VERSION 5.8 ;
BUSBITCHARS "[]" ;
DIVIDERCHAR "/" ;
UNITS
    DATABASE MICRONS 1000 ;
END UNITS

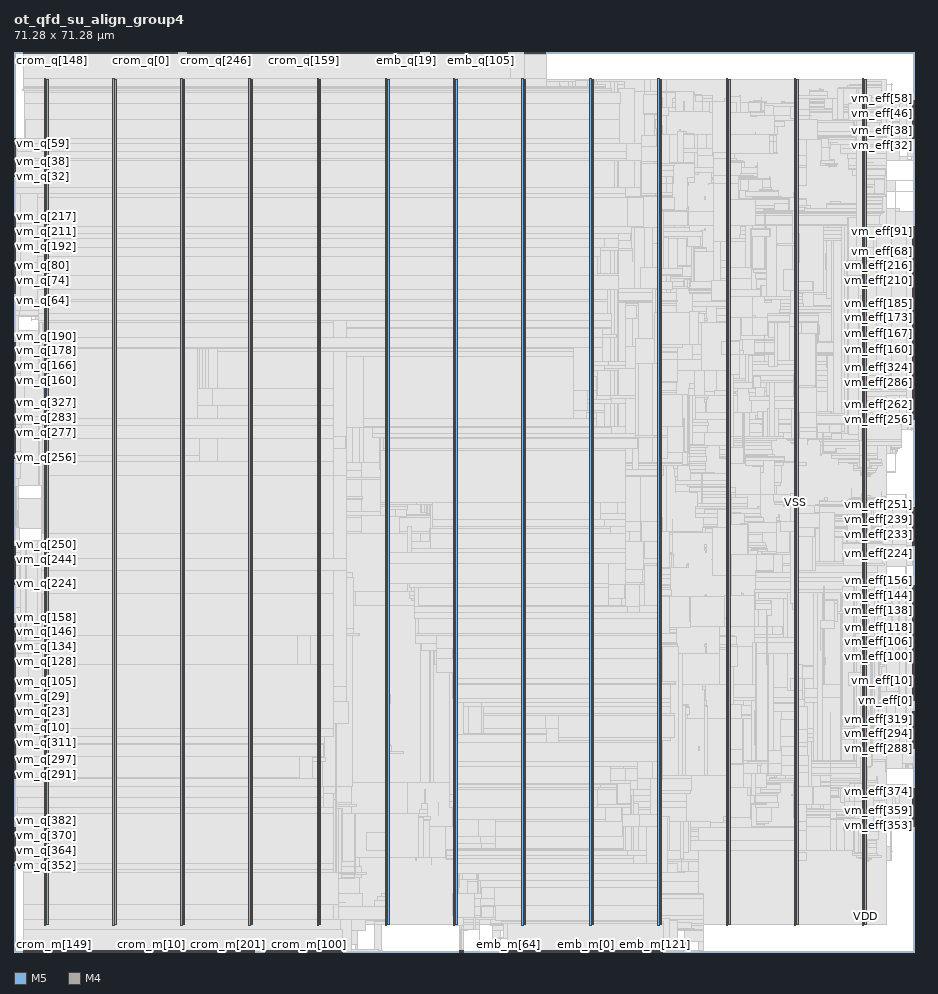
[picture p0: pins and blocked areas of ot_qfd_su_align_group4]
MACRO ot_qfd_su_align_group4
  FOREIGN ot_qfd_su_align_group4 0 0 ;
  CLASS BLOCK ;
  SIZE 71.28 BY 71.28 ;
  PIN clk
    DIRECTION INPUT ;
    USE SIGNAL ;
    PORT
      LAYER M5 ;
        RECT  9.936 71.196 9.96 71.28 ;
    END
  END clk
  PIN crom_m[0]
    DIRECTION OUTPUT ;
    USE SIGNAL ;
    PORT
      LAYER M5 ;
        RECT  9.936 0 9.96 0.084 ;
    END
  END crom_m[0]
  PIN crom_m[100]
    DIRECTION OUTPUT ;
    USE SIGNAL ;
    PORT
      LAYER M5 ;
        RECT  23.376 0 23.4 0.084 ;
    END
  END crom_m[100]
  PIN crom_m[101]
    DIRECTION OUTPUT ;
    USE SIGNAL ;
    PORT
      LAYER M5 ;
        RECT  23.472 0 23.496 0.084 ;
    END
  END crom_m[101]
  PIN crom_m[102]
    DIRECTION OUTPUT ;
    USE SIGNAL ;
    PORT
      LAYER M5 ;
        RECT  23.568 0 23.592 0.084 ;
    END
  END crom_m[102]
  PIN crom_m[103]
    DIRECTION OUTPUT ;
    USE SIGNAL ;
    PORT
      LAYER M5 ;
        RECT  23.664 0 23.688 0.084 ;
    END
  END crom_m[103]
  PIN crom_m[104]
    DIRECTION OUTPUT ;
    USE SIGNAL ;
    PORT
      LAYER M5 ;
        RECT  23.76 0 23.784 0.084 ;
    END
  END crom_m[104]
  PIN crom_m[105]
    DIRECTION OUTPUT ;
    USE SIGNAL ;
    PORT
      LAYER M5 ;
        RECT  23.856 0 23.88 0.084 ;
    END
  END crom_m[105]
  PIN crom_m[106]
    DIRECTION OUTPUT ;
    USE SIGNAL ;
    PORT
      LAYER M5 ;
        RECT  23.952 0 23.976 0.084 ;
    END
  END crom_m[106]
  PIN crom_m[107]
    DIRECTION OUTPUT ;
    USE SIGNAL ;
    PORT
      LAYER M5 ;
        RECT  24.048 0 24.072 0.084 ;
    END
  END crom_m[107]
  PIN crom_m[108]
    DIRECTION OUTPUT ;
    USE SIGNAL ;
    PORT
      LAYER M5 ;
        RECT  24.144 0 24.168 0.084 ;
    END
  END crom_m[108]
  PIN crom_m[109]
    DIRECTION OUTPUT ;
    USE SIGNAL ;
    PORT
      LAYER M5 ;
        RECT  24.24 0 24.264 0.084 ;
    END
  END crom_m[109]
  PIN crom_m[10]
    DIRECTION OUTPUT ;
    USE SIGNAL ;
    PORT
      LAYER M5 ;
        RECT  10.896 0 10.92 0.084 ;
    END
  END crom_m[10]
  PIN crom_m[110]
    DIRECTION OUTPUT ;
    USE SIGNAL ;
    PORT
      LAYER M5 ;
        RECT  24.336 0 24.36 0.084 ;
    END
  END crom_m[110]
  PIN crom_m[111]
    DIRECTION OUTPUT ;
    USE SIGNAL ;
    PORT
      LAYER M5 ;
        RECT  24.432 0 24.456 0.084 ;
    END
  END crom_m[111]
  PIN crom_m[112]
    DIRECTION OUTPUT ;
    USE SIGNAL ;
    PORT
      LAYER M5 ;
        RECT  24.528 0 24.552 0.084 ;
    END
  END crom_m[112]
  PIN crom_m[113]
    DIRECTION OUTPUT ;
    USE SIGNAL ;
    PORT
      LAYER M5 ;
        RECT  24.624 0 24.648 0.084 ;
    END
  END crom_m[113]
  PIN crom_m[114]
    DIRECTION OUTPUT ;
    USE SIGNAL ;
    PORT
      LAYER M5 ;
        RECT  24.72 0 24.744 0.084 ;
    END
  END crom_m[114]
  PIN crom_m[115]
    DIRECTION OUTPUT ;
    USE SIGNAL ;
    PORT
      LAYER M5 ;
        RECT  24.816 0 24.84 0.084 ;
    END
  END crom_m[115]
  PIN crom_m[116]
    DIRECTION OUTPUT ;
    USE SIGNAL ;
    PORT
      LAYER M5 ;
        RECT  24.912 0 24.936 0.084 ;
    END
  END crom_m[116]
  PIN crom_m[117]
    DIRECTION OUTPUT ;
    USE SIGNAL ;
    PORT
      LAYER M5 ;
        RECT  25.008 0 25.032 0.084 ;
    END
  END crom_m[117]
  PIN crom_m[118]
    DIRECTION OUTPUT ;
    USE SIGNAL ;
    PORT
      LAYER M5 ;
        RECT  25.104 0 25.128 0.084 ;
    END
  END crom_m[118]
  PIN crom_m[119]
    DIRECTION OUTPUT ;
    USE SIGNAL ;
    PORT
      LAYER M5 ;
        RECT  25.2 0 25.224 0.084 ;
    END
  END crom_m[119]
  PIN crom_m[11]
    DIRECTION OUTPUT ;
    USE SIGNAL ;
    PORT
      LAYER M5 ;
        RECT  10.992 0 11.016 0.084 ;
    END
  END crom_m[11]
  PIN crom_m[120]
    DIRECTION OUTPUT ;
    USE SIGNAL ;
    PORT
      LAYER M5 ;
        RECT  25.296 0 25.32 0.084 ;
    END
  END crom_m[120]
  PIN crom_m[121]
    DIRECTION OUTPUT ;
    USE SIGNAL ;
    PORT
      LAYER M5 ;
        RECT  25.392 0 25.416 0.084 ;
    END
  END crom_m[121]
  PIN crom_m[122]
    DIRECTION OUTPUT ;
    USE SIGNAL ;
    PORT
      LAYER M5 ;
        RECT  25.488 0 25.512 0.084 ;
    END
  END crom_m[122]
  PIN crom_m[123]
    DIRECTION OUTPUT ;
    USE SIGNAL ;
    PORT
      LAYER M5 ;
        RECT  25.584 0 25.608 0.084 ;
    END
  END crom_m[123]
  PIN crom_m[124]
    DIRECTION OUTPUT ;
    USE SIGNAL ;
    PORT
      LAYER M5 ;
        RECT  25.68 0 25.704 0.084 ;
    END
  END crom_m[124]
  PIN crom_m[125]
    DIRECTION OUTPUT ;
    USE SIGNAL ;
    PORT
      LAYER M5 ;
        RECT  25.776 0 25.8 0.084 ;
    END
  END crom_m[125]
  PIN crom_m[126]
    DIRECTION OUTPUT ;
    USE SIGNAL ;
    PORT
      LAYER M5 ;
        RECT  25.872 0 25.896 0.084 ;
    END
  END crom_m[126]
  PIN crom_m[127]
    DIRECTION OUTPUT ;
    USE SIGNAL ;
    PORT
      LAYER M5 ;
        RECT  25.968 0 25.992 0.084 ;
    END
  END crom_m[127]
  PIN crom_m[128]
    DIRECTION OUTPUT ;
    USE SIGNAL ;
    PORT
      LAYER M5 ;
        RECT  0.72 0 0.744 0.084 ;
    END
  END crom_m[128]
  PIN crom_m[129]
    DIRECTION OUTPUT ;
    USE SIGNAL ;
    PORT
      LAYER M5 ;
        RECT  0.816 0 0.84 0.084 ;
    END
  END crom_m[129]
  PIN crom_m[12]
    DIRECTION OUTPUT ;
    USE SIGNAL ;
    PORT
      LAYER M5 ;
        RECT  11.088 0 11.112 0.084 ;
    END
  END crom_m[12]
  PIN crom_m[130]
    DIRECTION OUTPUT ;
    USE SIGNAL ;
    PORT
      LAYER M5 ;
        RECT  0.912 0 0.936 0.084 ;
    END
  END crom_m[130]
  PIN crom_m[131]
    DIRECTION OUTPUT ;
    USE SIGNAL ;
    PORT
      LAYER M5 ;
        RECT  1.008 0 1.032 0.084 ;
    END
  END crom_m[131]
  PIN crom_m[132]
    DIRECTION OUTPUT ;
    USE SIGNAL ;
    PORT
      LAYER M5 ;
        RECT  1.104 0 1.128 0.084 ;
    END
  END crom_m[132]
  PIN crom_m[133]
    DIRECTION OUTPUT ;
    USE SIGNAL ;
    PORT
      LAYER M5 ;
        RECT  1.2 0 1.224 0.084 ;
    END
  END crom_m[133]
  PIN crom_m[134]
    DIRECTION OUTPUT ;
    USE SIGNAL ;
    PORT
      LAYER M5 ;
        RECT  1.296 0 1.32 0.084 ;
    END
  END crom_m[134]
  PIN crom_m[135]
    DIRECTION OUTPUT ;
    USE SIGNAL ;
    PORT
      LAYER M5 ;
        RECT  1.392 0 1.416 0.084 ;
    END
  END crom_m[135]
  PIN crom_m[136]
    DIRECTION OUTPUT ;
    USE SIGNAL ;
    PORT
      LAYER M5 ;
        RECT  1.488 0 1.512 0.084 ;
    END
  END crom_m[136]
  PIN crom_m[137]
    DIRECTION OUTPUT ;
    USE SIGNAL ;
    PORT
      LAYER M5 ;
        RECT  1.584 0 1.608 0.084 ;
    END
  END crom_m[137]
  PIN crom_m[138]
    DIRECTION OUTPUT ;
    USE SIGNAL ;
    PORT
      LAYER M5 ;
        RECT  1.68 0 1.704 0.084 ;
    END
  END crom_m[138]
  PIN crom_m[139]
    DIRECTION OUTPUT ;
    USE SIGNAL ;
    PORT
      LAYER M5 ;
        RECT  1.776 0 1.8 0.084 ;
    END
  END crom_m[139]
  PIN crom_m[13]
    DIRECTION OUTPUT ;
    USE SIGNAL ;
    PORT
      LAYER M5 ;
        RECT  11.184 0 11.208 0.084 ;
    END
  END crom_m[13]
  PIN crom_m[140]
    DIRECTION OUTPUT ;
    USE SIGNAL ;
    PORT
      LAYER M5 ;
        RECT  1.872 0 1.896 0.084 ;
    END
  END crom_m[140]
  PIN crom_m[141]
    DIRECTION OUTPUT ;
    USE SIGNAL ;
    PORT
      LAYER M5 ;
        RECT  1.968 0 1.992 0.084 ;
    END
  END crom_m[141]
  PIN crom_m[142]
    DIRECTION OUTPUT ;
    USE SIGNAL ;
    PORT
      LAYER M5 ;
        RECT  2.064 0 2.088 0.084 ;
    END
  END crom_m[142]
  PIN crom_m[143]
    DIRECTION OUTPUT ;
    USE SIGNAL ;
    PORT
      LAYER M5 ;
        RECT  2.16 0 2.184 0.084 ;
    END
  END crom_m[143]
  PIN crom_m[144]
    DIRECTION OUTPUT ;
    USE SIGNAL ;
    PORT
      LAYER M5 ;
        RECT  2.256 0 2.28 0.084 ;
    END
  END crom_m[144]
  PIN crom_m[145]
    DIRECTION OUTPUT ;
    USE SIGNAL ;
    PORT
      LAYER M5 ;
        RECT  2.352 0 2.376 0.084 ;
    END
  END crom_m[145]
  PIN crom_m[146]
    DIRECTION OUTPUT ;
    USE SIGNAL ;
    PORT
      LAYER M5 ;
        RECT  2.448 0 2.472 0.084 ;
    END
  END crom_m[146]
  PIN crom_m[147]
    DIRECTION OUTPUT ;
    USE SIGNAL ;
    PORT
      LAYER M5 ;
        RECT  2.544 0 2.568 0.084 ;
    END
  END crom_m[147]
  PIN crom_m[148]
    DIRECTION OUTPUT ;
    USE SIGNAL ;
    PORT
      LAYER M5 ;
        RECT  2.64 0 2.664 0.084 ;
    END
  END crom_m[148]
  PIN crom_m[149]
    DIRECTION OUTPUT ;
    USE SIGNAL ;
    PORT
      LAYER M5 ;
        RECT  2.736 0 2.76 0.084 ;
    END
  END crom_m[149]
  PIN crom_m[14]
    DIRECTION OUTPUT ;
    USE SIGNAL ;
    PORT
      LAYER M5 ;
        RECT  11.28 0 11.304 0.084 ;
    END
  END crom_m[14]
  PIN crom_m[150]
    DIRECTION OUTPUT ;
    USE SIGNAL ;
    PORT
      LAYER M5 ;
        RECT  2.832 0 2.856 0.084 ;
    END
  END crom_m[150]
  PIN crom_m[151]
    DIRECTION OUTPUT ;
    USE SIGNAL ;
    PORT
      LAYER M5 ;
        RECT  2.928 0 2.952 0.084 ;
    END
  END crom_m[151]
  PIN crom_m[152]
    DIRECTION OUTPUT ;
    USE SIGNAL ;
    PORT
      LAYER M5 ;
        RECT  3.024 0 3.048 0.084 ;
    END
  END crom_m[152]
  PIN crom_m[153]
    DIRECTION OUTPUT ;
    USE SIGNAL ;
    PORT
      LAYER M5 ;
        RECT  3.12 0 3.144 0.084 ;
    END
  END crom_m[153]
  PIN crom_m[154]
    DIRECTION OUTPUT ;
    USE SIGNAL ;
    PORT
      LAYER M5 ;
        RECT  3.216 0 3.24 0.084 ;
    END
  END crom_m[154]
  PIN crom_m[155]
    DIRECTION OUTPUT ;
    USE SIGNAL ;
    PORT
      LAYER M5 ;
        RECT  3.312 0 3.336 0.084 ;
    END
  END crom_m[155]
  PIN crom_m[156]
    DIRECTION OUTPUT ;
    USE SIGNAL ;
    PORT
      LAYER M5 ;
        RECT  3.408 0 3.432 0.084 ;
    END
  END crom_m[156]
  PIN crom_m[157]
    DIRECTION OUTPUT ;
    USE SIGNAL ;
    PORT
      LAYER M5 ;
        RECT  3.504 0 3.528 0.084 ;
    END
  END crom_m[157]
  PIN crom_m[158]
    DIRECTION OUTPUT ;
    USE SIGNAL ;
    PORT
      LAYER M5 ;
        RECT  3.6 0 3.624 0.084 ;
    END
  END crom_m[158]
  PIN crom_m[159]
    DIRECTION OUTPUT ;
    USE SIGNAL ;
    PORT
      LAYER M5 ;
        RECT  3.696 0 3.72 0.084 ;
    END
  END crom_m[159]
  PIN crom_m[15]
    DIRECTION OUTPUT ;
    USE SIGNAL ;
    PORT
      LAYER M5 ;
        RECT  11.376 0 11.4 0.084 ;
    END
  END crom_m[15]
  PIN crom_m[160]
    DIRECTION OUTPUT ;
    USE SIGNAL ;
    PORT
      LAYER M5 ;
        RECT  6.864 0 6.888 0.084 ;
    END
  END crom_m[160]
  PIN crom_m[161]
    DIRECTION OUTPUT ;
    USE SIGNAL ;
    PORT
      LAYER M5 ;
        RECT  6.96 0 6.984 0.084 ;
    END
  END crom_m[161]
  PIN crom_m[162]
    DIRECTION OUTPUT ;
    USE SIGNAL ;
    PORT
      LAYER M5 ;
        RECT  7.056 0 7.08 0.084 ;
    END
  END crom_m[162]
  PIN crom_m[163]
    DIRECTION OUTPUT ;
    USE SIGNAL ;
    PORT
      LAYER M5 ;
        RECT  7.152 0 7.176 0.084 ;
    END
  END crom_m[163]
  PIN crom_m[164]
    DIRECTION OUTPUT ;
    USE SIGNAL ;
    PORT
      LAYER M5 ;
        RECT  7.248 0 7.272 0.084 ;
    END
  END crom_m[164]
  PIN crom_m[165]
    DIRECTION OUTPUT ;
    USE SIGNAL ;
    PORT
      LAYER M5 ;
        RECT  7.344 0 7.368 0.084 ;
    END
  END crom_m[165]
  PIN crom_m[166]
    DIRECTION OUTPUT ;
    USE SIGNAL ;
    PORT
      LAYER M5 ;
        RECT  7.44 0 7.464 0.084 ;
    END
  END crom_m[166]
  PIN crom_m[167]
    DIRECTION OUTPUT ;
    USE SIGNAL ;
    PORT
      LAYER M5 ;
        RECT  7.536 0 7.56 0.084 ;
    END
  END crom_m[167]
  PIN crom_m[168]
    DIRECTION OUTPUT ;
    USE SIGNAL ;
    PORT
      LAYER M5 ;
        RECT  7.632 0 7.656 0.084 ;
    END
  END crom_m[168]
  PIN crom_m[169]
    DIRECTION OUTPUT ;
    USE SIGNAL ;
    PORT
      LAYER M5 ;
        RECT  7.728 0 7.752 0.084 ;
    END
  END crom_m[169]
  PIN crom_m[16]
    DIRECTION OUTPUT ;
    USE SIGNAL ;
    PORT
      LAYER M5 ;
        RECT  11.472 0 11.496 0.084 ;
    END
  END crom_m[16]
  PIN crom_m[170]
    DIRECTION OUTPUT ;
    USE SIGNAL ;
    PORT
      LAYER M5 ;
        RECT  7.824 0 7.848 0.084 ;
    END
  END crom_m[170]
  PIN crom_m[171]
    DIRECTION OUTPUT ;
    USE SIGNAL ;
    PORT
      LAYER M5 ;
        RECT  7.92 0 7.944 0.084 ;
    END
  END crom_m[171]
  PIN crom_m[172]
    DIRECTION OUTPUT ;
    USE SIGNAL ;
    PORT
      LAYER M5 ;
        RECT  8.016 0 8.04 0.084 ;
    END
  END crom_m[172]
  PIN crom_m[173]
    DIRECTION OUTPUT ;
    USE SIGNAL ;
    PORT
      LAYER M5 ;
        RECT  8.112 0 8.136 0.084 ;
    END
  END crom_m[173]
  PIN crom_m[174]
    DIRECTION OUTPUT ;
    USE SIGNAL ;
    PORT
      LAYER M5 ;
        RECT  8.208 0 8.232 0.084 ;
    END
  END crom_m[174]
  PIN crom_m[175]
    DIRECTION OUTPUT ;
    USE SIGNAL ;
    PORT
      LAYER M5 ;
        RECT  8.304 0 8.328 0.084 ;
    END
  END crom_m[175]
  PIN crom_m[176]
    DIRECTION OUTPUT ;
    USE SIGNAL ;
    PORT
      LAYER M5 ;
        RECT  8.4 0 8.424 0.084 ;
    END
  END crom_m[176]
  PIN crom_m[177]
    DIRECTION OUTPUT ;
    USE SIGNAL ;
    PORT
      LAYER M5 ;
        RECT  8.496 0 8.52 0.084 ;
    END
  END crom_m[177]
  PIN crom_m[178]
    DIRECTION OUTPUT ;
    USE SIGNAL ;
    PORT
      LAYER M5 ;
        RECT  8.592 0 8.616 0.084 ;
    END
  END crom_m[178]
  PIN crom_m[179]
    DIRECTION OUTPUT ;
    USE SIGNAL ;
    PORT
      LAYER M5 ;
        RECT  8.688 0 8.712 0.084 ;
    END
  END crom_m[179]
  PIN crom_m[17]
    DIRECTION OUTPUT ;
    USE SIGNAL ;
    PORT
      LAYER M5 ;
        RECT  11.568 0 11.592 0.084 ;
    END
  END crom_m[17]
  PIN crom_m[180]
    DIRECTION OUTPUT ;
    USE SIGNAL ;
    PORT
      LAYER M5 ;
        RECT  8.784 0 8.808 0.084 ;
    END
  END crom_m[180]
  PIN crom_m[181]
    DIRECTION OUTPUT ;
    USE SIGNAL ;
    PORT
      LAYER M5 ;
        RECT  8.88 0 8.904 0.084 ;
    END
  END crom_m[181]
  PIN crom_m[182]
    DIRECTION OUTPUT ;
    USE SIGNAL ;
    PORT
      LAYER M5 ;
        RECT  8.976 0 9 0.084 ;
    END
  END crom_m[182]
  PIN crom_m[183]
    DIRECTION OUTPUT ;
    USE SIGNAL ;
    PORT
      LAYER M5 ;
        RECT  9.072 0 9.096 0.084 ;
    END
  END crom_m[183]
  PIN crom_m[184]
    DIRECTION OUTPUT ;
    USE SIGNAL ;
    PORT
      LAYER M5 ;
        RECT  9.168 0 9.192 0.084 ;
    END
  END crom_m[184]
  PIN crom_m[185]
    DIRECTION OUTPUT ;
    USE SIGNAL ;
    PORT
      LAYER M5 ;
        RECT  9.264 0 9.288 0.084 ;
    END
  END crom_m[185]
  PIN crom_m[186]
    DIRECTION OUTPUT ;
    USE SIGNAL ;
    PORT
      LAYER M5 ;
        RECT  9.36 0 9.384 0.084 ;
    END
  END crom_m[186]
  PIN crom_m[187]
    DIRECTION OUTPUT ;
    USE SIGNAL ;
    PORT
      LAYER M5 ;
        RECT  9.456 0 9.48 0.084 ;
    END
  END crom_m[187]
  PIN crom_m[188]
    DIRECTION OUTPUT ;
    USE SIGNAL ;
    PORT
      LAYER M5 ;
        RECT  9.552 0 9.576 0.084 ;
    END
  END crom_m[188]
  PIN crom_m[189]
    DIRECTION OUTPUT ;
    USE SIGNAL ;
    PORT
      LAYER M5 ;
        RECT  9.648 0 9.672 0.084 ;
    END
  END crom_m[189]
  PIN crom_m[18]
    DIRECTION OUTPUT ;
    USE SIGNAL ;
    PORT
      LAYER M5 ;
        RECT  11.664 0 11.688 0.084 ;
    END
  END crom_m[18]
  PIN crom_m[190]
    DIRECTION OUTPUT ;
    USE SIGNAL ;
    PORT
      LAYER M5 ;
        RECT  9.744 0 9.768 0.084 ;
    END
  END crom_m[190]
  PIN crom_m[191]
    DIRECTION OUTPUT ;
    USE SIGNAL ;
    PORT
      LAYER M5 ;
        RECT  9.84 0 9.864 0.084 ;
    END
  END crom_m[191]
  PIN crom_m[192]
    DIRECTION OUTPUT ;
    USE SIGNAL ;
    PORT
      LAYER M5 ;
        RECT  16.08 0 16.104 0.084 ;
    END
  END crom_m[192]
  PIN crom_m[193]
    DIRECTION OUTPUT ;
    USE SIGNAL ;
    PORT
      LAYER M5 ;
        RECT  16.176 0 16.2 0.084 ;
    END
  END crom_m[193]
  PIN crom_m[194]
    DIRECTION OUTPUT ;
    USE SIGNAL ;
    PORT
      LAYER M5 ;
        RECT  16.272 0 16.296 0.084 ;
    END
  END crom_m[194]
  PIN crom_m[195]
    DIRECTION OUTPUT ;
    USE SIGNAL ;
    PORT
      LAYER M5 ;
        RECT  16.368 0 16.392 0.084 ;
    END
  END crom_m[195]
  PIN crom_m[196]
    DIRECTION OUTPUT ;
    USE SIGNAL ;
    PORT
      LAYER M5 ;
        RECT  16.464 0 16.488 0.084 ;
    END
  END crom_m[196]
  PIN crom_m[197]
    DIRECTION OUTPUT ;
    USE SIGNAL ;
    PORT
      LAYER M5 ;
        RECT  16.56 0 16.584 0.084 ;
    END
  END crom_m[197]
  PIN crom_m[198]
    DIRECTION OUTPUT ;
    USE SIGNAL ;
    PORT
      LAYER M5 ;
        RECT  16.656 0 16.68 0.084 ;
    END
  END crom_m[198]
  PIN crom_m[199]
    DIRECTION OUTPUT ;
    USE SIGNAL ;
    PORT
      LAYER M5 ;
        RECT  16.752 0 16.776 0.084 ;
    END
  END crom_m[199]
  PIN crom_m[19]
    DIRECTION OUTPUT ;
    USE SIGNAL ;
    PORT
      LAYER M5 ;
        RECT  11.76 0 11.784 0.084 ;
    END
  END crom_m[19]
  PIN crom_m[1]
    DIRECTION OUTPUT ;
    USE SIGNAL ;
    PORT
      LAYER M5 ;
        RECT  10.032 0 10.056 0.084 ;
    END
  END crom_m[1]
  PIN crom_m[200]
    DIRECTION OUTPUT ;
    USE SIGNAL ;
    PORT
      LAYER M5 ;
        RECT  16.848 0 16.872 0.084 ;
    END
  END crom_m[200]
  PIN crom_m[201]
    DIRECTION OUTPUT ;
    USE SIGNAL ;
    PORT
      LAYER M5 ;
        RECT  16.944 0 16.968 0.084 ;
    END
  END crom_m[201]
  PIN crom_m[202]
    DIRECTION OUTPUT ;
    USE SIGNAL ;
    PORT
      LAYER M5 ;
        RECT  17.04 0 17.064 0.084 ;
    END
  END crom_m[202]
  PIN crom_m[203]
    DIRECTION OUTPUT ;
    USE SIGNAL ;
    PORT
      LAYER M5 ;
        RECT  17.136 0 17.16 0.084 ;
    END
  END crom_m[203]
  PIN crom_m[204]
    DIRECTION OUTPUT ;
    USE SIGNAL ;
    PORT
      LAYER M5 ;
        RECT  17.232 0 17.256 0.084 ;
    END
  END crom_m[204]
  PIN crom_m[205]
    DIRECTION OUTPUT ;
    USE SIGNAL ;
    PORT
      LAYER M5 ;
        RECT  17.328 0 17.352 0.084 ;
    END
  END crom_m[205]
  PIN crom_m[206]
    DIRECTION OUTPUT ;
    USE SIGNAL ;
    PORT
      LAYER M5 ;
        RECT  17.424 0 17.448 0.084 ;
    END
  END crom_m[206]
  PIN crom_m[207]
    DIRECTION OUTPUT ;
    USE SIGNAL ;
    PORT
      LAYER M5 ;
        RECT  17.52 0 17.544 0.084 ;
    END
  END crom_m[207]
  PIN crom_m[208]
    DIRECTION OUTPUT ;
    USE SIGNAL ;
    PORT
      LAYER M5 ;
        RECT  17.616 0 17.64 0.084 ;
    END
  END crom_m[208]
  PIN crom_m[209]
    DIRECTION OUTPUT ;
    USE SIGNAL ;
    PORT
      LAYER M5 ;
        RECT  17.712 0 17.736 0.084 ;
    END
  END crom_m[209]
  PIN crom_m[20]
    DIRECTION OUTPUT ;
    USE SIGNAL ;
    PORT
      LAYER M5 ;
        RECT  11.856 0 11.88 0.084 ;
    END
  END crom_m[20]
  PIN crom_m[210]
    DIRECTION OUTPUT ;
    USE SIGNAL ;
    PORT
      LAYER M5 ;
        RECT  17.808 0 17.832 0.084 ;
    END
  END crom_m[210]
  PIN crom_m[211]
    DIRECTION OUTPUT ;
    USE SIGNAL ;
    PORT
      LAYER M5 ;
        RECT  17.904 0 17.928 0.084 ;
    END
  END crom_m[211]
  PIN crom_m[212]
    DIRECTION OUTPUT ;
    USE SIGNAL ;
    PORT
      LAYER M5 ;
        RECT  18 0 18.024 0.084 ;
    END
  END crom_m[212]
  PIN crom_m[213]
    DIRECTION OUTPUT ;
    USE SIGNAL ;
    PORT
      LAYER M5 ;
        RECT  18.096 0 18.12 0.084 ;
    END
  END crom_m[213]
  PIN crom_m[214]
    DIRECTION OUTPUT ;
    USE SIGNAL ;
    PORT
      LAYER M5 ;
        RECT  18.192 0 18.216 0.084 ;
    END
  END crom_m[214]
  PIN crom_m[215]
    DIRECTION OUTPUT ;
    USE SIGNAL ;
    PORT
      LAYER M5 ;
        RECT  18.288 0 18.312 0.084 ;
    END
  END crom_m[215]
  PIN crom_m[216]
    DIRECTION OUTPUT ;
    USE SIGNAL ;
    PORT
      LAYER M5 ;
        RECT  18.384 0 18.408 0.084 ;
    END
  END crom_m[216]
  PIN crom_m[217]
    DIRECTION OUTPUT ;
    USE SIGNAL ;
    PORT
      LAYER M5 ;
        RECT  18.48 0 18.504 0.084 ;
    END
  END crom_m[217]
  PIN crom_m[218]
    DIRECTION OUTPUT ;
    USE SIGNAL ;
    PORT
      LAYER M5 ;
        RECT  18.576 0 18.6 0.084 ;
    END
  END crom_m[218]
  PIN crom_m[219]
    DIRECTION OUTPUT ;
    USE SIGNAL ;
    PORT
      LAYER M5 ;
        RECT  18.672 0 18.696 0.084 ;
    END
  END crom_m[219]
  PIN crom_m[21]
    DIRECTION OUTPUT ;
    USE SIGNAL ;
    PORT
      LAYER M5 ;
        RECT  11.952 0 11.976 0.084 ;
    END
  END crom_m[21]
  PIN crom_m[220]
    DIRECTION OUTPUT ;
    USE SIGNAL ;
    PORT
      LAYER M5 ;
        RECT  18.768 0 18.792 0.084 ;
    END
  END crom_m[220]
  PIN crom_m[221]
    DIRECTION OUTPUT ;
    USE SIGNAL ;
    PORT
      LAYER M5 ;
        RECT  18.864 0 18.888 0.084 ;
    END
  END crom_m[221]
  PIN crom_m[222]
    DIRECTION OUTPUT ;
    USE SIGNAL ;
    PORT
      LAYER M5 ;
        RECT  18.96 0 18.984 0.084 ;
    END
  END crom_m[222]
  PIN crom_m[223]
    DIRECTION OUTPUT ;
    USE SIGNAL ;
    PORT
      LAYER M5 ;
        RECT  19.056 0 19.08 0.084 ;
    END
  END crom_m[223]
  PIN crom_m[224]
    DIRECTION OUTPUT ;
    USE SIGNAL ;
    PORT
      LAYER M5 ;
        RECT  19.92 0 19.944 0.084 ;
    END
  END crom_m[224]
  PIN crom_m[225]
    DIRECTION OUTPUT ;
    USE SIGNAL ;
    PORT
      LAYER M5 ;
        RECT  20.016 0 20.04 0.084 ;
    END
  END crom_m[225]
  PIN crom_m[226]
    DIRECTION OUTPUT ;
    USE SIGNAL ;
    PORT
      LAYER M5 ;
        RECT  20.112 0 20.136 0.084 ;
    END
  END crom_m[226]
  PIN crom_m[227]
    DIRECTION OUTPUT ;
    USE SIGNAL ;
    PORT
      LAYER M5 ;
        RECT  20.208 0 20.232 0.084 ;
    END
  END crom_m[227]
  PIN crom_m[228]
    DIRECTION OUTPUT ;
    USE SIGNAL ;
    PORT
      LAYER M5 ;
        RECT  20.304 0 20.328 0.084 ;
    END
  END crom_m[228]
  PIN crom_m[229]
    DIRECTION OUTPUT ;
    USE SIGNAL ;
    PORT
      LAYER M5 ;
        RECT  20.4 0 20.424 0.084 ;
    END
  END crom_m[229]
  PIN crom_m[22]
    DIRECTION OUTPUT ;
    USE SIGNAL ;
    PORT
      LAYER M5 ;
        RECT  12.048 0 12.072 0.084 ;
    END
  END crom_m[22]
  PIN crom_m[230]
    DIRECTION OUTPUT ;
    USE SIGNAL ;
    PORT
      LAYER M5 ;
        RECT  20.496 0 20.52 0.084 ;
    END
  END crom_m[230]
  PIN crom_m[231]
    DIRECTION OUTPUT ;
    USE SIGNAL ;
    PORT
      LAYER M5 ;
        RECT  20.592 0 20.616 0.084 ;
    END
  END crom_m[231]
  PIN crom_m[232]
    DIRECTION OUTPUT ;
    USE SIGNAL ;
    PORT
      LAYER M5 ;
        RECT  20.688 0 20.712 0.084 ;
    END
  END crom_m[232]
  PIN crom_m[233]
    DIRECTION OUTPUT ;
    USE SIGNAL ;
    PORT
      LAYER M5 ;
        RECT  20.784 0 20.808 0.084 ;
    END
  END crom_m[233]
  PIN crom_m[234]
    DIRECTION OUTPUT ;
    USE SIGNAL ;
    PORT
      LAYER M5 ;
        RECT  20.88 0 20.904 0.084 ;
    END
  END crom_m[234]
  PIN crom_m[235]
    DIRECTION OUTPUT ;
    USE SIGNAL ;
    PORT
      LAYER M5 ;
        RECT  20.976 0 21 0.084 ;
    END
  END crom_m[235]
  PIN crom_m[236]
    DIRECTION OUTPUT ;
    USE SIGNAL ;
    PORT
      LAYER M5 ;
        RECT  21.072 0 21.096 0.084 ;
    END
  END crom_m[236]
  PIN crom_m[237]
    DIRECTION OUTPUT ;
    USE SIGNAL ;
    PORT
      LAYER M5 ;
        RECT  21.168 0 21.192 0.084 ;
    END
  END crom_m[237]
  PIN crom_m[238]
    DIRECTION OUTPUT ;
    USE SIGNAL ;
    PORT
      LAYER M5 ;
        RECT  21.264 0 21.288 0.084 ;
    END
  END crom_m[238]
  PIN crom_m[239]
    DIRECTION OUTPUT ;
    USE SIGNAL ;
    PORT
      LAYER M5 ;
        RECT  21.36 0 21.384 0.084 ;
    END
  END crom_m[239]
  PIN crom_m[23]
    DIRECTION OUTPUT ;
    USE SIGNAL ;
    PORT
      LAYER M5 ;
        RECT  12.144 0 12.168 0.084 ;
    END
  END crom_m[23]
  PIN crom_m[240]
    DIRECTION OUTPUT ;
    USE SIGNAL ;
    PORT
      LAYER M5 ;
        RECT  21.456 0 21.48 0.084 ;
    END
  END crom_m[240]
  PIN crom_m[241]
    DIRECTION OUTPUT ;
    USE SIGNAL ;
    PORT
      LAYER M5 ;
        RECT  21.552 0 21.576 0.084 ;
    END
  END crom_m[241]
  PIN crom_m[242]
    DIRECTION OUTPUT ;
    USE SIGNAL ;
    PORT
      LAYER M5 ;
        RECT  21.648 0 21.672 0.084 ;
    END
  END crom_m[242]
  PIN crom_m[243]
    DIRECTION OUTPUT ;
    USE SIGNAL ;
    PORT
      LAYER M5 ;
        RECT  21.744 0 21.768 0.084 ;
    END
  END crom_m[243]
  PIN crom_m[244]
    DIRECTION OUTPUT ;
    USE SIGNAL ;
    PORT
      LAYER M5 ;
        RECT  21.84 0 21.864 0.084 ;
    END
  END crom_m[244]
  PIN crom_m[245]
    DIRECTION OUTPUT ;
    USE SIGNAL ;
    PORT
      LAYER M5 ;
        RECT  21.936 0 21.96 0.084 ;
    END
  END crom_m[245]
  PIN crom_m[246]
    DIRECTION OUTPUT ;
    USE SIGNAL ;
    PORT
      LAYER M5 ;
        RECT  22.032 0 22.056 0.084 ;
    END
  END crom_m[246]
  PIN crom_m[247]
    DIRECTION OUTPUT ;
    USE SIGNAL ;
    PORT
      LAYER M5 ;
        RECT  22.128 0 22.152 0.084 ;
    END
  END crom_m[247]
  PIN crom_m[248]
    DIRECTION OUTPUT ;
    USE SIGNAL ;
    PORT
      LAYER M5 ;
        RECT  22.224 0 22.248 0.084 ;
    END
  END crom_m[248]
  PIN crom_m[249]
    DIRECTION OUTPUT ;
    USE SIGNAL ;
    PORT
      LAYER M5 ;
        RECT  22.32 0 22.344 0.084 ;
    END
  END crom_m[249]
  PIN crom_m[24]
    DIRECTION OUTPUT ;
    USE SIGNAL ;
    PORT
      LAYER M5 ;
        RECT  12.24 0 12.264 0.084 ;
    END
  END crom_m[24]
  PIN crom_m[250]
    DIRECTION OUTPUT ;
    USE SIGNAL ;
    PORT
      LAYER M5 ;
        RECT  22.416 0 22.44 0.084 ;
    END
  END crom_m[250]
  PIN crom_m[251]
    DIRECTION OUTPUT ;
    USE SIGNAL ;
    PORT
      LAYER M5 ;
        RECT  22.512 0 22.536 0.084 ;
    END
  END crom_m[251]
  PIN crom_m[252]
    DIRECTION OUTPUT ;
    USE SIGNAL ;
    PORT
      LAYER M5 ;
        RECT  22.608 0 22.632 0.084 ;
    END
  END crom_m[252]
  PIN crom_m[253]
    DIRECTION OUTPUT ;
    USE SIGNAL ;
    PORT
      LAYER M5 ;
        RECT  22.704 0 22.728 0.084 ;
    END
  END crom_m[253]
  PIN crom_m[254]
    DIRECTION OUTPUT ;
    USE SIGNAL ;
    PORT
      LAYER M5 ;
        RECT  22.8 0 22.824 0.084 ;
    END
  END crom_m[254]
  PIN crom_m[255]
    DIRECTION OUTPUT ;
    USE SIGNAL ;
    PORT
      LAYER M5 ;
        RECT  22.896 0 22.92 0.084 ;
    END
  END crom_m[255]
  PIN crom_m[25]
    DIRECTION OUTPUT ;
    USE SIGNAL ;
    PORT
      LAYER M5 ;
        RECT  12.336 0 12.36 0.084 ;
    END
  END crom_m[25]
  PIN crom_m[26]
    DIRECTION OUTPUT ;
    USE SIGNAL ;
    PORT
      LAYER M5 ;
        RECT  12.432 0 12.456 0.084 ;
    END
  END crom_m[26]
  PIN crom_m[27]
    DIRECTION OUTPUT ;
    USE SIGNAL ;
    PORT
      LAYER M5 ;
        RECT  12.528 0 12.552 0.084 ;
    END
  END crom_m[27]
  PIN crom_m[28]
    DIRECTION OUTPUT ;
    USE SIGNAL ;
    PORT
      LAYER M5 ;
        RECT  12.624 0 12.648 0.084 ;
    END
  END crom_m[28]
  PIN crom_m[29]
    DIRECTION OUTPUT ;
    USE SIGNAL ;
    PORT
      LAYER M5 ;
        RECT  12.72 0 12.744 0.084 ;
    END
  END crom_m[29]
  PIN crom_m[2]
    DIRECTION OUTPUT ;
    USE SIGNAL ;
    PORT
      LAYER M5 ;
        RECT  10.128 0 10.152 0.084 ;
    END
  END crom_m[2]
  PIN crom_m[30]
    DIRECTION OUTPUT ;
    USE SIGNAL ;
    PORT
      LAYER M5 ;
        RECT  12.816 0 12.84 0.084 ;
    END
  END crom_m[30]
  PIN crom_m[31]
    DIRECTION OUTPUT ;
    USE SIGNAL ;
    PORT
      LAYER M5 ;
        RECT  12.912 0 12.936 0.084 ;
    END
  END crom_m[31]
  PIN crom_m[32]
    DIRECTION OUTPUT ;
    USE SIGNAL ;
    PORT
      LAYER M5 ;
        RECT  3.792 0 3.816 0.084 ;
    END
  END crom_m[32]
  PIN crom_m[33]
    DIRECTION OUTPUT ;
    USE SIGNAL ;
    PORT
      LAYER M5 ;
        RECT  3.888 0 3.912 0.084 ;
    END
  END crom_m[33]
  PIN crom_m[34]
    DIRECTION OUTPUT ;
    USE SIGNAL ;
    PORT
      LAYER M5 ;
        RECT  3.984 0 4.008 0.084 ;
    END
  END crom_m[34]
  PIN crom_m[35]
    DIRECTION OUTPUT ;
    USE SIGNAL ;
    PORT
      LAYER M5 ;
        RECT  4.08 0 4.104 0.084 ;
    END
  END crom_m[35]
  PIN crom_m[36]
    DIRECTION OUTPUT ;
    USE SIGNAL ;
    PORT
      LAYER M5 ;
        RECT  4.176 0 4.2 0.084 ;
    END
  END crom_m[36]
  PIN crom_m[37]
    DIRECTION OUTPUT ;
    USE SIGNAL ;
    PORT
      LAYER M5 ;
        RECT  4.272 0 4.296 0.084 ;
    END
  END crom_m[37]
  PIN crom_m[38]
    DIRECTION OUTPUT ;
    USE SIGNAL ;
    PORT
      LAYER M5 ;
        RECT  4.368 0 4.392 0.084 ;
    END
  END crom_m[38]
  PIN crom_m[39]
    DIRECTION OUTPUT ;
    USE SIGNAL ;
    PORT
      LAYER M5 ;
        RECT  4.464 0 4.488 0.084 ;
    END
  END crom_m[39]
  PIN crom_m[3]
    DIRECTION OUTPUT ;
    USE SIGNAL ;
    PORT
      LAYER M5 ;
        RECT  10.224 0 10.248 0.084 ;
    END
  END crom_m[3]
  PIN crom_m[40]
    DIRECTION OUTPUT ;
    USE SIGNAL ;
    PORT
      LAYER M5 ;
        RECT  4.56 0 4.584 0.084 ;
    END
  END crom_m[40]
  PIN crom_m[41]
    DIRECTION OUTPUT ;
    USE SIGNAL ;
    PORT
      LAYER M5 ;
        RECT  4.656 0 4.68 0.084 ;
    END
  END crom_m[41]
  PIN crom_m[42]
    DIRECTION OUTPUT ;
    USE SIGNAL ;
    PORT
      LAYER M5 ;
        RECT  4.752 0 4.776 0.084 ;
    END
  END crom_m[42]
  PIN crom_m[43]
    DIRECTION OUTPUT ;
    USE SIGNAL ;
    PORT
      LAYER M5 ;
        RECT  4.848 0 4.872 0.084 ;
    END
  END crom_m[43]
  PIN crom_m[44]
    DIRECTION OUTPUT ;
    USE SIGNAL ;
    PORT
      LAYER M5 ;
        RECT  4.944 0 4.968 0.084 ;
    END
  END crom_m[44]
  PIN crom_m[45]
    DIRECTION OUTPUT ;
    USE SIGNAL ;
    PORT
      LAYER M5 ;
        RECT  5.04 0 5.064 0.084 ;
    END
  END crom_m[45]
  PIN crom_m[46]
    DIRECTION OUTPUT ;
    USE SIGNAL ;
    PORT
      LAYER M5 ;
        RECT  5.136 0 5.16 0.084 ;
    END
  END crom_m[46]
  PIN crom_m[47]
    DIRECTION OUTPUT ;
    USE SIGNAL ;
    PORT
      LAYER M5 ;
        RECT  5.232 0 5.256 0.084 ;
    END
  END crom_m[47]
  PIN crom_m[48]
    DIRECTION OUTPUT ;
    USE SIGNAL ;
    PORT
      LAYER M5 ;
        RECT  5.328 0 5.352 0.084 ;
    END
  END crom_m[48]
  PIN crom_m[49]
    DIRECTION OUTPUT ;
    USE SIGNAL ;
    PORT
      LAYER M5 ;
        RECT  5.424 0 5.448 0.084 ;
    END
  END crom_m[49]
  PIN crom_m[4]
    DIRECTION OUTPUT ;
    USE SIGNAL ;
    PORT
      LAYER M5 ;
        RECT  10.32 0 10.344 0.084 ;
    END
  END crom_m[4]
  PIN crom_m[50]
    DIRECTION OUTPUT ;
    USE SIGNAL ;
    PORT
      LAYER M5 ;
        RECT  5.52 0 5.544 0.084 ;
    END
  END crom_m[50]
  PIN crom_m[51]
    DIRECTION OUTPUT ;
    USE SIGNAL ;
    PORT
      LAYER M5 ;
        RECT  5.616 0 5.64 0.084 ;
    END
  END crom_m[51]
  PIN crom_m[52]
    DIRECTION OUTPUT ;
    USE SIGNAL ;
    PORT
      LAYER M5 ;
        RECT  5.712 0 5.736 0.084 ;
    END
  END crom_m[52]
  PIN crom_m[53]
    DIRECTION OUTPUT ;
    USE SIGNAL ;
    PORT
      LAYER M5 ;
        RECT  5.808 0 5.832 0.084 ;
    END
  END crom_m[53]
  PIN crom_m[54]
    DIRECTION OUTPUT ;
    USE SIGNAL ;
    PORT
      LAYER M5 ;
        RECT  5.904 0 5.928 0.084 ;
    END
  END crom_m[54]
  PIN crom_m[55]
    DIRECTION OUTPUT ;
    USE SIGNAL ;
    PORT
      LAYER M5 ;
        RECT  6 0 6.024 0.084 ;
    END
  END crom_m[55]
  PIN crom_m[56]
    DIRECTION OUTPUT ;
    USE SIGNAL ;
    PORT
      LAYER M5 ;
        RECT  6.096 0 6.12 0.084 ;
    END
  END crom_m[56]
  PIN crom_m[57]
    DIRECTION OUTPUT ;
    USE SIGNAL ;
    PORT
      LAYER M5 ;
        RECT  6.192 0 6.216 0.084 ;
    END
  END crom_m[57]
  PIN crom_m[58]
    DIRECTION OUTPUT ;
    USE SIGNAL ;
    PORT
      LAYER M5 ;
        RECT  6.288 0 6.312 0.084 ;
    END
  END crom_m[58]
  PIN crom_m[59]
    DIRECTION OUTPUT ;
    USE SIGNAL ;
    PORT
      LAYER M5 ;
        RECT  6.384 0 6.408 0.084 ;
    END
  END crom_m[59]
  PIN crom_m[5]
    DIRECTION OUTPUT ;
    USE SIGNAL ;
    PORT
      LAYER M5 ;
        RECT  10.416 0 10.44 0.084 ;
    END
  END crom_m[5]
  PIN crom_m[60]
    DIRECTION OUTPUT ;
    USE SIGNAL ;
    PORT
      LAYER M5 ;
        RECT  6.48 0 6.504 0.084 ;
    END
  END crom_m[60]
  PIN crom_m[61]
    DIRECTION OUTPUT ;
    USE SIGNAL ;
    PORT
      LAYER M5 ;
        RECT  6.576 0 6.6 0.084 ;
    END
  END crom_m[61]
  PIN crom_m[62]
    DIRECTION OUTPUT ;
    USE SIGNAL ;
    PORT
      LAYER M5 ;
        RECT  6.672 0 6.696 0.084 ;
    END
  END crom_m[62]
  PIN crom_m[63]
    DIRECTION OUTPUT ;
    USE SIGNAL ;
    PORT
      LAYER M5 ;
        RECT  6.768 0 6.792 0.084 ;
    END
  END crom_m[63]
  PIN crom_m[64]
    DIRECTION OUTPUT ;
    USE SIGNAL ;
    PORT
      LAYER M5 ;
        RECT  13.008 0 13.032 0.084 ;
    END
  END crom_m[64]
  PIN crom_m[65]
    DIRECTION OUTPUT ;
    USE SIGNAL ;
    PORT
      LAYER M5 ;
        RECT  13.104 0 13.128 0.084 ;
    END
  END crom_m[65]
  PIN crom_m[66]
    DIRECTION OUTPUT ;
    USE SIGNAL ;
    PORT
      LAYER M5 ;
        RECT  13.2 0 13.224 0.084 ;
    END
  END crom_m[66]
  PIN crom_m[67]
    DIRECTION OUTPUT ;
    USE SIGNAL ;
    PORT
      LAYER M5 ;
        RECT  13.296 0 13.32 0.084 ;
    END
  END crom_m[67]
  PIN crom_m[68]
    DIRECTION OUTPUT ;
    USE SIGNAL ;
    PORT
      LAYER M5 ;
        RECT  13.392 0 13.416 0.084 ;
    END
  END crom_m[68]
  PIN crom_m[69]
    DIRECTION OUTPUT ;
    USE SIGNAL ;
    PORT
      LAYER M5 ;
        RECT  13.488 0 13.512 0.084 ;
    END
  END crom_m[69]
  PIN crom_m[6]
    DIRECTION OUTPUT ;
    USE SIGNAL ;
    PORT
      LAYER M5 ;
        RECT  10.512 0 10.536 0.084 ;
    END
  END crom_m[6]
  PIN crom_m[70]
    DIRECTION OUTPUT ;
    USE SIGNAL ;
    PORT
      LAYER M5 ;
        RECT  13.584 0 13.608 0.084 ;
    END
  END crom_m[70]
  PIN crom_m[71]
    DIRECTION OUTPUT ;
    USE SIGNAL ;
    PORT
      LAYER M5 ;
        RECT  13.68 0 13.704 0.084 ;
    END
  END crom_m[71]
  PIN crom_m[72]
    DIRECTION OUTPUT ;
    USE SIGNAL ;
    PORT
      LAYER M5 ;
        RECT  13.776 0 13.8 0.084 ;
    END
  END crom_m[72]
  PIN crom_m[73]
    DIRECTION OUTPUT ;
    USE SIGNAL ;
    PORT
      LAYER M5 ;
        RECT  13.872 0 13.896 0.084 ;
    END
  END crom_m[73]
  PIN crom_m[74]
    DIRECTION OUTPUT ;
    USE SIGNAL ;
    PORT
      LAYER M5 ;
        RECT  13.968 0 13.992 0.084 ;
    END
  END crom_m[74]
  PIN crom_m[75]
    DIRECTION OUTPUT ;
    USE SIGNAL ;
    PORT
      LAYER M5 ;
        RECT  14.064 0 14.088 0.084 ;
    END
  END crom_m[75]
  PIN crom_m[76]
    DIRECTION OUTPUT ;
    USE SIGNAL ;
    PORT
      LAYER M5 ;
        RECT  14.16 0 14.184 0.084 ;
    END
  END crom_m[76]
  PIN crom_m[77]
    DIRECTION OUTPUT ;
    USE SIGNAL ;
    PORT
      LAYER M5 ;
        RECT  14.256 0 14.28 0.084 ;
    END
  END crom_m[77]
  PIN crom_m[78]
    DIRECTION OUTPUT ;
    USE SIGNAL ;
    PORT
      LAYER M5 ;
        RECT  14.352 0 14.376 0.084 ;
    END
  END crom_m[78]
  PIN crom_m[79]
    DIRECTION OUTPUT ;
    USE SIGNAL ;
    PORT
      LAYER M5 ;
        RECT  14.448 0 14.472 0.084 ;
    END
  END crom_m[79]
  PIN crom_m[7]
    DIRECTION OUTPUT ;
    USE SIGNAL ;
    PORT
      LAYER M5 ;
        RECT  10.608 0 10.632 0.084 ;
    END
  END crom_m[7]
  PIN crom_m[80]
    DIRECTION OUTPUT ;
    USE SIGNAL ;
    PORT
      LAYER M5 ;
        RECT  14.544 0 14.568 0.084 ;
    END
  END crom_m[80]
  PIN crom_m[81]
    DIRECTION OUTPUT ;
    USE SIGNAL ;
    PORT
      LAYER M5 ;
        RECT  14.64 0 14.664 0.084 ;
    END
  END crom_m[81]
  PIN crom_m[82]
    DIRECTION OUTPUT ;
    USE SIGNAL ;
    PORT
      LAYER M5 ;
        RECT  14.736 0 14.76 0.084 ;
    END
  END crom_m[82]
  PIN crom_m[83]
    DIRECTION OUTPUT ;
    USE SIGNAL ;
    PORT
      LAYER M5 ;
        RECT  14.832 0 14.856 0.084 ;
    END
  END crom_m[83]
  PIN crom_m[84]
    DIRECTION OUTPUT ;
    USE SIGNAL ;
    PORT
      LAYER M5 ;
        RECT  14.928 0 14.952 0.084 ;
    END
  END crom_m[84]
  PIN crom_m[85]
    DIRECTION OUTPUT ;
    USE SIGNAL ;
    PORT
      LAYER M5 ;
        RECT  15.024 0 15.048 0.084 ;
    END
  END crom_m[85]
  PIN crom_m[86]
    DIRECTION OUTPUT ;
    USE SIGNAL ;
    PORT
      LAYER M5 ;
        RECT  15.12 0 15.144 0.084 ;
    END
  END crom_m[86]
  PIN crom_m[87]
    DIRECTION OUTPUT ;
    USE SIGNAL ;
    PORT
      LAYER M5 ;
        RECT  15.216 0 15.24 0.084 ;
    END
  END crom_m[87]
  PIN crom_m[88]
    DIRECTION OUTPUT ;
    USE SIGNAL ;
    PORT
      LAYER M5 ;
        RECT  15.312 0 15.336 0.084 ;
    END
  END crom_m[88]
  PIN crom_m[89]
    DIRECTION OUTPUT ;
    USE SIGNAL ;
    PORT
      LAYER M5 ;
        RECT  15.408 0 15.432 0.084 ;
    END
  END crom_m[89]
  PIN crom_m[8]
    DIRECTION OUTPUT ;
    USE SIGNAL ;
    PORT
      LAYER M5 ;
        RECT  10.704 0 10.728 0.084 ;
    END
  END crom_m[8]
  PIN crom_m[90]
    DIRECTION OUTPUT ;
    USE SIGNAL ;
    PORT
      LAYER M5 ;
        RECT  15.504 0 15.528 0.084 ;
    END
  END crom_m[90]
  PIN crom_m[91]
    DIRECTION OUTPUT ;
    USE SIGNAL ;
    PORT
      LAYER M5 ;
        RECT  15.6 0 15.624 0.084 ;
    END
  END crom_m[91]
  PIN crom_m[92]
    DIRECTION OUTPUT ;
    USE SIGNAL ;
    PORT
      LAYER M5 ;
        RECT  15.696 0 15.72 0.084 ;
    END
  END crom_m[92]
  PIN crom_m[93]
    DIRECTION OUTPUT ;
    USE SIGNAL ;
    PORT
      LAYER M5 ;
        RECT  15.792 0 15.816 0.084 ;
    END
  END crom_m[93]
  PIN crom_m[94]
    DIRECTION OUTPUT ;
    USE SIGNAL ;
    PORT
      LAYER M5 ;
        RECT  15.888 0 15.912 0.084 ;
    END
  END crom_m[94]
  PIN crom_m[95]
    DIRECTION OUTPUT ;
    USE SIGNAL ;
    PORT
      LAYER M5 ;
        RECT  15.984 0 16.008 0.084 ;
    END
  END crom_m[95]
  PIN crom_m[96]
    DIRECTION OUTPUT ;
    USE SIGNAL ;
    PORT
      LAYER M5 ;
        RECT  22.992 0 23.016 0.084 ;
    END
  END crom_m[96]
  PIN crom_m[97]
    DIRECTION OUTPUT ;
    USE SIGNAL ;
    PORT
      LAYER M5 ;
        RECT  23.088 0 23.112 0.084 ;
    END
  END crom_m[97]
  PIN crom_m[98]
    DIRECTION OUTPUT ;
    USE SIGNAL ;
    PORT
      LAYER M5 ;
        RECT  23.184 0 23.208 0.084 ;
    END
  END crom_m[98]
  PIN crom_m[99]
    DIRECTION OUTPUT ;
    USE SIGNAL ;
    PORT
      LAYER M5 ;
        RECT  23.28 0 23.304 0.084 ;
    END
  END crom_m[99]
  PIN crom_m[9]
    DIRECTION OUTPUT ;
    USE SIGNAL ;
    PORT
      LAYER M5 ;
        RECT  10.8 0 10.824 0.084 ;
    END
  END crom_m[9]
  PIN crom_q[0]
    DIRECTION INPUT ;
    USE SIGNAL ;
    PORT
      LAYER M5 ;
        RECT  10.032 71.196 10.056 71.28 ;
    END
  END crom_q[0]
  PIN crom_q[100]
    DIRECTION INPUT ;
    USE SIGNAL ;
    PORT
      LAYER M5 ;
        RECT  20.4 71.196 20.424 71.28 ;
    END
  END crom_q[100]
  PIN crom_q[101]
    DIRECTION INPUT ;
    USE SIGNAL ;
    PORT
      LAYER M5 ;
        RECT  20.496 71.196 20.52 71.28 ;
    END
  END crom_q[101]
  PIN crom_q[102]
    DIRECTION INPUT ;
    USE SIGNAL ;
    PORT
      LAYER M5 ;
        RECT  20.592 71.196 20.616 71.28 ;
    END
  END crom_q[102]
  PIN crom_q[103]
    DIRECTION INPUT ;
    USE SIGNAL ;
    PORT
      LAYER M5 ;
        RECT  20.688 71.196 20.712 71.28 ;
    END
  END crom_q[103]
  PIN crom_q[104]
    DIRECTION INPUT ;
    USE SIGNAL ;
    PORT
      LAYER M5 ;
        RECT  20.784 71.196 20.808 71.28 ;
    END
  END crom_q[104]
  PIN crom_q[105]
    DIRECTION INPUT ;
    USE SIGNAL ;
    PORT
      LAYER M5 ;
        RECT  20.88 71.196 20.904 71.28 ;
    END
  END crom_q[105]
  PIN crom_q[106]
    DIRECTION INPUT ;
    USE SIGNAL ;
    PORT
      LAYER M5 ;
        RECT  20.976 71.196 21 71.28 ;
    END
  END crom_q[106]
  PIN crom_q[107]
    DIRECTION INPUT ;
    USE SIGNAL ;
    PORT
      LAYER M5 ;
        RECT  21.072 71.196 21.096 71.28 ;
    END
  END crom_q[107]
  PIN crom_q[108]
    DIRECTION INPUT ;
    USE SIGNAL ;
    PORT
      LAYER M5 ;
        RECT  21.168 71.196 21.192 71.28 ;
    END
  END crom_q[108]
  PIN crom_q[109]
    DIRECTION INPUT ;
    USE SIGNAL ;
    PORT
      LAYER M5 ;
        RECT  21.264 71.196 21.288 71.28 ;
    END
  END crom_q[109]
  PIN crom_q[10]
    DIRECTION INPUT ;
    USE SIGNAL ;
    PORT
      LAYER M5 ;
        RECT  10.992 71.196 11.016 71.28 ;
    END
  END crom_q[10]
  PIN crom_q[110]
    DIRECTION INPUT ;
    USE SIGNAL ;
    PORT
      LAYER M5 ;
        RECT  21.36 71.196 21.384 71.28 ;
    END
  END crom_q[110]
  PIN crom_q[111]
    DIRECTION INPUT ;
    USE SIGNAL ;
    PORT
      LAYER M5 ;
        RECT  21.456 71.196 21.48 71.28 ;
    END
  END crom_q[111]
  PIN crom_q[112]
    DIRECTION INPUT ;
    USE SIGNAL ;
    PORT
      LAYER M5 ;
        RECT  21.552 71.196 21.576 71.28 ;
    END
  END crom_q[112]
  PIN crom_q[113]
    DIRECTION INPUT ;
    USE SIGNAL ;
    PORT
      LAYER M5 ;
        RECT  21.648 71.196 21.672 71.28 ;
    END
  END crom_q[113]
  PIN crom_q[114]
    DIRECTION INPUT ;
    USE SIGNAL ;
    PORT
      LAYER M5 ;
        RECT  21.744 71.196 21.768 71.28 ;
    END
  END crom_q[114]
  PIN crom_q[115]
    DIRECTION INPUT ;
    USE SIGNAL ;
    PORT
      LAYER M5 ;
        RECT  21.84 71.196 21.864 71.28 ;
    END
  END crom_q[115]
  PIN crom_q[116]
    DIRECTION INPUT ;
    USE SIGNAL ;
    PORT
      LAYER M5 ;
        RECT  21.936 71.196 21.96 71.28 ;
    END
  END crom_q[116]
  PIN crom_q[117]
    DIRECTION INPUT ;
    USE SIGNAL ;
    PORT
      LAYER M5 ;
        RECT  22.032 71.196 22.056 71.28 ;
    END
  END crom_q[117]
  PIN crom_q[118]
    DIRECTION INPUT ;
    USE SIGNAL ;
    PORT
      LAYER M5 ;
        RECT  22.128 71.196 22.152 71.28 ;
    END
  END crom_q[118]
  PIN crom_q[119]
    DIRECTION INPUT ;
    USE SIGNAL ;
    PORT
      LAYER M5 ;
        RECT  22.224 71.196 22.248 71.28 ;
    END
  END crom_q[119]
  PIN crom_q[11]
    DIRECTION INPUT ;
    USE SIGNAL ;
    PORT
      LAYER M5 ;
        RECT  11.088 71.196 11.112 71.28 ;
    END
  END crom_q[11]
  PIN crom_q[120]
    DIRECTION INPUT ;
    USE SIGNAL ;
    PORT
      LAYER M5 ;
        RECT  22.32 71.196 22.344 71.28 ;
    END
  END crom_q[120]
  PIN crom_q[121]
    DIRECTION INPUT ;
    USE SIGNAL ;
    PORT
      LAYER M5 ;
        RECT  22.416 71.196 22.44 71.28 ;
    END
  END crom_q[121]
  PIN crom_q[122]
    DIRECTION INPUT ;
    USE SIGNAL ;
    PORT
      LAYER M5 ;
        RECT  22.512 71.196 22.536 71.28 ;
    END
  END crom_q[122]
  PIN crom_q[123]
    DIRECTION INPUT ;
    USE SIGNAL ;
    PORT
      LAYER M5 ;
        RECT  22.608 71.196 22.632 71.28 ;
    END
  END crom_q[123]
  PIN crom_q[124]
    DIRECTION INPUT ;
    USE SIGNAL ;
    PORT
      LAYER M5 ;
        RECT  22.704 71.196 22.728 71.28 ;
    END
  END crom_q[124]
  PIN crom_q[125]
    DIRECTION INPUT ;
    USE SIGNAL ;
    PORT
      LAYER M5 ;
        RECT  22.8 71.196 22.824 71.28 ;
    END
  END crom_q[125]
  PIN crom_q[126]
    DIRECTION INPUT ;
    USE SIGNAL ;
    PORT
      LAYER M5 ;
        RECT  22.896 71.196 22.92 71.28 ;
    END
  END crom_q[126]
  PIN crom_q[127]
    DIRECTION INPUT ;
    USE SIGNAL ;
    PORT
      LAYER M5 ;
        RECT  0.72 71.196 0.744 71.28 ;
    END
  END crom_q[127]
  PIN crom_q[128]
    DIRECTION INPUT ;
    USE SIGNAL ;
    PORT
      LAYER M5 ;
        RECT  0.816 71.196 0.84 71.28 ;
    END
  END crom_q[128]
  PIN crom_q[129]
    DIRECTION INPUT ;
    USE SIGNAL ;
    PORT
      LAYER M5 ;
        RECT  0.912 71.196 0.936 71.28 ;
    END
  END crom_q[129]
  PIN crom_q[12]
    DIRECTION INPUT ;
    USE SIGNAL ;
    PORT
      LAYER M5 ;
        RECT  11.184 71.196 11.208 71.28 ;
    END
  END crom_q[12]
  PIN crom_q[130]
    DIRECTION INPUT ;
    USE SIGNAL ;
    PORT
      LAYER M5 ;
        RECT  1.008 71.196 1.032 71.28 ;
    END
  END crom_q[130]
  PIN crom_q[131]
    DIRECTION INPUT ;
    USE SIGNAL ;
    PORT
      LAYER M5 ;
        RECT  1.104 71.196 1.128 71.28 ;
    END
  END crom_q[131]
  PIN crom_q[132]
    DIRECTION INPUT ;
    USE SIGNAL ;
    PORT
      LAYER M5 ;
        RECT  1.2 71.196 1.224 71.28 ;
    END
  END crom_q[132]
  PIN crom_q[133]
    DIRECTION INPUT ;
    USE SIGNAL ;
    PORT
      LAYER M5 ;
        RECT  1.296 71.196 1.32 71.28 ;
    END
  END crom_q[133]
  PIN crom_q[134]
    DIRECTION INPUT ;
    USE SIGNAL ;
    PORT
      LAYER M5 ;
        RECT  1.392 71.196 1.416 71.28 ;
    END
  END crom_q[134]
  PIN crom_q[135]
    DIRECTION INPUT ;
    USE SIGNAL ;
    PORT
      LAYER M5 ;
        RECT  1.488 71.196 1.512 71.28 ;
    END
  END crom_q[135]
  PIN crom_q[136]
    DIRECTION INPUT ;
    USE SIGNAL ;
    PORT
      LAYER M5 ;
        RECT  1.584 71.196 1.608 71.28 ;
    END
  END crom_q[136]
  PIN crom_q[137]
    DIRECTION INPUT ;
    USE SIGNAL ;
    PORT
      LAYER M5 ;
        RECT  1.68 71.196 1.704 71.28 ;
    END
  END crom_q[137]
  PIN crom_q[138]
    DIRECTION INPUT ;
    USE SIGNAL ;
    PORT
      LAYER M5 ;
        RECT  1.776 71.196 1.8 71.28 ;
    END
  END crom_q[138]
  PIN crom_q[139]
    DIRECTION INPUT ;
    USE SIGNAL ;
    PORT
      LAYER M5 ;
        RECT  1.872 71.196 1.896 71.28 ;
    END
  END crom_q[139]
  PIN crom_q[13]
    DIRECTION INPUT ;
    USE SIGNAL ;
    PORT
      LAYER M5 ;
        RECT  11.28 71.196 11.304 71.28 ;
    END
  END crom_q[13]
  PIN crom_q[140]
    DIRECTION INPUT ;
    USE SIGNAL ;
    PORT
      LAYER M5 ;
        RECT  1.968 71.196 1.992 71.28 ;
    END
  END crom_q[140]
  PIN crom_q[141]
    DIRECTION INPUT ;
    USE SIGNAL ;
    PORT
      LAYER M5 ;
        RECT  2.064 71.196 2.088 71.28 ;
    END
  END crom_q[141]
  PIN crom_q[142]
    DIRECTION INPUT ;
    USE SIGNAL ;
    PORT
      LAYER M5 ;
        RECT  2.16 71.196 2.184 71.28 ;
    END
  END crom_q[142]
  PIN crom_q[143]
    DIRECTION INPUT ;
    USE SIGNAL ;
    PORT
      LAYER M5 ;
        RECT  2.256 71.196 2.28 71.28 ;
    END
  END crom_q[143]
  PIN crom_q[144]
    DIRECTION INPUT ;
    USE SIGNAL ;
    PORT
      LAYER M5 ;
        RECT  2.352 71.196 2.376 71.28 ;
    END
  END crom_q[144]
  PIN crom_q[145]
    DIRECTION INPUT ;
    USE SIGNAL ;
    PORT
      LAYER M5 ;
        RECT  2.448 71.196 2.472 71.28 ;
    END
  END crom_q[145]
  PIN crom_q[146]
    DIRECTION INPUT ;
    USE SIGNAL ;
    PORT
      LAYER M5 ;
        RECT  2.544 71.196 2.568 71.28 ;
    END
  END crom_q[146]
  PIN crom_q[147]
    DIRECTION INPUT ;
    USE SIGNAL ;
    PORT
      LAYER M5 ;
        RECT  2.64 71.196 2.664 71.28 ;
    END
  END crom_q[147]
  PIN crom_q[148]
    DIRECTION INPUT ;
    USE SIGNAL ;
    PORT
      LAYER M5 ;
        RECT  2.736 71.196 2.76 71.28 ;
    END
  END crom_q[148]
  PIN crom_q[149]
    DIRECTION INPUT ;
    USE SIGNAL ;
    PORT
      LAYER M5 ;
        RECT  2.832 71.196 2.856 71.28 ;
    END
  END crom_q[149]
  PIN crom_q[14]
    DIRECTION INPUT ;
    USE SIGNAL ;
    PORT
      LAYER M5 ;
        RECT  11.376 71.196 11.4 71.28 ;
    END
  END crom_q[14]
  PIN crom_q[150]
    DIRECTION INPUT ;
    USE SIGNAL ;
    PORT
      LAYER M5 ;
        RECT  2.928 71.196 2.952 71.28 ;
    END
  END crom_q[150]
  PIN crom_q[151]
    DIRECTION INPUT ;
    USE SIGNAL ;
    PORT
      LAYER M5 ;
        RECT  3.024 71.196 3.048 71.28 ;
    END
  END crom_q[151]
  PIN crom_q[152]
    DIRECTION INPUT ;
    USE SIGNAL ;
    PORT
      LAYER M5 ;
        RECT  3.12 71.196 3.144 71.28 ;
    END
  END crom_q[152]
  PIN crom_q[153]
    DIRECTION INPUT ;
    USE SIGNAL ;
    PORT
      LAYER M5 ;
        RECT  3.216 71.196 3.24 71.28 ;
    END
  END crom_q[153]
  PIN crom_q[154]
    DIRECTION INPUT ;
    USE SIGNAL ;
    PORT
      LAYER M5 ;
        RECT  3.312 71.196 3.336 71.28 ;
    END
  END crom_q[154]
  PIN crom_q[155]
    DIRECTION INPUT ;
    USE SIGNAL ;
    PORT
      LAYER M5 ;
        RECT  3.408 71.196 3.432 71.28 ;
    END
  END crom_q[155]
  PIN crom_q[156]
    DIRECTION INPUT ;
    USE SIGNAL ;
    PORT
      LAYER M5 ;
        RECT  3.504 71.196 3.528 71.28 ;
    END
  END crom_q[156]
  PIN crom_q[157]
    DIRECTION INPUT ;
    USE SIGNAL ;
    PORT
      LAYER M5 ;
        RECT  3.6 71.196 3.624 71.28 ;
    END
  END crom_q[157]
  PIN crom_q[158]
    DIRECTION INPUT ;
    USE SIGNAL ;
    PORT
      LAYER M5 ;
        RECT  3.696 71.196 3.72 71.28 ;
    END
  END crom_q[158]
  PIN crom_q[159]
    DIRECTION INPUT ;
    USE SIGNAL ;
    PORT
      LAYER M5 ;
        RECT  22.992 71.196 23.016 71.28 ;
    END
  END crom_q[159]
  PIN crom_q[15]
    DIRECTION INPUT ;
    USE SIGNAL ;
    PORT
      LAYER M5 ;
        RECT  11.472 71.196 11.496 71.28 ;
    END
  END crom_q[15]
  PIN crom_q[160]
    DIRECTION INPUT ;
    USE SIGNAL ;
    PORT
      LAYER M5 ;
        RECT  23.088 71.196 23.112 71.28 ;
    END
  END crom_q[160]
  PIN crom_q[161]
    DIRECTION INPUT ;
    USE SIGNAL ;
    PORT
      LAYER M5 ;
        RECT  23.184 71.196 23.208 71.28 ;
    END
  END crom_q[161]
  PIN crom_q[162]
    DIRECTION INPUT ;
    USE SIGNAL ;
    PORT
      LAYER M5 ;
        RECT  23.28 71.196 23.304 71.28 ;
    END
  END crom_q[162]
  PIN crom_q[163]
    DIRECTION INPUT ;
    USE SIGNAL ;
    PORT
      LAYER M5 ;
        RECT  23.376 71.196 23.4 71.28 ;
    END
  END crom_q[163]
  PIN crom_q[164]
    DIRECTION INPUT ;
    USE SIGNAL ;
    PORT
      LAYER M5 ;
        RECT  23.472 71.196 23.496 71.28 ;
    END
  END crom_q[164]
  PIN crom_q[165]
    DIRECTION INPUT ;
    USE SIGNAL ;
    PORT
      LAYER M5 ;
        RECT  23.568 71.196 23.592 71.28 ;
    END
  END crom_q[165]
  PIN crom_q[166]
    DIRECTION INPUT ;
    USE SIGNAL ;
    PORT
      LAYER M5 ;
        RECT  23.664 71.196 23.688 71.28 ;
    END
  END crom_q[166]
  PIN crom_q[167]
    DIRECTION INPUT ;
    USE SIGNAL ;
    PORT
      LAYER M5 ;
        RECT  23.76 71.196 23.784 71.28 ;
    END
  END crom_q[167]
  PIN crom_q[168]
    DIRECTION INPUT ;
    USE SIGNAL ;
    PORT
      LAYER M5 ;
        RECT  23.856 71.196 23.88 71.28 ;
    END
  END crom_q[168]
  PIN crom_q[169]
    DIRECTION INPUT ;
    USE SIGNAL ;
    PORT
      LAYER M5 ;
        RECT  23.952 71.196 23.976 71.28 ;
    END
  END crom_q[169]
  PIN crom_q[16]
    DIRECTION INPUT ;
    USE SIGNAL ;
    PORT
      LAYER M5 ;
        RECT  11.568 71.196 11.592 71.28 ;
    END
  END crom_q[16]
  PIN crom_q[170]
    DIRECTION INPUT ;
    USE SIGNAL ;
    PORT
      LAYER M5 ;
        RECT  24.048 71.196 24.072 71.28 ;
    END
  END crom_q[170]
  PIN crom_q[171]
    DIRECTION INPUT ;
    USE SIGNAL ;
    PORT
      LAYER M5 ;
        RECT  24.144 71.196 24.168 71.28 ;
    END
  END crom_q[171]
  PIN crom_q[172]
    DIRECTION INPUT ;
    USE SIGNAL ;
    PORT
      LAYER M5 ;
        RECT  24.24 71.196 24.264 71.28 ;
    END
  END crom_q[172]
  PIN crom_q[173]
    DIRECTION INPUT ;
    USE SIGNAL ;
    PORT
      LAYER M5 ;
        RECT  24.336 71.196 24.36 71.28 ;
    END
  END crom_q[173]
  PIN crom_q[174]
    DIRECTION INPUT ;
    USE SIGNAL ;
    PORT
      LAYER M5 ;
        RECT  24.432 71.196 24.456 71.28 ;
    END
  END crom_q[174]
  PIN crom_q[175]
    DIRECTION INPUT ;
    USE SIGNAL ;
    PORT
      LAYER M5 ;
        RECT  24.528 71.196 24.552 71.28 ;
    END
  END crom_q[175]
  PIN crom_q[176]
    DIRECTION INPUT ;
    USE SIGNAL ;
    PORT
      LAYER M5 ;
        RECT  24.624 71.196 24.648 71.28 ;
    END
  END crom_q[176]
  PIN crom_q[177]
    DIRECTION INPUT ;
    USE SIGNAL ;
    PORT
      LAYER M5 ;
        RECT  24.72 71.196 24.744 71.28 ;
    END
  END crom_q[177]
  PIN crom_q[178]
    DIRECTION INPUT ;
    USE SIGNAL ;
    PORT
      LAYER M5 ;
        RECT  24.816 71.196 24.84 71.28 ;
    END
  END crom_q[178]
  PIN crom_q[179]
    DIRECTION INPUT ;
    USE SIGNAL ;
    PORT
      LAYER M5 ;
        RECT  24.912 71.196 24.936 71.28 ;
    END
  END crom_q[179]
  PIN crom_q[17]
    DIRECTION INPUT ;
    USE SIGNAL ;
    PORT
      LAYER M5 ;
        RECT  11.664 71.196 11.688 71.28 ;
    END
  END crom_q[17]
  PIN crom_q[180]
    DIRECTION INPUT ;
    USE SIGNAL ;
    PORT
      LAYER M5 ;
        RECT  25.008 71.196 25.032 71.28 ;
    END
  END crom_q[180]
  PIN crom_q[181]
    DIRECTION INPUT ;
    USE SIGNAL ;
    PORT
      LAYER M5 ;
        RECT  25.104 71.196 25.128 71.28 ;
    END
  END crom_q[181]
  PIN crom_q[182]
    DIRECTION INPUT ;
    USE SIGNAL ;
    PORT
      LAYER M5 ;
        RECT  25.2 71.196 25.224 71.28 ;
    END
  END crom_q[182]
  PIN crom_q[183]
    DIRECTION INPUT ;
    USE SIGNAL ;
    PORT
      LAYER M5 ;
        RECT  25.296 71.196 25.32 71.28 ;
    END
  END crom_q[183]
  PIN crom_q[184]
    DIRECTION INPUT ;
    USE SIGNAL ;
    PORT
      LAYER M5 ;
        RECT  25.392 71.196 25.416 71.28 ;
    END
  END crom_q[184]
  PIN crom_q[185]
    DIRECTION INPUT ;
    USE SIGNAL ;
    PORT
      LAYER M5 ;
        RECT  25.488 71.196 25.512 71.28 ;
    END
  END crom_q[185]
  PIN crom_q[186]
    DIRECTION INPUT ;
    USE SIGNAL ;
    PORT
      LAYER M5 ;
        RECT  25.584 71.196 25.608 71.28 ;
    END
  END crom_q[186]
  PIN crom_q[187]
    DIRECTION INPUT ;
    USE SIGNAL ;
    PORT
      LAYER M5 ;
        RECT  25.68 71.196 25.704 71.28 ;
    END
  END crom_q[187]
  PIN crom_q[188]
    DIRECTION INPUT ;
    USE SIGNAL ;
    PORT
      LAYER M5 ;
        RECT  25.776 71.196 25.8 71.28 ;
    END
  END crom_q[188]
  PIN crom_q[189]
    DIRECTION INPUT ;
    USE SIGNAL ;
    PORT
      LAYER M5 ;
        RECT  25.872 71.196 25.896 71.28 ;
    END
  END crom_q[189]
  PIN crom_q[18]
    DIRECTION INPUT ;
    USE SIGNAL ;
    PORT
      LAYER M5 ;
        RECT  11.76 71.196 11.784 71.28 ;
    END
  END crom_q[18]
  PIN crom_q[190]
    DIRECTION INPUT ;
    USE SIGNAL ;
    PORT
      LAYER M5 ;
        RECT  25.968 71.196 25.992 71.28 ;
    END
  END crom_q[190]
  PIN crom_q[191]
    DIRECTION INPUT ;
    USE SIGNAL ;
    PORT
      LAYER M5 ;
        RECT  16.848 71.196 16.872 71.28 ;
    END
  END crom_q[191]
  PIN crom_q[192]
    DIRECTION INPUT ;
    USE SIGNAL ;
    PORT
      LAYER M5 ;
        RECT  16.944 71.196 16.968 71.28 ;
    END
  END crom_q[192]
  PIN crom_q[193]
    DIRECTION INPUT ;
    USE SIGNAL ;
    PORT
      LAYER M5 ;
        RECT  17.04 71.196 17.064 71.28 ;
    END
  END crom_q[193]
  PIN crom_q[194]
    DIRECTION INPUT ;
    USE SIGNAL ;
    PORT
      LAYER M5 ;
        RECT  17.136 71.196 17.16 71.28 ;
    END
  END crom_q[194]
  PIN crom_q[195]
    DIRECTION INPUT ;
    USE SIGNAL ;
    PORT
      LAYER M5 ;
        RECT  17.232 71.196 17.256 71.28 ;
    END
  END crom_q[195]
  PIN crom_q[196]
    DIRECTION INPUT ;
    USE SIGNAL ;
    PORT
      LAYER M5 ;
        RECT  17.328 71.196 17.352 71.28 ;
    END
  END crom_q[196]
  PIN crom_q[197]
    DIRECTION INPUT ;
    USE SIGNAL ;
    PORT
      LAYER M5 ;
        RECT  17.424 71.196 17.448 71.28 ;
    END
  END crom_q[197]
  PIN crom_q[198]
    DIRECTION INPUT ;
    USE SIGNAL ;
    PORT
      LAYER M5 ;
        RECT  17.52 71.196 17.544 71.28 ;
    END
  END crom_q[198]
  PIN crom_q[199]
    DIRECTION INPUT ;
    USE SIGNAL ;
    PORT
      LAYER M5 ;
        RECT  17.616 71.196 17.64 71.28 ;
    END
  END crom_q[199]
  PIN crom_q[19]
    DIRECTION INPUT ;
    USE SIGNAL ;
    PORT
      LAYER M5 ;
        RECT  11.856 71.196 11.88 71.28 ;
    END
  END crom_q[19]
  PIN crom_q[1]
    DIRECTION INPUT ;
    USE SIGNAL ;
    PORT
      LAYER M5 ;
        RECT  10.128 71.196 10.152 71.28 ;
    END
  END crom_q[1]
  PIN crom_q[200]
    DIRECTION INPUT ;
    USE SIGNAL ;
    PORT
      LAYER M5 ;
        RECT  17.712 71.196 17.736 71.28 ;
    END
  END crom_q[200]
  PIN crom_q[201]
    DIRECTION INPUT ;
    USE SIGNAL ;
    PORT
      LAYER M5 ;
        RECT  17.808 71.196 17.832 71.28 ;
    END
  END crom_q[201]
  PIN crom_q[202]
    DIRECTION INPUT ;
    USE SIGNAL ;
    PORT
      LAYER M5 ;
        RECT  17.904 71.196 17.928 71.28 ;
    END
  END crom_q[202]
  PIN crom_q[203]
    DIRECTION INPUT ;
    USE SIGNAL ;
    PORT
      LAYER M5 ;
        RECT  18 71.196 18.024 71.28 ;
    END
  END crom_q[203]
  PIN crom_q[204]
    DIRECTION INPUT ;
    USE SIGNAL ;
    PORT
      LAYER M5 ;
        RECT  18.096 71.196 18.12 71.28 ;
    END
  END crom_q[204]
  PIN crom_q[205]
    DIRECTION INPUT ;
    USE SIGNAL ;
    PORT
      LAYER M5 ;
        RECT  18.192 71.196 18.216 71.28 ;
    END
  END crom_q[205]
  PIN crom_q[206]
    DIRECTION INPUT ;
    USE SIGNAL ;
    PORT
      LAYER M5 ;
        RECT  18.288 71.196 18.312 71.28 ;
    END
  END crom_q[206]
  PIN crom_q[207]
    DIRECTION INPUT ;
    USE SIGNAL ;
    PORT
      LAYER M5 ;
        RECT  18.384 71.196 18.408 71.28 ;
    END
  END crom_q[207]
  PIN crom_q[208]
    DIRECTION INPUT ;
    USE SIGNAL ;
    PORT
      LAYER M5 ;
        RECT  18.48 71.196 18.504 71.28 ;
    END
  END crom_q[208]
  PIN crom_q[209]
    DIRECTION INPUT ;
    USE SIGNAL ;
    PORT
      LAYER M5 ;
        RECT  18.576 71.196 18.6 71.28 ;
    END
  END crom_q[209]
  PIN crom_q[20]
    DIRECTION INPUT ;
    USE SIGNAL ;
    PORT
      LAYER M5 ;
        RECT  11.952 71.196 11.976 71.28 ;
    END
  END crom_q[20]
  PIN crom_q[210]
    DIRECTION INPUT ;
    USE SIGNAL ;
    PORT
      LAYER M5 ;
        RECT  18.672 71.196 18.696 71.28 ;
    END
  END crom_q[210]
  PIN crom_q[211]
    DIRECTION INPUT ;
    USE SIGNAL ;
    PORT
      LAYER M5 ;
        RECT  18.768 71.196 18.792 71.28 ;
    END
  END crom_q[211]
  PIN crom_q[212]
    DIRECTION INPUT ;
    USE SIGNAL ;
    PORT
      LAYER M5 ;
        RECT  18.864 71.196 18.888 71.28 ;
    END
  END crom_q[212]
  PIN crom_q[213]
    DIRECTION INPUT ;
    USE SIGNAL ;
    PORT
      LAYER M5 ;
        RECT  18.96 71.196 18.984 71.28 ;
    END
  END crom_q[213]
  PIN crom_q[214]
    DIRECTION INPUT ;
    USE SIGNAL ;
    PORT
      LAYER M5 ;
        RECT  19.056 71.196 19.08 71.28 ;
    END
  END crom_q[214]
  PIN crom_q[215]
    DIRECTION INPUT ;
    USE SIGNAL ;
    PORT
      LAYER M5 ;
        RECT  19.152 71.196 19.176 71.28 ;
    END
  END crom_q[215]
  PIN crom_q[216]
    DIRECTION INPUT ;
    USE SIGNAL ;
    PORT
      LAYER M5 ;
        RECT  19.248 71.196 19.272 71.28 ;
    END
  END crom_q[216]
  PIN crom_q[217]
    DIRECTION INPUT ;
    USE SIGNAL ;
    PORT
      LAYER M5 ;
        RECT  19.344 71.196 19.368 71.28 ;
    END
  END crom_q[217]
  PIN crom_q[218]
    DIRECTION INPUT ;
    USE SIGNAL ;
    PORT
      LAYER M5 ;
        RECT  19.44 71.196 19.464 71.28 ;
    END
  END crom_q[218]
  PIN crom_q[219]
    DIRECTION INPUT ;
    USE SIGNAL ;
    PORT
      LAYER M5 ;
        RECT  19.536 71.196 19.56 71.28 ;
    END
  END crom_q[219]
  PIN crom_q[21]
    DIRECTION INPUT ;
    USE SIGNAL ;
    PORT
      LAYER M5 ;
        RECT  12.048 71.196 12.072 71.28 ;
    END
  END crom_q[21]
  PIN crom_q[220]
    DIRECTION INPUT ;
    USE SIGNAL ;
    PORT
      LAYER M5 ;
        RECT  19.632 71.196 19.656 71.28 ;
    END
  END crom_q[220]
  PIN crom_q[221]
    DIRECTION INPUT ;
    USE SIGNAL ;
    PORT
      LAYER M5 ;
        RECT  19.728 71.196 19.752 71.28 ;
    END
  END crom_q[221]
  PIN crom_q[222]
    DIRECTION INPUT ;
    USE SIGNAL ;
    PORT
      LAYER M5 ;
        RECT  19.824 71.196 19.848 71.28 ;
    END
  END crom_q[222]
  PIN crom_q[223]
    DIRECTION INPUT ;
    USE SIGNAL ;
    PORT
      LAYER M5 ;
        RECT  13.776 71.196 13.8 71.28 ;
    END
  END crom_q[223]
  PIN crom_q[224]
    DIRECTION INPUT ;
    USE SIGNAL ;
    PORT
      LAYER M5 ;
        RECT  13.872 71.196 13.896 71.28 ;
    END
  END crom_q[224]
  PIN crom_q[225]
    DIRECTION INPUT ;
    USE SIGNAL ;
    PORT
      LAYER M5 ;
        RECT  13.968 71.196 13.992 71.28 ;
    END
  END crom_q[225]
  PIN crom_q[226]
    DIRECTION INPUT ;
    USE SIGNAL ;
    PORT
      LAYER M5 ;
        RECT  14.064 71.196 14.088 71.28 ;
    END
  END crom_q[226]
  PIN crom_q[227]
    DIRECTION INPUT ;
    USE SIGNAL ;
    PORT
      LAYER M5 ;
        RECT  14.16 71.196 14.184 71.28 ;
    END
  END crom_q[227]
  PIN crom_q[228]
    DIRECTION INPUT ;
    USE SIGNAL ;
    PORT
      LAYER M5 ;
        RECT  14.256 71.196 14.28 71.28 ;
    END
  END crom_q[228]
  PIN crom_q[229]
    DIRECTION INPUT ;
    USE SIGNAL ;
    PORT
      LAYER M5 ;
        RECT  14.352 71.196 14.376 71.28 ;
    END
  END crom_q[229]
  PIN crom_q[22]
    DIRECTION INPUT ;
    USE SIGNAL ;
    PORT
      LAYER M5 ;
        RECT  12.144 71.196 12.168 71.28 ;
    END
  END crom_q[22]
  PIN crom_q[230]
    DIRECTION INPUT ;
    USE SIGNAL ;
    PORT
      LAYER M5 ;
        RECT  14.448 71.196 14.472 71.28 ;
    END
  END crom_q[230]
  PIN crom_q[231]
    DIRECTION INPUT ;
    USE SIGNAL ;
    PORT
      LAYER M5 ;
        RECT  14.544 71.196 14.568 71.28 ;
    END
  END crom_q[231]
  PIN crom_q[232]
    DIRECTION INPUT ;
    USE SIGNAL ;
    PORT
      LAYER M5 ;
        RECT  14.64 71.196 14.664 71.28 ;
    END
  END crom_q[232]
  PIN crom_q[233]
    DIRECTION INPUT ;
    USE SIGNAL ;
    PORT
      LAYER M5 ;
        RECT  14.736 71.196 14.76 71.28 ;
    END
  END crom_q[233]
  PIN crom_q[234]
    DIRECTION INPUT ;
    USE SIGNAL ;
    PORT
      LAYER M5 ;
        RECT  14.832 71.196 14.856 71.28 ;
    END
  END crom_q[234]
  PIN crom_q[235]
    DIRECTION INPUT ;
    USE SIGNAL ;
    PORT
      LAYER M5 ;
        RECT  14.928 71.196 14.952 71.28 ;
    END
  END crom_q[235]
  PIN crom_q[236]
    DIRECTION INPUT ;
    USE SIGNAL ;
    PORT
      LAYER M5 ;
        RECT  15.024 71.196 15.048 71.28 ;
    END
  END crom_q[236]
  PIN crom_q[237]
    DIRECTION INPUT ;
    USE SIGNAL ;
    PORT
      LAYER M5 ;
        RECT  15.12 71.196 15.144 71.28 ;
    END
  END crom_q[237]
  PIN crom_q[238]
    DIRECTION INPUT ;
    USE SIGNAL ;
    PORT
      LAYER M5 ;
        RECT  15.216 71.196 15.24 71.28 ;
    END
  END crom_q[238]
  PIN crom_q[239]
    DIRECTION INPUT ;
    USE SIGNAL ;
    PORT
      LAYER M5 ;
        RECT  15.312 71.196 15.336 71.28 ;
    END
  END crom_q[239]
  PIN crom_q[23]
    DIRECTION INPUT ;
    USE SIGNAL ;
    PORT
      LAYER M5 ;
        RECT  12.24 71.196 12.264 71.28 ;
    END
  END crom_q[23]
  PIN crom_q[240]
    DIRECTION INPUT ;
    USE SIGNAL ;
    PORT
      LAYER M5 ;
        RECT  15.408 71.196 15.432 71.28 ;
    END
  END crom_q[240]
  PIN crom_q[241]
    DIRECTION INPUT ;
    USE SIGNAL ;
    PORT
      LAYER M5 ;
        RECT  15.504 71.196 15.528 71.28 ;
    END
  END crom_q[241]
  PIN crom_q[242]
    DIRECTION INPUT ;
    USE SIGNAL ;
    PORT
      LAYER M5 ;
        RECT  15.6 71.196 15.624 71.28 ;
    END
  END crom_q[242]
  PIN crom_q[243]
    DIRECTION INPUT ;
    USE SIGNAL ;
    PORT
      LAYER M5 ;
        RECT  15.696 71.196 15.72 71.28 ;
    END
  END crom_q[243]
  PIN crom_q[244]
    DIRECTION INPUT ;
    USE SIGNAL ;
    PORT
      LAYER M5 ;
        RECT  15.792 71.196 15.816 71.28 ;
    END
  END crom_q[244]
  PIN crom_q[245]
    DIRECTION INPUT ;
    USE SIGNAL ;
    PORT
      LAYER M5 ;
        RECT  15.888 71.196 15.912 71.28 ;
    END
  END crom_q[245]
  PIN crom_q[246]
    DIRECTION INPUT ;
    USE SIGNAL ;
    PORT
      LAYER M5 ;
        RECT  15.984 71.196 16.008 71.28 ;
    END
  END crom_q[246]
  PIN crom_q[247]
    DIRECTION INPUT ;
    USE SIGNAL ;
    PORT
      LAYER M5 ;
        RECT  16.08 71.196 16.104 71.28 ;
    END
  END crom_q[247]
  PIN crom_q[248]
    DIRECTION INPUT ;
    USE SIGNAL ;
    PORT
      LAYER M5 ;
        RECT  16.176 71.196 16.2 71.28 ;
    END
  END crom_q[248]
  PIN crom_q[249]
    DIRECTION INPUT ;
    USE SIGNAL ;
    PORT
      LAYER M5 ;
        RECT  16.272 71.196 16.296 71.28 ;
    END
  END crom_q[249]
  PIN crom_q[24]
    DIRECTION INPUT ;
    USE SIGNAL ;
    PORT
      LAYER M5 ;
        RECT  12.336 71.196 12.36 71.28 ;
    END
  END crom_q[24]
  PIN crom_q[250]
    DIRECTION INPUT ;
    USE SIGNAL ;
    PORT
      LAYER M5 ;
        RECT  16.368 71.196 16.392 71.28 ;
    END
  END crom_q[250]
  PIN crom_q[251]
    DIRECTION INPUT ;
    USE SIGNAL ;
    PORT
      LAYER M5 ;
        RECT  16.464 71.196 16.488 71.28 ;
    END
  END crom_q[251]
  PIN crom_q[252]
    DIRECTION INPUT ;
    USE SIGNAL ;
    PORT
      LAYER M5 ;
        RECT  16.56 71.196 16.584 71.28 ;
    END
  END crom_q[252]
  PIN crom_q[253]
    DIRECTION INPUT ;
    USE SIGNAL ;
    PORT
      LAYER M5 ;
        RECT  16.656 71.196 16.68 71.28 ;
    END
  END crom_q[253]
  PIN crom_q[254]
    DIRECTION INPUT ;
    USE SIGNAL ;
    PORT
      LAYER M5 ;
        RECT  16.752 71.196 16.776 71.28 ;
    END
  END crom_q[254]
  PIN crom_q[255]
    DIRECTION INPUT ;
    USE SIGNAL ;
    PORT
      LAYER M5 ;
        RECT  29.136 71.196 29.16 71.28 ;
    END
  END crom_q[255]
  PIN crom_q[25]
    DIRECTION INPUT ;
    USE SIGNAL ;
    PORT
      LAYER M5 ;
        RECT  12.432 71.196 12.456 71.28 ;
    END
  END crom_q[25]
  PIN crom_q[26]
    DIRECTION INPUT ;
    USE SIGNAL ;
    PORT
      LAYER M5 ;
        RECT  12.528 71.196 12.552 71.28 ;
    END
  END crom_q[26]
  PIN crom_q[27]
    DIRECTION INPUT ;
    USE SIGNAL ;
    PORT
      LAYER M5 ;
        RECT  12.624 71.196 12.648 71.28 ;
    END
  END crom_q[27]
  PIN crom_q[28]
    DIRECTION INPUT ;
    USE SIGNAL ;
    PORT
      LAYER M5 ;
        RECT  12.72 71.196 12.744 71.28 ;
    END
  END crom_q[28]
  PIN crom_q[29]
    DIRECTION INPUT ;
    USE SIGNAL ;
    PORT
      LAYER M5 ;
        RECT  12.816 71.196 12.84 71.28 ;
    END
  END crom_q[29]
  PIN crom_q[2]
    DIRECTION INPUT ;
    USE SIGNAL ;
    PORT
      LAYER M5 ;
        RECT  10.224 71.196 10.248 71.28 ;
    END
  END crom_q[2]
  PIN crom_q[30]
    DIRECTION INPUT ;
    USE SIGNAL ;
    PORT
      LAYER M5 ;
        RECT  12.912 71.196 12.936 71.28 ;
    END
  END crom_q[30]
  PIN crom_q[31]
    DIRECTION INPUT ;
    USE SIGNAL ;
    PORT
      LAYER M5 ;
        RECT  3.792 71.196 3.816 71.28 ;
    END
  END crom_q[31]
  PIN crom_q[32]
    DIRECTION INPUT ;
    USE SIGNAL ;
    PORT
      LAYER M5 ;
        RECT  3.888 71.196 3.912 71.28 ;
    END
  END crom_q[32]
  PIN crom_q[33]
    DIRECTION INPUT ;
    USE SIGNAL ;
    PORT
      LAYER M5 ;
        RECT  3.984 71.196 4.008 71.28 ;
    END
  END crom_q[33]
  PIN crom_q[34]
    DIRECTION INPUT ;
    USE SIGNAL ;
    PORT
      LAYER M5 ;
        RECT  4.08 71.196 4.104 71.28 ;
    END
  END crom_q[34]
  PIN crom_q[35]
    DIRECTION INPUT ;
    USE SIGNAL ;
    PORT
      LAYER M5 ;
        RECT  4.176 71.196 4.2 71.28 ;
    END
  END crom_q[35]
  PIN crom_q[36]
    DIRECTION INPUT ;
    USE SIGNAL ;
    PORT
      LAYER M5 ;
        RECT  4.272 71.196 4.296 71.28 ;
    END
  END crom_q[36]
  PIN crom_q[37]
    DIRECTION INPUT ;
    USE SIGNAL ;
    PORT
      LAYER M5 ;
        RECT  4.368 71.196 4.392 71.28 ;
    END
  END crom_q[37]
  PIN crom_q[38]
    DIRECTION INPUT ;
    USE SIGNAL ;
    PORT
      LAYER M5 ;
        RECT  4.464 71.196 4.488 71.28 ;
    END
  END crom_q[38]
  PIN crom_q[39]
    DIRECTION INPUT ;
    USE SIGNAL ;
    PORT
      LAYER M5 ;
        RECT  4.56 71.196 4.584 71.28 ;
    END
  END crom_q[39]
  PIN crom_q[3]
    DIRECTION INPUT ;
    USE SIGNAL ;
    PORT
      LAYER M5 ;
        RECT  10.32 71.196 10.344 71.28 ;
    END
  END crom_q[3]
  PIN crom_q[40]
    DIRECTION INPUT ;
    USE SIGNAL ;
    PORT
      LAYER M5 ;
        RECT  4.656 71.196 4.68 71.28 ;
    END
  END crom_q[40]
  PIN crom_q[41]
    DIRECTION INPUT ;
    USE SIGNAL ;
    PORT
      LAYER M5 ;
        RECT  4.752 71.196 4.776 71.28 ;
    END
  END crom_q[41]
  PIN crom_q[42]
    DIRECTION INPUT ;
    USE SIGNAL ;
    PORT
      LAYER M5 ;
        RECT  4.848 71.196 4.872 71.28 ;
    END
  END crom_q[42]
  PIN crom_q[43]
    DIRECTION INPUT ;
    USE SIGNAL ;
    PORT
      LAYER M5 ;
        RECT  4.944 71.196 4.968 71.28 ;
    END
  END crom_q[43]
  PIN crom_q[44]
    DIRECTION INPUT ;
    USE SIGNAL ;
    PORT
      LAYER M5 ;
        RECT  5.04 71.196 5.064 71.28 ;
    END
  END crom_q[44]
  PIN crom_q[45]
    DIRECTION INPUT ;
    USE SIGNAL ;
    PORT
      LAYER M5 ;
        RECT  5.136 71.196 5.16 71.28 ;
    END
  END crom_q[45]
  PIN crom_q[46]
    DIRECTION INPUT ;
    USE SIGNAL ;
    PORT
      LAYER M5 ;
        RECT  5.232 71.196 5.256 71.28 ;
    END
  END crom_q[46]
  PIN crom_q[47]
    DIRECTION INPUT ;
    USE SIGNAL ;
    PORT
      LAYER M5 ;
        RECT  5.328 71.196 5.352 71.28 ;
    END
  END crom_q[47]
  PIN crom_q[48]
    DIRECTION INPUT ;
    USE SIGNAL ;
    PORT
      LAYER M5 ;
        RECT  5.424 71.196 5.448 71.28 ;
    END
  END crom_q[48]
  PIN crom_q[49]
    DIRECTION INPUT ;
    USE SIGNAL ;
    PORT
      LAYER M5 ;
        RECT  5.52 71.196 5.544 71.28 ;
    END
  END crom_q[49]
  PIN crom_q[4]
    DIRECTION INPUT ;
    USE SIGNAL ;
    PORT
      LAYER M5 ;
        RECT  10.416 71.196 10.44 71.28 ;
    END
  END crom_q[4]
  PIN crom_q[50]
    DIRECTION INPUT ;
    USE SIGNAL ;
    PORT
      LAYER M5 ;
        RECT  5.616 71.196 5.64 71.28 ;
    END
  END crom_q[50]
  PIN crom_q[51]
    DIRECTION INPUT ;
    USE SIGNAL ;
    PORT
      LAYER M5 ;
        RECT  5.712 71.196 5.736 71.28 ;
    END
  END crom_q[51]
  PIN crom_q[52]
    DIRECTION INPUT ;
    USE SIGNAL ;
    PORT
      LAYER M5 ;
        RECT  5.808 71.196 5.832 71.28 ;
    END
  END crom_q[52]
  PIN crom_q[53]
    DIRECTION INPUT ;
    USE SIGNAL ;
    PORT
      LAYER M5 ;
        RECT  5.904 71.196 5.928 71.28 ;
    END
  END crom_q[53]
  PIN crom_q[54]
    DIRECTION INPUT ;
    USE SIGNAL ;
    PORT
      LAYER M5 ;
        RECT  6 71.196 6.024 71.28 ;
    END
  END crom_q[54]
  PIN crom_q[55]
    DIRECTION INPUT ;
    USE SIGNAL ;
    PORT
      LAYER M5 ;
        RECT  6.096 71.196 6.12 71.28 ;
    END
  END crom_q[55]
  PIN crom_q[56]
    DIRECTION INPUT ;
    USE SIGNAL ;
    PORT
      LAYER M5 ;
        RECT  6.192 71.196 6.216 71.28 ;
    END
  END crom_q[56]
  PIN crom_q[57]
    DIRECTION INPUT ;
    USE SIGNAL ;
    PORT
      LAYER M5 ;
        RECT  6.288 71.196 6.312 71.28 ;
    END
  END crom_q[57]
  PIN crom_q[58]
    DIRECTION INPUT ;
    USE SIGNAL ;
    PORT
      LAYER M5 ;
        RECT  6.384 71.196 6.408 71.28 ;
    END
  END crom_q[58]
  PIN crom_q[59]
    DIRECTION INPUT ;
    USE SIGNAL ;
    PORT
      LAYER M5 ;
        RECT  6.48 71.196 6.504 71.28 ;
    END
  END crom_q[59]
  PIN crom_q[5]
    DIRECTION INPUT ;
    USE SIGNAL ;
    PORT
      LAYER M5 ;
        RECT  10.512 71.196 10.536 71.28 ;
    END
  END crom_q[5]
  PIN crom_q[60]
    DIRECTION INPUT ;
    USE SIGNAL ;
    PORT
      LAYER M5 ;
        RECT  6.576 71.196 6.6 71.28 ;
    END
  END crom_q[60]
  PIN crom_q[61]
    DIRECTION INPUT ;
    USE SIGNAL ;
    PORT
      LAYER M5 ;
        RECT  6.672 71.196 6.696 71.28 ;
    END
  END crom_q[61]
  PIN crom_q[62]
    DIRECTION INPUT ;
    USE SIGNAL ;
    PORT
      LAYER M5 ;
        RECT  6.768 71.196 6.792 71.28 ;
    END
  END crom_q[62]
  PIN crom_q[63]
    DIRECTION INPUT ;
    USE SIGNAL ;
    PORT
      LAYER M5 ;
        RECT  6.864 71.196 6.888 71.28 ;
    END
  END crom_q[63]
  PIN crom_q[64]
    DIRECTION INPUT ;
    USE SIGNAL ;
    PORT
      LAYER M5 ;
        RECT  6.96 71.196 6.984 71.28 ;
    END
  END crom_q[64]
  PIN crom_q[65]
    DIRECTION INPUT ;
    USE SIGNAL ;
    PORT
      LAYER M5 ;
        RECT  7.056 71.196 7.08 71.28 ;
    END
  END crom_q[65]
  PIN crom_q[66]
    DIRECTION INPUT ;
    USE SIGNAL ;
    PORT
      LAYER M5 ;
        RECT  7.152 71.196 7.176 71.28 ;
    END
  END crom_q[66]
  PIN crom_q[67]
    DIRECTION INPUT ;
    USE SIGNAL ;
    PORT
      LAYER M5 ;
        RECT  7.248 71.196 7.272 71.28 ;
    END
  END crom_q[67]
  PIN crom_q[68]
    DIRECTION INPUT ;
    USE SIGNAL ;
    PORT
      LAYER M5 ;
        RECT  7.344 71.196 7.368 71.28 ;
    END
  END crom_q[68]
  PIN crom_q[69]
    DIRECTION INPUT ;
    USE SIGNAL ;
    PORT
      LAYER M5 ;
        RECT  7.44 71.196 7.464 71.28 ;
    END
  END crom_q[69]
  PIN crom_q[6]
    DIRECTION INPUT ;
    USE SIGNAL ;
    PORT
      LAYER M5 ;
        RECT  10.608 71.196 10.632 71.28 ;
    END
  END crom_q[6]
  PIN crom_q[70]
    DIRECTION INPUT ;
    USE SIGNAL ;
    PORT
      LAYER M5 ;
        RECT  7.536 71.196 7.56 71.28 ;
    END
  END crom_q[70]
  PIN crom_q[71]
    DIRECTION INPUT ;
    USE SIGNAL ;
    PORT
      LAYER M5 ;
        RECT  7.632 71.196 7.656 71.28 ;
    END
  END crom_q[71]
  PIN crom_q[72]
    DIRECTION INPUT ;
    USE SIGNAL ;
    PORT
      LAYER M5 ;
        RECT  7.728 71.196 7.752 71.28 ;
    END
  END crom_q[72]
  PIN crom_q[73]
    DIRECTION INPUT ;
    USE SIGNAL ;
    PORT
      LAYER M5 ;
        RECT  7.824 71.196 7.848 71.28 ;
    END
  END crom_q[73]
  PIN crom_q[74]
    DIRECTION INPUT ;
    USE SIGNAL ;
    PORT
      LAYER M5 ;
        RECT  7.92 71.196 7.944 71.28 ;
    END
  END crom_q[74]
  PIN crom_q[75]
    DIRECTION INPUT ;
    USE SIGNAL ;
    PORT
      LAYER M5 ;
        RECT  8.016 71.196 8.04 71.28 ;
    END
  END crom_q[75]
  PIN crom_q[76]
    DIRECTION INPUT ;
    USE SIGNAL ;
    PORT
      LAYER M5 ;
        RECT  8.112 71.196 8.136 71.28 ;
    END
  END crom_q[76]
  PIN crom_q[77]
    DIRECTION INPUT ;
    USE SIGNAL ;
    PORT
      LAYER M5 ;
        RECT  8.208 71.196 8.232 71.28 ;
    END
  END crom_q[77]
  PIN crom_q[78]
    DIRECTION INPUT ;
    USE SIGNAL ;
    PORT
      LAYER M5 ;
        RECT  8.304 71.196 8.328 71.28 ;
    END
  END crom_q[78]
  PIN crom_q[79]
    DIRECTION INPUT ;
    USE SIGNAL ;
    PORT
      LAYER M5 ;
        RECT  8.4 71.196 8.424 71.28 ;
    END
  END crom_q[79]
  PIN crom_q[7]
    DIRECTION INPUT ;
    USE SIGNAL ;
    PORT
      LAYER M5 ;
        RECT  10.704 71.196 10.728 71.28 ;
    END
  END crom_q[7]
  PIN crom_q[80]
    DIRECTION INPUT ;
    USE SIGNAL ;
    PORT
      LAYER M5 ;
        RECT  8.496 71.196 8.52 71.28 ;
    END
  END crom_q[80]
  PIN crom_q[81]
    DIRECTION INPUT ;
    USE SIGNAL ;
    PORT
      LAYER M5 ;
        RECT  8.592 71.196 8.616 71.28 ;
    END
  END crom_q[81]
  PIN crom_q[82]
    DIRECTION INPUT ;
    USE SIGNAL ;
    PORT
      LAYER M5 ;
        RECT  8.688 71.196 8.712 71.28 ;
    END
  END crom_q[82]
  PIN crom_q[83]
    DIRECTION INPUT ;
    USE SIGNAL ;
    PORT
      LAYER M5 ;
        RECT  8.784 71.196 8.808 71.28 ;
    END
  END crom_q[83]
  PIN crom_q[84]
    DIRECTION INPUT ;
    USE SIGNAL ;
    PORT
      LAYER M5 ;
        RECT  8.88 71.196 8.904 71.28 ;
    END
  END crom_q[84]
  PIN crom_q[85]
    DIRECTION INPUT ;
    USE SIGNAL ;
    PORT
      LAYER M5 ;
        RECT  8.976 71.196 9 71.28 ;
    END
  END crom_q[85]
  PIN crom_q[86]
    DIRECTION INPUT ;
    USE SIGNAL ;
    PORT
      LAYER M5 ;
        RECT  9.072 71.196 9.096 71.28 ;
    END
  END crom_q[86]
  PIN crom_q[87]
    DIRECTION INPUT ;
    USE SIGNAL ;
    PORT
      LAYER M5 ;
        RECT  9.168 71.196 9.192 71.28 ;
    END
  END crom_q[87]
  PIN crom_q[88]
    DIRECTION INPUT ;
    USE SIGNAL ;
    PORT
      LAYER M5 ;
        RECT  9.264 71.196 9.288 71.28 ;
    END
  END crom_q[88]
  PIN crom_q[89]
    DIRECTION INPUT ;
    USE SIGNAL ;
    PORT
      LAYER M5 ;
        RECT  9.36 71.196 9.384 71.28 ;
    END
  END crom_q[89]
  PIN crom_q[8]
    DIRECTION INPUT ;
    USE SIGNAL ;
    PORT
      LAYER M5 ;
        RECT  10.8 71.196 10.824 71.28 ;
    END
  END crom_q[8]
  PIN crom_q[90]
    DIRECTION INPUT ;
    USE SIGNAL ;
    PORT
      LAYER M5 ;
        RECT  9.456 71.196 9.48 71.28 ;
    END
  END crom_q[90]
  PIN crom_q[91]
    DIRECTION INPUT ;
    USE SIGNAL ;
    PORT
      LAYER M5 ;
        RECT  9.552 71.196 9.576 71.28 ;
    END
  END crom_q[91]
  PIN crom_q[92]
    DIRECTION INPUT ;
    USE SIGNAL ;
    PORT
      LAYER M5 ;
        RECT  9.648 71.196 9.672 71.28 ;
    END
  END crom_q[92]
  PIN crom_q[93]
    DIRECTION INPUT ;
    USE SIGNAL ;
    PORT
      LAYER M5 ;
        RECT  9.744 71.196 9.768 71.28 ;
    END
  END crom_q[93]
  PIN crom_q[94]
    DIRECTION INPUT ;
    USE SIGNAL ;
    PORT
      LAYER M5 ;
        RECT  9.84 71.196 9.864 71.28 ;
    END
  END crom_q[94]
  PIN crom_q[95]
    DIRECTION INPUT ;
    USE SIGNAL ;
    PORT
      LAYER M5 ;
        RECT  19.92 71.196 19.944 71.28 ;
    END
  END crom_q[95]
  PIN crom_q[96]
    DIRECTION INPUT ;
    USE SIGNAL ;
    PORT
      LAYER M5 ;
        RECT  20.016 71.196 20.04 71.28 ;
    END
  END crom_q[96]
  PIN crom_q[97]
    DIRECTION INPUT ;
    USE SIGNAL ;
    PORT
      LAYER M5 ;
        RECT  20.112 71.196 20.136 71.28 ;
    END
  END crom_q[97]
  PIN crom_q[98]
    DIRECTION INPUT ;
    USE SIGNAL ;
    PORT
      LAYER M5 ;
        RECT  20.208 71.196 20.232 71.28 ;
    END
  END crom_q[98]
  PIN crom_q[99]
    DIRECTION INPUT ;
    USE SIGNAL ;
    PORT
      LAYER M5 ;
        RECT  20.304 71.196 20.328 71.28 ;
    END
  END crom_q[99]
  PIN crom_q[9]
    DIRECTION INPUT ;
    USE SIGNAL ;
    PORT
      LAYER M5 ;
        RECT  10.896 71.196 10.92 71.28 ;
    END
  END crom_q[9]
  PIN emb_m[0]
    DIRECTION OUTPUT ;
    USE SIGNAL ;
    PORT
      LAYER M5 ;
        RECT  45.264 0 45.288 0.084 ;
    END
  END emb_m[0]
  PIN emb_m[100]
    DIRECTION OUTPUT ;
    USE SIGNAL ;
    PORT
      LAYER M5 ;
        RECT  48.72 0 48.744 0.084 ;
    END
  END emb_m[100]
  PIN emb_m[101]
    DIRECTION OUTPUT ;
    USE SIGNAL ;
    PORT
      LAYER M5 ;
        RECT  48.816 0 48.84 0.084 ;
    END
  END emb_m[101]
  PIN emb_m[102]
    DIRECTION OUTPUT ;
    USE SIGNAL ;
    PORT
      LAYER M5 ;
        RECT  48.912 0 48.936 0.084 ;
    END
  END emb_m[102]
  PIN emb_m[103]
    DIRECTION OUTPUT ;
    USE SIGNAL ;
    PORT
      LAYER M5 ;
        RECT  49.008 0 49.032 0.084 ;
    END
  END emb_m[103]
  PIN emb_m[104]
    DIRECTION OUTPUT ;
    USE SIGNAL ;
    PORT
      LAYER M5 ;
        RECT  49.104 0 49.128 0.084 ;
    END
  END emb_m[104]
  PIN emb_m[105]
    DIRECTION OUTPUT ;
    USE SIGNAL ;
    PORT
      LAYER M5 ;
        RECT  49.2 0 49.224 0.084 ;
    END
  END emb_m[105]
  PIN emb_m[106]
    DIRECTION OUTPUT ;
    USE SIGNAL ;
    PORT
      LAYER M5 ;
        RECT  49.296 0 49.32 0.084 ;
    END
  END emb_m[106]
  PIN emb_m[107]
    DIRECTION OUTPUT ;
    USE SIGNAL ;
    PORT
      LAYER M5 ;
        RECT  49.392 0 49.416 0.084 ;
    END
  END emb_m[107]
  PIN emb_m[108]
    DIRECTION OUTPUT ;
    USE SIGNAL ;
    PORT
      LAYER M5 ;
        RECT  49.488 0 49.512 0.084 ;
    END
  END emb_m[108]
  PIN emb_m[109]
    DIRECTION OUTPUT ;
    USE SIGNAL ;
    PORT
      LAYER M5 ;
        RECT  49.584 0 49.608 0.084 ;
    END
  END emb_m[109]
  PIN emb_m[10]
    DIRECTION OUTPUT ;
    USE SIGNAL ;
    PORT
      LAYER M5 ;
        RECT  46.224 0 46.248 0.084 ;
    END
  END emb_m[10]
  PIN emb_m[110]
    DIRECTION OUTPUT ;
    USE SIGNAL ;
    PORT
      LAYER M5 ;
        RECT  49.68 0 49.704 0.084 ;
    END
  END emb_m[110]
  PIN emb_m[111]
    DIRECTION OUTPUT ;
    USE SIGNAL ;
    PORT
      LAYER M5 ;
        RECT  49.776 0 49.8 0.084 ;
    END
  END emb_m[111]
  PIN emb_m[112]
    DIRECTION OUTPUT ;
    USE SIGNAL ;
    PORT
      LAYER M5 ;
        RECT  49.872 0 49.896 0.084 ;
    END
  END emb_m[112]
  PIN emb_m[113]
    DIRECTION OUTPUT ;
    USE SIGNAL ;
    PORT
      LAYER M5 ;
        RECT  49.968 0 49.992 0.084 ;
    END
  END emb_m[113]
  PIN emb_m[114]
    DIRECTION OUTPUT ;
    USE SIGNAL ;
    PORT
      LAYER M5 ;
        RECT  50.064 0 50.088 0.084 ;
    END
  END emb_m[114]
  PIN emb_m[115]
    DIRECTION OUTPUT ;
    USE SIGNAL ;
    PORT
      LAYER M5 ;
        RECT  50.16 0 50.184 0.084 ;
    END
  END emb_m[115]
  PIN emb_m[116]
    DIRECTION OUTPUT ;
    USE SIGNAL ;
    PORT
      LAYER M5 ;
        RECT  50.256 0 50.28 0.084 ;
    END
  END emb_m[116]
  PIN emb_m[117]
    DIRECTION OUTPUT ;
    USE SIGNAL ;
    PORT
      LAYER M5 ;
        RECT  50.352 0 50.376 0.084 ;
    END
  END emb_m[117]
  PIN emb_m[118]
    DIRECTION OUTPUT ;
    USE SIGNAL ;
    PORT
      LAYER M5 ;
        RECT  50.448 0 50.472 0.084 ;
    END
  END emb_m[118]
  PIN emb_m[119]
    DIRECTION OUTPUT ;
    USE SIGNAL ;
    PORT
      LAYER M5 ;
        RECT  50.544 0 50.568 0.084 ;
    END
  END emb_m[119]
  PIN emb_m[11]
    DIRECTION OUTPUT ;
    USE SIGNAL ;
    PORT
      LAYER M5 ;
        RECT  46.32 0 46.344 0.084 ;
    END
  END emb_m[11]
  PIN emb_m[120]
    DIRECTION OUTPUT ;
    USE SIGNAL ;
    PORT
      LAYER M5 ;
        RECT  50.64 0 50.664 0.084 ;
    END
  END emb_m[120]
  PIN emb_m[121]
    DIRECTION OUTPUT ;
    USE SIGNAL ;
    PORT
      LAYER M5 ;
        RECT  50.736 0 50.76 0.084 ;
    END
  END emb_m[121]
  PIN emb_m[122]
    DIRECTION OUTPUT ;
    USE SIGNAL ;
    PORT
      LAYER M5 ;
        RECT  50.832 0 50.856 0.084 ;
    END
  END emb_m[122]
  PIN emb_m[123]
    DIRECTION OUTPUT ;
    USE SIGNAL ;
    PORT
      LAYER M5 ;
        RECT  50.928 0 50.952 0.084 ;
    END
  END emb_m[123]
  PIN emb_m[124]
    DIRECTION OUTPUT ;
    USE SIGNAL ;
    PORT
      LAYER M5 ;
        RECT  51.024 0 51.048 0.084 ;
    END
  END emb_m[124]
  PIN emb_m[125]
    DIRECTION OUTPUT ;
    USE SIGNAL ;
    PORT
      LAYER M5 ;
        RECT  51.12 0 51.144 0.084 ;
    END
  END emb_m[125]
  PIN emb_m[126]
    DIRECTION OUTPUT ;
    USE SIGNAL ;
    PORT
      LAYER M5 ;
        RECT  51.216 0 51.24 0.084 ;
    END
  END emb_m[126]
  PIN emb_m[127]
    DIRECTION OUTPUT ;
    USE SIGNAL ;
    PORT
      LAYER M5 ;
        RECT  51.312 0 51.336 0.084 ;
    END
  END emb_m[127]
  PIN emb_m[12]
    DIRECTION OUTPUT ;
    USE SIGNAL ;
    PORT
      LAYER M5 ;
        RECT  46.416 0 46.44 0.084 ;
    END
  END emb_m[12]
  PIN emb_m[13]
    DIRECTION OUTPUT ;
    USE SIGNAL ;
    PORT
      LAYER M5 ;
        RECT  46.512 0 46.536 0.084 ;
    END
  END emb_m[13]
  PIN emb_m[14]
    DIRECTION OUTPUT ;
    USE SIGNAL ;
    PORT
      LAYER M5 ;
        RECT  46.608 0 46.632 0.084 ;
    END
  END emb_m[14]
  PIN emb_m[15]
    DIRECTION OUTPUT ;
    USE SIGNAL ;
    PORT
      LAYER M5 ;
        RECT  46.704 0 46.728 0.084 ;
    END
  END emb_m[15]
  PIN emb_m[16]
    DIRECTION OUTPUT ;
    USE SIGNAL ;
    PORT
      LAYER M5 ;
        RECT  46.8 0 46.824 0.084 ;
    END
  END emb_m[16]
  PIN emb_m[17]
    DIRECTION OUTPUT ;
    USE SIGNAL ;
    PORT
      LAYER M5 ;
        RECT  46.896 0 46.92 0.084 ;
    END
  END emb_m[17]
  PIN emb_m[18]
    DIRECTION OUTPUT ;
    USE SIGNAL ;
    PORT
      LAYER M5 ;
        RECT  46.992 0 47.016 0.084 ;
    END
  END emb_m[18]
  PIN emb_m[19]
    DIRECTION OUTPUT ;
    USE SIGNAL ;
    PORT
      LAYER M5 ;
        RECT  47.088 0 47.112 0.084 ;
    END
  END emb_m[19]
  PIN emb_m[1]
    DIRECTION OUTPUT ;
    USE SIGNAL ;
    PORT
      LAYER M5 ;
        RECT  45.36 0 45.384 0.084 ;
    END
  END emb_m[1]
  PIN emb_m[20]
    DIRECTION OUTPUT ;
    USE SIGNAL ;
    PORT
      LAYER M5 ;
        RECT  47.184 0 47.208 0.084 ;
    END
  END emb_m[20]
  PIN emb_m[21]
    DIRECTION OUTPUT ;
    USE SIGNAL ;
    PORT
      LAYER M5 ;
        RECT  47.28 0 47.304 0.084 ;
    END
  END emb_m[21]
  PIN emb_m[22]
    DIRECTION OUTPUT ;
    USE SIGNAL ;
    PORT
      LAYER M5 ;
        RECT  47.376 0 47.4 0.084 ;
    END
  END emb_m[22]
  PIN emb_m[23]
    DIRECTION OUTPUT ;
    USE SIGNAL ;
    PORT
      LAYER M5 ;
        RECT  47.472 0 47.496 0.084 ;
    END
  END emb_m[23]
  PIN emb_m[24]
    DIRECTION OUTPUT ;
    USE SIGNAL ;
    PORT
      LAYER M5 ;
        RECT  47.568 0 47.592 0.084 ;
    END
  END emb_m[24]
  PIN emb_m[25]
    DIRECTION OUTPUT ;
    USE SIGNAL ;
    PORT
      LAYER M5 ;
        RECT  47.664 0 47.688 0.084 ;
    END
  END emb_m[25]
  PIN emb_m[26]
    DIRECTION OUTPUT ;
    USE SIGNAL ;
    PORT
      LAYER M5 ;
        RECT  47.76 0 47.784 0.084 ;
    END
  END emb_m[26]
  PIN emb_m[27]
    DIRECTION OUTPUT ;
    USE SIGNAL ;
    PORT
      LAYER M5 ;
        RECT  47.856 0 47.88 0.084 ;
    END
  END emb_m[27]
  PIN emb_m[28]
    DIRECTION OUTPUT ;
    USE SIGNAL ;
    PORT
      LAYER M5 ;
        RECT  47.952 0 47.976 0.084 ;
    END
  END emb_m[28]
  PIN emb_m[29]
    DIRECTION OUTPUT ;
    USE SIGNAL ;
    PORT
      LAYER M5 ;
        RECT  48.048 0 48.072 0.084 ;
    END
  END emb_m[29]
  PIN emb_m[2]
    DIRECTION OUTPUT ;
    USE SIGNAL ;
    PORT
      LAYER M5 ;
        RECT  45.456 0 45.48 0.084 ;
    END
  END emb_m[2]
  PIN emb_m[30]
    DIRECTION OUTPUT ;
    USE SIGNAL ;
    PORT
      LAYER M5 ;
        RECT  48.144 0 48.168 0.084 ;
    END
  END emb_m[30]
  PIN emb_m[31]
    DIRECTION OUTPUT ;
    USE SIGNAL ;
    PORT
      LAYER M5 ;
        RECT  48.24 0 48.264 0.084 ;
    END
  END emb_m[31]
  PIN emb_m[32]
    DIRECTION OUTPUT ;
    USE SIGNAL ;
    PORT
      LAYER M5 ;
        RECT  42.192 0 42.216 0.084 ;
    END
  END emb_m[32]
  PIN emb_m[33]
    DIRECTION OUTPUT ;
    USE SIGNAL ;
    PORT
      LAYER M5 ;
        RECT  42.288 0 42.312 0.084 ;
    END
  END emb_m[33]
  PIN emb_m[34]
    DIRECTION OUTPUT ;
    USE SIGNAL ;
    PORT
      LAYER M5 ;
        RECT  42.384 0 42.408 0.084 ;
    END
  END emb_m[34]
  PIN emb_m[35]
    DIRECTION OUTPUT ;
    USE SIGNAL ;
    PORT
      LAYER M5 ;
        RECT  42.48 0 42.504 0.084 ;
    END
  END emb_m[35]
  PIN emb_m[36]
    DIRECTION OUTPUT ;
    USE SIGNAL ;
    PORT
      LAYER M5 ;
        RECT  42.576 0 42.6 0.084 ;
    END
  END emb_m[36]
  PIN emb_m[37]
    DIRECTION OUTPUT ;
    USE SIGNAL ;
    PORT
      LAYER M5 ;
        RECT  42.672 0 42.696 0.084 ;
    END
  END emb_m[37]
  PIN emb_m[38]
    DIRECTION OUTPUT ;
    USE SIGNAL ;
    PORT
      LAYER M5 ;
        RECT  42.768 0 42.792 0.084 ;
    END
  END emb_m[38]
  PIN emb_m[39]
    DIRECTION OUTPUT ;
    USE SIGNAL ;
    PORT
      LAYER M5 ;
        RECT  42.864 0 42.888 0.084 ;
    END
  END emb_m[39]
  PIN emb_m[3]
    DIRECTION OUTPUT ;
    USE SIGNAL ;
    PORT
      LAYER M5 ;
        RECT  45.552 0 45.576 0.084 ;
    END
  END emb_m[3]
  PIN emb_m[40]
    DIRECTION OUTPUT ;
    USE SIGNAL ;
    PORT
      LAYER M5 ;
        RECT  42.96 0 42.984 0.084 ;
    END
  END emb_m[40]
  PIN emb_m[41]
    DIRECTION OUTPUT ;
    USE SIGNAL ;
    PORT
      LAYER M5 ;
        RECT  43.056 0 43.08 0.084 ;
    END
  END emb_m[41]
  PIN emb_m[42]
    DIRECTION OUTPUT ;
    USE SIGNAL ;
    PORT
      LAYER M5 ;
        RECT  43.152 0 43.176 0.084 ;
    END
  END emb_m[42]
  PIN emb_m[43]
    DIRECTION OUTPUT ;
    USE SIGNAL ;
    PORT
      LAYER M5 ;
        RECT  43.248 0 43.272 0.084 ;
    END
  END emb_m[43]
  PIN emb_m[44]
    DIRECTION OUTPUT ;
    USE SIGNAL ;
    PORT
      LAYER M5 ;
        RECT  43.344 0 43.368 0.084 ;
    END
  END emb_m[44]
  PIN emb_m[45]
    DIRECTION OUTPUT ;
    USE SIGNAL ;
    PORT
      LAYER M5 ;
        RECT  43.44 0 43.464 0.084 ;
    END
  END emb_m[45]
  PIN emb_m[46]
    DIRECTION OUTPUT ;
    USE SIGNAL ;
    PORT
      LAYER M5 ;
        RECT  43.536 0 43.56 0.084 ;
    END
  END emb_m[46]
  PIN emb_m[47]
    DIRECTION OUTPUT ;
    USE SIGNAL ;
    PORT
      LAYER M5 ;
        RECT  43.632 0 43.656 0.084 ;
    END
  END emb_m[47]
  PIN emb_m[48]
    DIRECTION OUTPUT ;
    USE SIGNAL ;
    PORT
      LAYER M5 ;
        RECT  43.728 0 43.752 0.084 ;
    END
  END emb_m[48]
  PIN emb_m[49]
    DIRECTION OUTPUT ;
    USE SIGNAL ;
    PORT
      LAYER M5 ;
        RECT  43.824 0 43.848 0.084 ;
    END
  END emb_m[49]
  PIN emb_m[4]
    DIRECTION OUTPUT ;
    USE SIGNAL ;
    PORT
      LAYER M5 ;
        RECT  45.648 0 45.672 0.084 ;
    END
  END emb_m[4]
  PIN emb_m[50]
    DIRECTION OUTPUT ;
    USE SIGNAL ;
    PORT
      LAYER M5 ;
        RECT  43.92 0 43.944 0.084 ;
    END
  END emb_m[50]
  PIN emb_m[51]
    DIRECTION OUTPUT ;
    USE SIGNAL ;
    PORT
      LAYER M5 ;
        RECT  44.016 0 44.04 0.084 ;
    END
  END emb_m[51]
  PIN emb_m[52]
    DIRECTION OUTPUT ;
    USE SIGNAL ;
    PORT
      LAYER M5 ;
        RECT  44.112 0 44.136 0.084 ;
    END
  END emb_m[52]
  PIN emb_m[53]
    DIRECTION OUTPUT ;
    USE SIGNAL ;
    PORT
      LAYER M5 ;
        RECT  44.208 0 44.232 0.084 ;
    END
  END emb_m[53]
  PIN emb_m[54]
    DIRECTION OUTPUT ;
    USE SIGNAL ;
    PORT
      LAYER M5 ;
        RECT  44.304 0 44.328 0.084 ;
    END
  END emb_m[54]
  PIN emb_m[55]
    DIRECTION OUTPUT ;
    USE SIGNAL ;
    PORT
      LAYER M5 ;
        RECT  44.4 0 44.424 0.084 ;
    END
  END emb_m[55]
  PIN emb_m[56]
    DIRECTION OUTPUT ;
    USE SIGNAL ;
    PORT
      LAYER M5 ;
        RECT  44.496 0 44.52 0.084 ;
    END
  END emb_m[56]
  PIN emb_m[57]
    DIRECTION OUTPUT ;
    USE SIGNAL ;
    PORT
      LAYER M5 ;
        RECT  44.592 0 44.616 0.084 ;
    END
  END emb_m[57]
  PIN emb_m[58]
    DIRECTION OUTPUT ;
    USE SIGNAL ;
    PORT
      LAYER M5 ;
        RECT  44.688 0 44.712 0.084 ;
    END
  END emb_m[58]
  PIN emb_m[59]
    DIRECTION OUTPUT ;
    USE SIGNAL ;
    PORT
      LAYER M5 ;
        RECT  44.784 0 44.808 0.084 ;
    END
  END emb_m[59]
  PIN emb_m[5]
    DIRECTION OUTPUT ;
    USE SIGNAL ;
    PORT
      LAYER M5 ;
        RECT  45.744 0 45.768 0.084 ;
    END
  END emb_m[5]
  PIN emb_m[60]
    DIRECTION OUTPUT ;
    USE SIGNAL ;
    PORT
      LAYER M5 ;
        RECT  44.88 0 44.904 0.084 ;
    END
  END emb_m[60]
  PIN emb_m[61]
    DIRECTION OUTPUT ;
    USE SIGNAL ;
    PORT
      LAYER M5 ;
        RECT  44.976 0 45 0.084 ;
    END
  END emb_m[61]
  PIN emb_m[62]
    DIRECTION OUTPUT ;
    USE SIGNAL ;
    PORT
      LAYER M5 ;
        RECT  45.072 0 45.096 0.084 ;
    END
  END emb_m[62]
  PIN emb_m[63]
    DIRECTION OUTPUT ;
    USE SIGNAL ;
    PORT
      LAYER M5 ;
        RECT  45.168 0 45.192 0.084 ;
    END
  END emb_m[63]
  PIN emb_m[64]
    DIRECTION OUTPUT ;
    USE SIGNAL ;
    PORT
      LAYER M5 ;
        RECT  39.12 0 39.144 0.084 ;
    END
  END emb_m[64]
  PIN emb_m[65]
    DIRECTION OUTPUT ;
    USE SIGNAL ;
    PORT
      LAYER M5 ;
        RECT  39.216 0 39.24 0.084 ;
    END
  END emb_m[65]
  PIN emb_m[66]
    DIRECTION OUTPUT ;
    USE SIGNAL ;
    PORT
      LAYER M5 ;
        RECT  39.312 0 39.336 0.084 ;
    END
  END emb_m[66]
  PIN emb_m[67]
    DIRECTION OUTPUT ;
    USE SIGNAL ;
    PORT
      LAYER M5 ;
        RECT  39.408 0 39.432 0.084 ;
    END
  END emb_m[67]
  PIN emb_m[68]
    DIRECTION OUTPUT ;
    USE SIGNAL ;
    PORT
      LAYER M5 ;
        RECT  39.504 0 39.528 0.084 ;
    END
  END emb_m[68]
  PIN emb_m[69]
    DIRECTION OUTPUT ;
    USE SIGNAL ;
    PORT
      LAYER M5 ;
        RECT  39.6 0 39.624 0.084 ;
    END
  END emb_m[69]
  PIN emb_m[6]
    DIRECTION OUTPUT ;
    USE SIGNAL ;
    PORT
      LAYER M5 ;
        RECT  45.84 0 45.864 0.084 ;
    END
  END emb_m[6]
  PIN emb_m[70]
    DIRECTION OUTPUT ;
    USE SIGNAL ;
    PORT
      LAYER M5 ;
        RECT  39.696 0 39.72 0.084 ;
    END
  END emb_m[70]
  PIN emb_m[71]
    DIRECTION OUTPUT ;
    USE SIGNAL ;
    PORT
      LAYER M5 ;
        RECT  39.792 0 39.816 0.084 ;
    END
  END emb_m[71]
  PIN emb_m[72]
    DIRECTION OUTPUT ;
    USE SIGNAL ;
    PORT
      LAYER M5 ;
        RECT  39.888 0 39.912 0.084 ;
    END
  END emb_m[72]
  PIN emb_m[73]
    DIRECTION OUTPUT ;
    USE SIGNAL ;
    PORT
      LAYER M5 ;
        RECT  39.984 0 40.008 0.084 ;
    END
  END emb_m[73]
  PIN emb_m[74]
    DIRECTION OUTPUT ;
    USE SIGNAL ;
    PORT
      LAYER M5 ;
        RECT  40.08 0 40.104 0.084 ;
    END
  END emb_m[74]
  PIN emb_m[75]
    DIRECTION OUTPUT ;
    USE SIGNAL ;
    PORT
      LAYER M5 ;
        RECT  40.176 0 40.2 0.084 ;
    END
  END emb_m[75]
  PIN emb_m[76]
    DIRECTION OUTPUT ;
    USE SIGNAL ;
    PORT
      LAYER M5 ;
        RECT  40.272 0 40.296 0.084 ;
    END
  END emb_m[76]
  PIN emb_m[77]
    DIRECTION OUTPUT ;
    USE SIGNAL ;
    PORT
      LAYER M5 ;
        RECT  40.368 0 40.392 0.084 ;
    END
  END emb_m[77]
  PIN emb_m[78]
    DIRECTION OUTPUT ;
    USE SIGNAL ;
    PORT
      LAYER M5 ;
        RECT  40.464 0 40.488 0.084 ;
    END
  END emb_m[78]
  PIN emb_m[79]
    DIRECTION OUTPUT ;
    USE SIGNAL ;
    PORT
      LAYER M5 ;
        RECT  40.56 0 40.584 0.084 ;
    END
  END emb_m[79]
  PIN emb_m[7]
    DIRECTION OUTPUT ;
    USE SIGNAL ;
    PORT
      LAYER M5 ;
        RECT  45.936 0 45.96 0.084 ;
    END
  END emb_m[7]
  PIN emb_m[80]
    DIRECTION OUTPUT ;
    USE SIGNAL ;
    PORT
      LAYER M5 ;
        RECT  40.656 0 40.68 0.084 ;
    END
  END emb_m[80]
  PIN emb_m[81]
    DIRECTION OUTPUT ;
    USE SIGNAL ;
    PORT
      LAYER M5 ;
        RECT  40.752 0 40.776 0.084 ;
    END
  END emb_m[81]
  PIN emb_m[82]
    DIRECTION OUTPUT ;
    USE SIGNAL ;
    PORT
      LAYER M5 ;
        RECT  40.848 0 40.872 0.084 ;
    END
  END emb_m[82]
  PIN emb_m[83]
    DIRECTION OUTPUT ;
    USE SIGNAL ;
    PORT
      LAYER M5 ;
        RECT  40.944 0 40.968 0.084 ;
    END
  END emb_m[83]
  PIN emb_m[84]
    DIRECTION OUTPUT ;
    USE SIGNAL ;
    PORT
      LAYER M5 ;
        RECT  41.04 0 41.064 0.084 ;
    END
  END emb_m[84]
  PIN emb_m[85]
    DIRECTION OUTPUT ;
    USE SIGNAL ;
    PORT
      LAYER M5 ;
        RECT  41.136 0 41.16 0.084 ;
    END
  END emb_m[85]
  PIN emb_m[86]
    DIRECTION OUTPUT ;
    USE SIGNAL ;
    PORT
      LAYER M5 ;
        RECT  41.232 0 41.256 0.084 ;
    END
  END emb_m[86]
  PIN emb_m[87]
    DIRECTION OUTPUT ;
    USE SIGNAL ;
    PORT
      LAYER M5 ;
        RECT  41.328 0 41.352 0.084 ;
    END
  END emb_m[87]
  PIN emb_m[88]
    DIRECTION OUTPUT ;
    USE SIGNAL ;
    PORT
      LAYER M5 ;
        RECT  41.424 0 41.448 0.084 ;
    END
  END emb_m[88]
  PIN emb_m[89]
    DIRECTION OUTPUT ;
    USE SIGNAL ;
    PORT
      LAYER M5 ;
        RECT  41.52 0 41.544 0.084 ;
    END
  END emb_m[89]
  PIN emb_m[8]
    DIRECTION OUTPUT ;
    USE SIGNAL ;
    PORT
      LAYER M5 ;
        RECT  46.032 0 46.056 0.084 ;
    END
  END emb_m[8]
  PIN emb_m[90]
    DIRECTION OUTPUT ;
    USE SIGNAL ;
    PORT
      LAYER M5 ;
        RECT  41.616 0 41.64 0.084 ;
    END
  END emb_m[90]
  PIN emb_m[91]
    DIRECTION OUTPUT ;
    USE SIGNAL ;
    PORT
      LAYER M5 ;
        RECT  41.712 0 41.736 0.084 ;
    END
  END emb_m[91]
  PIN emb_m[92]
    DIRECTION OUTPUT ;
    USE SIGNAL ;
    PORT
      LAYER M5 ;
        RECT  41.808 0 41.832 0.084 ;
    END
  END emb_m[92]
  PIN emb_m[93]
    DIRECTION OUTPUT ;
    USE SIGNAL ;
    PORT
      LAYER M5 ;
        RECT  41.904 0 41.928 0.084 ;
    END
  END emb_m[93]
  PIN emb_m[94]
    DIRECTION OUTPUT ;
    USE SIGNAL ;
    PORT
      LAYER M5 ;
        RECT  42 0 42.024 0.084 ;
    END
  END emb_m[94]
  PIN emb_m[95]
    DIRECTION OUTPUT ;
    USE SIGNAL ;
    PORT
      LAYER M5 ;
        RECT  42.096 0 42.12 0.084 ;
    END
  END emb_m[95]
  PIN emb_m[96]
    DIRECTION OUTPUT ;
    USE SIGNAL ;
    PORT
      LAYER M5 ;
        RECT  48.336 0 48.36 0.084 ;
    END
  END emb_m[96]
  PIN emb_m[97]
    DIRECTION OUTPUT ;
    USE SIGNAL ;
    PORT
      LAYER M5 ;
        RECT  48.432 0 48.456 0.084 ;
    END
  END emb_m[97]
  PIN emb_m[98]
    DIRECTION OUTPUT ;
    USE SIGNAL ;
    PORT
      LAYER M5 ;
        RECT  48.528 0 48.552 0.084 ;
    END
  END emb_m[98]
  PIN emb_m[99]
    DIRECTION OUTPUT ;
    USE SIGNAL ;
    PORT
      LAYER M5 ;
        RECT  48.624 0 48.648 0.084 ;
    END
  END emb_m[99]
  PIN emb_m[9]
    DIRECTION OUTPUT ;
    USE SIGNAL ;
    PORT
      LAYER M5 ;
        RECT  46.128 0 46.152 0.084 ;
    END
  END emb_m[9]
  PIN emb_q[0]
    DIRECTION INPUT ;
    USE SIGNAL ;
    PORT
      LAYER M5 ;
        RECT  29.232 71.196 29.256 71.28 ;
    END
  END emb_q[0]
  PIN emb_q[100]
    DIRECTION INPUT ;
    USE SIGNAL ;
    PORT
      LAYER M5 ;
        RECT  36.528 71.196 36.552 71.28 ;
    END
  END emb_q[100]
  PIN emb_q[101]
    DIRECTION INPUT ;
    USE SIGNAL ;
    PORT
      LAYER M5 ;
        RECT  36.624 71.196 36.648 71.28 ;
    END
  END emb_q[101]
  PIN emb_q[102]
    DIRECTION INPUT ;
    USE SIGNAL ;
    PORT
      LAYER M5 ;
        RECT  36.72 71.196 36.744 71.28 ;
    END
  END emb_q[102]
  PIN emb_q[103]
    DIRECTION INPUT ;
    USE SIGNAL ;
    PORT
      LAYER M5 ;
        RECT  36.816 71.196 36.84 71.28 ;
    END
  END emb_q[103]
  PIN emb_q[104]
    DIRECTION INPUT ;
    USE SIGNAL ;
    PORT
      LAYER M5 ;
        RECT  36.912 71.196 36.936 71.28 ;
    END
  END emb_q[104]
  PIN emb_q[105]
    DIRECTION INPUT ;
    USE SIGNAL ;
    PORT
      LAYER M5 ;
        RECT  37.008 71.196 37.032 71.28 ;
    END
  END emb_q[105]
  PIN emb_q[106]
    DIRECTION INPUT ;
    USE SIGNAL ;
    PORT
      LAYER M5 ;
        RECT  37.104 71.196 37.128 71.28 ;
    END
  END emb_q[106]
  PIN emb_q[107]
    DIRECTION INPUT ;
    USE SIGNAL ;
    PORT
      LAYER M5 ;
        RECT  37.2 71.196 37.224 71.28 ;
    END
  END emb_q[107]
  PIN emb_q[108]
    DIRECTION INPUT ;
    USE SIGNAL ;
    PORT
      LAYER M5 ;
        RECT  37.296 71.196 37.32 71.28 ;
    END
  END emb_q[108]
  PIN emb_q[109]
    DIRECTION INPUT ;
    USE SIGNAL ;
    PORT
      LAYER M5 ;
        RECT  37.392 71.196 37.416 71.28 ;
    END
  END emb_q[109]
  PIN emb_q[10]
    DIRECTION INPUT ;
    USE SIGNAL ;
    PORT
      LAYER M5 ;
        RECT  30.192 71.196 30.216 71.28 ;
    END
  END emb_q[10]
  PIN emb_q[110]
    DIRECTION INPUT ;
    USE SIGNAL ;
    PORT
      LAYER M5 ;
        RECT  37.488 71.196 37.512 71.28 ;
    END
  END emb_q[110]
  PIN emb_q[111]
    DIRECTION INPUT ;
    USE SIGNAL ;
    PORT
      LAYER M5 ;
        RECT  37.584 71.196 37.608 71.28 ;
    END
  END emb_q[111]
  PIN emb_q[112]
    DIRECTION INPUT ;
    USE SIGNAL ;
    PORT
      LAYER M5 ;
        RECT  37.68 71.196 37.704 71.28 ;
    END
  END emb_q[112]
  PIN emb_q[113]
    DIRECTION INPUT ;
    USE SIGNAL ;
    PORT
      LAYER M5 ;
        RECT  37.776 71.196 37.8 71.28 ;
    END
  END emb_q[113]
  PIN emb_q[114]
    DIRECTION INPUT ;
    USE SIGNAL ;
    PORT
      LAYER M5 ;
        RECT  37.872 71.196 37.896 71.28 ;
    END
  END emb_q[114]
  PIN emb_q[115]
    DIRECTION INPUT ;
    USE SIGNAL ;
    PORT
      LAYER M5 ;
        RECT  37.968 71.196 37.992 71.28 ;
    END
  END emb_q[115]
  PIN emb_q[116]
    DIRECTION INPUT ;
    USE SIGNAL ;
    PORT
      LAYER M5 ;
        RECT  38.064 71.196 38.088 71.28 ;
    END
  END emb_q[116]
  PIN emb_q[117]
    DIRECTION INPUT ;
    USE SIGNAL ;
    PORT
      LAYER M5 ;
        RECT  38.16 71.196 38.184 71.28 ;
    END
  END emb_q[117]
  PIN emb_q[118]
    DIRECTION INPUT ;
    USE SIGNAL ;
    PORT
      LAYER M5 ;
        RECT  38.256 71.196 38.28 71.28 ;
    END
  END emb_q[118]
  PIN emb_q[119]
    DIRECTION INPUT ;
    USE SIGNAL ;
    PORT
      LAYER M5 ;
        RECT  38.352 71.196 38.376 71.28 ;
    END
  END emb_q[119]
  PIN emb_q[11]
    DIRECTION INPUT ;
    USE SIGNAL ;
    PORT
      LAYER M5 ;
        RECT  30.288 71.196 30.312 71.28 ;
    END
  END emb_q[11]
  PIN emb_q[120]
    DIRECTION INPUT ;
    USE SIGNAL ;
    PORT
      LAYER M5 ;
        RECT  38.448 71.196 38.472 71.28 ;
    END
  END emb_q[120]
  PIN emb_q[121]
    DIRECTION INPUT ;
    USE SIGNAL ;
    PORT
      LAYER M5 ;
        RECT  38.544 71.196 38.568 71.28 ;
    END
  END emb_q[121]
  PIN emb_q[122]
    DIRECTION INPUT ;
    USE SIGNAL ;
    PORT
      LAYER M5 ;
        RECT  38.64 71.196 38.664 71.28 ;
    END
  END emb_q[122]
  PIN emb_q[123]
    DIRECTION INPUT ;
    USE SIGNAL ;
    PORT
      LAYER M5 ;
        RECT  38.736 71.196 38.76 71.28 ;
    END
  END emb_q[123]
  PIN emb_q[124]
    DIRECTION INPUT ;
    USE SIGNAL ;
    PORT
      LAYER M5 ;
        RECT  38.832 71.196 38.856 71.28 ;
    END
  END emb_q[124]
  PIN emb_q[125]
    DIRECTION INPUT ;
    USE SIGNAL ;
    PORT
      LAYER M5 ;
        RECT  38.928 71.196 38.952 71.28 ;
    END
  END emb_q[125]
  PIN emb_q[126]
    DIRECTION INPUT ;
    USE SIGNAL ;
    PORT
      LAYER M5 ;
        RECT  39.024 71.196 39.048 71.28 ;
    END
  END emb_q[126]
  PIN emb_q[127]
    DIRECTION INPUT ;
    USE SIGNAL ;
    PORT
      LAYER M5 ;
        RECT  40.464 71.196 40.488 71.28 ;
    END
  END emb_q[127]
  PIN emb_q[12]
    DIRECTION INPUT ;
    USE SIGNAL ;
    PORT
      LAYER M5 ;
        RECT  30.384 71.196 30.408 71.28 ;
    END
  END emb_q[12]
  PIN emb_q[13]
    DIRECTION INPUT ;
    USE SIGNAL ;
    PORT
      LAYER M5 ;
        RECT  30.48 71.196 30.504 71.28 ;
    END
  END emb_q[13]
  PIN emb_q[14]
    DIRECTION INPUT ;
    USE SIGNAL ;
    PORT
      LAYER M5 ;
        RECT  30.576 71.196 30.6 71.28 ;
    END
  END emb_q[14]
  PIN emb_q[15]
    DIRECTION INPUT ;
    USE SIGNAL ;
    PORT
      LAYER M5 ;
        RECT  30.672 71.196 30.696 71.28 ;
    END
  END emb_q[15]
  PIN emb_q[16]
    DIRECTION INPUT ;
    USE SIGNAL ;
    PORT
      LAYER M5 ;
        RECT  30.768 71.196 30.792 71.28 ;
    END
  END emb_q[16]
  PIN emb_q[17]
    DIRECTION INPUT ;
    USE SIGNAL ;
    PORT
      LAYER M5 ;
        RECT  30.864 71.196 30.888 71.28 ;
    END
  END emb_q[17]
  PIN emb_q[18]
    DIRECTION INPUT ;
    USE SIGNAL ;
    PORT
      LAYER M5 ;
        RECT  30.96 71.196 30.984 71.28 ;
    END
  END emb_q[18]
  PIN emb_q[19]
    DIRECTION INPUT ;
    USE SIGNAL ;
    PORT
      LAYER M5 ;
        RECT  31.056 71.196 31.08 71.28 ;
    END
  END emb_q[19]
  PIN emb_q[1]
    DIRECTION INPUT ;
    USE SIGNAL ;
    PORT
      LAYER M5 ;
        RECT  29.328 71.196 29.352 71.28 ;
    END
  END emb_q[1]
  PIN emb_q[20]
    DIRECTION INPUT ;
    USE SIGNAL ;
    PORT
      LAYER M5 ;
        RECT  31.152 71.196 31.176 71.28 ;
    END
  END emb_q[20]
  PIN emb_q[21]
    DIRECTION INPUT ;
    USE SIGNAL ;
    PORT
      LAYER M5 ;
        RECT  31.248 71.196 31.272 71.28 ;
    END
  END emb_q[21]
  PIN emb_q[22]
    DIRECTION INPUT ;
    USE SIGNAL ;
    PORT
      LAYER M5 ;
        RECT  31.344 71.196 31.368 71.28 ;
    END
  END emb_q[22]
  PIN emb_q[23]
    DIRECTION INPUT ;
    USE SIGNAL ;
    PORT
      LAYER M5 ;
        RECT  31.44 71.196 31.464 71.28 ;
    END
  END emb_q[23]
  PIN emb_q[24]
    DIRECTION INPUT ;
    USE SIGNAL ;
    PORT
      LAYER M5 ;
        RECT  31.536 71.196 31.56 71.28 ;
    END
  END emb_q[24]
  PIN emb_q[25]
    DIRECTION INPUT ;
    USE SIGNAL ;
    PORT
      LAYER M5 ;
        RECT  31.632 71.196 31.656 71.28 ;
    END
  END emb_q[25]
  PIN emb_q[26]
    DIRECTION INPUT ;
    USE SIGNAL ;
    PORT
      LAYER M5 ;
        RECT  31.728 71.196 31.752 71.28 ;
    END
  END emb_q[26]
  PIN emb_q[27]
    DIRECTION INPUT ;
    USE SIGNAL ;
    PORT
      LAYER M5 ;
        RECT  31.824 71.196 31.848 71.28 ;
    END
  END emb_q[27]
  PIN emb_q[28]
    DIRECTION INPUT ;
    USE SIGNAL ;
    PORT
      LAYER M5 ;
        RECT  31.92 71.196 31.944 71.28 ;
    END
  END emb_q[28]
  PIN emb_q[29]
    DIRECTION INPUT ;
    USE SIGNAL ;
    PORT
      LAYER M5 ;
        RECT  32.016 71.196 32.04 71.28 ;
    END
  END emb_q[29]
  PIN emb_q[2]
    DIRECTION INPUT ;
    USE SIGNAL ;
    PORT
      LAYER M5 ;
        RECT  29.424 71.196 29.448 71.28 ;
    END
  END emb_q[2]
  PIN emb_q[30]
    DIRECTION INPUT ;
    USE SIGNAL ;
    PORT
      LAYER M5 ;
        RECT  32.112 71.196 32.136 71.28 ;
    END
  END emb_q[30]
  PIN emb_q[31]
    DIRECTION INPUT ;
    USE SIGNAL ;
    PORT
      LAYER M5 ;
        RECT  26.064 71.196 26.088 71.28 ;
    END
  END emb_q[31]
  PIN emb_q[32]
    DIRECTION INPUT ;
    USE SIGNAL ;
    PORT
      LAYER M5 ;
        RECT  26.16 71.196 26.184 71.28 ;
    END
  END emb_q[32]
  PIN emb_q[33]
    DIRECTION INPUT ;
    USE SIGNAL ;
    PORT
      LAYER M5 ;
        RECT  26.256 71.196 26.28 71.28 ;
    END
  END emb_q[33]
  PIN emb_q[34]
    DIRECTION INPUT ;
    USE SIGNAL ;
    PORT
      LAYER M5 ;
        RECT  26.352 71.196 26.376 71.28 ;
    END
  END emb_q[34]
  PIN emb_q[35]
    DIRECTION INPUT ;
    USE SIGNAL ;
    PORT
      LAYER M5 ;
        RECT  26.448 71.196 26.472 71.28 ;
    END
  END emb_q[35]
  PIN emb_q[36]
    DIRECTION INPUT ;
    USE SIGNAL ;
    PORT
      LAYER M5 ;
        RECT  26.544 71.196 26.568 71.28 ;
    END
  END emb_q[36]
  PIN emb_q[37]
    DIRECTION INPUT ;
    USE SIGNAL ;
    PORT
      LAYER M5 ;
        RECT  26.64 71.196 26.664 71.28 ;
    END
  END emb_q[37]
  PIN emb_q[38]
    DIRECTION INPUT ;
    USE SIGNAL ;
    PORT
      LAYER M5 ;
        RECT  26.736 71.196 26.76 71.28 ;
    END
  END emb_q[38]
  PIN emb_q[39]
    DIRECTION INPUT ;
    USE SIGNAL ;
    PORT
      LAYER M5 ;
        RECT  26.832 71.196 26.856 71.28 ;
    END
  END emb_q[39]
  PIN emb_q[3]
    DIRECTION INPUT ;
    USE SIGNAL ;
    PORT
      LAYER M5 ;
        RECT  29.52 71.196 29.544 71.28 ;
    END
  END emb_q[3]
  PIN emb_q[40]
    DIRECTION INPUT ;
    USE SIGNAL ;
    PORT
      LAYER M5 ;
        RECT  26.928 71.196 26.952 71.28 ;
    END
  END emb_q[40]
  PIN emb_q[41]
    DIRECTION INPUT ;
    USE SIGNAL ;
    PORT
      LAYER M5 ;
        RECT  27.024 71.196 27.048 71.28 ;
    END
  END emb_q[41]
  PIN emb_q[42]
    DIRECTION INPUT ;
    USE SIGNAL ;
    PORT
      LAYER M5 ;
        RECT  27.12 71.196 27.144 71.28 ;
    END
  END emb_q[42]
  PIN emb_q[43]
    DIRECTION INPUT ;
    USE SIGNAL ;
    PORT
      LAYER M5 ;
        RECT  27.216 71.196 27.24 71.28 ;
    END
  END emb_q[43]
  PIN emb_q[44]
    DIRECTION INPUT ;
    USE SIGNAL ;
    PORT
      LAYER M5 ;
        RECT  27.312 71.196 27.336 71.28 ;
    END
  END emb_q[44]
  PIN emb_q[45]
    DIRECTION INPUT ;
    USE SIGNAL ;
    PORT
      LAYER M5 ;
        RECT  27.408 71.196 27.432 71.28 ;
    END
  END emb_q[45]
  PIN emb_q[46]
    DIRECTION INPUT ;
    USE SIGNAL ;
    PORT
      LAYER M5 ;
        RECT  27.504 71.196 27.528 71.28 ;
    END
  END emb_q[46]
  PIN emb_q[47]
    DIRECTION INPUT ;
    USE SIGNAL ;
    PORT
      LAYER M5 ;
        RECT  27.6 71.196 27.624 71.28 ;
    END
  END emb_q[47]
  PIN emb_q[48]
    DIRECTION INPUT ;
    USE SIGNAL ;
    PORT
      LAYER M5 ;
        RECT  27.696 71.196 27.72 71.28 ;
    END
  END emb_q[48]
  PIN emb_q[49]
    DIRECTION INPUT ;
    USE SIGNAL ;
    PORT
      LAYER M5 ;
        RECT  27.792 71.196 27.816 71.28 ;
    END
  END emb_q[49]
  PIN emb_q[4]
    DIRECTION INPUT ;
    USE SIGNAL ;
    PORT
      LAYER M5 ;
        RECT  29.616 71.196 29.64 71.28 ;
    END
  END emb_q[4]
  PIN emb_q[50]
    DIRECTION INPUT ;
    USE SIGNAL ;
    PORT
      LAYER M5 ;
        RECT  27.888 71.196 27.912 71.28 ;
    END
  END emb_q[50]
  PIN emb_q[51]
    DIRECTION INPUT ;
    USE SIGNAL ;
    PORT
      LAYER M5 ;
        RECT  27.984 71.196 28.008 71.28 ;
    END
  END emb_q[51]
  PIN emb_q[52]
    DIRECTION INPUT ;
    USE SIGNAL ;
    PORT
      LAYER M5 ;
        RECT  28.08 71.196 28.104 71.28 ;
    END
  END emb_q[52]
  PIN emb_q[53]
    DIRECTION INPUT ;
    USE SIGNAL ;
    PORT
      LAYER M5 ;
        RECT  28.176 71.196 28.2 71.28 ;
    END
  END emb_q[53]
  PIN emb_q[54]
    DIRECTION INPUT ;
    USE SIGNAL ;
    PORT
      LAYER M5 ;
        RECT  28.272 71.196 28.296 71.28 ;
    END
  END emb_q[54]
  PIN emb_q[55]
    DIRECTION INPUT ;
    USE SIGNAL ;
    PORT
      LAYER M5 ;
        RECT  28.368 71.196 28.392 71.28 ;
    END
  END emb_q[55]
  PIN emb_q[56]
    DIRECTION INPUT ;
    USE SIGNAL ;
    PORT
      LAYER M5 ;
        RECT  28.464 71.196 28.488 71.28 ;
    END
  END emb_q[56]
  PIN emb_q[57]
    DIRECTION INPUT ;
    USE SIGNAL ;
    PORT
      LAYER M5 ;
        RECT  28.56 71.196 28.584 71.28 ;
    END
  END emb_q[57]
  PIN emb_q[58]
    DIRECTION INPUT ;
    USE SIGNAL ;
    PORT
      LAYER M5 ;
        RECT  28.656 71.196 28.68 71.28 ;
    END
  END emb_q[58]
  PIN emb_q[59]
    DIRECTION INPUT ;
    USE SIGNAL ;
    PORT
      LAYER M5 ;
        RECT  28.752 71.196 28.776 71.28 ;
    END
  END emb_q[59]
  PIN emb_q[5]
    DIRECTION INPUT ;
    USE SIGNAL ;
    PORT
      LAYER M5 ;
        RECT  29.712 71.196 29.736 71.28 ;
    END
  END emb_q[5]
  PIN emb_q[60]
    DIRECTION INPUT ;
    USE SIGNAL ;
    PORT
      LAYER M5 ;
        RECT  28.848 71.196 28.872 71.28 ;
    END
  END emb_q[60]
  PIN emb_q[61]
    DIRECTION INPUT ;
    USE SIGNAL ;
    PORT
      LAYER M5 ;
        RECT  28.944 71.196 28.968 71.28 ;
    END
  END emb_q[61]
  PIN emb_q[62]
    DIRECTION INPUT ;
    USE SIGNAL ;
    PORT
      LAYER M5 ;
        RECT  29.04 71.196 29.064 71.28 ;
    END
  END emb_q[62]
  PIN emb_q[63]
    DIRECTION INPUT ;
    USE SIGNAL ;
    PORT
      LAYER M5 ;
        RECT  32.976 71.196 33 71.28 ;
    END
  END emb_q[63]
  PIN emb_q[64]
    DIRECTION INPUT ;
    USE SIGNAL ;
    PORT
      LAYER M5 ;
        RECT  33.072 71.196 33.096 71.28 ;
    END
  END emb_q[64]
  PIN emb_q[65]
    DIRECTION INPUT ;
    USE SIGNAL ;
    PORT
      LAYER M5 ;
        RECT  33.168 71.196 33.192 71.28 ;
    END
  END emb_q[65]
  PIN emb_q[66]
    DIRECTION INPUT ;
    USE SIGNAL ;
    PORT
      LAYER M5 ;
        RECT  33.264 71.196 33.288 71.28 ;
    END
  END emb_q[66]
  PIN emb_q[67]
    DIRECTION INPUT ;
    USE SIGNAL ;
    PORT
      LAYER M5 ;
        RECT  33.36 71.196 33.384 71.28 ;
    END
  END emb_q[67]
  PIN emb_q[68]
    DIRECTION INPUT ;
    USE SIGNAL ;
    PORT
      LAYER M5 ;
        RECT  33.456 71.196 33.48 71.28 ;
    END
  END emb_q[68]
  PIN emb_q[69]
    DIRECTION INPUT ;
    USE SIGNAL ;
    PORT
      LAYER M5 ;
        RECT  33.552 71.196 33.576 71.28 ;
    END
  END emb_q[69]
  PIN emb_q[6]
    DIRECTION INPUT ;
    USE SIGNAL ;
    PORT
      LAYER M5 ;
        RECT  29.808 71.196 29.832 71.28 ;
    END
  END emb_q[6]
  PIN emb_q[70]
    DIRECTION INPUT ;
    USE SIGNAL ;
    PORT
      LAYER M5 ;
        RECT  33.648 71.196 33.672 71.28 ;
    END
  END emb_q[70]
  PIN emb_q[71]
    DIRECTION INPUT ;
    USE SIGNAL ;
    PORT
      LAYER M5 ;
        RECT  33.744 71.196 33.768 71.28 ;
    END
  END emb_q[71]
  PIN emb_q[72]
    DIRECTION INPUT ;
    USE SIGNAL ;
    PORT
      LAYER M5 ;
        RECT  33.84 71.196 33.864 71.28 ;
    END
  END emb_q[72]
  PIN emb_q[73]
    DIRECTION INPUT ;
    USE SIGNAL ;
    PORT
      LAYER M5 ;
        RECT  33.936 71.196 33.96 71.28 ;
    END
  END emb_q[73]
  PIN emb_q[74]
    DIRECTION INPUT ;
    USE SIGNAL ;
    PORT
      LAYER M5 ;
        RECT  34.032 71.196 34.056 71.28 ;
    END
  END emb_q[74]
  PIN emb_q[75]
    DIRECTION INPUT ;
    USE SIGNAL ;
    PORT
      LAYER M5 ;
        RECT  34.128 71.196 34.152 71.28 ;
    END
  END emb_q[75]
  PIN emb_q[76]
    DIRECTION INPUT ;
    USE SIGNAL ;
    PORT
      LAYER M5 ;
        RECT  34.224 71.196 34.248 71.28 ;
    END
  END emb_q[76]
  PIN emb_q[77]
    DIRECTION INPUT ;
    USE SIGNAL ;
    PORT
      LAYER M5 ;
        RECT  34.32 71.196 34.344 71.28 ;
    END
  END emb_q[77]
  PIN emb_q[78]
    DIRECTION INPUT ;
    USE SIGNAL ;
    PORT
      LAYER M5 ;
        RECT  34.416 71.196 34.44 71.28 ;
    END
  END emb_q[78]
  PIN emb_q[79]
    DIRECTION INPUT ;
    USE SIGNAL ;
    PORT
      LAYER M5 ;
        RECT  34.512 71.196 34.536 71.28 ;
    END
  END emb_q[79]
  PIN emb_q[7]
    DIRECTION INPUT ;
    USE SIGNAL ;
    PORT
      LAYER M5 ;
        RECT  29.904 71.196 29.928 71.28 ;
    END
  END emb_q[7]
  PIN emb_q[80]
    DIRECTION INPUT ;
    USE SIGNAL ;
    PORT
      LAYER M5 ;
        RECT  34.608 71.196 34.632 71.28 ;
    END
  END emb_q[80]
  PIN emb_q[81]
    DIRECTION INPUT ;
    USE SIGNAL ;
    PORT
      LAYER M5 ;
        RECT  34.704 71.196 34.728 71.28 ;
    END
  END emb_q[81]
  PIN emb_q[82]
    DIRECTION INPUT ;
    USE SIGNAL ;
    PORT
      LAYER M5 ;
        RECT  34.8 71.196 34.824 71.28 ;
    END
  END emb_q[82]
  PIN emb_q[83]
    DIRECTION INPUT ;
    USE SIGNAL ;
    PORT
      LAYER M5 ;
        RECT  34.896 71.196 34.92 71.28 ;
    END
  END emb_q[83]
  PIN emb_q[84]
    DIRECTION INPUT ;
    USE SIGNAL ;
    PORT
      LAYER M5 ;
        RECT  34.992 71.196 35.016 71.28 ;
    END
  END emb_q[84]
  PIN emb_q[85]
    DIRECTION INPUT ;
    USE SIGNAL ;
    PORT
      LAYER M5 ;
        RECT  35.088 71.196 35.112 71.28 ;
    END
  END emb_q[85]
  PIN emb_q[86]
    DIRECTION INPUT ;
    USE SIGNAL ;
    PORT
      LAYER M5 ;
        RECT  35.184 71.196 35.208 71.28 ;
    END
  END emb_q[86]
  PIN emb_q[87]
    DIRECTION INPUT ;
    USE SIGNAL ;
    PORT
      LAYER M5 ;
        RECT  35.28 71.196 35.304 71.28 ;
    END
  END emb_q[87]
  PIN emb_q[88]
    DIRECTION INPUT ;
    USE SIGNAL ;
    PORT
      LAYER M5 ;
        RECT  35.376 71.196 35.4 71.28 ;
    END
  END emb_q[88]
  PIN emb_q[89]
    DIRECTION INPUT ;
    USE SIGNAL ;
    PORT
      LAYER M5 ;
        RECT  35.472 71.196 35.496 71.28 ;
    END
  END emb_q[89]
  PIN emb_q[8]
    DIRECTION INPUT ;
    USE SIGNAL ;
    PORT
      LAYER M5 ;
        RECT  30 71.196 30.024 71.28 ;
    END
  END emb_q[8]
  PIN emb_q[90]
    DIRECTION INPUT ;
    USE SIGNAL ;
    PORT
      LAYER M5 ;
        RECT  35.568 71.196 35.592 71.28 ;
    END
  END emb_q[90]
  PIN emb_q[91]
    DIRECTION INPUT ;
    USE SIGNAL ;
    PORT
      LAYER M5 ;
        RECT  35.664 71.196 35.688 71.28 ;
    END
  END emb_q[91]
  PIN emb_q[92]
    DIRECTION INPUT ;
    USE SIGNAL ;
    PORT
      LAYER M5 ;
        RECT  35.76 71.196 35.784 71.28 ;
    END
  END emb_q[92]
  PIN emb_q[93]
    DIRECTION INPUT ;
    USE SIGNAL ;
    PORT
      LAYER M5 ;
        RECT  35.856 71.196 35.88 71.28 ;
    END
  END emb_q[93]
  PIN emb_q[94]
    DIRECTION INPUT ;
    USE SIGNAL ;
    PORT
      LAYER M5 ;
        RECT  35.952 71.196 35.976 71.28 ;
    END
  END emb_q[94]
  PIN emb_q[95]
    DIRECTION INPUT ;
    USE SIGNAL ;
    PORT
      LAYER M5 ;
        RECT  36.048 71.196 36.072 71.28 ;
    END
  END emb_q[95]
  PIN emb_q[96]
    DIRECTION INPUT ;
    USE SIGNAL ;
    PORT
      LAYER M5 ;
        RECT  36.144 71.196 36.168 71.28 ;
    END
  END emb_q[96]
  PIN emb_q[97]
    DIRECTION INPUT ;
    USE SIGNAL ;
    PORT
      LAYER M5 ;
        RECT  36.24 71.196 36.264 71.28 ;
    END
  END emb_q[97]
  PIN emb_q[98]
    DIRECTION INPUT ;
    USE SIGNAL ;
    PORT
      LAYER M5 ;
        RECT  36.336 71.196 36.36 71.28 ;
    END
  END emb_q[98]
  PIN emb_q[99]
    DIRECTION INPUT ;
    USE SIGNAL ;
    PORT
      LAYER M5 ;
        RECT  36.432 71.196 36.456 71.28 ;
    END
  END emb_q[99]
  PIN emb_q[9]
    DIRECTION INPUT ;
    USE SIGNAL ;
    PORT
      LAYER M5 ;
        RECT  30.096 71.196 30.12 71.28 ;
    END
  END emb_q[9]
  PIN emb_sel[0]
    DIRECTION INPUT ;
    USE SIGNAL ;
    PORT
      LAYER M5 ;
        RECT  40.56 71.196 40.584 71.28 ;
    END
  END emb_sel[0]
  PIN emb_sel[1]
    DIRECTION INPUT ;
    USE SIGNAL ;
    PORT
      LAYER M5 ;
        RECT  40.656 71.196 40.68 71.28 ;
    END
  END emb_sel[1]
  PIN emb_sel[2]
    DIRECTION INPUT ;
    USE SIGNAL ;
    PORT
      LAYER M5 ;
        RECT  40.752 71.196 40.776 71.28 ;
    END
  END emb_sel[2]
  PIN emb_sel[3]
    DIRECTION INPUT ;
    USE SIGNAL ;
    PORT
      LAYER M5 ;
        RECT  40.848 71.196 40.872 71.28 ;
    END
  END emb_sel[3]
  PIN emb_sel_m[0]
    DIRECTION OUTPUT ;
    USE SIGNAL ;
    PORT
      LAYER M5 ;
        RECT  35.28 0 35.304 0.084 ;
    END
  END emb_sel_m[0]
  PIN emb_sel_m[1]
    DIRECTION OUTPUT ;
    USE SIGNAL ;
    PORT
      LAYER M5 ;
        RECT  35.376 0 35.4 0.084 ;
    END
  END emb_sel_m[1]
  PIN emb_sel_m[2]
    DIRECTION OUTPUT ;
    USE SIGNAL ;
    PORT
      LAYER M5 ;
        RECT  35.472 0 35.496 0.084 ;
    END
  END emb_sel_m[2]
  PIN emb_sel_m[3]
    DIRECTION OUTPUT ;
    USE SIGNAL ;
    PORT
      LAYER M5 ;
        RECT  35.568 0 35.592 0.084 ;
    END
  END emb_sel_m[3]
  PIN rst_n
    DIRECTION INPUT ;
    USE SIGNAL ;
    PORT
      LAYER M5 ;
        RECT  40.944 71.196 40.968 71.28 ;
    END
  END rst_n
  PIN vm_eff[0]
    DIRECTION OUTPUT ;
    USE SIGNAL ;
    PORT
      LAYER M4 ;
        RECT  71.196 19.92 71.28 19.944 ;
    END
  END vm_eff[0]
  PIN vm_eff[100]
    DIRECTION OUTPUT ;
    USE SIGNAL ;
    PORT
      LAYER M4 ;
        RECT  71.196 23.376 71.28 23.4 ;
    END
  END vm_eff[100]
  PIN vm_eff[101]
    DIRECTION OUTPUT ;
    USE SIGNAL ;
    PORT
      LAYER M4 ;
        RECT  71.196 23.472 71.28 23.496 ;
    END
  END vm_eff[101]
  PIN vm_eff[102]
    DIRECTION OUTPUT ;
    USE SIGNAL ;
    PORT
      LAYER M4 ;
        RECT  71.196 23.568 71.28 23.592 ;
    END
  END vm_eff[102]
  PIN vm_eff[103]
    DIRECTION OUTPUT ;
    USE SIGNAL ;
    PORT
      LAYER M4 ;
        RECT  71.196 23.664 71.28 23.688 ;
    END
  END vm_eff[103]
  PIN vm_eff[104]
    DIRECTION OUTPUT ;
    USE SIGNAL ;
    PORT
      LAYER M4 ;
        RECT  71.196 23.76 71.28 23.784 ;
    END
  END vm_eff[104]
  PIN vm_eff[105]
    DIRECTION OUTPUT ;
    USE SIGNAL ;
    PORT
      LAYER M4 ;
        RECT  71.196 23.856 71.28 23.88 ;
    END
  END vm_eff[105]
  PIN vm_eff[106]
    DIRECTION OUTPUT ;
    USE SIGNAL ;
    PORT
      LAYER M4 ;
        RECT  71.196 23.952 71.28 23.976 ;
    END
  END vm_eff[106]
  PIN vm_eff[107]
    DIRECTION OUTPUT ;
    USE SIGNAL ;
    PORT
      LAYER M4 ;
        RECT  71.196 24.048 71.28 24.072 ;
    END
  END vm_eff[107]
  PIN vm_eff[108]
    DIRECTION OUTPUT ;
    USE SIGNAL ;
    PORT
      LAYER M4 ;
        RECT  71.196 24.144 71.28 24.168 ;
    END
  END vm_eff[108]
  PIN vm_eff[109]
    DIRECTION OUTPUT ;
    USE SIGNAL ;
    PORT
      LAYER M4 ;
        RECT  71.196 24.24 71.28 24.264 ;
    END
  END vm_eff[109]
  PIN vm_eff[10]
    DIRECTION OUTPUT ;
    USE SIGNAL ;
    PORT
      LAYER M4 ;
        RECT  71.196 20.88 71.28 20.904 ;
    END
  END vm_eff[10]
  PIN vm_eff[110]
    DIRECTION OUTPUT ;
    USE SIGNAL ;
    PORT
      LAYER M4 ;
        RECT  71.196 24.336 71.28 24.36 ;
    END
  END vm_eff[110]
  PIN vm_eff[111]
    DIRECTION OUTPUT ;
    USE SIGNAL ;
    PORT
      LAYER M4 ;
        RECT  71.196 24.432 71.28 24.456 ;
    END
  END vm_eff[111]
  PIN vm_eff[112]
    DIRECTION OUTPUT ;
    USE SIGNAL ;
    PORT
      LAYER M4 ;
        RECT  71.196 24.528 71.28 24.552 ;
    END
  END vm_eff[112]
  PIN vm_eff[113]
    DIRECTION OUTPUT ;
    USE SIGNAL ;
    PORT
      LAYER M4 ;
        RECT  71.196 24.624 71.28 24.648 ;
    END
  END vm_eff[113]
  PIN vm_eff[114]
    DIRECTION OUTPUT ;
    USE SIGNAL ;
    PORT
      LAYER M4 ;
        RECT  71.196 24.72 71.28 24.744 ;
    END
  END vm_eff[114]
  PIN vm_eff[115]
    DIRECTION OUTPUT ;
    USE SIGNAL ;
    PORT
      LAYER M4 ;
        RECT  71.196 24.816 71.28 24.84 ;
    END
  END vm_eff[115]
  PIN vm_eff[116]
    DIRECTION OUTPUT ;
    USE SIGNAL ;
    PORT
      LAYER M4 ;
        RECT  71.196 24.912 71.28 24.936 ;
    END
  END vm_eff[116]
  PIN vm_eff[117]
    DIRECTION OUTPUT ;
    USE SIGNAL ;
    PORT
      LAYER M4 ;
        RECT  71.196 25.008 71.28 25.032 ;
    END
  END vm_eff[117]
  PIN vm_eff[118]
    DIRECTION OUTPUT ;
    USE SIGNAL ;
    PORT
      LAYER M4 ;
        RECT  71.196 25.104 71.28 25.128 ;
    END
  END vm_eff[118]
  PIN vm_eff[119]
    DIRECTION OUTPUT ;
    USE SIGNAL ;
    PORT
      LAYER M4 ;
        RECT  71.196 25.2 71.28 25.224 ;
    END
  END vm_eff[119]
  PIN vm_eff[11]
    DIRECTION OUTPUT ;
    USE SIGNAL ;
    PORT
      LAYER M4 ;
        RECT  71.196 20.976 71.28 21 ;
    END
  END vm_eff[11]
  PIN vm_eff[120]
    DIRECTION OUTPUT ;
    USE SIGNAL ;
    PORT
      LAYER M4 ;
        RECT  71.196 25.296 71.28 25.32 ;
    END
  END vm_eff[120]
  PIN vm_eff[121]
    DIRECTION OUTPUT ;
    USE SIGNAL ;
    PORT
      LAYER M4 ;
        RECT  71.196 25.392 71.28 25.416 ;
    END
  END vm_eff[121]
  PIN vm_eff[122]
    DIRECTION OUTPUT ;
    USE SIGNAL ;
    PORT
      LAYER M4 ;
        RECT  71.196 25.488 71.28 25.512 ;
    END
  END vm_eff[122]
  PIN vm_eff[123]
    DIRECTION OUTPUT ;
    USE SIGNAL ;
    PORT
      LAYER M4 ;
        RECT  71.196 25.584 71.28 25.608 ;
    END
  END vm_eff[123]
  PIN vm_eff[124]
    DIRECTION OUTPUT ;
    USE SIGNAL ;
    PORT
      LAYER M4 ;
        RECT  71.196 25.68 71.28 25.704 ;
    END
  END vm_eff[124]
  PIN vm_eff[125]
    DIRECTION OUTPUT ;
    USE SIGNAL ;
    PORT
      LAYER M4 ;
        RECT  71.196 25.776 71.28 25.8 ;
    END
  END vm_eff[125]
  PIN vm_eff[126]
    DIRECTION OUTPUT ;
    USE SIGNAL ;
    PORT
      LAYER M4 ;
        RECT  71.196 25.872 71.28 25.896 ;
    END
  END vm_eff[126]
  PIN vm_eff[127]
    DIRECTION OUTPUT ;
    USE SIGNAL ;
    PORT
      LAYER M4 ;
        RECT  71.196 25.968 71.28 25.992 ;
    END
  END vm_eff[127]
  PIN vm_eff[128]
    DIRECTION OUTPUT ;
    USE SIGNAL ;
    PORT
      LAYER M4 ;
        RECT  71.196 26.064 71.28 26.088 ;
    END
  END vm_eff[128]
  PIN vm_eff[129]
    DIRECTION OUTPUT ;
    USE SIGNAL ;
    PORT
      LAYER M4 ;
        RECT  71.196 26.16 71.28 26.184 ;
    END
  END vm_eff[129]
  PIN vm_eff[12]
    DIRECTION OUTPUT ;
    USE SIGNAL ;
    PORT
      LAYER M4 ;
        RECT  71.196 21.072 71.28 21.096 ;
    END
  END vm_eff[12]
  PIN vm_eff[130]
    DIRECTION OUTPUT ;
    USE SIGNAL ;
    PORT
      LAYER M4 ;
        RECT  71.196 26.256 71.28 26.28 ;
    END
  END vm_eff[130]
  PIN vm_eff[131]
    DIRECTION OUTPUT ;
    USE SIGNAL ;
    PORT
      LAYER M4 ;
        RECT  71.196 26.352 71.28 26.376 ;
    END
  END vm_eff[131]
  PIN vm_eff[132]
    DIRECTION OUTPUT ;
    USE SIGNAL ;
    PORT
      LAYER M4 ;
        RECT  71.196 26.448 71.28 26.472 ;
    END
  END vm_eff[132]
  PIN vm_eff[133]
    DIRECTION OUTPUT ;
    USE SIGNAL ;
    PORT
      LAYER M4 ;
        RECT  71.196 26.544 71.28 26.568 ;
    END
  END vm_eff[133]
  PIN vm_eff[134]
    DIRECTION OUTPUT ;
    USE SIGNAL ;
    PORT
      LAYER M4 ;
        RECT  71.196 26.64 71.28 26.664 ;
    END
  END vm_eff[134]
  PIN vm_eff[135]
    DIRECTION OUTPUT ;
    USE SIGNAL ;
    PORT
      LAYER M4 ;
        RECT  71.196 26.736 71.28 26.76 ;
    END
  END vm_eff[135]
  PIN vm_eff[136]
    DIRECTION OUTPUT ;
    USE SIGNAL ;
    PORT
      LAYER M4 ;
        RECT  71.196 26.832 71.28 26.856 ;
    END
  END vm_eff[136]
  PIN vm_eff[137]
    DIRECTION OUTPUT ;
    USE SIGNAL ;
    PORT
      LAYER M4 ;
        RECT  71.196 26.928 71.28 26.952 ;
    END
  END vm_eff[137]
  PIN vm_eff[138]
    DIRECTION OUTPUT ;
    USE SIGNAL ;
    PORT
      LAYER M4 ;
        RECT  71.196 27.024 71.28 27.048 ;
    END
  END vm_eff[138]
  PIN vm_eff[139]
    DIRECTION OUTPUT ;
    USE SIGNAL ;
    PORT
      LAYER M4 ;
        RECT  71.196 27.12 71.28 27.144 ;
    END
  END vm_eff[139]
  PIN vm_eff[13]
    DIRECTION OUTPUT ;
    USE SIGNAL ;
    PORT
      LAYER M4 ;
        RECT  71.196 21.168 71.28 21.192 ;
    END
  END vm_eff[13]
  PIN vm_eff[140]
    DIRECTION OUTPUT ;
    USE SIGNAL ;
    PORT
      LAYER M4 ;
        RECT  71.196 27.216 71.28 27.24 ;
    END
  END vm_eff[140]
  PIN vm_eff[141]
    DIRECTION OUTPUT ;
    USE SIGNAL ;
    PORT
      LAYER M4 ;
        RECT  71.196 27.312 71.28 27.336 ;
    END
  END vm_eff[141]
  PIN vm_eff[142]
    DIRECTION OUTPUT ;
    USE SIGNAL ;
    PORT
      LAYER M4 ;
        RECT  71.196 27.408 71.28 27.432 ;
    END
  END vm_eff[142]
  PIN vm_eff[143]
    DIRECTION OUTPUT ;
    USE SIGNAL ;
    PORT
      LAYER M4 ;
        RECT  71.196 27.504 71.28 27.528 ;
    END
  END vm_eff[143]
  PIN vm_eff[144]
    DIRECTION OUTPUT ;
    USE SIGNAL ;
    PORT
      LAYER M4 ;
        RECT  71.196 27.6 71.28 27.624 ;
    END
  END vm_eff[144]
  PIN vm_eff[145]
    DIRECTION OUTPUT ;
    USE SIGNAL ;
    PORT
      LAYER M4 ;
        RECT  71.196 27.696 71.28 27.72 ;
    END
  END vm_eff[145]
  PIN vm_eff[146]
    DIRECTION OUTPUT ;
    USE SIGNAL ;
    PORT
      LAYER M4 ;
        RECT  71.196 27.792 71.28 27.816 ;
    END
  END vm_eff[146]
  PIN vm_eff[147]
    DIRECTION OUTPUT ;
    USE SIGNAL ;
    PORT
      LAYER M4 ;
        RECT  71.196 27.888 71.28 27.912 ;
    END
  END vm_eff[147]
  PIN vm_eff[148]
    DIRECTION OUTPUT ;
    USE SIGNAL ;
    PORT
      LAYER M4 ;
        RECT  71.196 27.984 71.28 28.008 ;
    END
  END vm_eff[148]
  PIN vm_eff[149]
    DIRECTION OUTPUT ;
    USE SIGNAL ;
    PORT
      LAYER M4 ;
        RECT  71.196 28.08 71.28 28.104 ;
    END
  END vm_eff[149]
  PIN vm_eff[14]
    DIRECTION OUTPUT ;
    USE SIGNAL ;
    PORT
      LAYER M4 ;
        RECT  71.196 21.264 71.28 21.288 ;
    END
  END vm_eff[14]
  PIN vm_eff[150]
    DIRECTION OUTPUT ;
    USE SIGNAL ;
    PORT
      LAYER M4 ;
        RECT  71.196 28.176 71.28 28.2 ;
    END
  END vm_eff[150]
  PIN vm_eff[151]
    DIRECTION OUTPUT ;
    USE SIGNAL ;
    PORT
      LAYER M4 ;
        RECT  71.196 28.272 71.28 28.296 ;
    END
  END vm_eff[151]
  PIN vm_eff[152]
    DIRECTION OUTPUT ;
    USE SIGNAL ;
    PORT
      LAYER M4 ;
        RECT  71.196 28.368 71.28 28.392 ;
    END
  END vm_eff[152]
  PIN vm_eff[153]
    DIRECTION OUTPUT ;
    USE SIGNAL ;
    PORT
      LAYER M4 ;
        RECT  71.196 28.464 71.28 28.488 ;
    END
  END vm_eff[153]
  PIN vm_eff[154]
    DIRECTION OUTPUT ;
    USE SIGNAL ;
    PORT
      LAYER M4 ;
        RECT  71.196 28.56 71.28 28.584 ;
    END
  END vm_eff[154]
  PIN vm_eff[155]
    DIRECTION OUTPUT ;
    USE SIGNAL ;
    PORT
      LAYER M4 ;
        RECT  71.196 28.656 71.28 28.68 ;
    END
  END vm_eff[155]
  PIN vm_eff[156]
    DIRECTION OUTPUT ;
    USE SIGNAL ;
    PORT
      LAYER M4 ;
        RECT  71.196 28.752 71.28 28.776 ;
    END
  END vm_eff[156]
  PIN vm_eff[157]
    DIRECTION OUTPUT ;
    USE SIGNAL ;
    PORT
      LAYER M4 ;
        RECT  71.196 28.848 71.28 28.872 ;
    END
  END vm_eff[157]
  PIN vm_eff[158]
    DIRECTION OUTPUT ;
    USE SIGNAL ;
    PORT
      LAYER M4 ;
        RECT  71.196 28.944 71.28 28.968 ;
    END
  END vm_eff[158]
  PIN vm_eff[159]
    DIRECTION OUTPUT ;
    USE SIGNAL ;
    PORT
      LAYER M4 ;
        RECT  71.196 29.04 71.28 29.064 ;
    END
  END vm_eff[159]
  PIN vm_eff[15]
    DIRECTION OUTPUT ;
    USE SIGNAL ;
    PORT
      LAYER M4 ;
        RECT  71.196 21.36 71.28 21.384 ;
    END
  END vm_eff[15]
  PIN vm_eff[160]
    DIRECTION OUTPUT ;
    USE SIGNAL ;
    PORT
      LAYER M4 ;
        RECT  71.196 48.336 71.28 48.36 ;
    END
  END vm_eff[160]
  PIN vm_eff[161]
    DIRECTION OUTPUT ;
    USE SIGNAL ;
    PORT
      LAYER M4 ;
        RECT  71.196 48.432 71.28 48.456 ;
    END
  END vm_eff[161]
  PIN vm_eff[162]
    DIRECTION OUTPUT ;
    USE SIGNAL ;
    PORT
      LAYER M4 ;
        RECT  71.196 48.528 71.28 48.552 ;
    END
  END vm_eff[162]
  PIN vm_eff[163]
    DIRECTION OUTPUT ;
    USE SIGNAL ;
    PORT
      LAYER M4 ;
        RECT  71.196 48.624 71.28 48.648 ;
    END
  END vm_eff[163]
  PIN vm_eff[164]
    DIRECTION OUTPUT ;
    USE SIGNAL ;
    PORT
      LAYER M4 ;
        RECT  71.196 48.72 71.28 48.744 ;
    END
  END vm_eff[164]
  PIN vm_eff[165]
    DIRECTION OUTPUT ;
    USE SIGNAL ;
    PORT
      LAYER M4 ;
        RECT  71.196 48.816 71.28 48.84 ;
    END
  END vm_eff[165]
  PIN vm_eff[166]
    DIRECTION OUTPUT ;
    USE SIGNAL ;
    PORT
      LAYER M4 ;
        RECT  71.196 48.912 71.28 48.936 ;
    END
  END vm_eff[166]
  PIN vm_eff[167]
    DIRECTION OUTPUT ;
    USE SIGNAL ;
    PORT
      LAYER M4 ;
        RECT  71.196 49.008 71.28 49.032 ;
    END
  END vm_eff[167]
  PIN vm_eff[168]
    DIRECTION OUTPUT ;
    USE SIGNAL ;
    PORT
      LAYER M4 ;
        RECT  71.196 49.104 71.28 49.128 ;
    END
  END vm_eff[168]
  PIN vm_eff[169]
    DIRECTION OUTPUT ;
    USE SIGNAL ;
    PORT
      LAYER M4 ;
        RECT  71.196 49.2 71.28 49.224 ;
    END
  END vm_eff[169]
  PIN vm_eff[16]
    DIRECTION OUTPUT ;
    USE SIGNAL ;
    PORT
      LAYER M4 ;
        RECT  71.196 21.456 71.28 21.48 ;
    END
  END vm_eff[16]
  PIN vm_eff[170]
    DIRECTION OUTPUT ;
    USE SIGNAL ;
    PORT
      LAYER M4 ;
        RECT  71.196 49.296 71.28 49.32 ;
    END
  END vm_eff[170]
  PIN vm_eff[171]
    DIRECTION OUTPUT ;
    USE SIGNAL ;
    PORT
      LAYER M4 ;
        RECT  71.196 49.392 71.28 49.416 ;
    END
  END vm_eff[171]
  PIN vm_eff[172]
    DIRECTION OUTPUT ;
    USE SIGNAL ;
    PORT
      LAYER M4 ;
        RECT  71.196 49.488 71.28 49.512 ;
    END
  END vm_eff[172]
  PIN vm_eff[173]
    DIRECTION OUTPUT ;
    USE SIGNAL ;
    PORT
      LAYER M4 ;
        RECT  71.196 49.584 71.28 49.608 ;
    END
  END vm_eff[173]
  PIN vm_eff[174]
    DIRECTION OUTPUT ;
    USE SIGNAL ;
    PORT
      LAYER M4 ;
        RECT  71.196 49.68 71.28 49.704 ;
    END
  END vm_eff[174]
  PIN vm_eff[175]
    DIRECTION OUTPUT ;
    USE SIGNAL ;
    PORT
      LAYER M4 ;
        RECT  71.196 49.776 71.28 49.8 ;
    END
  END vm_eff[175]
  PIN vm_eff[176]
    DIRECTION OUTPUT ;
    USE SIGNAL ;
    PORT
      LAYER M4 ;
        RECT  71.196 49.872 71.28 49.896 ;
    END
  END vm_eff[176]
  PIN vm_eff[177]
    DIRECTION OUTPUT ;
    USE SIGNAL ;
    PORT
      LAYER M4 ;
        RECT  71.196 49.968 71.28 49.992 ;
    END
  END vm_eff[177]
  PIN vm_eff[178]
    DIRECTION OUTPUT ;
    USE SIGNAL ;
    PORT
      LAYER M4 ;
        RECT  71.196 50.064 71.28 50.088 ;
    END
  END vm_eff[178]
  PIN vm_eff[179]
    DIRECTION OUTPUT ;
    USE SIGNAL ;
    PORT
      LAYER M4 ;
        RECT  71.196 50.16 71.28 50.184 ;
    END
  END vm_eff[179]
  PIN vm_eff[17]
    DIRECTION OUTPUT ;
    USE SIGNAL ;
    PORT
      LAYER M4 ;
        RECT  71.196 21.552 71.28 21.576 ;
    END
  END vm_eff[17]
  PIN vm_eff[180]
    DIRECTION OUTPUT ;
    USE SIGNAL ;
    PORT
      LAYER M4 ;
        RECT  71.196 50.256 71.28 50.28 ;
    END
  END vm_eff[180]
  PIN vm_eff[181]
    DIRECTION OUTPUT ;
    USE SIGNAL ;
    PORT
      LAYER M4 ;
        RECT  71.196 50.352 71.28 50.376 ;
    END
  END vm_eff[181]
  PIN vm_eff[182]
    DIRECTION OUTPUT ;
    USE SIGNAL ;
    PORT
      LAYER M4 ;
        RECT  71.196 50.448 71.28 50.472 ;
    END
  END vm_eff[182]
  PIN vm_eff[183]
    DIRECTION OUTPUT ;
    USE SIGNAL ;
    PORT
      LAYER M4 ;
        RECT  71.196 50.544 71.28 50.568 ;
    END
  END vm_eff[183]
  PIN vm_eff[184]
    DIRECTION OUTPUT ;
    USE SIGNAL ;
    PORT
      LAYER M4 ;
        RECT  71.196 50.64 71.28 50.664 ;
    END
  END vm_eff[184]
  PIN vm_eff[185]
    DIRECTION OUTPUT ;
    USE SIGNAL ;
    PORT
      LAYER M4 ;
        RECT  71.196 50.736 71.28 50.76 ;
    END
  END vm_eff[185]
  PIN vm_eff[186]
    DIRECTION OUTPUT ;
    USE SIGNAL ;
    PORT
      LAYER M4 ;
        RECT  71.196 50.832 71.28 50.856 ;
    END
  END vm_eff[186]
  PIN vm_eff[187]
    DIRECTION OUTPUT ;
    USE SIGNAL ;
    PORT
      LAYER M4 ;
        RECT  71.196 50.928 71.28 50.952 ;
    END
  END vm_eff[187]
  PIN vm_eff[188]
    DIRECTION OUTPUT ;
    USE SIGNAL ;
    PORT
      LAYER M4 ;
        RECT  71.196 51.024 71.28 51.048 ;
    END
  END vm_eff[188]
  PIN vm_eff[189]
    DIRECTION OUTPUT ;
    USE SIGNAL ;
    PORT
      LAYER M4 ;
        RECT  71.196 51.12 71.28 51.144 ;
    END
  END vm_eff[189]
  PIN vm_eff[18]
    DIRECTION OUTPUT ;
    USE SIGNAL ;
    PORT
      LAYER M4 ;
        RECT  71.196 21.648 71.28 21.672 ;
    END
  END vm_eff[18]
  PIN vm_eff[190]
    DIRECTION OUTPUT ;
    USE SIGNAL ;
    PORT
      LAYER M4 ;
        RECT  71.196 51.216 71.28 51.24 ;
    END
  END vm_eff[190]
  PIN vm_eff[191]
    DIRECTION OUTPUT ;
    USE SIGNAL ;
    PORT
      LAYER M4 ;
        RECT  71.196 51.312 71.28 51.336 ;
    END
  END vm_eff[191]
  PIN vm_eff[192]
    DIRECTION OUTPUT ;
    USE SIGNAL ;
    PORT
      LAYER M4 ;
        RECT  71.196 51.408 71.28 51.432 ;
    END
  END vm_eff[192]
  PIN vm_eff[193]
    DIRECTION OUTPUT ;
    USE SIGNAL ;
    PORT
      LAYER M4 ;
        RECT  71.196 51.504 71.28 51.528 ;
    END
  END vm_eff[193]
  PIN vm_eff[194]
    DIRECTION OUTPUT ;
    USE SIGNAL ;
    PORT
      LAYER M4 ;
        RECT  71.196 51.6 71.28 51.624 ;
    END
  END vm_eff[194]
  PIN vm_eff[195]
    DIRECTION OUTPUT ;
    USE SIGNAL ;
    PORT
      LAYER M4 ;
        RECT  71.196 51.696 71.28 51.72 ;
    END
  END vm_eff[195]
  PIN vm_eff[196]
    DIRECTION OUTPUT ;
    USE SIGNAL ;
    PORT
      LAYER M4 ;
        RECT  71.196 51.792 71.28 51.816 ;
    END
  END vm_eff[196]
  PIN vm_eff[197]
    DIRECTION OUTPUT ;
    USE SIGNAL ;
    PORT
      LAYER M4 ;
        RECT  71.196 51.888 71.28 51.912 ;
    END
  END vm_eff[197]
  PIN vm_eff[198]
    DIRECTION OUTPUT ;
    USE SIGNAL ;
    PORT
      LAYER M4 ;
        RECT  71.196 51.984 71.28 52.008 ;
    END
  END vm_eff[198]
  PIN vm_eff[199]
    DIRECTION OUTPUT ;
    USE SIGNAL ;
    PORT
      LAYER M4 ;
        RECT  71.196 52.08 71.28 52.104 ;
    END
  END vm_eff[199]
  PIN vm_eff[19]
    DIRECTION OUTPUT ;
    USE SIGNAL ;
    PORT
      LAYER M4 ;
        RECT  71.196 21.744 71.28 21.768 ;
    END
  END vm_eff[19]
  PIN vm_eff[1]
    DIRECTION OUTPUT ;
    USE SIGNAL ;
    PORT
      LAYER M4 ;
        RECT  71.196 20.016 71.28 20.04 ;
    END
  END vm_eff[1]
  PIN vm_eff[200]
    DIRECTION OUTPUT ;
    USE SIGNAL ;
    PORT
      LAYER M4 ;
        RECT  71.196 52.176 71.28 52.2 ;
    END
  END vm_eff[200]
  PIN vm_eff[201]
    DIRECTION OUTPUT ;
    USE SIGNAL ;
    PORT
      LAYER M4 ;
        RECT  71.196 52.272 71.28 52.296 ;
    END
  END vm_eff[201]
  PIN vm_eff[202]
    DIRECTION OUTPUT ;
    USE SIGNAL ;
    PORT
      LAYER M4 ;
        RECT  71.196 52.368 71.28 52.392 ;
    END
  END vm_eff[202]
  PIN vm_eff[203]
    DIRECTION OUTPUT ;
    USE SIGNAL ;
    PORT
      LAYER M4 ;
        RECT  71.196 52.464 71.28 52.488 ;
    END
  END vm_eff[203]
  PIN vm_eff[204]
    DIRECTION OUTPUT ;
    USE SIGNAL ;
    PORT
      LAYER M4 ;
        RECT  71.196 52.56 71.28 52.584 ;
    END
  END vm_eff[204]
  PIN vm_eff[205]
    DIRECTION OUTPUT ;
    USE SIGNAL ;
    PORT
      LAYER M4 ;
        RECT  71.196 52.656 71.28 52.68 ;
    END
  END vm_eff[205]
  PIN vm_eff[206]
    DIRECTION OUTPUT ;
    USE SIGNAL ;
    PORT
      LAYER M4 ;
        RECT  71.196 52.752 71.28 52.776 ;
    END
  END vm_eff[206]
  PIN vm_eff[207]
    DIRECTION OUTPUT ;
    USE SIGNAL ;
    PORT
      LAYER M4 ;
        RECT  71.196 52.848 71.28 52.872 ;
    END
  END vm_eff[207]
  PIN vm_eff[208]
    DIRECTION OUTPUT ;
    USE SIGNAL ;
    PORT
      LAYER M4 ;
        RECT  71.196 52.944 71.28 52.968 ;
    END
  END vm_eff[208]
  PIN vm_eff[209]
    DIRECTION OUTPUT ;
    USE SIGNAL ;
    PORT
      LAYER M4 ;
        RECT  71.196 53.04 71.28 53.064 ;
    END
  END vm_eff[209]
  PIN vm_eff[20]
    DIRECTION OUTPUT ;
    USE SIGNAL ;
    PORT
      LAYER M4 ;
        RECT  71.196 21.84 71.28 21.864 ;
    END
  END vm_eff[20]
  PIN vm_eff[210]
    DIRECTION OUTPUT ;
    USE SIGNAL ;
    PORT
      LAYER M4 ;
        RECT  71.196 53.136 71.28 53.16 ;
    END
  END vm_eff[210]
  PIN vm_eff[211]
    DIRECTION OUTPUT ;
    USE SIGNAL ;
    PORT
      LAYER M4 ;
        RECT  71.196 53.232 71.28 53.256 ;
    END
  END vm_eff[211]
  PIN vm_eff[212]
    DIRECTION OUTPUT ;
    USE SIGNAL ;
    PORT
      LAYER M4 ;
        RECT  71.196 53.328 71.28 53.352 ;
    END
  END vm_eff[212]
  PIN vm_eff[213]
    DIRECTION OUTPUT ;
    USE SIGNAL ;
    PORT
      LAYER M4 ;
        RECT  71.196 53.424 71.28 53.448 ;
    END
  END vm_eff[213]
  PIN vm_eff[214]
    DIRECTION OUTPUT ;
    USE SIGNAL ;
    PORT
      LAYER M4 ;
        RECT  71.196 53.52 71.28 53.544 ;
    END
  END vm_eff[214]
  PIN vm_eff[215]
    DIRECTION OUTPUT ;
    USE SIGNAL ;
    PORT
      LAYER M4 ;
        RECT  71.196 53.616 71.28 53.64 ;
    END
  END vm_eff[215]
  PIN vm_eff[216]
    DIRECTION OUTPUT ;
    USE SIGNAL ;
    PORT
      LAYER M4 ;
        RECT  71.196 53.712 71.28 53.736 ;
    END
  END vm_eff[216]
  PIN vm_eff[217]
    DIRECTION OUTPUT ;
    USE SIGNAL ;
    PORT
      LAYER M4 ;
        RECT  71.196 53.808 71.28 53.832 ;
    END
  END vm_eff[217]
  PIN vm_eff[218]
    DIRECTION OUTPUT ;
    USE SIGNAL ;
    PORT
      LAYER M4 ;
        RECT  71.196 53.904 71.28 53.928 ;
    END
  END vm_eff[218]
  PIN vm_eff[219]
    DIRECTION OUTPUT ;
    USE SIGNAL ;
    PORT
      LAYER M4 ;
        RECT  71.196 54 71.28 54.024 ;
    END
  END vm_eff[219]
  PIN vm_eff[21]
    DIRECTION OUTPUT ;
    USE SIGNAL ;
    PORT
      LAYER M4 ;
        RECT  71.196 21.936 71.28 21.96 ;
    END
  END vm_eff[21]
  PIN vm_eff[220]
    DIRECTION OUTPUT ;
    USE SIGNAL ;
    PORT
      LAYER M4 ;
        RECT  71.196 54.096 71.28 54.12 ;
    END
  END vm_eff[220]
  PIN vm_eff[221]
    DIRECTION OUTPUT ;
    USE SIGNAL ;
    PORT
      LAYER M4 ;
        RECT  71.196 54.192 71.28 54.216 ;
    END
  END vm_eff[221]
  PIN vm_eff[222]
    DIRECTION OUTPUT ;
    USE SIGNAL ;
    PORT
      LAYER M4 ;
        RECT  71.196 54.288 71.28 54.312 ;
    END
  END vm_eff[222]
  PIN vm_eff[223]
    DIRECTION OUTPUT ;
    USE SIGNAL ;
    PORT
      LAYER M4 ;
        RECT  71.196 54.384 71.28 54.408 ;
    END
  END vm_eff[223]
  PIN vm_eff[224]
    DIRECTION OUTPUT ;
    USE SIGNAL ;
    PORT
      LAYER M4 ;
        RECT  71.196 32.208 71.28 32.232 ;
    END
  END vm_eff[224]
  PIN vm_eff[225]
    DIRECTION OUTPUT ;
    USE SIGNAL ;
    PORT
      LAYER M4 ;
        RECT  71.196 32.304 71.28 32.328 ;
    END
  END vm_eff[225]
  PIN vm_eff[226]
    DIRECTION OUTPUT ;
    USE SIGNAL ;
    PORT
      LAYER M4 ;
        RECT  71.196 32.4 71.28 32.424 ;
    END
  END vm_eff[226]
  PIN vm_eff[227]
    DIRECTION OUTPUT ;
    USE SIGNAL ;
    PORT
      LAYER M4 ;
        RECT  71.196 32.496 71.28 32.52 ;
    END
  END vm_eff[227]
  PIN vm_eff[228]
    DIRECTION OUTPUT ;
    USE SIGNAL ;
    PORT
      LAYER M4 ;
        RECT  71.196 32.592 71.28 32.616 ;
    END
  END vm_eff[228]
  PIN vm_eff[229]
    DIRECTION OUTPUT ;
    USE SIGNAL ;
    PORT
      LAYER M4 ;
        RECT  71.196 32.688 71.28 32.712 ;
    END
  END vm_eff[229]
  PIN vm_eff[22]
    DIRECTION OUTPUT ;
    USE SIGNAL ;
    PORT
      LAYER M4 ;
        RECT  71.196 22.032 71.28 22.056 ;
    END
  END vm_eff[22]
  PIN vm_eff[230]
    DIRECTION OUTPUT ;
    USE SIGNAL ;
    PORT
      LAYER M4 ;
        RECT  71.196 32.784 71.28 32.808 ;
    END
  END vm_eff[230]
  PIN vm_eff[231]
    DIRECTION OUTPUT ;
    USE SIGNAL ;
    PORT
      LAYER M4 ;
        RECT  71.196 32.88 71.28 32.904 ;
    END
  END vm_eff[231]
  PIN vm_eff[232]
    DIRECTION OUTPUT ;
    USE SIGNAL ;
    PORT
      LAYER M4 ;
        RECT  71.196 32.976 71.28 33 ;
    END
  END vm_eff[232]
  PIN vm_eff[233]
    DIRECTION OUTPUT ;
    USE SIGNAL ;
    PORT
      LAYER M4 ;
        RECT  71.196 33.072 71.28 33.096 ;
    END
  END vm_eff[233]
  PIN vm_eff[234]
    DIRECTION OUTPUT ;
    USE SIGNAL ;
    PORT
      LAYER M4 ;
        RECT  71.196 33.168 71.28 33.192 ;
    END
  END vm_eff[234]
  PIN vm_eff[235]
    DIRECTION OUTPUT ;
    USE SIGNAL ;
    PORT
      LAYER M4 ;
        RECT  71.196 33.264 71.28 33.288 ;
    END
  END vm_eff[235]
  PIN vm_eff[236]
    DIRECTION OUTPUT ;
    USE SIGNAL ;
    PORT
      LAYER M4 ;
        RECT  71.196 33.36 71.28 33.384 ;
    END
  END vm_eff[236]
  PIN vm_eff[237]
    DIRECTION OUTPUT ;
    USE SIGNAL ;
    PORT
      LAYER M4 ;
        RECT  71.196 33.456 71.28 33.48 ;
    END
  END vm_eff[237]
  PIN vm_eff[238]
    DIRECTION OUTPUT ;
    USE SIGNAL ;
    PORT
      LAYER M4 ;
        RECT  71.196 33.552 71.28 33.576 ;
    END
  END vm_eff[238]
  PIN vm_eff[239]
    DIRECTION OUTPUT ;
    USE SIGNAL ;
    PORT
      LAYER M4 ;
        RECT  71.196 33.648 71.28 33.672 ;
    END
  END vm_eff[239]
  PIN vm_eff[23]
    DIRECTION OUTPUT ;
    USE SIGNAL ;
    PORT
      LAYER M4 ;
        RECT  71.196 22.128 71.28 22.152 ;
    END
  END vm_eff[23]
  PIN vm_eff[240]
    DIRECTION OUTPUT ;
    USE SIGNAL ;
    PORT
      LAYER M4 ;
        RECT  71.196 33.744 71.28 33.768 ;
    END
  END vm_eff[240]
  PIN vm_eff[241]
    DIRECTION OUTPUT ;
    USE SIGNAL ;
    PORT
      LAYER M4 ;
        RECT  71.196 33.84 71.28 33.864 ;
    END
  END vm_eff[241]
  PIN vm_eff[242]
    DIRECTION OUTPUT ;
    USE SIGNAL ;
    PORT
      LAYER M4 ;
        RECT  71.196 33.936 71.28 33.96 ;
    END
  END vm_eff[242]
  PIN vm_eff[243]
    DIRECTION OUTPUT ;
    USE SIGNAL ;
    PORT
      LAYER M4 ;
        RECT  71.196 34.032 71.28 34.056 ;
    END
  END vm_eff[243]
  PIN vm_eff[244]
    DIRECTION OUTPUT ;
    USE SIGNAL ;
    PORT
      LAYER M4 ;
        RECT  71.196 34.128 71.28 34.152 ;
    END
  END vm_eff[244]
  PIN vm_eff[245]
    DIRECTION OUTPUT ;
    USE SIGNAL ;
    PORT
      LAYER M4 ;
        RECT  71.196 34.224 71.28 34.248 ;
    END
  END vm_eff[245]
  PIN vm_eff[246]
    DIRECTION OUTPUT ;
    USE SIGNAL ;
    PORT
      LAYER M4 ;
        RECT  71.196 34.32 71.28 34.344 ;
    END
  END vm_eff[246]
  PIN vm_eff[247]
    DIRECTION OUTPUT ;
    USE SIGNAL ;
    PORT
      LAYER M4 ;
        RECT  71.196 34.416 71.28 34.44 ;
    END
  END vm_eff[247]
  PIN vm_eff[248]
    DIRECTION OUTPUT ;
    USE SIGNAL ;
    PORT
      LAYER M4 ;
        RECT  71.196 34.512 71.28 34.536 ;
    END
  END vm_eff[248]
  PIN vm_eff[249]
    DIRECTION OUTPUT ;
    USE SIGNAL ;
    PORT
      LAYER M4 ;
        RECT  71.196 34.608 71.28 34.632 ;
    END
  END vm_eff[249]
  PIN vm_eff[24]
    DIRECTION OUTPUT ;
    USE SIGNAL ;
    PORT
      LAYER M4 ;
        RECT  71.196 22.224 71.28 22.248 ;
    END
  END vm_eff[24]
  PIN vm_eff[250]
    DIRECTION OUTPUT ;
    USE SIGNAL ;
    PORT
      LAYER M4 ;
        RECT  71.196 34.704 71.28 34.728 ;
    END
  END vm_eff[250]
  PIN vm_eff[251]
    DIRECTION OUTPUT ;
    USE SIGNAL ;
    PORT
      LAYER M4 ;
        RECT  71.196 34.8 71.28 34.824 ;
    END
  END vm_eff[251]
  PIN vm_eff[252]
    DIRECTION OUTPUT ;
    USE SIGNAL ;
    PORT
      LAYER M4 ;
        RECT  71.196 34.896 71.28 34.92 ;
    END
  END vm_eff[252]
  PIN vm_eff[253]
    DIRECTION OUTPUT ;
    USE SIGNAL ;
    PORT
      LAYER M4 ;
        RECT  71.196 34.992 71.28 35.016 ;
    END
  END vm_eff[253]
  PIN vm_eff[254]
    DIRECTION OUTPUT ;
    USE SIGNAL ;
    PORT
      LAYER M4 ;
        RECT  71.196 35.088 71.28 35.112 ;
    END
  END vm_eff[254]
  PIN vm_eff[255]
    DIRECTION OUTPUT ;
    USE SIGNAL ;
    PORT
      LAYER M4 ;
        RECT  71.196 35.184 71.28 35.208 ;
    END
  END vm_eff[255]
  PIN vm_eff[256]
    DIRECTION OUTPUT ;
    USE SIGNAL ;
    PORT
      LAYER M4 ;
        RECT  71.196 42.192 71.28 42.216 ;
    END
  END vm_eff[256]
  PIN vm_eff[257]
    DIRECTION OUTPUT ;
    USE SIGNAL ;
    PORT
      LAYER M4 ;
        RECT  71.196 42.288 71.28 42.312 ;
    END
  END vm_eff[257]
  PIN vm_eff[258]
    DIRECTION OUTPUT ;
    USE SIGNAL ;
    PORT
      LAYER M4 ;
        RECT  71.196 42.384 71.28 42.408 ;
    END
  END vm_eff[258]
  PIN vm_eff[259]
    DIRECTION OUTPUT ;
    USE SIGNAL ;
    PORT
      LAYER M4 ;
        RECT  71.196 42.48 71.28 42.504 ;
    END
  END vm_eff[259]
  PIN vm_eff[25]
    DIRECTION OUTPUT ;
    USE SIGNAL ;
    PORT
      LAYER M4 ;
        RECT  71.196 22.32 71.28 22.344 ;
    END
  END vm_eff[25]
  PIN vm_eff[260]
    DIRECTION OUTPUT ;
    USE SIGNAL ;
    PORT
      LAYER M4 ;
        RECT  71.196 42.576 71.28 42.6 ;
    END
  END vm_eff[260]
  PIN vm_eff[261]
    DIRECTION OUTPUT ;
    USE SIGNAL ;
    PORT
      LAYER M4 ;
        RECT  71.196 42.672 71.28 42.696 ;
    END
  END vm_eff[261]
  PIN vm_eff[262]
    DIRECTION OUTPUT ;
    USE SIGNAL ;
    PORT
      LAYER M4 ;
        RECT  71.196 42.768 71.28 42.792 ;
    END
  END vm_eff[262]
  PIN vm_eff[263]
    DIRECTION OUTPUT ;
    USE SIGNAL ;
    PORT
      LAYER M4 ;
        RECT  71.196 42.864 71.28 42.888 ;
    END
  END vm_eff[263]
  PIN vm_eff[264]
    DIRECTION OUTPUT ;
    USE SIGNAL ;
    PORT
      LAYER M4 ;
        RECT  71.196 42.96 71.28 42.984 ;
    END
  END vm_eff[264]
  PIN vm_eff[265]
    DIRECTION OUTPUT ;
    USE SIGNAL ;
    PORT
      LAYER M4 ;
        RECT  71.196 43.056 71.28 43.08 ;
    END
  END vm_eff[265]
  PIN vm_eff[266]
    DIRECTION OUTPUT ;
    USE SIGNAL ;
    PORT
      LAYER M4 ;
        RECT  71.196 43.152 71.28 43.176 ;
    END
  END vm_eff[266]
  PIN vm_eff[267]
    DIRECTION OUTPUT ;
    USE SIGNAL ;
    PORT
      LAYER M4 ;
        RECT  71.196 43.248 71.28 43.272 ;
    END
  END vm_eff[267]
  PIN vm_eff[268]
    DIRECTION OUTPUT ;
    USE SIGNAL ;
    PORT
      LAYER M4 ;
        RECT  71.196 43.344 71.28 43.368 ;
    END
  END vm_eff[268]
  PIN vm_eff[269]
    DIRECTION OUTPUT ;
    USE SIGNAL ;
    PORT
      LAYER M4 ;
        RECT  71.196 43.44 71.28 43.464 ;
    END
  END vm_eff[269]
  PIN vm_eff[26]
    DIRECTION OUTPUT ;
    USE SIGNAL ;
    PORT
      LAYER M4 ;
        RECT  71.196 22.416 71.28 22.44 ;
    END
  END vm_eff[26]
  PIN vm_eff[270]
    DIRECTION OUTPUT ;
    USE SIGNAL ;
    PORT
      LAYER M4 ;
        RECT  71.196 43.536 71.28 43.56 ;
    END
  END vm_eff[270]
  PIN vm_eff[271]
    DIRECTION OUTPUT ;
    USE SIGNAL ;
    PORT
      LAYER M4 ;
        RECT  71.196 43.632 71.28 43.656 ;
    END
  END vm_eff[271]
  PIN vm_eff[272]
    DIRECTION OUTPUT ;
    USE SIGNAL ;
    PORT
      LAYER M4 ;
        RECT  71.196 43.728 71.28 43.752 ;
    END
  END vm_eff[272]
  PIN vm_eff[273]
    DIRECTION OUTPUT ;
    USE SIGNAL ;
    PORT
      LAYER M4 ;
        RECT  71.196 43.824 71.28 43.848 ;
    END
  END vm_eff[273]
  PIN vm_eff[274]
    DIRECTION OUTPUT ;
    USE SIGNAL ;
    PORT
      LAYER M4 ;
        RECT  71.196 43.92 71.28 43.944 ;
    END
  END vm_eff[274]
  PIN vm_eff[275]
    DIRECTION OUTPUT ;
    USE SIGNAL ;
    PORT
      LAYER M4 ;
        RECT  71.196 44.016 71.28 44.04 ;
    END
  END vm_eff[275]
  PIN vm_eff[276]
    DIRECTION OUTPUT ;
    USE SIGNAL ;
    PORT
      LAYER M4 ;
        RECT  71.196 44.112 71.28 44.136 ;
    END
  END vm_eff[276]
  PIN vm_eff[277]
    DIRECTION OUTPUT ;
    USE SIGNAL ;
    PORT
      LAYER M4 ;
        RECT  71.196 44.208 71.28 44.232 ;
    END
  END vm_eff[277]
  PIN vm_eff[278]
    DIRECTION OUTPUT ;
    USE SIGNAL ;
    PORT
      LAYER M4 ;
        RECT  71.196 44.304 71.28 44.328 ;
    END
  END vm_eff[278]
  PIN vm_eff[279]
    DIRECTION OUTPUT ;
    USE SIGNAL ;
    PORT
      LAYER M4 ;
        RECT  71.196 44.4 71.28 44.424 ;
    END
  END vm_eff[279]
  PIN vm_eff[27]
    DIRECTION OUTPUT ;
    USE SIGNAL ;
    PORT
      LAYER M4 ;
        RECT  71.196 22.512 71.28 22.536 ;
    END
  END vm_eff[27]
  PIN vm_eff[280]
    DIRECTION OUTPUT ;
    USE SIGNAL ;
    PORT
      LAYER M4 ;
        RECT  71.196 44.496 71.28 44.52 ;
    END
  END vm_eff[280]
  PIN vm_eff[281]
    DIRECTION OUTPUT ;
    USE SIGNAL ;
    PORT
      LAYER M4 ;
        RECT  71.196 44.592 71.28 44.616 ;
    END
  END vm_eff[281]
  PIN vm_eff[282]
    DIRECTION OUTPUT ;
    USE SIGNAL ;
    PORT
      LAYER M4 ;
        RECT  71.196 44.688 71.28 44.712 ;
    END
  END vm_eff[282]
  PIN vm_eff[283]
    DIRECTION OUTPUT ;
    USE SIGNAL ;
    PORT
      LAYER M4 ;
        RECT  71.196 44.784 71.28 44.808 ;
    END
  END vm_eff[283]
  PIN vm_eff[284]
    DIRECTION OUTPUT ;
    USE SIGNAL ;
    PORT
      LAYER M4 ;
        RECT  71.196 44.88 71.28 44.904 ;
    END
  END vm_eff[284]
  PIN vm_eff[285]
    DIRECTION OUTPUT ;
    USE SIGNAL ;
    PORT
      LAYER M4 ;
        RECT  71.196 44.976 71.28 45 ;
    END
  END vm_eff[285]
  PIN vm_eff[286]
    DIRECTION OUTPUT ;
    USE SIGNAL ;
    PORT
      LAYER M4 ;
        RECT  71.196 45.072 71.28 45.096 ;
    END
  END vm_eff[286]
  PIN vm_eff[287]
    DIRECTION OUTPUT ;
    USE SIGNAL ;
    PORT
      LAYER M4 ;
        RECT  71.196 45.168 71.28 45.192 ;
    END
  END vm_eff[287]
  PIN vm_eff[288]
    DIRECTION OUTPUT ;
    USE SIGNAL ;
    PORT
      LAYER M4 ;
        RECT  71.196 16.08 71.28 16.104 ;
    END
  END vm_eff[288]
  PIN vm_eff[289]
    DIRECTION OUTPUT ;
    USE SIGNAL ;
    PORT
      LAYER M4 ;
        RECT  71.196 16.176 71.28 16.2 ;
    END
  END vm_eff[289]
  PIN vm_eff[28]
    DIRECTION OUTPUT ;
    USE SIGNAL ;
    PORT
      LAYER M4 ;
        RECT  71.196 22.608 71.28 22.632 ;
    END
  END vm_eff[28]
  PIN vm_eff[290]
    DIRECTION OUTPUT ;
    USE SIGNAL ;
    PORT
      LAYER M4 ;
        RECT  71.196 16.272 71.28 16.296 ;
    END
  END vm_eff[290]
  PIN vm_eff[291]
    DIRECTION OUTPUT ;
    USE SIGNAL ;
    PORT
      LAYER M4 ;
        RECT  71.196 16.368 71.28 16.392 ;
    END
  END vm_eff[291]
  PIN vm_eff[292]
    DIRECTION OUTPUT ;
    USE SIGNAL ;
    PORT
      LAYER M4 ;
        RECT  71.196 16.464 71.28 16.488 ;
    END
  END vm_eff[292]
  PIN vm_eff[293]
    DIRECTION OUTPUT ;
    USE SIGNAL ;
    PORT
      LAYER M4 ;
        RECT  71.196 16.56 71.28 16.584 ;
    END
  END vm_eff[293]
  PIN vm_eff[294]
    DIRECTION OUTPUT ;
    USE SIGNAL ;
    PORT
      LAYER M4 ;
        RECT  71.196 16.656 71.28 16.68 ;
    END
  END vm_eff[294]
  PIN vm_eff[295]
    DIRECTION OUTPUT ;
    USE SIGNAL ;
    PORT
      LAYER M4 ;
        RECT  71.196 16.752 71.28 16.776 ;
    END
  END vm_eff[295]
  PIN vm_eff[296]
    DIRECTION OUTPUT ;
    USE SIGNAL ;
    PORT
      LAYER M4 ;
        RECT  71.196 16.848 71.28 16.872 ;
    END
  END vm_eff[296]
  PIN vm_eff[297]
    DIRECTION OUTPUT ;
    USE SIGNAL ;
    PORT
      LAYER M4 ;
        RECT  71.196 16.944 71.28 16.968 ;
    END
  END vm_eff[297]
  PIN vm_eff[298]
    DIRECTION OUTPUT ;
    USE SIGNAL ;
    PORT
      LAYER M4 ;
        RECT  71.196 17.04 71.28 17.064 ;
    END
  END vm_eff[298]
  PIN vm_eff[299]
    DIRECTION OUTPUT ;
    USE SIGNAL ;
    PORT
      LAYER M4 ;
        RECT  71.196 17.136 71.28 17.16 ;
    END
  END vm_eff[299]
  PIN vm_eff[29]
    DIRECTION OUTPUT ;
    USE SIGNAL ;
    PORT
      LAYER M4 ;
        RECT  71.196 22.704 71.28 22.728 ;
    END
  END vm_eff[29]
  PIN vm_eff[2]
    DIRECTION OUTPUT ;
    USE SIGNAL ;
    PORT
      LAYER M4 ;
        RECT  71.196 20.112 71.28 20.136 ;
    END
  END vm_eff[2]
  PIN vm_eff[300]
    DIRECTION OUTPUT ;
    USE SIGNAL ;
    PORT
      LAYER M4 ;
        RECT  71.196 17.232 71.28 17.256 ;
    END
  END vm_eff[300]
  PIN vm_eff[301]
    DIRECTION OUTPUT ;
    USE SIGNAL ;
    PORT
      LAYER M4 ;
        RECT  71.196 17.328 71.28 17.352 ;
    END
  END vm_eff[301]
  PIN vm_eff[302]
    DIRECTION OUTPUT ;
    USE SIGNAL ;
    PORT
      LAYER M4 ;
        RECT  71.196 17.424 71.28 17.448 ;
    END
  END vm_eff[302]
  PIN vm_eff[303]
    DIRECTION OUTPUT ;
    USE SIGNAL ;
    PORT
      LAYER M4 ;
        RECT  71.196 17.52 71.28 17.544 ;
    END
  END vm_eff[303]
  PIN vm_eff[304]
    DIRECTION OUTPUT ;
    USE SIGNAL ;
    PORT
      LAYER M4 ;
        RECT  71.196 17.616 71.28 17.64 ;
    END
  END vm_eff[304]
  PIN vm_eff[305]
    DIRECTION OUTPUT ;
    USE SIGNAL ;
    PORT
      LAYER M4 ;
        RECT  71.196 17.712 71.28 17.736 ;
    END
  END vm_eff[305]
  PIN vm_eff[306]
    DIRECTION OUTPUT ;
    USE SIGNAL ;
    PORT
      LAYER M4 ;
        RECT  71.196 17.808 71.28 17.832 ;
    END
  END vm_eff[306]
  PIN vm_eff[307]
    DIRECTION OUTPUT ;
    USE SIGNAL ;
    PORT
      LAYER M4 ;
        RECT  71.196 17.904 71.28 17.928 ;
    END
  END vm_eff[307]
  PIN vm_eff[308]
    DIRECTION OUTPUT ;
    USE SIGNAL ;
    PORT
      LAYER M4 ;
        RECT  71.196 18 71.28 18.024 ;
    END
  END vm_eff[308]
  PIN vm_eff[309]
    DIRECTION OUTPUT ;
    USE SIGNAL ;
    PORT
      LAYER M4 ;
        RECT  71.196 18.096 71.28 18.12 ;
    END
  END vm_eff[309]
  PIN vm_eff[30]
    DIRECTION OUTPUT ;
    USE SIGNAL ;
    PORT
      LAYER M4 ;
        RECT  71.196 22.8 71.28 22.824 ;
    END
  END vm_eff[30]
  PIN vm_eff[310]
    DIRECTION OUTPUT ;
    USE SIGNAL ;
    PORT
      LAYER M4 ;
        RECT  71.196 18.192 71.28 18.216 ;
    END
  END vm_eff[310]
  PIN vm_eff[311]
    DIRECTION OUTPUT ;
    USE SIGNAL ;
    PORT
      LAYER M4 ;
        RECT  71.196 18.288 71.28 18.312 ;
    END
  END vm_eff[311]
  PIN vm_eff[312]
    DIRECTION OUTPUT ;
    USE SIGNAL ;
    PORT
      LAYER M4 ;
        RECT  71.196 18.384 71.28 18.408 ;
    END
  END vm_eff[312]
  PIN vm_eff[313]
    DIRECTION OUTPUT ;
    USE SIGNAL ;
    PORT
      LAYER M4 ;
        RECT  71.196 18.48 71.28 18.504 ;
    END
  END vm_eff[313]
  PIN vm_eff[314]
    DIRECTION OUTPUT ;
    USE SIGNAL ;
    PORT
      LAYER M4 ;
        RECT  71.196 18.576 71.28 18.6 ;
    END
  END vm_eff[314]
  PIN vm_eff[315]
    DIRECTION OUTPUT ;
    USE SIGNAL ;
    PORT
      LAYER M4 ;
        RECT  71.196 18.672 71.28 18.696 ;
    END
  END vm_eff[315]
  PIN vm_eff[316]
    DIRECTION OUTPUT ;
    USE SIGNAL ;
    PORT
      LAYER M4 ;
        RECT  71.196 18.768 71.28 18.792 ;
    END
  END vm_eff[316]
  PIN vm_eff[317]
    DIRECTION OUTPUT ;
    USE SIGNAL ;
    PORT
      LAYER M4 ;
        RECT  71.196 18.864 71.28 18.888 ;
    END
  END vm_eff[317]
  PIN vm_eff[318]
    DIRECTION OUTPUT ;
    USE SIGNAL ;
    PORT
      LAYER M4 ;
        RECT  71.196 18.96 71.28 18.984 ;
    END
  END vm_eff[318]
  PIN vm_eff[319]
    DIRECTION OUTPUT ;
    USE SIGNAL ;
    PORT
      LAYER M4 ;
        RECT  71.196 19.056 71.28 19.08 ;
    END
  END vm_eff[319]
  PIN vm_eff[31]
    DIRECTION OUTPUT ;
    USE SIGNAL ;
    PORT
      LAYER M4 ;
        RECT  71.196 22.896 71.28 22.92 ;
    END
  END vm_eff[31]
  PIN vm_eff[320]
    DIRECTION OUTPUT ;
    USE SIGNAL ;
    PORT
      LAYER M4 ;
        RECT  71.196 45.264 71.28 45.288 ;
    END
  END vm_eff[320]
  PIN vm_eff[321]
    DIRECTION OUTPUT ;
    USE SIGNAL ;
    PORT
      LAYER M4 ;
        RECT  71.196 45.36 71.28 45.384 ;
    END
  END vm_eff[321]
  PIN vm_eff[322]
    DIRECTION OUTPUT ;
    USE SIGNAL ;
    PORT
      LAYER M4 ;
        RECT  71.196 45.456 71.28 45.48 ;
    END
  END vm_eff[322]
  PIN vm_eff[323]
    DIRECTION OUTPUT ;
    USE SIGNAL ;
    PORT
      LAYER M4 ;
        RECT  71.196 45.552 71.28 45.576 ;
    END
  END vm_eff[323]
  PIN vm_eff[324]
    DIRECTION OUTPUT ;
    USE SIGNAL ;
    PORT
      LAYER M4 ;
        RECT  71.196 45.648 71.28 45.672 ;
    END
  END vm_eff[324]
  PIN vm_eff[325]
    DIRECTION OUTPUT ;
    USE SIGNAL ;
    PORT
      LAYER M4 ;
        RECT  71.196 45.744 71.28 45.768 ;
    END
  END vm_eff[325]
  PIN vm_eff[326]
    DIRECTION OUTPUT ;
    USE SIGNAL ;
    PORT
      LAYER M4 ;
        RECT  71.196 45.84 71.28 45.864 ;
    END
  END vm_eff[326]
  PIN vm_eff[327]
    DIRECTION OUTPUT ;
    USE SIGNAL ;
    PORT
      LAYER M4 ;
        RECT  71.196 45.936 71.28 45.96 ;
    END
  END vm_eff[327]
  PIN vm_eff[328]
    DIRECTION OUTPUT ;
    USE SIGNAL ;
    PORT
      LAYER M4 ;
        RECT  71.196 46.032 71.28 46.056 ;
    END
  END vm_eff[328]
  PIN vm_eff[329]
    DIRECTION OUTPUT ;
    USE SIGNAL ;
    PORT
      LAYER M4 ;
        RECT  71.196 46.128 71.28 46.152 ;
    END
  END vm_eff[329]
  PIN vm_eff[32]
    DIRECTION OUTPUT ;
    USE SIGNAL ;
    PORT
      LAYER M4 ;
        RECT  71.196 64.464 71.28 64.488 ;
    END
  END vm_eff[32]
  PIN vm_eff[330]
    DIRECTION OUTPUT ;
    USE SIGNAL ;
    PORT
      LAYER M4 ;
        RECT  71.196 46.224 71.28 46.248 ;
    END
  END vm_eff[330]
  PIN vm_eff[331]
    DIRECTION OUTPUT ;
    USE SIGNAL ;
    PORT
      LAYER M4 ;
        RECT  71.196 46.32 71.28 46.344 ;
    END
  END vm_eff[331]
  PIN vm_eff[332]
    DIRECTION OUTPUT ;
    USE SIGNAL ;
    PORT
      LAYER M4 ;
        RECT  71.196 46.416 71.28 46.44 ;
    END
  END vm_eff[332]
  PIN vm_eff[333]
    DIRECTION OUTPUT ;
    USE SIGNAL ;
    PORT
      LAYER M4 ;
        RECT  71.196 46.512 71.28 46.536 ;
    END
  END vm_eff[333]
  PIN vm_eff[334]
    DIRECTION OUTPUT ;
    USE SIGNAL ;
    PORT
      LAYER M4 ;
        RECT  71.196 46.608 71.28 46.632 ;
    END
  END vm_eff[334]
  PIN vm_eff[335]
    DIRECTION OUTPUT ;
    USE SIGNAL ;
    PORT
      LAYER M4 ;
        RECT  71.196 46.704 71.28 46.728 ;
    END
  END vm_eff[335]
  PIN vm_eff[336]
    DIRECTION OUTPUT ;
    USE SIGNAL ;
    PORT
      LAYER M4 ;
        RECT  71.196 46.8 71.28 46.824 ;
    END
  END vm_eff[336]
  PIN vm_eff[337]
    DIRECTION OUTPUT ;
    USE SIGNAL ;
    PORT
      LAYER M4 ;
        RECT  71.196 46.896 71.28 46.92 ;
    END
  END vm_eff[337]
  PIN vm_eff[338]
    DIRECTION OUTPUT ;
    USE SIGNAL ;
    PORT
      LAYER M4 ;
        RECT  71.196 46.992 71.28 47.016 ;
    END
  END vm_eff[338]
  PIN vm_eff[339]
    DIRECTION OUTPUT ;
    USE SIGNAL ;
    PORT
      LAYER M4 ;
        RECT  71.196 47.088 71.28 47.112 ;
    END
  END vm_eff[339]
  PIN vm_eff[33]
    DIRECTION OUTPUT ;
    USE SIGNAL ;
    PORT
      LAYER M4 ;
        RECT  71.196 64.56 71.28 64.584 ;
    END
  END vm_eff[33]
  PIN vm_eff[340]
    DIRECTION OUTPUT ;
    USE SIGNAL ;
    PORT
      LAYER M4 ;
        RECT  71.196 47.184 71.28 47.208 ;
    END
  END vm_eff[340]
  PIN vm_eff[341]
    DIRECTION OUTPUT ;
    USE SIGNAL ;
    PORT
      LAYER M4 ;
        RECT  71.196 47.28 71.28 47.304 ;
    END
  END vm_eff[341]
  PIN vm_eff[342]
    DIRECTION OUTPUT ;
    USE SIGNAL ;
    PORT
      LAYER M4 ;
        RECT  71.196 47.376 71.28 47.4 ;
    END
  END vm_eff[342]
  PIN vm_eff[343]
    DIRECTION OUTPUT ;
    USE SIGNAL ;
    PORT
      LAYER M4 ;
        RECT  71.196 47.472 71.28 47.496 ;
    END
  END vm_eff[343]
  PIN vm_eff[344]
    DIRECTION OUTPUT ;
    USE SIGNAL ;
    PORT
      LAYER M4 ;
        RECT  71.196 47.568 71.28 47.592 ;
    END
  END vm_eff[344]
  PIN vm_eff[345]
    DIRECTION OUTPUT ;
    USE SIGNAL ;
    PORT
      LAYER M4 ;
        RECT  71.196 47.664 71.28 47.688 ;
    END
  END vm_eff[345]
  PIN vm_eff[346]
    DIRECTION OUTPUT ;
    USE SIGNAL ;
    PORT
      LAYER M4 ;
        RECT  71.196 47.76 71.28 47.784 ;
    END
  END vm_eff[346]
  PIN vm_eff[347]
    DIRECTION OUTPUT ;
    USE SIGNAL ;
    PORT
      LAYER M4 ;
        RECT  71.196 47.856 71.28 47.88 ;
    END
  END vm_eff[347]
  PIN vm_eff[348]
    DIRECTION OUTPUT ;
    USE SIGNAL ;
    PORT
      LAYER M4 ;
        RECT  71.196 47.952 71.28 47.976 ;
    END
  END vm_eff[348]
  PIN vm_eff[349]
    DIRECTION OUTPUT ;
    USE SIGNAL ;
    PORT
      LAYER M4 ;
        RECT  71.196 48.048 71.28 48.072 ;
    END
  END vm_eff[349]
  PIN vm_eff[34]
    DIRECTION OUTPUT ;
    USE SIGNAL ;
    PORT
      LAYER M4 ;
        RECT  71.196 64.656 71.28 64.68 ;
    END
  END vm_eff[34]
  PIN vm_eff[350]
    DIRECTION OUTPUT ;
    USE SIGNAL ;
    PORT
      LAYER M4 ;
        RECT  71.196 48.144 71.28 48.168 ;
    END
  END vm_eff[350]
  PIN vm_eff[351]
    DIRECTION OUTPUT ;
    USE SIGNAL ;
    PORT
      LAYER M4 ;
        RECT  71.196 48.24 71.28 48.264 ;
    END
  END vm_eff[351]
  PIN vm_eff[352]
    DIRECTION OUTPUT ;
    USE SIGNAL ;
    PORT
      LAYER M4 ;
        RECT  71.196 9.936 71.28 9.96 ;
    END
  END vm_eff[352]
  PIN vm_eff[353]
    DIRECTION OUTPUT ;
    USE SIGNAL ;
    PORT
      LAYER M4 ;
        RECT  71.196 10.032 71.28 10.056 ;
    END
  END vm_eff[353]
  PIN vm_eff[354]
    DIRECTION OUTPUT ;
    USE SIGNAL ;
    PORT
      LAYER M4 ;
        RECT  71.196 10.128 71.28 10.152 ;
    END
  END vm_eff[354]
  PIN vm_eff[355]
    DIRECTION OUTPUT ;
    USE SIGNAL ;
    PORT
      LAYER M4 ;
        RECT  71.196 10.224 71.28 10.248 ;
    END
  END vm_eff[355]
  PIN vm_eff[356]
    DIRECTION OUTPUT ;
    USE SIGNAL ;
    PORT
      LAYER M4 ;
        RECT  71.196 10.32 71.28 10.344 ;
    END
  END vm_eff[356]
  PIN vm_eff[357]
    DIRECTION OUTPUT ;
    USE SIGNAL ;
    PORT
      LAYER M4 ;
        RECT  71.196 10.416 71.28 10.44 ;
    END
  END vm_eff[357]
  PIN vm_eff[358]
    DIRECTION OUTPUT ;
    USE SIGNAL ;
    PORT
      LAYER M4 ;
        RECT  71.196 10.512 71.28 10.536 ;
    END
  END vm_eff[358]
  PIN vm_eff[359]
    DIRECTION OUTPUT ;
    USE SIGNAL ;
    PORT
      LAYER M4 ;
        RECT  71.196 10.608 71.28 10.632 ;
    END
  END vm_eff[359]
  PIN vm_eff[35]
    DIRECTION OUTPUT ;
    USE SIGNAL ;
    PORT
      LAYER M4 ;
        RECT  71.196 64.752 71.28 64.776 ;
    END
  END vm_eff[35]
  PIN vm_eff[360]
    DIRECTION OUTPUT ;
    USE SIGNAL ;
    PORT
      LAYER M4 ;
        RECT  71.196 10.704 71.28 10.728 ;
    END
  END vm_eff[360]
  PIN vm_eff[361]
    DIRECTION OUTPUT ;
    USE SIGNAL ;
    PORT
      LAYER M4 ;
        RECT  71.196 10.8 71.28 10.824 ;
    END
  END vm_eff[361]
  PIN vm_eff[362]
    DIRECTION OUTPUT ;
    USE SIGNAL ;
    PORT
      LAYER M4 ;
        RECT  71.196 10.896 71.28 10.92 ;
    END
  END vm_eff[362]
  PIN vm_eff[363]
    DIRECTION OUTPUT ;
    USE SIGNAL ;
    PORT
      LAYER M4 ;
        RECT  71.196 10.992 71.28 11.016 ;
    END
  END vm_eff[363]
  PIN vm_eff[364]
    DIRECTION OUTPUT ;
    USE SIGNAL ;
    PORT
      LAYER M4 ;
        RECT  71.196 11.088 71.28 11.112 ;
    END
  END vm_eff[364]
  PIN vm_eff[365]
    DIRECTION OUTPUT ;
    USE SIGNAL ;
    PORT
      LAYER M4 ;
        RECT  71.196 11.184 71.28 11.208 ;
    END
  END vm_eff[365]
  PIN vm_eff[366]
    DIRECTION OUTPUT ;
    USE SIGNAL ;
    PORT
      LAYER M4 ;
        RECT  71.196 11.28 71.28 11.304 ;
    END
  END vm_eff[366]
  PIN vm_eff[367]
    DIRECTION OUTPUT ;
    USE SIGNAL ;
    PORT
      LAYER M4 ;
        RECT  71.196 11.376 71.28 11.4 ;
    END
  END vm_eff[367]
  PIN vm_eff[368]
    DIRECTION OUTPUT ;
    USE SIGNAL ;
    PORT
      LAYER M4 ;
        RECT  71.196 11.472 71.28 11.496 ;
    END
  END vm_eff[368]
  PIN vm_eff[369]
    DIRECTION OUTPUT ;
    USE SIGNAL ;
    PORT
      LAYER M4 ;
        RECT  71.196 11.568 71.28 11.592 ;
    END
  END vm_eff[369]
  PIN vm_eff[36]
    DIRECTION OUTPUT ;
    USE SIGNAL ;
    PORT
      LAYER M4 ;
        RECT  71.196 64.848 71.28 64.872 ;
    END
  END vm_eff[36]
  PIN vm_eff[370]
    DIRECTION OUTPUT ;
    USE SIGNAL ;
    PORT
      LAYER M4 ;
        RECT  71.196 11.664 71.28 11.688 ;
    END
  END vm_eff[370]
  PIN vm_eff[371]
    DIRECTION OUTPUT ;
    USE SIGNAL ;
    PORT
      LAYER M4 ;
        RECT  71.196 11.76 71.28 11.784 ;
    END
  END vm_eff[371]
  PIN vm_eff[372]
    DIRECTION OUTPUT ;
    USE SIGNAL ;
    PORT
      LAYER M4 ;
        RECT  71.196 11.856 71.28 11.88 ;
    END
  END vm_eff[372]
  PIN vm_eff[373]
    DIRECTION OUTPUT ;
    USE SIGNAL ;
    PORT
      LAYER M4 ;
        RECT  71.196 11.952 71.28 11.976 ;
    END
  END vm_eff[373]
  PIN vm_eff[374]
    DIRECTION OUTPUT ;
    USE SIGNAL ;
    PORT
      LAYER M4 ;
        RECT  71.196 12.048 71.28 12.072 ;
    END
  END vm_eff[374]
  PIN vm_eff[375]
    DIRECTION OUTPUT ;
    USE SIGNAL ;
    PORT
      LAYER M4 ;
        RECT  71.196 12.144 71.28 12.168 ;
    END
  END vm_eff[375]
  PIN vm_eff[376]
    DIRECTION OUTPUT ;
    USE SIGNAL ;
    PORT
      LAYER M4 ;
        RECT  71.196 12.24 71.28 12.264 ;
    END
  END vm_eff[376]
  PIN vm_eff[377]
    DIRECTION OUTPUT ;
    USE SIGNAL ;
    PORT
      LAYER M4 ;
        RECT  71.196 12.336 71.28 12.36 ;
    END
  END vm_eff[377]
  PIN vm_eff[378]
    DIRECTION OUTPUT ;
    USE SIGNAL ;
    PORT
      LAYER M4 ;
        RECT  71.196 12.432 71.28 12.456 ;
    END
  END vm_eff[378]
  PIN vm_eff[379]
    DIRECTION OUTPUT ;
    USE SIGNAL ;
    PORT
      LAYER M4 ;
        RECT  71.196 12.528 71.28 12.552 ;
    END
  END vm_eff[379]
  PIN vm_eff[37]
    DIRECTION OUTPUT ;
    USE SIGNAL ;
    PORT
      LAYER M4 ;
        RECT  71.196 64.944 71.28 64.968 ;
    END
  END vm_eff[37]
  PIN vm_eff[380]
    DIRECTION OUTPUT ;
    USE SIGNAL ;
    PORT
      LAYER M4 ;
        RECT  71.196 12.624 71.28 12.648 ;
    END
  END vm_eff[380]
  PIN vm_eff[381]
    DIRECTION OUTPUT ;
    USE SIGNAL ;
    PORT
      LAYER M4 ;
        RECT  71.196 12.72 71.28 12.744 ;
    END
  END vm_eff[381]
  PIN vm_eff[382]
    DIRECTION OUTPUT ;
    USE SIGNAL ;
    PORT
      LAYER M4 ;
        RECT  71.196 12.816 71.28 12.84 ;
    END
  END vm_eff[382]
  PIN vm_eff[383]
    DIRECTION OUTPUT ;
    USE SIGNAL ;
    PORT
      LAYER M4 ;
        RECT  71.196 12.912 71.28 12.936 ;
    END
  END vm_eff[383]
  PIN vm_eff[38]
    DIRECTION OUTPUT ;
    USE SIGNAL ;
    PORT
      LAYER M4 ;
        RECT  71.196 65.04 71.28 65.064 ;
    END
  END vm_eff[38]
  PIN vm_eff[39]
    DIRECTION OUTPUT ;
    USE SIGNAL ;
    PORT
      LAYER M4 ;
        RECT  71.196 65.136 71.28 65.16 ;
    END
  END vm_eff[39]
  PIN vm_eff[3]
    DIRECTION OUTPUT ;
    USE SIGNAL ;
    PORT
      LAYER M4 ;
        RECT  71.196 20.208 71.28 20.232 ;
    END
  END vm_eff[3]
  PIN vm_eff[40]
    DIRECTION OUTPUT ;
    USE SIGNAL ;
    PORT
      LAYER M4 ;
        RECT  71.196 65.232 71.28 65.256 ;
    END
  END vm_eff[40]
  PIN vm_eff[41]
    DIRECTION OUTPUT ;
    USE SIGNAL ;
    PORT
      LAYER M4 ;
        RECT  71.196 65.328 71.28 65.352 ;
    END
  END vm_eff[41]
  PIN vm_eff[42]
    DIRECTION OUTPUT ;
    USE SIGNAL ;
    PORT
      LAYER M4 ;
        RECT  71.196 65.424 71.28 65.448 ;
    END
  END vm_eff[42]
  PIN vm_eff[43]
    DIRECTION OUTPUT ;
    USE SIGNAL ;
    PORT
      LAYER M4 ;
        RECT  71.196 65.52 71.28 65.544 ;
    END
  END vm_eff[43]
  PIN vm_eff[44]
    DIRECTION OUTPUT ;
    USE SIGNAL ;
    PORT
      LAYER M4 ;
        RECT  71.196 65.616 71.28 65.64 ;
    END
  END vm_eff[44]
  PIN vm_eff[45]
    DIRECTION OUTPUT ;
    USE SIGNAL ;
    PORT
      LAYER M4 ;
        RECT  71.196 65.712 71.28 65.736 ;
    END
  END vm_eff[45]
  PIN vm_eff[46]
    DIRECTION OUTPUT ;
    USE SIGNAL ;
    PORT
      LAYER M4 ;
        RECT  71.196 65.808 71.28 65.832 ;
    END
  END vm_eff[46]
  PIN vm_eff[47]
    DIRECTION OUTPUT ;
    USE SIGNAL ;
    PORT
      LAYER M4 ;
        RECT  71.196 65.904 71.28 65.928 ;
    END
  END vm_eff[47]
  PIN vm_eff[48]
    DIRECTION OUTPUT ;
    USE SIGNAL ;
    PORT
      LAYER M4 ;
        RECT  71.196 66 71.28 66.024 ;
    END
  END vm_eff[48]
  PIN vm_eff[49]
    DIRECTION OUTPUT ;
    USE SIGNAL ;
    PORT
      LAYER M4 ;
        RECT  71.196 66.096 71.28 66.12 ;
    END
  END vm_eff[49]
  PIN vm_eff[4]
    DIRECTION OUTPUT ;
    USE SIGNAL ;
    PORT
      LAYER M4 ;
        RECT  71.196 20.304 71.28 20.328 ;
    END
  END vm_eff[4]
  PIN vm_eff[50]
    DIRECTION OUTPUT ;
    USE SIGNAL ;
    PORT
      LAYER M4 ;
        RECT  71.196 66.192 71.28 66.216 ;
    END
  END vm_eff[50]
  PIN vm_eff[51]
    DIRECTION OUTPUT ;
    USE SIGNAL ;
    PORT
      LAYER M4 ;
        RECT  71.196 66.288 71.28 66.312 ;
    END
  END vm_eff[51]
  PIN vm_eff[52]
    DIRECTION OUTPUT ;
    USE SIGNAL ;
    PORT
      LAYER M4 ;
        RECT  71.196 66.384 71.28 66.408 ;
    END
  END vm_eff[52]
  PIN vm_eff[53]
    DIRECTION OUTPUT ;
    USE SIGNAL ;
    PORT
      LAYER M4 ;
        RECT  71.196 66.48 71.28 66.504 ;
    END
  END vm_eff[53]
  PIN vm_eff[54]
    DIRECTION OUTPUT ;
    USE SIGNAL ;
    PORT
      LAYER M4 ;
        RECT  71.196 66.576 71.28 66.6 ;
    END
  END vm_eff[54]
  PIN vm_eff[55]
    DIRECTION OUTPUT ;
    USE SIGNAL ;
    PORT
      LAYER M4 ;
        RECT  71.196 66.672 71.28 66.696 ;
    END
  END vm_eff[55]
  PIN vm_eff[56]
    DIRECTION OUTPUT ;
    USE SIGNAL ;
    PORT
      LAYER M4 ;
        RECT  71.196 66.768 71.28 66.792 ;
    END
  END vm_eff[56]
  PIN vm_eff[57]
    DIRECTION OUTPUT ;
    USE SIGNAL ;
    PORT
      LAYER M4 ;
        RECT  71.196 66.864 71.28 66.888 ;
    END
  END vm_eff[57]
  PIN vm_eff[58]
    DIRECTION OUTPUT ;
    USE SIGNAL ;
    PORT
      LAYER M4 ;
        RECT  71.196 66.96 71.28 66.984 ;
    END
  END vm_eff[58]
  PIN vm_eff[59]
    DIRECTION OUTPUT ;
    USE SIGNAL ;
    PORT
      LAYER M4 ;
        RECT  71.196 67.056 71.28 67.08 ;
    END
  END vm_eff[59]
  PIN vm_eff[5]
    DIRECTION OUTPUT ;
    USE SIGNAL ;
    PORT
      LAYER M4 ;
        RECT  71.196 20.4 71.28 20.424 ;
    END
  END vm_eff[5]
  PIN vm_eff[60]
    DIRECTION OUTPUT ;
    USE SIGNAL ;
    PORT
      LAYER M4 ;
        RECT  71.196 67.152 71.28 67.176 ;
    END
  END vm_eff[60]
  PIN vm_eff[61]
    DIRECTION OUTPUT ;
    USE SIGNAL ;
    PORT
      LAYER M4 ;
        RECT  71.196 67.248 71.28 67.272 ;
    END
  END vm_eff[61]
  PIN vm_eff[62]
    DIRECTION OUTPUT ;
    USE SIGNAL ;
    PORT
      LAYER M4 ;
        RECT  71.196 67.344 71.28 67.368 ;
    END
  END vm_eff[62]
  PIN vm_eff[63]
    DIRECTION OUTPUT ;
    USE SIGNAL ;
    PORT
      LAYER M4 ;
        RECT  71.196 67.44 71.28 67.464 ;
    END
  END vm_eff[63]
  PIN vm_eff[64]
    DIRECTION OUTPUT ;
    USE SIGNAL ;
    PORT
      LAYER M4 ;
        RECT  71.196 54.48 71.28 54.504 ;
    END
  END vm_eff[64]
  PIN vm_eff[65]
    DIRECTION OUTPUT ;
    USE SIGNAL ;
    PORT
      LAYER M4 ;
        RECT  71.196 54.576 71.28 54.6 ;
    END
  END vm_eff[65]
  PIN vm_eff[66]
    DIRECTION OUTPUT ;
    USE SIGNAL ;
    PORT
      LAYER M4 ;
        RECT  71.196 54.672 71.28 54.696 ;
    END
  END vm_eff[66]
  PIN vm_eff[67]
    DIRECTION OUTPUT ;
    USE SIGNAL ;
    PORT
      LAYER M4 ;
        RECT  71.196 54.768 71.28 54.792 ;
    END
  END vm_eff[67]
  PIN vm_eff[68]
    DIRECTION OUTPUT ;
    USE SIGNAL ;
    PORT
      LAYER M4 ;
        RECT  71.196 54.864 71.28 54.888 ;
    END
  END vm_eff[68]
  PIN vm_eff[69]
    DIRECTION OUTPUT ;
    USE SIGNAL ;
    PORT
      LAYER M4 ;
        RECT  71.196 54.96 71.28 54.984 ;
    END
  END vm_eff[69]
  PIN vm_eff[6]
    DIRECTION OUTPUT ;
    USE SIGNAL ;
    PORT
      LAYER M4 ;
        RECT  71.196 20.496 71.28 20.52 ;
    END
  END vm_eff[6]
  PIN vm_eff[70]
    DIRECTION OUTPUT ;
    USE SIGNAL ;
    PORT
      LAYER M4 ;
        RECT  71.196 55.056 71.28 55.08 ;
    END
  END vm_eff[70]
  PIN vm_eff[71]
    DIRECTION OUTPUT ;
    USE SIGNAL ;
    PORT
      LAYER M4 ;
        RECT  71.196 55.152 71.28 55.176 ;
    END
  END vm_eff[71]
  PIN vm_eff[72]
    DIRECTION OUTPUT ;
    USE SIGNAL ;
    PORT
      LAYER M4 ;
        RECT  71.196 55.248 71.28 55.272 ;
    END
  END vm_eff[72]
  PIN vm_eff[73]
    DIRECTION OUTPUT ;
    USE SIGNAL ;
    PORT
      LAYER M4 ;
        RECT  71.196 55.344 71.28 55.368 ;
    END
  END vm_eff[73]
  PIN vm_eff[74]
    DIRECTION OUTPUT ;
    USE SIGNAL ;
    PORT
      LAYER M4 ;
        RECT  71.196 55.44 71.28 55.464 ;
    END
  END vm_eff[74]
  PIN vm_eff[75]
    DIRECTION OUTPUT ;
    USE SIGNAL ;
    PORT
      LAYER M4 ;
        RECT  71.196 55.536 71.28 55.56 ;
    END
  END vm_eff[75]
  PIN vm_eff[76]
    DIRECTION OUTPUT ;
    USE SIGNAL ;
    PORT
      LAYER M4 ;
        RECT  71.196 55.632 71.28 55.656 ;
    END
  END vm_eff[76]
  PIN vm_eff[77]
    DIRECTION OUTPUT ;
    USE SIGNAL ;
    PORT
      LAYER M4 ;
        RECT  71.196 55.728 71.28 55.752 ;
    END
  END vm_eff[77]
  PIN vm_eff[78]
    DIRECTION OUTPUT ;
    USE SIGNAL ;
    PORT
      LAYER M4 ;
        RECT  71.196 55.824 71.28 55.848 ;
    END
  END vm_eff[78]
  PIN vm_eff[79]
    DIRECTION OUTPUT ;
    USE SIGNAL ;
    PORT
      LAYER M4 ;
        RECT  71.196 55.92 71.28 55.944 ;
    END
  END vm_eff[79]
  PIN vm_eff[7]
    DIRECTION OUTPUT ;
    USE SIGNAL ;
    PORT
      LAYER M4 ;
        RECT  71.196 20.592 71.28 20.616 ;
    END
  END vm_eff[7]
  PIN vm_eff[80]
    DIRECTION OUTPUT ;
    USE SIGNAL ;
    PORT
      LAYER M4 ;
        RECT  71.196 56.016 71.28 56.04 ;
    END
  END vm_eff[80]
  PIN vm_eff[81]
    DIRECTION OUTPUT ;
    USE SIGNAL ;
    PORT
      LAYER M4 ;
        RECT  71.196 56.112 71.28 56.136 ;
    END
  END vm_eff[81]
  PIN vm_eff[82]
    DIRECTION OUTPUT ;
    USE SIGNAL ;
    PORT
      LAYER M4 ;
        RECT  71.196 56.208 71.28 56.232 ;
    END
  END vm_eff[82]
  PIN vm_eff[83]
    DIRECTION OUTPUT ;
    USE SIGNAL ;
    PORT
      LAYER M4 ;
        RECT  71.196 56.304 71.28 56.328 ;
    END
  END vm_eff[83]
  PIN vm_eff[84]
    DIRECTION OUTPUT ;
    USE SIGNAL ;
    PORT
      LAYER M4 ;
        RECT  71.196 56.4 71.28 56.424 ;
    END
  END vm_eff[84]
  PIN vm_eff[85]
    DIRECTION OUTPUT ;
    USE SIGNAL ;
    PORT
      LAYER M4 ;
        RECT  71.196 56.496 71.28 56.52 ;
    END
  END vm_eff[85]
  PIN vm_eff[86]
    DIRECTION OUTPUT ;
    USE SIGNAL ;
    PORT
      LAYER M4 ;
        RECT  71.196 56.592 71.28 56.616 ;
    END
  END vm_eff[86]
  PIN vm_eff[87]
    DIRECTION OUTPUT ;
    USE SIGNAL ;
    PORT
      LAYER M4 ;
        RECT  71.196 56.688 71.28 56.712 ;
    END
  END vm_eff[87]
  PIN vm_eff[88]
    DIRECTION OUTPUT ;
    USE SIGNAL ;
    PORT
      LAYER M4 ;
        RECT  71.196 56.784 71.28 56.808 ;
    END
  END vm_eff[88]
  PIN vm_eff[89]
    DIRECTION OUTPUT ;
    USE SIGNAL ;
    PORT
      LAYER M4 ;
        RECT  71.196 56.88 71.28 56.904 ;
    END
  END vm_eff[89]
  PIN vm_eff[8]
    DIRECTION OUTPUT ;
    USE SIGNAL ;
    PORT
      LAYER M4 ;
        RECT  71.196 20.688 71.28 20.712 ;
    END
  END vm_eff[8]
  PIN vm_eff[90]
    DIRECTION OUTPUT ;
    USE SIGNAL ;
    PORT
      LAYER M4 ;
        RECT  71.196 56.976 71.28 57 ;
    END
  END vm_eff[90]
  PIN vm_eff[91]
    DIRECTION OUTPUT ;
    USE SIGNAL ;
    PORT
      LAYER M4 ;
        RECT  71.196 57.072 71.28 57.096 ;
    END
  END vm_eff[91]
  PIN vm_eff[92]
    DIRECTION OUTPUT ;
    USE SIGNAL ;
    PORT
      LAYER M4 ;
        RECT  71.196 57.168 71.28 57.192 ;
    END
  END vm_eff[92]
  PIN vm_eff[93]
    DIRECTION OUTPUT ;
    USE SIGNAL ;
    PORT
      LAYER M4 ;
        RECT  71.196 57.264 71.28 57.288 ;
    END
  END vm_eff[93]
  PIN vm_eff[94]
    DIRECTION OUTPUT ;
    USE SIGNAL ;
    PORT
      LAYER M4 ;
        RECT  71.196 57.36 71.28 57.384 ;
    END
  END vm_eff[94]
  PIN vm_eff[95]
    DIRECTION OUTPUT ;
    USE SIGNAL ;
    PORT
      LAYER M4 ;
        RECT  71.196 57.456 71.28 57.48 ;
    END
  END vm_eff[95]
  PIN vm_eff[96]
    DIRECTION OUTPUT ;
    USE SIGNAL ;
    PORT
      LAYER M4 ;
        RECT  71.196 22.992 71.28 23.016 ;
    END
  END vm_eff[96]
  PIN vm_eff[97]
    DIRECTION OUTPUT ;
    USE SIGNAL ;
    PORT
      LAYER M4 ;
        RECT  71.196 23.088 71.28 23.112 ;
    END
  END vm_eff[97]
  PIN vm_eff[98]
    DIRECTION OUTPUT ;
    USE SIGNAL ;
    PORT
      LAYER M4 ;
        RECT  71.196 23.184 71.28 23.208 ;
    END
  END vm_eff[98]
  PIN vm_eff[99]
    DIRECTION OUTPUT ;
    USE SIGNAL ;
    PORT
      LAYER M4 ;
        RECT  71.196 23.28 71.28 23.304 ;
    END
  END vm_eff[99]
  PIN vm_eff[9]
    DIRECTION OUTPUT ;
    USE SIGNAL ;
    PORT
      LAYER M4 ;
        RECT  71.196 20.784 71.28 20.808 ;
    END
  END vm_eff[9]
  PIN vm_mask[0]
    DIRECTION INPUT ;
    USE SIGNAL ;
    PORT
      LAYER M5 ;
        RECT  41.04 71.196 41.064 71.28 ;
    END
  END vm_mask[0]
  PIN vm_mask[10]
    DIRECTION INPUT ;
    USE SIGNAL ;
    PORT
      LAYER M5 ;
        RECT  42 71.196 42.024 71.28 ;
    END
  END vm_mask[10]
  PIN vm_mask[11]
    DIRECTION INPUT ;
    USE SIGNAL ;
    PORT
      LAYER M5 ;
        RECT  42.096 71.196 42.12 71.28 ;
    END
  END vm_mask[11]
  PIN vm_mask[1]
    DIRECTION INPUT ;
    USE SIGNAL ;
    PORT
      LAYER M5 ;
        RECT  41.136 71.196 41.16 71.28 ;
    END
  END vm_mask[1]
  PIN vm_mask[2]
    DIRECTION INPUT ;
    USE SIGNAL ;
    PORT
      LAYER M5 ;
        RECT  41.232 71.196 41.256 71.28 ;
    END
  END vm_mask[2]
  PIN vm_mask[3]
    DIRECTION INPUT ;
    USE SIGNAL ;
    PORT
      LAYER M5 ;
        RECT  41.328 71.196 41.352 71.28 ;
    END
  END vm_mask[3]
  PIN vm_mask[4]
    DIRECTION INPUT ;
    USE SIGNAL ;
    PORT
      LAYER M5 ;
        RECT  41.424 71.196 41.448 71.28 ;
    END
  END vm_mask[4]
  PIN vm_mask[5]
    DIRECTION INPUT ;
    USE SIGNAL ;
    PORT
      LAYER M5 ;
        RECT  41.52 71.196 41.544 71.28 ;
    END
  END vm_mask[5]
  PIN vm_mask[6]
    DIRECTION INPUT ;
    USE SIGNAL ;
    PORT
      LAYER M5 ;
        RECT  41.616 71.196 41.64 71.28 ;
    END
  END vm_mask[6]
  PIN vm_mask[7]
    DIRECTION INPUT ;
    USE SIGNAL ;
    PORT
      LAYER M5 ;
        RECT  41.712 71.196 41.736 71.28 ;
    END
  END vm_mask[7]
  PIN vm_mask[8]
    DIRECTION INPUT ;
    USE SIGNAL ;
    PORT
      LAYER M5 ;
        RECT  41.808 71.196 41.832 71.28 ;
    END
  END vm_mask[8]
  PIN vm_mask[9]
    DIRECTION INPUT ;
    USE SIGNAL ;
    PORT
      LAYER M5 ;
        RECT  41.904 71.196 41.928 71.28 ;
    END
  END vm_mask[9]
  PIN vm_q[0]
    DIRECTION INPUT ;
    USE SIGNAL ;
    PORT
      LAYER M4 ;
        RECT  0 16.848 0.084 16.872 ;
    END
  END vm_q[0]
  PIN vm_q[100]
    DIRECTION INPUT ;
    USE SIGNAL ;
    PORT
      LAYER M4 ;
        RECT  0 20.304 0.084 20.328 ;
    END
  END vm_q[100]
  PIN vm_q[101]
    DIRECTION INPUT ;
    USE SIGNAL ;
    PORT
      LAYER M4 ;
        RECT  0 20.4 0.084 20.424 ;
    END
  END vm_q[101]
  PIN vm_q[102]
    DIRECTION INPUT ;
    USE SIGNAL ;
    PORT
      LAYER M4 ;
        RECT  0 20.496 0.084 20.52 ;
    END
  END vm_q[102]
  PIN vm_q[103]
    DIRECTION INPUT ;
    USE SIGNAL ;
    PORT
      LAYER M4 ;
        RECT  0 20.592 0.084 20.616 ;
    END
  END vm_q[103]
  PIN vm_q[104]
    DIRECTION INPUT ;
    USE SIGNAL ;
    PORT
      LAYER M4 ;
        RECT  0 20.688 0.084 20.712 ;
    END
  END vm_q[104]
  PIN vm_q[105]
    DIRECTION INPUT ;
    USE SIGNAL ;
    PORT
      LAYER M4 ;
        RECT  0 20.784 0.084 20.808 ;
    END
  END vm_q[105]
  PIN vm_q[106]
    DIRECTION INPUT ;
    USE SIGNAL ;
    PORT
      LAYER M4 ;
        RECT  0 20.88 0.084 20.904 ;
    END
  END vm_q[106]
  PIN vm_q[107]
    DIRECTION INPUT ;
    USE SIGNAL ;
    PORT
      LAYER M4 ;
        RECT  0 20.976 0.084 21 ;
    END
  END vm_q[107]
  PIN vm_q[108]
    DIRECTION INPUT ;
    USE SIGNAL ;
    PORT
      LAYER M4 ;
        RECT  0 21.072 0.084 21.096 ;
    END
  END vm_q[108]
  PIN vm_q[109]
    DIRECTION INPUT ;
    USE SIGNAL ;
    PORT
      LAYER M4 ;
        RECT  0 21.168 0.084 21.192 ;
    END
  END vm_q[109]
  PIN vm_q[10]
    DIRECTION INPUT ;
    USE SIGNAL ;
    PORT
      LAYER M4 ;
        RECT  0 17.808 0.084 17.832 ;
    END
  END vm_q[10]
  PIN vm_q[110]
    DIRECTION INPUT ;
    USE SIGNAL ;
    PORT
      LAYER M4 ;
        RECT  0 21.264 0.084 21.288 ;
    END
  END vm_q[110]
  PIN vm_q[111]
    DIRECTION INPUT ;
    USE SIGNAL ;
    PORT
      LAYER M4 ;
        RECT  0 21.36 0.084 21.384 ;
    END
  END vm_q[111]
  PIN vm_q[112]
    DIRECTION INPUT ;
    USE SIGNAL ;
    PORT
      LAYER M4 ;
        RECT  0 21.456 0.084 21.48 ;
    END
  END vm_q[112]
  PIN vm_q[113]
    DIRECTION INPUT ;
    USE SIGNAL ;
    PORT
      LAYER M4 ;
        RECT  0 21.552 0.084 21.576 ;
    END
  END vm_q[113]
  PIN vm_q[114]
    DIRECTION INPUT ;
    USE SIGNAL ;
    PORT
      LAYER M4 ;
        RECT  0 21.648 0.084 21.672 ;
    END
  END vm_q[114]
  PIN vm_q[115]
    DIRECTION INPUT ;
    USE SIGNAL ;
    PORT
      LAYER M4 ;
        RECT  0 21.744 0.084 21.768 ;
    END
  END vm_q[115]
  PIN vm_q[116]
    DIRECTION INPUT ;
    USE SIGNAL ;
    PORT
      LAYER M4 ;
        RECT  0 21.84 0.084 21.864 ;
    END
  END vm_q[116]
  PIN vm_q[117]
    DIRECTION INPUT ;
    USE SIGNAL ;
    PORT
      LAYER M4 ;
        RECT  0 21.936 0.084 21.96 ;
    END
  END vm_q[117]
  PIN vm_q[118]
    DIRECTION INPUT ;
    USE SIGNAL ;
    PORT
      LAYER M4 ;
        RECT  0 22.032 0.084 22.056 ;
    END
  END vm_q[118]
  PIN vm_q[119]
    DIRECTION INPUT ;
    USE SIGNAL ;
    PORT
      LAYER M4 ;
        RECT  0 22.128 0.084 22.152 ;
    END
  END vm_q[119]
  PIN vm_q[11]
    DIRECTION INPUT ;
    USE SIGNAL ;
    PORT
      LAYER M4 ;
        RECT  0 17.904 0.084 17.928 ;
    END
  END vm_q[11]
  PIN vm_q[120]
    DIRECTION INPUT ;
    USE SIGNAL ;
    PORT
      LAYER M4 ;
        RECT  0 22.224 0.084 22.248 ;
    END
  END vm_q[120]
  PIN vm_q[121]
    DIRECTION INPUT ;
    USE SIGNAL ;
    PORT
      LAYER M4 ;
        RECT  0 22.32 0.084 22.344 ;
    END
  END vm_q[121]
  PIN vm_q[122]
    DIRECTION INPUT ;
    USE SIGNAL ;
    PORT
      LAYER M4 ;
        RECT  0 22.416 0.084 22.44 ;
    END
  END vm_q[122]
  PIN vm_q[123]
    DIRECTION INPUT ;
    USE SIGNAL ;
    PORT
      LAYER M4 ;
        RECT  0 22.512 0.084 22.536 ;
    END
  END vm_q[123]
  PIN vm_q[124]
    DIRECTION INPUT ;
    USE SIGNAL ;
    PORT
      LAYER M4 ;
        RECT  0 22.608 0.084 22.632 ;
    END
  END vm_q[124]
  PIN vm_q[125]
    DIRECTION INPUT ;
    USE SIGNAL ;
    PORT
      LAYER M4 ;
        RECT  0 22.704 0.084 22.728 ;
    END
  END vm_q[125]
  PIN vm_q[126]
    DIRECTION INPUT ;
    USE SIGNAL ;
    PORT
      LAYER M4 ;
        RECT  0 22.8 0.084 22.824 ;
    END
  END vm_q[126]
  PIN vm_q[127]
    DIRECTION INPUT ;
    USE SIGNAL ;
    PORT
      LAYER M4 ;
        RECT  0 22.896 0.084 22.92 ;
    END
  END vm_q[127]
  PIN vm_q[128]
    DIRECTION INPUT ;
    USE SIGNAL ;
    PORT
      LAYER M4 ;
        RECT  0 22.992 0.084 23.016 ;
    END
  END vm_q[128]
  PIN vm_q[129]
    DIRECTION INPUT ;
    USE SIGNAL ;
    PORT
      LAYER M4 ;
        RECT  0 23.088 0.084 23.112 ;
    END
  END vm_q[129]
  PIN vm_q[12]
    DIRECTION INPUT ;
    USE SIGNAL ;
    PORT
      LAYER M4 ;
        RECT  0 18 0.084 18.024 ;
    END
  END vm_q[12]
  PIN vm_q[130]
    DIRECTION INPUT ;
    USE SIGNAL ;
    PORT
      LAYER M4 ;
        RECT  0 23.184 0.084 23.208 ;
    END
  END vm_q[130]
  PIN vm_q[131]
    DIRECTION INPUT ;
    USE SIGNAL ;
    PORT
      LAYER M4 ;
        RECT  0 23.28 0.084 23.304 ;
    END
  END vm_q[131]
  PIN vm_q[132]
    DIRECTION INPUT ;
    USE SIGNAL ;
    PORT
      LAYER M4 ;
        RECT  0 23.376 0.084 23.4 ;
    END
  END vm_q[132]
  PIN vm_q[133]
    DIRECTION INPUT ;
    USE SIGNAL ;
    PORT
      LAYER M4 ;
        RECT  0 23.472 0.084 23.496 ;
    END
  END vm_q[133]
  PIN vm_q[134]
    DIRECTION INPUT ;
    USE SIGNAL ;
    PORT
      LAYER M4 ;
        RECT  0 23.568 0.084 23.592 ;
    END
  END vm_q[134]
  PIN vm_q[135]
    DIRECTION INPUT ;
    USE SIGNAL ;
    PORT
      LAYER M4 ;
        RECT  0 23.664 0.084 23.688 ;
    END
  END vm_q[135]
  PIN vm_q[136]
    DIRECTION INPUT ;
    USE SIGNAL ;
    PORT
      LAYER M4 ;
        RECT  0 23.76 0.084 23.784 ;
    END
  END vm_q[136]
  PIN vm_q[137]
    DIRECTION INPUT ;
    USE SIGNAL ;
    PORT
      LAYER M4 ;
        RECT  0 23.856 0.084 23.88 ;
    END
  END vm_q[137]
  PIN vm_q[138]
    DIRECTION INPUT ;
    USE SIGNAL ;
    PORT
      LAYER M4 ;
        RECT  0 23.952 0.084 23.976 ;
    END
  END vm_q[138]
  PIN vm_q[139]
    DIRECTION INPUT ;
    USE SIGNAL ;
    PORT
      LAYER M4 ;
        RECT  0 24.048 0.084 24.072 ;
    END
  END vm_q[139]
  PIN vm_q[13]
    DIRECTION INPUT ;
    USE SIGNAL ;
    PORT
      LAYER M4 ;
        RECT  0 18.096 0.084 18.12 ;
    END
  END vm_q[13]
  PIN vm_q[140]
    DIRECTION INPUT ;
    USE SIGNAL ;
    PORT
      LAYER M4 ;
        RECT  0 24.144 0.084 24.168 ;
    END
  END vm_q[140]
  PIN vm_q[141]
    DIRECTION INPUT ;
    USE SIGNAL ;
    PORT
      LAYER M4 ;
        RECT  0 24.24 0.084 24.264 ;
    END
  END vm_q[141]
  PIN vm_q[142]
    DIRECTION INPUT ;
    USE SIGNAL ;
    PORT
      LAYER M4 ;
        RECT  0 24.336 0.084 24.36 ;
    END
  END vm_q[142]
  PIN vm_q[143]
    DIRECTION INPUT ;
    USE SIGNAL ;
    PORT
      LAYER M4 ;
        RECT  0 24.432 0.084 24.456 ;
    END
  END vm_q[143]
  PIN vm_q[144]
    DIRECTION INPUT ;
    USE SIGNAL ;
    PORT
      LAYER M4 ;
        RECT  0 24.528 0.084 24.552 ;
    END
  END vm_q[144]
  PIN vm_q[145]
    DIRECTION INPUT ;
    USE SIGNAL ;
    PORT
      LAYER M4 ;
        RECT  0 24.624 0.084 24.648 ;
    END
  END vm_q[145]
  PIN vm_q[146]
    DIRECTION INPUT ;
    USE SIGNAL ;
    PORT
      LAYER M4 ;
        RECT  0 24.72 0.084 24.744 ;
    END
  END vm_q[146]
  PIN vm_q[147]
    DIRECTION INPUT ;
    USE SIGNAL ;
    PORT
      LAYER M4 ;
        RECT  0 24.816 0.084 24.84 ;
    END
  END vm_q[147]
  PIN vm_q[148]
    DIRECTION INPUT ;
    USE SIGNAL ;
    PORT
      LAYER M4 ;
        RECT  0 24.912 0.084 24.936 ;
    END
  END vm_q[148]
  PIN vm_q[149]
    DIRECTION INPUT ;
    USE SIGNAL ;
    PORT
      LAYER M4 ;
        RECT  0 25.008 0.084 25.032 ;
    END
  END vm_q[149]
  PIN vm_q[14]
    DIRECTION INPUT ;
    USE SIGNAL ;
    PORT
      LAYER M4 ;
        RECT  0 18.192 0.084 18.216 ;
    END
  END vm_q[14]
  PIN vm_q[150]
    DIRECTION INPUT ;
    USE SIGNAL ;
    PORT
      LAYER M4 ;
        RECT  0 25.104 0.084 25.128 ;
    END
  END vm_q[150]
  PIN vm_q[151]
    DIRECTION INPUT ;
    USE SIGNAL ;
    PORT
      LAYER M4 ;
        RECT  0 25.2 0.084 25.224 ;
    END
  END vm_q[151]
  PIN vm_q[152]
    DIRECTION INPUT ;
    USE SIGNAL ;
    PORT
      LAYER M4 ;
        RECT  0 25.296 0.084 25.32 ;
    END
  END vm_q[152]
  PIN vm_q[153]
    DIRECTION INPUT ;
    USE SIGNAL ;
    PORT
      LAYER M4 ;
        RECT  0 25.392 0.084 25.416 ;
    END
  END vm_q[153]
  PIN vm_q[154]
    DIRECTION INPUT ;
    USE SIGNAL ;
    PORT
      LAYER M4 ;
        RECT  0 25.488 0.084 25.512 ;
    END
  END vm_q[154]
  PIN vm_q[155]
    DIRECTION INPUT ;
    USE SIGNAL ;
    PORT
      LAYER M4 ;
        RECT  0 25.584 0.084 25.608 ;
    END
  END vm_q[155]
  PIN vm_q[156]
    DIRECTION INPUT ;
    USE SIGNAL ;
    PORT
      LAYER M4 ;
        RECT  0 25.68 0.084 25.704 ;
    END
  END vm_q[156]
  PIN vm_q[157]
    DIRECTION INPUT ;
    USE SIGNAL ;
    PORT
      LAYER M4 ;
        RECT  0 25.776 0.084 25.8 ;
    END
  END vm_q[157]
  PIN vm_q[158]
    DIRECTION INPUT ;
    USE SIGNAL ;
    PORT
      LAYER M4 ;
        RECT  0 25.872 0.084 25.896 ;
    END
  END vm_q[158]
  PIN vm_q[159]
    DIRECTION INPUT ;
    USE SIGNAL ;
    PORT
      LAYER M4 ;
        RECT  0 25.968 0.084 25.992 ;
    END
  END vm_q[159]
  PIN vm_q[15]
    DIRECTION INPUT ;
    USE SIGNAL ;
    PORT
      LAYER M4 ;
        RECT  0 18.288 0.084 18.312 ;
    END
  END vm_q[15]
  PIN vm_q[160]
    DIRECTION INPUT ;
    USE SIGNAL ;
    PORT
      LAYER M4 ;
        RECT  0 45.264 0.084 45.288 ;
    END
  END vm_q[160]
  PIN vm_q[161]
    DIRECTION INPUT ;
    USE SIGNAL ;
    PORT
      LAYER M4 ;
        RECT  0 45.36 0.084 45.384 ;
    END
  END vm_q[161]
  PIN vm_q[162]
    DIRECTION INPUT ;
    USE SIGNAL ;
    PORT
      LAYER M4 ;
        RECT  0 45.456 0.084 45.48 ;
    END
  END vm_q[162]
  PIN vm_q[163]
    DIRECTION INPUT ;
    USE SIGNAL ;
    PORT
      LAYER M4 ;
        RECT  0 45.552 0.084 45.576 ;
    END
  END vm_q[163]
  PIN vm_q[164]
    DIRECTION INPUT ;
    USE SIGNAL ;
    PORT
      LAYER M4 ;
        RECT  0 45.648 0.084 45.672 ;
    END
  END vm_q[164]
  PIN vm_q[165]
    DIRECTION INPUT ;
    USE SIGNAL ;
    PORT
      LAYER M4 ;
        RECT  0 45.744 0.084 45.768 ;
    END
  END vm_q[165]
  PIN vm_q[166]
    DIRECTION INPUT ;
    USE SIGNAL ;
    PORT
      LAYER M4 ;
        RECT  0 45.84 0.084 45.864 ;
    END
  END vm_q[166]
  PIN vm_q[167]
    DIRECTION INPUT ;
    USE SIGNAL ;
    PORT
      LAYER M4 ;
        RECT  0 45.936 0.084 45.96 ;
    END
  END vm_q[167]
  PIN vm_q[168]
    DIRECTION INPUT ;
    USE SIGNAL ;
    PORT
      LAYER M4 ;
        RECT  0 46.032 0.084 46.056 ;
    END
  END vm_q[168]
  PIN vm_q[169]
    DIRECTION INPUT ;
    USE SIGNAL ;
    PORT
      LAYER M4 ;
        RECT  0 46.128 0.084 46.152 ;
    END
  END vm_q[169]
  PIN vm_q[16]
    DIRECTION INPUT ;
    USE SIGNAL ;
    PORT
      LAYER M4 ;
        RECT  0 18.384 0.084 18.408 ;
    END
  END vm_q[16]
  PIN vm_q[170]
    DIRECTION INPUT ;
    USE SIGNAL ;
    PORT
      LAYER M4 ;
        RECT  0 46.224 0.084 46.248 ;
    END
  END vm_q[170]
  PIN vm_q[171]
    DIRECTION INPUT ;
    USE SIGNAL ;
    PORT
      LAYER M4 ;
        RECT  0 46.32 0.084 46.344 ;
    END
  END vm_q[171]
  PIN vm_q[172]
    DIRECTION INPUT ;
    USE SIGNAL ;
    PORT
      LAYER M4 ;
        RECT  0 46.416 0.084 46.44 ;
    END
  END vm_q[172]
  PIN vm_q[173]
    DIRECTION INPUT ;
    USE SIGNAL ;
    PORT
      LAYER M4 ;
        RECT  0 46.512 0.084 46.536 ;
    END
  END vm_q[173]
  PIN vm_q[174]
    DIRECTION INPUT ;
    USE SIGNAL ;
    PORT
      LAYER M4 ;
        RECT  0 46.608 0.084 46.632 ;
    END
  END vm_q[174]
  PIN vm_q[175]
    DIRECTION INPUT ;
    USE SIGNAL ;
    PORT
      LAYER M4 ;
        RECT  0 46.704 0.084 46.728 ;
    END
  END vm_q[175]
  PIN vm_q[176]
    DIRECTION INPUT ;
    USE SIGNAL ;
    PORT
      LAYER M4 ;
        RECT  0 46.8 0.084 46.824 ;
    END
  END vm_q[176]
  PIN vm_q[177]
    DIRECTION INPUT ;
    USE SIGNAL ;
    PORT
      LAYER M4 ;
        RECT  0 46.896 0.084 46.92 ;
    END
  END vm_q[177]
  PIN vm_q[178]
    DIRECTION INPUT ;
    USE SIGNAL ;
    PORT
      LAYER M4 ;
        RECT  0 46.992 0.084 47.016 ;
    END
  END vm_q[178]
  PIN vm_q[179]
    DIRECTION INPUT ;
    USE SIGNAL ;
    PORT
      LAYER M4 ;
        RECT  0 47.088 0.084 47.112 ;
    END
  END vm_q[179]
  PIN vm_q[17]
    DIRECTION INPUT ;
    USE SIGNAL ;
    PORT
      LAYER M4 ;
        RECT  0 18.48 0.084 18.504 ;
    END
  END vm_q[17]
  PIN vm_q[180]
    DIRECTION INPUT ;
    USE SIGNAL ;
    PORT
      LAYER M4 ;
        RECT  0 47.184 0.084 47.208 ;
    END
  END vm_q[180]
  PIN vm_q[181]
    DIRECTION INPUT ;
    USE SIGNAL ;
    PORT
      LAYER M4 ;
        RECT  0 47.28 0.084 47.304 ;
    END
  END vm_q[181]
  PIN vm_q[182]
    DIRECTION INPUT ;
    USE SIGNAL ;
    PORT
      LAYER M4 ;
        RECT  0 47.376 0.084 47.4 ;
    END
  END vm_q[182]
  PIN vm_q[183]
    DIRECTION INPUT ;
    USE SIGNAL ;
    PORT
      LAYER M4 ;
        RECT  0 47.472 0.084 47.496 ;
    END
  END vm_q[183]
  PIN vm_q[184]
    DIRECTION INPUT ;
    USE SIGNAL ;
    PORT
      LAYER M4 ;
        RECT  0 47.568 0.084 47.592 ;
    END
  END vm_q[184]
  PIN vm_q[185]
    DIRECTION INPUT ;
    USE SIGNAL ;
    PORT
      LAYER M4 ;
        RECT  0 47.664 0.084 47.688 ;
    END
  END vm_q[185]
  PIN vm_q[186]
    DIRECTION INPUT ;
    USE SIGNAL ;
    PORT
      LAYER M4 ;
        RECT  0 47.76 0.084 47.784 ;
    END
  END vm_q[186]
  PIN vm_q[187]
    DIRECTION INPUT ;
    USE SIGNAL ;
    PORT
      LAYER M4 ;
        RECT  0 47.856 0.084 47.88 ;
    END
  END vm_q[187]
  PIN vm_q[188]
    DIRECTION INPUT ;
    USE SIGNAL ;
    PORT
      LAYER M4 ;
        RECT  0 47.952 0.084 47.976 ;
    END
  END vm_q[188]
  PIN vm_q[189]
    DIRECTION INPUT ;
    USE SIGNAL ;
    PORT
      LAYER M4 ;
        RECT  0 48.048 0.084 48.072 ;
    END
  END vm_q[189]
  PIN vm_q[18]
    DIRECTION INPUT ;
    USE SIGNAL ;
    PORT
      LAYER M4 ;
        RECT  0 18.576 0.084 18.6 ;
    END
  END vm_q[18]
  PIN vm_q[190]
    DIRECTION INPUT ;
    USE SIGNAL ;
    PORT
      LAYER M4 ;
        RECT  0 48.144 0.084 48.168 ;
    END
  END vm_q[190]
  PIN vm_q[191]
    DIRECTION INPUT ;
    USE SIGNAL ;
    PORT
      LAYER M4 ;
        RECT  0 48.24 0.084 48.264 ;
    END
  END vm_q[191]
  PIN vm_q[192]
    DIRECTION INPUT ;
    USE SIGNAL ;
    PORT
      LAYER M4 ;
        RECT  0 55.248 0.084 55.272 ;
    END
  END vm_q[192]
  PIN vm_q[193]
    DIRECTION INPUT ;
    USE SIGNAL ;
    PORT
      LAYER M4 ;
        RECT  0 55.344 0.084 55.368 ;
    END
  END vm_q[193]
  PIN vm_q[194]
    DIRECTION INPUT ;
    USE SIGNAL ;
    PORT
      LAYER M4 ;
        RECT  0 55.44 0.084 55.464 ;
    END
  END vm_q[194]
  PIN vm_q[195]
    DIRECTION INPUT ;
    USE SIGNAL ;
    PORT
      LAYER M4 ;
        RECT  0 55.536 0.084 55.56 ;
    END
  END vm_q[195]
  PIN vm_q[196]
    DIRECTION INPUT ;
    USE SIGNAL ;
    PORT
      LAYER M4 ;
        RECT  0 55.632 0.084 55.656 ;
    END
  END vm_q[196]
  PIN vm_q[197]
    DIRECTION INPUT ;
    USE SIGNAL ;
    PORT
      LAYER M4 ;
        RECT  0 55.728 0.084 55.752 ;
    END
  END vm_q[197]
  PIN vm_q[198]
    DIRECTION INPUT ;
    USE SIGNAL ;
    PORT
      LAYER M4 ;
        RECT  0 55.824 0.084 55.848 ;
    END
  END vm_q[198]
  PIN vm_q[199]
    DIRECTION INPUT ;
    USE SIGNAL ;
    PORT
      LAYER M4 ;
        RECT  0 55.92 0.084 55.944 ;
    END
  END vm_q[199]
  PIN vm_q[19]
    DIRECTION INPUT ;
    USE SIGNAL ;
    PORT
      LAYER M4 ;
        RECT  0 18.672 0.084 18.696 ;
    END
  END vm_q[19]
  PIN vm_q[1]
    DIRECTION INPUT ;
    USE SIGNAL ;
    PORT
      LAYER M4 ;
        RECT  0 16.944 0.084 16.968 ;
    END
  END vm_q[1]
  PIN vm_q[200]
    DIRECTION INPUT ;
    USE SIGNAL ;
    PORT
      LAYER M4 ;
        RECT  0 56.016 0.084 56.04 ;
    END
  END vm_q[200]
  PIN vm_q[201]
    DIRECTION INPUT ;
    USE SIGNAL ;
    PORT
      LAYER M4 ;
        RECT  0 56.112 0.084 56.136 ;
    END
  END vm_q[201]
  PIN vm_q[202]
    DIRECTION INPUT ;
    USE SIGNAL ;
    PORT
      LAYER M4 ;
        RECT  0 56.208 0.084 56.232 ;
    END
  END vm_q[202]
  PIN vm_q[203]
    DIRECTION INPUT ;
    USE SIGNAL ;
    PORT
      LAYER M4 ;
        RECT  0 56.304 0.084 56.328 ;
    END
  END vm_q[203]
  PIN vm_q[204]
    DIRECTION INPUT ;
    USE SIGNAL ;
    PORT
      LAYER M4 ;
        RECT  0 56.4 0.084 56.424 ;
    END
  END vm_q[204]
  PIN vm_q[205]
    DIRECTION INPUT ;
    USE SIGNAL ;
    PORT
      LAYER M4 ;
        RECT  0 56.496 0.084 56.52 ;
    END
  END vm_q[205]
  PIN vm_q[206]
    DIRECTION INPUT ;
    USE SIGNAL ;
    PORT
      LAYER M4 ;
        RECT  0 56.592 0.084 56.616 ;
    END
  END vm_q[206]
  PIN vm_q[207]
    DIRECTION INPUT ;
    USE SIGNAL ;
    PORT
      LAYER M4 ;
        RECT  0 56.688 0.084 56.712 ;
    END
  END vm_q[207]
  PIN vm_q[208]
    DIRECTION INPUT ;
    USE SIGNAL ;
    PORT
      LAYER M4 ;
        RECT  0 56.784 0.084 56.808 ;
    END
  END vm_q[208]
  PIN vm_q[209]
    DIRECTION INPUT ;
    USE SIGNAL ;
    PORT
      LAYER M4 ;
        RECT  0 56.88 0.084 56.904 ;
    END
  END vm_q[209]
  PIN vm_q[20]
    DIRECTION INPUT ;
    USE SIGNAL ;
    PORT
      LAYER M4 ;
        RECT  0 18.768 0.084 18.792 ;
    END
  END vm_q[20]
  PIN vm_q[210]
    DIRECTION INPUT ;
    USE SIGNAL ;
    PORT
      LAYER M4 ;
        RECT  0 56.976 0.084 57 ;
    END
  END vm_q[210]
  PIN vm_q[211]
    DIRECTION INPUT ;
    USE SIGNAL ;
    PORT
      LAYER M4 ;
        RECT  0 57.072 0.084 57.096 ;
    END
  END vm_q[211]
  PIN vm_q[212]
    DIRECTION INPUT ;
    USE SIGNAL ;
    PORT
      LAYER M4 ;
        RECT  0 57.168 0.084 57.192 ;
    END
  END vm_q[212]
  PIN vm_q[213]
    DIRECTION INPUT ;
    USE SIGNAL ;
    PORT
      LAYER M4 ;
        RECT  0 57.264 0.084 57.288 ;
    END
  END vm_q[213]
  PIN vm_q[214]
    DIRECTION INPUT ;
    USE SIGNAL ;
    PORT
      LAYER M4 ;
        RECT  0 57.36 0.084 57.384 ;
    END
  END vm_q[214]
  PIN vm_q[215]
    DIRECTION INPUT ;
    USE SIGNAL ;
    PORT
      LAYER M4 ;
        RECT  0 57.456 0.084 57.48 ;
    END
  END vm_q[215]
  PIN vm_q[216]
    DIRECTION INPUT ;
    USE SIGNAL ;
    PORT
      LAYER M4 ;
        RECT  0 57.552 0.084 57.576 ;
    END
  END vm_q[216]
  PIN vm_q[217]
    DIRECTION INPUT ;
    USE SIGNAL ;
    PORT
      LAYER M4 ;
        RECT  0 57.648 0.084 57.672 ;
    END
  END vm_q[217]
  PIN vm_q[218]
    DIRECTION INPUT ;
    USE SIGNAL ;
    PORT
      LAYER M4 ;
        RECT  0 57.744 0.084 57.768 ;
    END
  END vm_q[218]
  PIN vm_q[219]
    DIRECTION INPUT ;
    USE SIGNAL ;
    PORT
      LAYER M4 ;
        RECT  0 57.84 0.084 57.864 ;
    END
  END vm_q[219]
  PIN vm_q[21]
    DIRECTION INPUT ;
    USE SIGNAL ;
    PORT
      LAYER M4 ;
        RECT  0 18.864 0.084 18.888 ;
    END
  END vm_q[21]
  PIN vm_q[220]
    DIRECTION INPUT ;
    USE SIGNAL ;
    PORT
      LAYER M4 ;
        RECT  0 57.936 0.084 57.96 ;
    END
  END vm_q[220]
  PIN vm_q[221]
    DIRECTION INPUT ;
    USE SIGNAL ;
    PORT
      LAYER M4 ;
        RECT  0 58.032 0.084 58.056 ;
    END
  END vm_q[221]
  PIN vm_q[222]
    DIRECTION INPUT ;
    USE SIGNAL ;
    PORT
      LAYER M4 ;
        RECT  0 58.128 0.084 58.152 ;
    END
  END vm_q[222]
  PIN vm_q[223]
    DIRECTION INPUT ;
    USE SIGNAL ;
    PORT
      LAYER M4 ;
        RECT  0 58.224 0.084 58.248 ;
    END
  END vm_q[223]
  PIN vm_q[224]
    DIRECTION INPUT ;
    USE SIGNAL ;
    PORT
      LAYER M4 ;
        RECT  0 29.136 0.084 29.16 ;
    END
  END vm_q[224]
  PIN vm_q[225]
    DIRECTION INPUT ;
    USE SIGNAL ;
    PORT
      LAYER M4 ;
        RECT  0 29.232 0.084 29.256 ;
    END
  END vm_q[225]
  PIN vm_q[226]
    DIRECTION INPUT ;
    USE SIGNAL ;
    PORT
      LAYER M4 ;
        RECT  0 29.328 0.084 29.352 ;
    END
  END vm_q[226]
  PIN vm_q[227]
    DIRECTION INPUT ;
    USE SIGNAL ;
    PORT
      LAYER M4 ;
        RECT  0 29.424 0.084 29.448 ;
    END
  END vm_q[227]
  PIN vm_q[228]
    DIRECTION INPUT ;
    USE SIGNAL ;
    PORT
      LAYER M4 ;
        RECT  0 29.52 0.084 29.544 ;
    END
  END vm_q[228]
  PIN vm_q[229]
    DIRECTION INPUT ;
    USE SIGNAL ;
    PORT
      LAYER M4 ;
        RECT  0 29.616 0.084 29.64 ;
    END
  END vm_q[229]
  PIN vm_q[22]
    DIRECTION INPUT ;
    USE SIGNAL ;
    PORT
      LAYER M4 ;
        RECT  0 18.96 0.084 18.984 ;
    END
  END vm_q[22]
  PIN vm_q[230]
    DIRECTION INPUT ;
    USE SIGNAL ;
    PORT
      LAYER M4 ;
        RECT  0 29.712 0.084 29.736 ;
    END
  END vm_q[230]
  PIN vm_q[231]
    DIRECTION INPUT ;
    USE SIGNAL ;
    PORT
      LAYER M4 ;
        RECT  0 29.808 0.084 29.832 ;
    END
  END vm_q[231]
  PIN vm_q[232]
    DIRECTION INPUT ;
    USE SIGNAL ;
    PORT
      LAYER M4 ;
        RECT  0 29.904 0.084 29.928 ;
    END
  END vm_q[232]
  PIN vm_q[233]
    DIRECTION INPUT ;
    USE SIGNAL ;
    PORT
      LAYER M4 ;
        RECT  0 30 0.084 30.024 ;
    END
  END vm_q[233]
  PIN vm_q[234]
    DIRECTION INPUT ;
    USE SIGNAL ;
    PORT
      LAYER M4 ;
        RECT  0 30.096 0.084 30.12 ;
    END
  END vm_q[234]
  PIN vm_q[235]
    DIRECTION INPUT ;
    USE SIGNAL ;
    PORT
      LAYER M4 ;
        RECT  0 30.192 0.084 30.216 ;
    END
  END vm_q[235]
  PIN vm_q[236]
    DIRECTION INPUT ;
    USE SIGNAL ;
    PORT
      LAYER M4 ;
        RECT  0 30.288 0.084 30.312 ;
    END
  END vm_q[236]
  PIN vm_q[237]
    DIRECTION INPUT ;
    USE SIGNAL ;
    PORT
      LAYER M4 ;
        RECT  0 30.384 0.084 30.408 ;
    END
  END vm_q[237]
  PIN vm_q[238]
    DIRECTION INPUT ;
    USE SIGNAL ;
    PORT
      LAYER M4 ;
        RECT  0 30.48 0.084 30.504 ;
    END
  END vm_q[238]
  PIN vm_q[239]
    DIRECTION INPUT ;
    USE SIGNAL ;
    PORT
      LAYER M4 ;
        RECT  0 30.576 0.084 30.6 ;
    END
  END vm_q[239]
  PIN vm_q[23]
    DIRECTION INPUT ;
    USE SIGNAL ;
    PORT
      LAYER M4 ;
        RECT  0 19.056 0.084 19.08 ;
    END
  END vm_q[23]
  PIN vm_q[240]
    DIRECTION INPUT ;
    USE SIGNAL ;
    PORT
      LAYER M4 ;
        RECT  0 30.672 0.084 30.696 ;
    END
  END vm_q[240]
  PIN vm_q[241]
    DIRECTION INPUT ;
    USE SIGNAL ;
    PORT
      LAYER M4 ;
        RECT  0 30.768 0.084 30.792 ;
    END
  END vm_q[241]
  PIN vm_q[242]
    DIRECTION INPUT ;
    USE SIGNAL ;
    PORT
      LAYER M4 ;
        RECT  0 30.864 0.084 30.888 ;
    END
  END vm_q[242]
  PIN vm_q[243]
    DIRECTION INPUT ;
    USE SIGNAL ;
    PORT
      LAYER M4 ;
        RECT  0 30.96 0.084 30.984 ;
    END
  END vm_q[243]
  PIN vm_q[244]
    DIRECTION INPUT ;
    USE SIGNAL ;
    PORT
      LAYER M4 ;
        RECT  0 31.056 0.084 31.08 ;
    END
  END vm_q[244]
  PIN vm_q[245]
    DIRECTION INPUT ;
    USE SIGNAL ;
    PORT
      LAYER M4 ;
        RECT  0 31.152 0.084 31.176 ;
    END
  END vm_q[245]
  PIN vm_q[246]
    DIRECTION INPUT ;
    USE SIGNAL ;
    PORT
      LAYER M4 ;
        RECT  0 31.248 0.084 31.272 ;
    END
  END vm_q[246]
  PIN vm_q[247]
    DIRECTION INPUT ;
    USE SIGNAL ;
    PORT
      LAYER M4 ;
        RECT  0 31.344 0.084 31.368 ;
    END
  END vm_q[247]
  PIN vm_q[248]
    DIRECTION INPUT ;
    USE SIGNAL ;
    PORT
      LAYER M4 ;
        RECT  0 31.44 0.084 31.464 ;
    END
  END vm_q[248]
  PIN vm_q[249]
    DIRECTION INPUT ;
    USE SIGNAL ;
    PORT
      LAYER M4 ;
        RECT  0 31.536 0.084 31.56 ;
    END
  END vm_q[249]
  PIN vm_q[24]
    DIRECTION INPUT ;
    USE SIGNAL ;
    PORT
      LAYER M4 ;
        RECT  0 19.152 0.084 19.176 ;
    END
  END vm_q[24]
  PIN vm_q[250]
    DIRECTION INPUT ;
    USE SIGNAL ;
    PORT
      LAYER M4 ;
        RECT  0 31.632 0.084 31.656 ;
    END
  END vm_q[250]
  PIN vm_q[251]
    DIRECTION INPUT ;
    USE SIGNAL ;
    PORT
      LAYER M4 ;
        RECT  0 31.728 0.084 31.752 ;
    END
  END vm_q[251]
  PIN vm_q[252]
    DIRECTION INPUT ;
    USE SIGNAL ;
    PORT
      LAYER M4 ;
        RECT  0 31.824 0.084 31.848 ;
    END
  END vm_q[252]
  PIN vm_q[253]
    DIRECTION INPUT ;
    USE SIGNAL ;
    PORT
      LAYER M4 ;
        RECT  0 31.92 0.084 31.944 ;
    END
  END vm_q[253]
  PIN vm_q[254]
    DIRECTION INPUT ;
    USE SIGNAL ;
    PORT
      LAYER M4 ;
        RECT  0 32.016 0.084 32.04 ;
    END
  END vm_q[254]
  PIN vm_q[255]
    DIRECTION INPUT ;
    USE SIGNAL ;
    PORT
      LAYER M4 ;
        RECT  0 32.112 0.084 32.136 ;
    END
  END vm_q[255]
  PIN vm_q[256]
    DIRECTION INPUT ;
    USE SIGNAL ;
    PORT
      LAYER M4 ;
        RECT  0 39.12 0.084 39.144 ;
    END
  END vm_q[256]
  PIN vm_q[257]
    DIRECTION INPUT ;
    USE SIGNAL ;
    PORT
      LAYER M4 ;
        RECT  0 39.216 0.084 39.24 ;
    END
  END vm_q[257]
  PIN vm_q[258]
    DIRECTION INPUT ;
    USE SIGNAL ;
    PORT
      LAYER M4 ;
        RECT  0 39.312 0.084 39.336 ;
    END
  END vm_q[258]
  PIN vm_q[259]
    DIRECTION INPUT ;
    USE SIGNAL ;
    PORT
      LAYER M4 ;
        RECT  0 39.408 0.084 39.432 ;
    END
  END vm_q[259]
  PIN vm_q[25]
    DIRECTION INPUT ;
    USE SIGNAL ;
    PORT
      LAYER M4 ;
        RECT  0 19.248 0.084 19.272 ;
    END
  END vm_q[25]
  PIN vm_q[260]
    DIRECTION INPUT ;
    USE SIGNAL ;
    PORT
      LAYER M4 ;
        RECT  0 39.504 0.084 39.528 ;
    END
  END vm_q[260]
  PIN vm_q[261]
    DIRECTION INPUT ;
    USE SIGNAL ;
    PORT
      LAYER M4 ;
        RECT  0 39.6 0.084 39.624 ;
    END
  END vm_q[261]
  PIN vm_q[262]
    DIRECTION INPUT ;
    USE SIGNAL ;
    PORT
      LAYER M4 ;
        RECT  0 39.696 0.084 39.72 ;
    END
  END vm_q[262]
  PIN vm_q[263]
    DIRECTION INPUT ;
    USE SIGNAL ;
    PORT
      LAYER M4 ;
        RECT  0 39.792 0.084 39.816 ;
    END
  END vm_q[263]
  PIN vm_q[264]
    DIRECTION INPUT ;
    USE SIGNAL ;
    PORT
      LAYER M4 ;
        RECT  0 39.888 0.084 39.912 ;
    END
  END vm_q[264]
  PIN vm_q[265]
    DIRECTION INPUT ;
    USE SIGNAL ;
    PORT
      LAYER M4 ;
        RECT  0 39.984 0.084 40.008 ;
    END
  END vm_q[265]
  PIN vm_q[266]
    DIRECTION INPUT ;
    USE SIGNAL ;
    PORT
      LAYER M4 ;
        RECT  0 40.08 0.084 40.104 ;
    END
  END vm_q[266]
  PIN vm_q[267]
    DIRECTION INPUT ;
    USE SIGNAL ;
    PORT
      LAYER M4 ;
        RECT  0 40.176 0.084 40.2 ;
    END
  END vm_q[267]
  PIN vm_q[268]
    DIRECTION INPUT ;
    USE SIGNAL ;
    PORT
      LAYER M4 ;
        RECT  0 40.272 0.084 40.296 ;
    END
  END vm_q[268]
  PIN vm_q[269]
    DIRECTION INPUT ;
    USE SIGNAL ;
    PORT
      LAYER M4 ;
        RECT  0 40.368 0.084 40.392 ;
    END
  END vm_q[269]
  PIN vm_q[26]
    DIRECTION INPUT ;
    USE SIGNAL ;
    PORT
      LAYER M4 ;
        RECT  0 19.344 0.084 19.368 ;
    END
  END vm_q[26]
  PIN vm_q[270]
    DIRECTION INPUT ;
    USE SIGNAL ;
    PORT
      LAYER M4 ;
        RECT  0 40.464 0.084 40.488 ;
    END
  END vm_q[270]
  PIN vm_q[271]
    DIRECTION INPUT ;
    USE SIGNAL ;
    PORT
      LAYER M4 ;
        RECT  0 40.56 0.084 40.584 ;
    END
  END vm_q[271]
  PIN vm_q[272]
    DIRECTION INPUT ;
    USE SIGNAL ;
    PORT
      LAYER M4 ;
        RECT  0 40.656 0.084 40.68 ;
    END
  END vm_q[272]
  PIN vm_q[273]
    DIRECTION INPUT ;
    USE SIGNAL ;
    PORT
      LAYER M4 ;
        RECT  0 40.752 0.084 40.776 ;
    END
  END vm_q[273]
  PIN vm_q[274]
    DIRECTION INPUT ;
    USE SIGNAL ;
    PORT
      LAYER M4 ;
        RECT  0 40.848 0.084 40.872 ;
    END
  END vm_q[274]
  PIN vm_q[275]
    DIRECTION INPUT ;
    USE SIGNAL ;
    PORT
      LAYER M4 ;
        RECT  0 40.944 0.084 40.968 ;
    END
  END vm_q[275]
  PIN vm_q[276]
    DIRECTION INPUT ;
    USE SIGNAL ;
    PORT
      LAYER M4 ;
        RECT  0 41.04 0.084 41.064 ;
    END
  END vm_q[276]
  PIN vm_q[277]
    DIRECTION INPUT ;
    USE SIGNAL ;
    PORT
      LAYER M4 ;
        RECT  0 41.136 0.084 41.16 ;
    END
  END vm_q[277]
  PIN vm_q[278]
    DIRECTION INPUT ;
    USE SIGNAL ;
    PORT
      LAYER M4 ;
        RECT  0 41.232 0.084 41.256 ;
    END
  END vm_q[278]
  PIN vm_q[279]
    DIRECTION INPUT ;
    USE SIGNAL ;
    PORT
      LAYER M4 ;
        RECT  0 41.328 0.084 41.352 ;
    END
  END vm_q[279]
  PIN vm_q[27]
    DIRECTION INPUT ;
    USE SIGNAL ;
    PORT
      LAYER M4 ;
        RECT  0 19.44 0.084 19.464 ;
    END
  END vm_q[27]
  PIN vm_q[280]
    DIRECTION INPUT ;
    USE SIGNAL ;
    PORT
      LAYER M4 ;
        RECT  0 41.424 0.084 41.448 ;
    END
  END vm_q[280]
  PIN vm_q[281]
    DIRECTION INPUT ;
    USE SIGNAL ;
    PORT
      LAYER M4 ;
        RECT  0 41.52 0.084 41.544 ;
    END
  END vm_q[281]
  PIN vm_q[282]
    DIRECTION INPUT ;
    USE SIGNAL ;
    PORT
      LAYER M4 ;
        RECT  0 41.616 0.084 41.64 ;
    END
  END vm_q[282]
  PIN vm_q[283]
    DIRECTION INPUT ;
    USE SIGNAL ;
    PORT
      LAYER M4 ;
        RECT  0 41.712 0.084 41.736 ;
    END
  END vm_q[283]
  PIN vm_q[284]
    DIRECTION INPUT ;
    USE SIGNAL ;
    PORT
      LAYER M4 ;
        RECT  0 41.808 0.084 41.832 ;
    END
  END vm_q[284]
  PIN vm_q[285]
    DIRECTION INPUT ;
    USE SIGNAL ;
    PORT
      LAYER M4 ;
        RECT  0 41.904 0.084 41.928 ;
    END
  END vm_q[285]
  PIN vm_q[286]
    DIRECTION INPUT ;
    USE SIGNAL ;
    PORT
      LAYER M4 ;
        RECT  0 42 0.084 42.024 ;
    END
  END vm_q[286]
  PIN vm_q[287]
    DIRECTION INPUT ;
    USE SIGNAL ;
    PORT
      LAYER M4 ;
        RECT  0 42.096 0.084 42.12 ;
    END
  END vm_q[287]
  PIN vm_q[288]
    DIRECTION INPUT ;
    USE SIGNAL ;
    PORT
      LAYER M4 ;
        RECT  0 13.776 0.084 13.8 ;
    END
  END vm_q[288]
  PIN vm_q[289]
    DIRECTION INPUT ;
    USE SIGNAL ;
    PORT
      LAYER M4 ;
        RECT  0 13.872 0.084 13.896 ;
    END
  END vm_q[289]
  PIN vm_q[28]
    DIRECTION INPUT ;
    USE SIGNAL ;
    PORT
      LAYER M4 ;
        RECT  0 19.536 0.084 19.56 ;
    END
  END vm_q[28]
  PIN vm_q[290]
    DIRECTION INPUT ;
    USE SIGNAL ;
    PORT
      LAYER M4 ;
        RECT  0 13.968 0.084 13.992 ;
    END
  END vm_q[290]
  PIN vm_q[291]
    DIRECTION INPUT ;
    USE SIGNAL ;
    PORT
      LAYER M4 ;
        RECT  0 14.064 0.084 14.088 ;
    END
  END vm_q[291]
  PIN vm_q[292]
    DIRECTION INPUT ;
    USE SIGNAL ;
    PORT
      LAYER M4 ;
        RECT  0 14.16 0.084 14.184 ;
    END
  END vm_q[292]
  PIN vm_q[293]
    DIRECTION INPUT ;
    USE SIGNAL ;
    PORT
      LAYER M4 ;
        RECT  0 14.256 0.084 14.28 ;
    END
  END vm_q[293]
  PIN vm_q[294]
    DIRECTION INPUT ;
    USE SIGNAL ;
    PORT
      LAYER M4 ;
        RECT  0 14.352 0.084 14.376 ;
    END
  END vm_q[294]
  PIN vm_q[295]
    DIRECTION INPUT ;
    USE SIGNAL ;
    PORT
      LAYER M4 ;
        RECT  0 14.448 0.084 14.472 ;
    END
  END vm_q[295]
  PIN vm_q[296]
    DIRECTION INPUT ;
    USE SIGNAL ;
    PORT
      LAYER M4 ;
        RECT  0 14.544 0.084 14.568 ;
    END
  END vm_q[296]
  PIN vm_q[297]
    DIRECTION INPUT ;
    USE SIGNAL ;
    PORT
      LAYER M4 ;
        RECT  0 14.64 0.084 14.664 ;
    END
  END vm_q[297]
  PIN vm_q[298]
    DIRECTION INPUT ;
    USE SIGNAL ;
    PORT
      LAYER M4 ;
        RECT  0 14.736 0.084 14.76 ;
    END
  END vm_q[298]
  PIN vm_q[299]
    DIRECTION INPUT ;
    USE SIGNAL ;
    PORT
      LAYER M4 ;
        RECT  0 14.832 0.084 14.856 ;
    END
  END vm_q[299]
  PIN vm_q[29]
    DIRECTION INPUT ;
    USE SIGNAL ;
    PORT
      LAYER M4 ;
        RECT  0 19.632 0.084 19.656 ;
    END
  END vm_q[29]
  PIN vm_q[2]
    DIRECTION INPUT ;
    USE SIGNAL ;
    PORT
      LAYER M4 ;
        RECT  0 17.04 0.084 17.064 ;
    END
  END vm_q[2]
  PIN vm_q[300]
    DIRECTION INPUT ;
    USE SIGNAL ;
    PORT
      LAYER M4 ;
        RECT  0 14.928 0.084 14.952 ;
    END
  END vm_q[300]
  PIN vm_q[301]
    DIRECTION INPUT ;
    USE SIGNAL ;
    PORT
      LAYER M4 ;
        RECT  0 15.024 0.084 15.048 ;
    END
  END vm_q[301]
  PIN vm_q[302]
    DIRECTION INPUT ;
    USE SIGNAL ;
    PORT
      LAYER M4 ;
        RECT  0 15.12 0.084 15.144 ;
    END
  END vm_q[302]
  PIN vm_q[303]
    DIRECTION INPUT ;
    USE SIGNAL ;
    PORT
      LAYER M4 ;
        RECT  0 15.216 0.084 15.24 ;
    END
  END vm_q[303]
  PIN vm_q[304]
    DIRECTION INPUT ;
    USE SIGNAL ;
    PORT
      LAYER M4 ;
        RECT  0 15.312 0.084 15.336 ;
    END
  END vm_q[304]
  PIN vm_q[305]
    DIRECTION INPUT ;
    USE SIGNAL ;
    PORT
      LAYER M4 ;
        RECT  0 15.408 0.084 15.432 ;
    END
  END vm_q[305]
  PIN vm_q[306]
    DIRECTION INPUT ;
    USE SIGNAL ;
    PORT
      LAYER M4 ;
        RECT  0 15.504 0.084 15.528 ;
    END
  END vm_q[306]
  PIN vm_q[307]
    DIRECTION INPUT ;
    USE SIGNAL ;
    PORT
      LAYER M4 ;
        RECT  0 15.6 0.084 15.624 ;
    END
  END vm_q[307]
  PIN vm_q[308]
    DIRECTION INPUT ;
    USE SIGNAL ;
    PORT
      LAYER M4 ;
        RECT  0 15.696 0.084 15.72 ;
    END
  END vm_q[308]
  PIN vm_q[309]
    DIRECTION INPUT ;
    USE SIGNAL ;
    PORT
      LAYER M4 ;
        RECT  0 15.792 0.084 15.816 ;
    END
  END vm_q[309]
  PIN vm_q[30]
    DIRECTION INPUT ;
    USE SIGNAL ;
    PORT
      LAYER M4 ;
        RECT  0 19.728 0.084 19.752 ;
    END
  END vm_q[30]
  PIN vm_q[310]
    DIRECTION INPUT ;
    USE SIGNAL ;
    PORT
      LAYER M4 ;
        RECT  0 15.888 0.084 15.912 ;
    END
  END vm_q[310]
  PIN vm_q[311]
    DIRECTION INPUT ;
    USE SIGNAL ;
    PORT
      LAYER M4 ;
        RECT  0 15.984 0.084 16.008 ;
    END
  END vm_q[311]
  PIN vm_q[312]
    DIRECTION INPUT ;
    USE SIGNAL ;
    PORT
      LAYER M4 ;
        RECT  0 16.08 0.084 16.104 ;
    END
  END vm_q[312]
  PIN vm_q[313]
    DIRECTION INPUT ;
    USE SIGNAL ;
    PORT
      LAYER M4 ;
        RECT  0 16.176 0.084 16.2 ;
    END
  END vm_q[313]
  PIN vm_q[314]
    DIRECTION INPUT ;
    USE SIGNAL ;
    PORT
      LAYER M4 ;
        RECT  0 16.272 0.084 16.296 ;
    END
  END vm_q[314]
  PIN vm_q[315]
    DIRECTION INPUT ;
    USE SIGNAL ;
    PORT
      LAYER M4 ;
        RECT  0 16.368 0.084 16.392 ;
    END
  END vm_q[315]
  PIN vm_q[316]
    DIRECTION INPUT ;
    USE SIGNAL ;
    PORT
      LAYER M4 ;
        RECT  0 16.464 0.084 16.488 ;
    END
  END vm_q[316]
  PIN vm_q[317]
    DIRECTION INPUT ;
    USE SIGNAL ;
    PORT
      LAYER M4 ;
        RECT  0 16.56 0.084 16.584 ;
    END
  END vm_q[317]
  PIN vm_q[318]
    DIRECTION INPUT ;
    USE SIGNAL ;
    PORT
      LAYER M4 ;
        RECT  0 16.656 0.084 16.68 ;
    END
  END vm_q[318]
  PIN vm_q[319]
    DIRECTION INPUT ;
    USE SIGNAL ;
    PORT
      LAYER M4 ;
        RECT  0 16.752 0.084 16.776 ;
    END
  END vm_q[319]
  PIN vm_q[31]
    DIRECTION INPUT ;
    USE SIGNAL ;
    PORT
      LAYER M4 ;
        RECT  0 19.824 0.084 19.848 ;
    END
  END vm_q[31]
  PIN vm_q[320]
    DIRECTION INPUT ;
    USE SIGNAL ;
    PORT
      LAYER M4 ;
        RECT  0 42.192 0.084 42.216 ;
    END
  END vm_q[320]
  PIN vm_q[321]
    DIRECTION INPUT ;
    USE SIGNAL ;
    PORT
      LAYER M4 ;
        RECT  0 42.288 0.084 42.312 ;
    END
  END vm_q[321]
  PIN vm_q[322]
    DIRECTION INPUT ;
    USE SIGNAL ;
    PORT
      LAYER M4 ;
        RECT  0 42.384 0.084 42.408 ;
    END
  END vm_q[322]
  PIN vm_q[323]
    DIRECTION INPUT ;
    USE SIGNAL ;
    PORT
      LAYER M4 ;
        RECT  0 42.48 0.084 42.504 ;
    END
  END vm_q[323]
  PIN vm_q[324]
    DIRECTION INPUT ;
    USE SIGNAL ;
    PORT
      LAYER M4 ;
        RECT  0 42.576 0.084 42.6 ;
    END
  END vm_q[324]
  PIN vm_q[325]
    DIRECTION INPUT ;
    USE SIGNAL ;
    PORT
      LAYER M4 ;
        RECT  0 42.672 0.084 42.696 ;
    END
  END vm_q[325]
  PIN vm_q[326]
    DIRECTION INPUT ;
    USE SIGNAL ;
    PORT
      LAYER M4 ;
        RECT  0 42.768 0.084 42.792 ;
    END
  END vm_q[326]
  PIN vm_q[327]
    DIRECTION INPUT ;
    USE SIGNAL ;
    PORT
      LAYER M4 ;
        RECT  0 42.864 0.084 42.888 ;
    END
  END vm_q[327]
  PIN vm_q[328]
    DIRECTION INPUT ;
    USE SIGNAL ;
    PORT
      LAYER M4 ;
        RECT  0 42.96 0.084 42.984 ;
    END
  END vm_q[328]
  PIN vm_q[329]
    DIRECTION INPUT ;
    USE SIGNAL ;
    PORT
      LAYER M4 ;
        RECT  0 43.056 0.084 43.08 ;
    END
  END vm_q[329]
  PIN vm_q[32]
    DIRECTION INPUT ;
    USE SIGNAL ;
    PORT
      LAYER M4 ;
        RECT  0 61.392 0.084 61.416 ;
    END
  END vm_q[32]
  PIN vm_q[330]
    DIRECTION INPUT ;
    USE SIGNAL ;
    PORT
      LAYER M4 ;
        RECT  0 43.152 0.084 43.176 ;
    END
  END vm_q[330]
  PIN vm_q[331]
    DIRECTION INPUT ;
    USE SIGNAL ;
    PORT
      LAYER M4 ;
        RECT  0 43.248 0.084 43.272 ;
    END
  END vm_q[331]
  PIN vm_q[332]
    DIRECTION INPUT ;
    USE SIGNAL ;
    PORT
      LAYER M4 ;
        RECT  0 43.344 0.084 43.368 ;
    END
  END vm_q[332]
  PIN vm_q[333]
    DIRECTION INPUT ;
    USE SIGNAL ;
    PORT
      LAYER M4 ;
        RECT  0 43.44 0.084 43.464 ;
    END
  END vm_q[333]
  PIN vm_q[334]
    DIRECTION INPUT ;
    USE SIGNAL ;
    PORT
      LAYER M4 ;
        RECT  0 43.536 0.084 43.56 ;
    END
  END vm_q[334]
  PIN vm_q[335]
    DIRECTION INPUT ;
    USE SIGNAL ;
    PORT
      LAYER M4 ;
        RECT  0 43.632 0.084 43.656 ;
    END
  END vm_q[335]
  PIN vm_q[336]
    DIRECTION INPUT ;
    USE SIGNAL ;
    PORT
      LAYER M4 ;
        RECT  0 43.728 0.084 43.752 ;
    END
  END vm_q[336]
  PIN vm_q[337]
    DIRECTION INPUT ;
    USE SIGNAL ;
    PORT
      LAYER M4 ;
        RECT  0 43.824 0.084 43.848 ;
    END
  END vm_q[337]
  PIN vm_q[338]
    DIRECTION INPUT ;
    USE SIGNAL ;
    PORT
      LAYER M4 ;
        RECT  0 43.92 0.084 43.944 ;
    END
  END vm_q[338]
  PIN vm_q[339]
    DIRECTION INPUT ;
    USE SIGNAL ;
    PORT
      LAYER M4 ;
        RECT  0 44.016 0.084 44.04 ;
    END
  END vm_q[339]
  PIN vm_q[33]
    DIRECTION INPUT ;
    USE SIGNAL ;
    PORT
      LAYER M4 ;
        RECT  0 61.488 0.084 61.512 ;
    END
  END vm_q[33]
  PIN vm_q[340]
    DIRECTION INPUT ;
    USE SIGNAL ;
    PORT
      LAYER M4 ;
        RECT  0 44.112 0.084 44.136 ;
    END
  END vm_q[340]
  PIN vm_q[341]
    DIRECTION INPUT ;
    USE SIGNAL ;
    PORT
      LAYER M4 ;
        RECT  0 44.208 0.084 44.232 ;
    END
  END vm_q[341]
  PIN vm_q[342]
    DIRECTION INPUT ;
    USE SIGNAL ;
    PORT
      LAYER M4 ;
        RECT  0 44.304 0.084 44.328 ;
    END
  END vm_q[342]
  PIN vm_q[343]
    DIRECTION INPUT ;
    USE SIGNAL ;
    PORT
      LAYER M4 ;
        RECT  0 44.4 0.084 44.424 ;
    END
  END vm_q[343]
  PIN vm_q[344]
    DIRECTION INPUT ;
    USE SIGNAL ;
    PORT
      LAYER M4 ;
        RECT  0 44.496 0.084 44.52 ;
    END
  END vm_q[344]
  PIN vm_q[345]
    DIRECTION INPUT ;
    USE SIGNAL ;
    PORT
      LAYER M4 ;
        RECT  0 44.592 0.084 44.616 ;
    END
  END vm_q[345]
  PIN vm_q[346]
    DIRECTION INPUT ;
    USE SIGNAL ;
    PORT
      LAYER M4 ;
        RECT  0 44.688 0.084 44.712 ;
    END
  END vm_q[346]
  PIN vm_q[347]
    DIRECTION INPUT ;
    USE SIGNAL ;
    PORT
      LAYER M4 ;
        RECT  0 44.784 0.084 44.808 ;
    END
  END vm_q[347]
  PIN vm_q[348]
    DIRECTION INPUT ;
    USE SIGNAL ;
    PORT
      LAYER M4 ;
        RECT  0 44.88 0.084 44.904 ;
    END
  END vm_q[348]
  PIN vm_q[349]
    DIRECTION INPUT ;
    USE SIGNAL ;
    PORT
      LAYER M4 ;
        RECT  0 44.976 0.084 45 ;
    END
  END vm_q[349]
  PIN vm_q[34]
    DIRECTION INPUT ;
    USE SIGNAL ;
    PORT
      LAYER M4 ;
        RECT  0 61.584 0.084 61.608 ;
    END
  END vm_q[34]
  PIN vm_q[350]
    DIRECTION INPUT ;
    USE SIGNAL ;
    PORT
      LAYER M4 ;
        RECT  0 45.072 0.084 45.096 ;
    END
  END vm_q[350]
  PIN vm_q[351]
    DIRECTION INPUT ;
    USE SIGNAL ;
    PORT
      LAYER M4 ;
        RECT  0 45.168 0.084 45.192 ;
    END
  END vm_q[351]
  PIN vm_q[352]
    DIRECTION INPUT ;
    USE SIGNAL ;
    PORT
      LAYER M4 ;
        RECT  0 6.864 0.084 6.888 ;
    END
  END vm_q[352]
  PIN vm_q[353]
    DIRECTION INPUT ;
    USE SIGNAL ;
    PORT
      LAYER M4 ;
        RECT  0 6.96 0.084 6.984 ;
    END
  END vm_q[353]
  PIN vm_q[354]
    DIRECTION INPUT ;
    USE SIGNAL ;
    PORT
      LAYER M4 ;
        RECT  0 7.056 0.084 7.08 ;
    END
  END vm_q[354]
  PIN vm_q[355]
    DIRECTION INPUT ;
    USE SIGNAL ;
    PORT
      LAYER M4 ;
        RECT  0 7.152 0.084 7.176 ;
    END
  END vm_q[355]
  PIN vm_q[356]
    DIRECTION INPUT ;
    USE SIGNAL ;
    PORT
      LAYER M4 ;
        RECT  0 7.248 0.084 7.272 ;
    END
  END vm_q[356]
  PIN vm_q[357]
    DIRECTION INPUT ;
    USE SIGNAL ;
    PORT
      LAYER M4 ;
        RECT  0 7.344 0.084 7.368 ;
    END
  END vm_q[357]
  PIN vm_q[358]
    DIRECTION INPUT ;
    USE SIGNAL ;
    PORT
      LAYER M4 ;
        RECT  0 7.44 0.084 7.464 ;
    END
  END vm_q[358]
  PIN vm_q[359]
    DIRECTION INPUT ;
    USE SIGNAL ;
    PORT
      LAYER M4 ;
        RECT  0 7.536 0.084 7.56 ;
    END
  END vm_q[359]
  PIN vm_q[35]
    DIRECTION INPUT ;
    USE SIGNAL ;
    PORT
      LAYER M4 ;
        RECT  0 61.68 0.084 61.704 ;
    END
  END vm_q[35]
  PIN vm_q[360]
    DIRECTION INPUT ;
    USE SIGNAL ;
    PORT
      LAYER M4 ;
        RECT  0 7.632 0.084 7.656 ;
    END
  END vm_q[360]
  PIN vm_q[361]
    DIRECTION INPUT ;
    USE SIGNAL ;
    PORT
      LAYER M4 ;
        RECT  0 7.728 0.084 7.752 ;
    END
  END vm_q[361]
  PIN vm_q[362]
    DIRECTION INPUT ;
    USE SIGNAL ;
    PORT
      LAYER M4 ;
        RECT  0 7.824 0.084 7.848 ;
    END
  END vm_q[362]
  PIN vm_q[363]
    DIRECTION INPUT ;
    USE SIGNAL ;
    PORT
      LAYER M4 ;
        RECT  0 7.92 0.084 7.944 ;
    END
  END vm_q[363]
  PIN vm_q[364]
    DIRECTION INPUT ;
    USE SIGNAL ;
    PORT
      LAYER M4 ;
        RECT  0 8.016 0.084 8.04 ;
    END
  END vm_q[364]
  PIN vm_q[365]
    DIRECTION INPUT ;
    USE SIGNAL ;
    PORT
      LAYER M4 ;
        RECT  0 8.112 0.084 8.136 ;
    END
  END vm_q[365]
  PIN vm_q[366]
    DIRECTION INPUT ;
    USE SIGNAL ;
    PORT
      LAYER M4 ;
        RECT  0 8.208 0.084 8.232 ;
    END
  END vm_q[366]
  PIN vm_q[367]
    DIRECTION INPUT ;
    USE SIGNAL ;
    PORT
      LAYER M4 ;
        RECT  0 8.304 0.084 8.328 ;
    END
  END vm_q[367]
  PIN vm_q[368]
    DIRECTION INPUT ;
    USE SIGNAL ;
    PORT
      LAYER M4 ;
        RECT  0 8.4 0.084 8.424 ;
    END
  END vm_q[368]
  PIN vm_q[369]
    DIRECTION INPUT ;
    USE SIGNAL ;
    PORT
      LAYER M4 ;
        RECT  0 8.496 0.084 8.52 ;
    END
  END vm_q[369]
  PIN vm_q[36]
    DIRECTION INPUT ;
    USE SIGNAL ;
    PORT
      LAYER M4 ;
        RECT  0 61.776 0.084 61.8 ;
    END
  END vm_q[36]
  PIN vm_q[370]
    DIRECTION INPUT ;
    USE SIGNAL ;
    PORT
      LAYER M4 ;
        RECT  0 8.592 0.084 8.616 ;
    END
  END vm_q[370]
  PIN vm_q[371]
    DIRECTION INPUT ;
    USE SIGNAL ;
    PORT
      LAYER M4 ;
        RECT  0 8.688 0.084 8.712 ;
    END
  END vm_q[371]
  PIN vm_q[372]
    DIRECTION INPUT ;
    USE SIGNAL ;
    PORT
      LAYER M4 ;
        RECT  0 8.784 0.084 8.808 ;
    END
  END vm_q[372]
  PIN vm_q[373]
    DIRECTION INPUT ;
    USE SIGNAL ;
    PORT
      LAYER M4 ;
        RECT  0 8.88 0.084 8.904 ;
    END
  END vm_q[373]
  PIN vm_q[374]
    DIRECTION INPUT ;
    USE SIGNAL ;
    PORT
      LAYER M4 ;
        RECT  0 8.976 0.084 9 ;
    END
  END vm_q[374]
  PIN vm_q[375]
    DIRECTION INPUT ;
    USE SIGNAL ;
    PORT
      LAYER M4 ;
        RECT  0 9.072 0.084 9.096 ;
    END
  END vm_q[375]
  PIN vm_q[376]
    DIRECTION INPUT ;
    USE SIGNAL ;
    PORT
      LAYER M4 ;
        RECT  0 9.168 0.084 9.192 ;
    END
  END vm_q[376]
  PIN vm_q[377]
    DIRECTION INPUT ;
    USE SIGNAL ;
    PORT
      LAYER M4 ;
        RECT  0 9.264 0.084 9.288 ;
    END
  END vm_q[377]
  PIN vm_q[378]
    DIRECTION INPUT ;
    USE SIGNAL ;
    PORT
      LAYER M4 ;
        RECT  0 9.36 0.084 9.384 ;
    END
  END vm_q[378]
  PIN vm_q[379]
    DIRECTION INPUT ;
    USE SIGNAL ;
    PORT
      LAYER M4 ;
        RECT  0 9.456 0.084 9.48 ;
    END
  END vm_q[379]
  PIN vm_q[37]
    DIRECTION INPUT ;
    USE SIGNAL ;
    PORT
      LAYER M4 ;
        RECT  0 61.872 0.084 61.896 ;
    END
  END vm_q[37]
  PIN vm_q[380]
    DIRECTION INPUT ;
    USE SIGNAL ;
    PORT
      LAYER M4 ;
        RECT  0 9.552 0.084 9.576 ;
    END
  END vm_q[380]
  PIN vm_q[381]
    DIRECTION INPUT ;
    USE SIGNAL ;
    PORT
      LAYER M4 ;
        RECT  0 9.648 0.084 9.672 ;
    END
  END vm_q[381]
  PIN vm_q[382]
    DIRECTION INPUT ;
    USE SIGNAL ;
    PORT
      LAYER M4 ;
        RECT  0 9.744 0.084 9.768 ;
    END
  END vm_q[382]
  PIN vm_q[383]
    DIRECTION INPUT ;
    USE SIGNAL ;
    PORT
      LAYER M4 ;
        RECT  0 9.84 0.084 9.864 ;
    END
  END vm_q[383]
  PIN vm_q[38]
    DIRECTION INPUT ;
    USE SIGNAL ;
    PORT
      LAYER M4 ;
        RECT  0 61.968 0.084 61.992 ;
    END
  END vm_q[38]
  PIN vm_q[39]
    DIRECTION INPUT ;
    USE SIGNAL ;
    PORT
      LAYER M4 ;
        RECT  0 62.064 0.084 62.088 ;
    END
  END vm_q[39]
  PIN vm_q[3]
    DIRECTION INPUT ;
    USE SIGNAL ;
    PORT
      LAYER M4 ;
        RECT  0 17.136 0.084 17.16 ;
    END
  END vm_q[3]
  PIN vm_q[40]
    DIRECTION INPUT ;
    USE SIGNAL ;
    PORT
      LAYER M4 ;
        RECT  0 62.16 0.084 62.184 ;
    END
  END vm_q[40]
  PIN vm_q[41]
    DIRECTION INPUT ;
    USE SIGNAL ;
    PORT
      LAYER M4 ;
        RECT  0 62.256 0.084 62.28 ;
    END
  END vm_q[41]
  PIN vm_q[42]
    DIRECTION INPUT ;
    USE SIGNAL ;
    PORT
      LAYER M4 ;
        RECT  0 62.352 0.084 62.376 ;
    END
  END vm_q[42]
  PIN vm_q[43]
    DIRECTION INPUT ;
    USE SIGNAL ;
    PORT
      LAYER M4 ;
        RECT  0 62.448 0.084 62.472 ;
    END
  END vm_q[43]
  PIN vm_q[44]
    DIRECTION INPUT ;
    USE SIGNAL ;
    PORT
      LAYER M4 ;
        RECT  0 62.544 0.084 62.568 ;
    END
  END vm_q[44]
  PIN vm_q[45]
    DIRECTION INPUT ;
    USE SIGNAL ;
    PORT
      LAYER M4 ;
        RECT  0 62.64 0.084 62.664 ;
    END
  END vm_q[45]
  PIN vm_q[46]
    DIRECTION INPUT ;
    USE SIGNAL ;
    PORT
      LAYER M4 ;
        RECT  0 62.736 0.084 62.76 ;
    END
  END vm_q[46]
  PIN vm_q[47]
    DIRECTION INPUT ;
    USE SIGNAL ;
    PORT
      LAYER M4 ;
        RECT  0 62.832 0.084 62.856 ;
    END
  END vm_q[47]
  PIN vm_q[48]
    DIRECTION INPUT ;
    USE SIGNAL ;
    PORT
      LAYER M4 ;
        RECT  0 62.928 0.084 62.952 ;
    END
  END vm_q[48]
  PIN vm_q[49]
    DIRECTION INPUT ;
    USE SIGNAL ;
    PORT
      LAYER M4 ;
        RECT  0 63.024 0.084 63.048 ;
    END
  END vm_q[49]
  PIN vm_q[4]
    DIRECTION INPUT ;
    USE SIGNAL ;
    PORT
      LAYER M4 ;
        RECT  0 17.232 0.084 17.256 ;
    END
  END vm_q[4]
  PIN vm_q[50]
    DIRECTION INPUT ;
    USE SIGNAL ;
    PORT
      LAYER M4 ;
        RECT  0 63.12 0.084 63.144 ;
    END
  END vm_q[50]
  PIN vm_q[51]
    DIRECTION INPUT ;
    USE SIGNAL ;
    PORT
      LAYER M4 ;
        RECT  0 63.216 0.084 63.24 ;
    END
  END vm_q[51]
  PIN vm_q[52]
    DIRECTION INPUT ;
    USE SIGNAL ;
    PORT
      LAYER M4 ;
        RECT  0 63.312 0.084 63.336 ;
    END
  END vm_q[52]
  PIN vm_q[53]
    DIRECTION INPUT ;
    USE SIGNAL ;
    PORT
      LAYER M4 ;
        RECT  0 63.408 0.084 63.432 ;
    END
  END vm_q[53]
  PIN vm_q[54]
    DIRECTION INPUT ;
    USE SIGNAL ;
    PORT
      LAYER M4 ;
        RECT  0 63.504 0.084 63.528 ;
    END
  END vm_q[54]
  PIN vm_q[55]
    DIRECTION INPUT ;
    USE SIGNAL ;
    PORT
      LAYER M4 ;
        RECT  0 63.6 0.084 63.624 ;
    END
  END vm_q[55]
  PIN vm_q[56]
    DIRECTION INPUT ;
    USE SIGNAL ;
    PORT
      LAYER M4 ;
        RECT  0 63.696 0.084 63.72 ;
    END
  END vm_q[56]
  PIN vm_q[57]
    DIRECTION INPUT ;
    USE SIGNAL ;
    PORT
      LAYER M4 ;
        RECT  0 63.792 0.084 63.816 ;
    END
  END vm_q[57]
  PIN vm_q[58]
    DIRECTION INPUT ;
    USE SIGNAL ;
    PORT
      LAYER M4 ;
        RECT  0 63.888 0.084 63.912 ;
    END
  END vm_q[58]
  PIN vm_q[59]
    DIRECTION INPUT ;
    USE SIGNAL ;
    PORT
      LAYER M4 ;
        RECT  0 63.984 0.084 64.008 ;
    END
  END vm_q[59]
  PIN vm_q[5]
    DIRECTION INPUT ;
    USE SIGNAL ;
    PORT
      LAYER M4 ;
        RECT  0 17.328 0.084 17.352 ;
    END
  END vm_q[5]
  PIN vm_q[60]
    DIRECTION INPUT ;
    USE SIGNAL ;
    PORT
      LAYER M4 ;
        RECT  0 64.08 0.084 64.104 ;
    END
  END vm_q[60]
  PIN vm_q[61]
    DIRECTION INPUT ;
    USE SIGNAL ;
    PORT
      LAYER M4 ;
        RECT  0 64.176 0.084 64.2 ;
    END
  END vm_q[61]
  PIN vm_q[62]
    DIRECTION INPUT ;
    USE SIGNAL ;
    PORT
      LAYER M4 ;
        RECT  0 64.272 0.084 64.296 ;
    END
  END vm_q[62]
  PIN vm_q[63]
    DIRECTION INPUT ;
    USE SIGNAL ;
    PORT
      LAYER M4 ;
        RECT  0 64.368 0.084 64.392 ;
    END
  END vm_q[63]
  PIN vm_q[64]
    DIRECTION INPUT ;
    USE SIGNAL ;
    PORT
      LAYER M4 ;
        RECT  0 52.176 0.084 52.2 ;
    END
  END vm_q[64]
  PIN vm_q[65]
    DIRECTION INPUT ;
    USE SIGNAL ;
    PORT
      LAYER M4 ;
        RECT  0 52.272 0.084 52.296 ;
    END
  END vm_q[65]
  PIN vm_q[66]
    DIRECTION INPUT ;
    USE SIGNAL ;
    PORT
      LAYER M4 ;
        RECT  0 52.368 0.084 52.392 ;
    END
  END vm_q[66]
  PIN vm_q[67]
    DIRECTION INPUT ;
    USE SIGNAL ;
    PORT
      LAYER M4 ;
        RECT  0 52.464 0.084 52.488 ;
    END
  END vm_q[67]
  PIN vm_q[68]
    DIRECTION INPUT ;
    USE SIGNAL ;
    PORT
      LAYER M4 ;
        RECT  0 52.56 0.084 52.584 ;
    END
  END vm_q[68]
  PIN vm_q[69]
    DIRECTION INPUT ;
    USE SIGNAL ;
    PORT
      LAYER M4 ;
        RECT  0 52.656 0.084 52.68 ;
    END
  END vm_q[69]
  PIN vm_q[6]
    DIRECTION INPUT ;
    USE SIGNAL ;
    PORT
      LAYER M4 ;
        RECT  0 17.424 0.084 17.448 ;
    END
  END vm_q[6]
  PIN vm_q[70]
    DIRECTION INPUT ;
    USE SIGNAL ;
    PORT
      LAYER M4 ;
        RECT  0 52.752 0.084 52.776 ;
    END
  END vm_q[70]
  PIN vm_q[71]
    DIRECTION INPUT ;
    USE SIGNAL ;
    PORT
      LAYER M4 ;
        RECT  0 52.848 0.084 52.872 ;
    END
  END vm_q[71]
  PIN vm_q[72]
    DIRECTION INPUT ;
    USE SIGNAL ;
    PORT
      LAYER M4 ;
        RECT  0 52.944 0.084 52.968 ;
    END
  END vm_q[72]
  PIN vm_q[73]
    DIRECTION INPUT ;
    USE SIGNAL ;
    PORT
      LAYER M4 ;
        RECT  0 53.04 0.084 53.064 ;
    END
  END vm_q[73]
  PIN vm_q[74]
    DIRECTION INPUT ;
    USE SIGNAL ;
    PORT
      LAYER M4 ;
        RECT  0 53.136 0.084 53.16 ;
    END
  END vm_q[74]
  PIN vm_q[75]
    DIRECTION INPUT ;
    USE SIGNAL ;
    PORT
      LAYER M4 ;
        RECT  0 53.232 0.084 53.256 ;
    END
  END vm_q[75]
  PIN vm_q[76]
    DIRECTION INPUT ;
    USE SIGNAL ;
    PORT
      LAYER M4 ;
        RECT  0 53.328 0.084 53.352 ;
    END
  END vm_q[76]
  PIN vm_q[77]
    DIRECTION INPUT ;
    USE SIGNAL ;
    PORT
      LAYER M4 ;
        RECT  0 53.424 0.084 53.448 ;
    END
  END vm_q[77]
  PIN vm_q[78]
    DIRECTION INPUT ;
    USE SIGNAL ;
    PORT
      LAYER M4 ;
        RECT  0 53.52 0.084 53.544 ;
    END
  END vm_q[78]
  PIN vm_q[79]
    DIRECTION INPUT ;
    USE SIGNAL ;
    PORT
      LAYER M4 ;
        RECT  0 53.616 0.084 53.64 ;
    END
  END vm_q[79]
  PIN vm_q[7]
    DIRECTION INPUT ;
    USE SIGNAL ;
    PORT
      LAYER M4 ;
        RECT  0 17.52 0.084 17.544 ;
    END
  END vm_q[7]
  PIN vm_q[80]
    DIRECTION INPUT ;
    USE SIGNAL ;
    PORT
      LAYER M4 ;
        RECT  0 53.712 0.084 53.736 ;
    END
  END vm_q[80]
  PIN vm_q[81]
    DIRECTION INPUT ;
    USE SIGNAL ;
    PORT
      LAYER M4 ;
        RECT  0 53.808 0.084 53.832 ;
    END
  END vm_q[81]
  PIN vm_q[82]
    DIRECTION INPUT ;
    USE SIGNAL ;
    PORT
      LAYER M4 ;
        RECT  0 53.904 0.084 53.928 ;
    END
  END vm_q[82]
  PIN vm_q[83]
    DIRECTION INPUT ;
    USE SIGNAL ;
    PORT
      LAYER M4 ;
        RECT  0 54 0.084 54.024 ;
    END
  END vm_q[83]
  PIN vm_q[84]
    DIRECTION INPUT ;
    USE SIGNAL ;
    PORT
      LAYER M4 ;
        RECT  0 54.096 0.084 54.12 ;
    END
  END vm_q[84]
  PIN vm_q[85]
    DIRECTION INPUT ;
    USE SIGNAL ;
    PORT
      LAYER M4 ;
        RECT  0 54.192 0.084 54.216 ;
    END
  END vm_q[85]
  PIN vm_q[86]
    DIRECTION INPUT ;
    USE SIGNAL ;
    PORT
      LAYER M4 ;
        RECT  0 54.288 0.084 54.312 ;
    END
  END vm_q[86]
  PIN vm_q[87]
    DIRECTION INPUT ;
    USE SIGNAL ;
    PORT
      LAYER M4 ;
        RECT  0 54.384 0.084 54.408 ;
    END
  END vm_q[87]
  PIN vm_q[88]
    DIRECTION INPUT ;
    USE SIGNAL ;
    PORT
      LAYER M4 ;
        RECT  0 54.48 0.084 54.504 ;
    END
  END vm_q[88]
  PIN vm_q[89]
    DIRECTION INPUT ;
    USE SIGNAL ;
    PORT
      LAYER M4 ;
        RECT  0 54.576 0.084 54.6 ;
    END
  END vm_q[89]
  PIN vm_q[8]
    DIRECTION INPUT ;
    USE SIGNAL ;
    PORT
      LAYER M4 ;
        RECT  0 17.616 0.084 17.64 ;
    END
  END vm_q[8]
  PIN vm_q[90]
    DIRECTION INPUT ;
    USE SIGNAL ;
    PORT
      LAYER M4 ;
        RECT  0 54.672 0.084 54.696 ;
    END
  END vm_q[90]
  PIN vm_q[91]
    DIRECTION INPUT ;
    USE SIGNAL ;
    PORT
      LAYER M4 ;
        RECT  0 54.768 0.084 54.792 ;
    END
  END vm_q[91]
  PIN vm_q[92]
    DIRECTION INPUT ;
    USE SIGNAL ;
    PORT
      LAYER M4 ;
        RECT  0 54.864 0.084 54.888 ;
    END
  END vm_q[92]
  PIN vm_q[93]
    DIRECTION INPUT ;
    USE SIGNAL ;
    PORT
      LAYER M4 ;
        RECT  0 54.96 0.084 54.984 ;
    END
  END vm_q[93]
  PIN vm_q[94]
    DIRECTION INPUT ;
    USE SIGNAL ;
    PORT
      LAYER M4 ;
        RECT  0 55.056 0.084 55.08 ;
    END
  END vm_q[94]
  PIN vm_q[95]
    DIRECTION INPUT ;
    USE SIGNAL ;
    PORT
      LAYER M4 ;
        RECT  0 55.152 0.084 55.176 ;
    END
  END vm_q[95]
  PIN vm_q[96]
    DIRECTION INPUT ;
    USE SIGNAL ;
    PORT
      LAYER M4 ;
        RECT  0 19.92 0.084 19.944 ;
    END
  END vm_q[96]
  PIN vm_q[97]
    DIRECTION INPUT ;
    USE SIGNAL ;
    PORT
      LAYER M4 ;
        RECT  0 20.016 0.084 20.04 ;
    END
  END vm_q[97]
  PIN vm_q[98]
    DIRECTION INPUT ;
    USE SIGNAL ;
    PORT
      LAYER M4 ;
        RECT  0 20.112 0.084 20.136 ;
    END
  END vm_q[98]
  PIN vm_q[99]
    DIRECTION INPUT ;
    USE SIGNAL ;
    PORT
      LAYER M4 ;
        RECT  0 20.208 0.084 20.232 ;
    END
  END vm_q[99]
  PIN vm_q[9]
    DIRECTION INPUT ;
    USE SIGNAL ;
    PORT
      LAYER M4 ;
        RECT  0 17.712 0.084 17.736 ;
    END
  END vm_q[9]
  PIN VDD
    DIRECTION INOUT ;
    USE POWER ;
    PORT
      LAYER M5 ;
        RECT  67.392 2.151 67.512 69.129 ;
        RECT  61.992 2.151 62.112 69.129 ;
        RECT  56.592 2.151 56.712 69.129 ;
        RECT  51.192 2.151 51.312 69.129 ;
        RECT  45.792 2.151 45.912 69.129 ;
        RECT  40.392 2.151 40.512 69.129 ;
        RECT  34.992 2.151 35.112 69.129 ;
        RECT  29.592 2.151 29.712 69.129 ;
        RECT  24.192 2.151 24.312 69.129 ;
        RECT  18.792 2.151 18.912 69.129 ;
        RECT  13.392 2.151 13.512 69.129 ;
        RECT  7.992 2.151 8.112 69.129 ;
        RECT  2.592 2.151 2.712 69.129 ;
    END
  END VDD
  PIN VSS
    DIRECTION INOUT ;
    USE GROUND ;
    PORT
      LAYER M5 ;
        RECT  67.2 2.137 67.32 69.143 ;
        RECT  61.8 2.137 61.92 69.143 ;
        RECT  56.4 2.137 56.52 69.143 ;
        RECT  51 2.137 51.12 69.143 ;
        RECT  45.6 2.137 45.72 69.143 ;
        RECT  40.2 2.137 40.32 69.143 ;
        RECT  34.8 2.137 34.92 69.143 ;
        RECT  29.4 2.137 29.52 69.143 ;
        RECT  24 2.137 24.12 69.143 ;
        RECT  18.6 2.137 18.72 69.143 ;
        RECT  13.2 2.137 13.32 69.143 ;
        RECT  7.8 2.137 7.92 69.143 ;
        RECT  2.4 2.137 2.52 69.143 ;
    END
  END VSS
  # OT_OBS_CLOSED layer=M5 d_um=1.536 added=214
  OBS
    LAYER RVTN ;
     RECT  2.16 2.16 69.12 2.295 ;
     RECT  2.16 2.565 69.12 2.835 ;
     RECT  2.16 3.105 69.12 3.375 ;
     RECT  2.16 3.645 69.12 3.915 ;
     RECT  2.16 4.185 69.12 4.455 ;
     RECT  2.16 4.725 69.12 4.995 ;
     RECT  2.16 5.265 69.12 5.535 ;
     RECT  2.16 5.805 69.12 6.075 ;
     RECT  2.16 6.345 69.12 6.615 ;
     RECT  2.16 6.885 69.12 7.155 ;
     RECT  2.16 7.425 69.12 7.695 ;
     RECT  2.16 7.965 69.12 8.235 ;
     RECT  2.16 8.505 69.12 8.775 ;
     RECT  2.16 9.045 69.12 9.315 ;
     RECT  2.16 9.585 69.12 9.855 ;
     RECT  2.16 10.125 69.12 10.395 ;
     RECT  2.16 10.665 69.12 10.935 ;
     RECT  2.16 11.205 69.12 11.475 ;
     RECT  2.16 11.745 69.12 12.015 ;
     RECT  2.16 12.285 69.12 12.555 ;
     RECT  2.16 12.825 69.12 13.095 ;
     RECT  2.16 13.365 69.12 13.635 ;
     RECT  2.16 13.905 69.12 14.175 ;
     RECT  2.16 14.445 69.12 14.715 ;
     RECT  2.16 14.985 69.12 15.255 ;
     RECT  2.16 15.525 69.12 15.795 ;
     RECT  2.16 16.065 69.12 16.335 ;
     RECT  2.16 16.605 69.12 16.875 ;
     RECT  2.16 17.145 69.12 17.415 ;
     RECT  2.16 17.685 69.12 17.955 ;
     RECT  2.16 18.225 69.12 18.495 ;
     RECT  2.16 18.765 69.12 19.035 ;
     RECT  2.16 19.305 69.12 19.575 ;
     RECT  2.16 19.845 69.12 20.115 ;
     RECT  2.16 20.385 69.12 20.655 ;
     RECT  2.16 20.925 69.12 21.195 ;
     RECT  2.16 21.465 69.12 21.735 ;
     RECT  2.16 22.005 69.12 22.275 ;
     RECT  2.16 22.545 69.12 22.815 ;
     RECT  2.16 23.085 69.12 23.355 ;
     RECT  2.16 23.625 69.12 23.895 ;
     RECT  2.16 24.165 69.12 24.435 ;
     RECT  2.16 24.705 69.12 24.975 ;
     RECT  2.16 25.245 69.12 25.515 ;
     RECT  2.16 25.785 69.12 26.055 ;
     RECT  2.16 26.325 69.12 26.595 ;
     RECT  2.16 26.865 69.12 27.135 ;
     RECT  2.16 27.405 69.12 27.675 ;
     RECT  2.16 27.945 69.12 28.215 ;
     RECT  2.16 28.485 69.12 28.755 ;
     RECT  2.16 29.025 69.12 29.295 ;
     RECT  2.16 29.565 69.12 29.835 ;
     RECT  2.16 30.105 69.12 30.375 ;
     RECT  2.16 30.645 69.12 30.915 ;
     RECT  2.16 31.185 69.12 31.455 ;
     RECT  2.16 31.725 69.12 31.995 ;
     RECT  2.16 32.265 69.12 32.535 ;
     RECT  2.16 32.805 69.12 33.075 ;
     RECT  2.16 33.345 69.12 33.615 ;
     RECT  2.16 33.885 69.12 34.155 ;
     RECT  2.16 34.425 69.12 34.695 ;
     RECT  2.16 34.965 69.12 35.235 ;
     RECT  2.16 35.505 69.12 35.775 ;
     RECT  2.16 36.045 69.12 36.315 ;
     RECT  2.16 36.585 69.12 36.855 ;
     RECT  2.16 37.125 69.12 37.395 ;
     RECT  2.16 37.665 69.12 37.935 ;
     RECT  2.16 38.205 69.12 38.475 ;
     RECT  2.16 38.745 69.12 39.015 ;
     RECT  2.16 39.285 69.12 39.555 ;
     RECT  2.16 39.825 69.12 40.095 ;
     RECT  2.16 40.365 69.12 40.635 ;
     RECT  2.16 40.905 69.12 41.175 ;
     RECT  2.16 41.445 69.12 41.715 ;
     RECT  2.16 41.985 69.12 42.255 ;
     RECT  2.16 42.525 69.12 42.795 ;
     RECT  2.16 43.065 69.12 43.335 ;
     RECT  2.16 43.605 69.12 43.875 ;
     RECT  2.16 44.145 69.12 44.415 ;
     RECT  2.16 44.685 69.12 44.955 ;
     RECT  2.16 45.225 69.12 45.495 ;
     RECT  2.16 45.765 69.12 46.035 ;
     RECT  2.16 46.305 69.12 46.575 ;
     RECT  2.16 46.845 69.12 47.115 ;
     RECT  2.16 47.385 69.12 47.655 ;
     RECT  2.16 47.925 69.12 48.195 ;
     RECT  2.16 48.465 69.12 48.735 ;
     RECT  2.16 49.005 69.12 49.275 ;
     RECT  2.16 49.545 69.12 49.815 ;
     RECT  2.16 50.085 69.12 50.355 ;
     RECT  2.16 50.625 69.12 50.895 ;
     RECT  2.16 51.165 69.12 51.435 ;
     RECT  2.16 51.705 69.12 51.975 ;
     RECT  2.16 52.245 69.12 52.515 ;
     RECT  2.16 52.785 69.12 53.055 ;
     RECT  2.16 53.325 69.12 53.595 ;
     RECT  2.16 53.865 69.12 54.135 ;
     RECT  2.16 54.405 69.12 54.675 ;
     RECT  2.16 54.945 69.12 55.215 ;
     RECT  2.16 55.485 69.12 55.755 ;
     RECT  2.16 56.025 69.12 56.295 ;
     RECT  2.16 56.565 69.12 56.835 ;
     RECT  2.16 57.105 69.12 57.375 ;
     RECT  2.16 57.645 69.12 57.915 ;
     RECT  2.16 58.185 69.12 58.455 ;
     RECT  2.16 58.725 69.12 58.995 ;
     RECT  2.16 59.265 69.12 59.535 ;
     RECT  2.16 59.805 69.12 60.075 ;
     RECT  2.16 60.345 69.12 60.615 ;
     RECT  2.16 60.885 69.12 61.155 ;
     RECT  2.16 61.425 69.12 61.695 ;
     RECT  2.16 61.965 69.12 62.235 ;
     RECT  2.16 62.505 69.12 62.775 ;
     RECT  2.16 63.045 69.12 63.315 ;
     RECT  2.16 63.585 69.12 63.855 ;
     RECT  2.16 64.125 69.12 64.395 ;
     RECT  2.16 64.665 69.12 64.935 ;
     RECT  2.16 65.205 69.12 65.475 ;
     RECT  2.16 65.745 69.12 66.015 ;
     RECT  2.16 66.285 69.12 66.555 ;
     RECT  2.16 66.825 69.12 67.095 ;
     RECT  2.16 67.365 69.12 67.635 ;
     RECT  2.16 67.905 69.12 68.175 ;
     RECT  2.16 68.445 69.12 68.715 ;
     RECT  2.16 68.985 69.12 69.12 ;
    LAYER RVTP ;
     RECT  2.16 2.295 69.12 2.565 ;
     RECT  2.16 2.835 69.12 3.105 ;
     RECT  2.16 3.375 69.12 3.645 ;
     RECT  2.16 3.915 69.12 4.185 ;
     RECT  2.16 4.455 69.12 4.725 ;
     RECT  2.16 4.995 69.12 5.265 ;
     RECT  2.16 5.535 69.12 5.805 ;
     RECT  2.16 6.075 69.12 6.345 ;
     RECT  2.16 6.615 69.12 6.885 ;
     RECT  2.16 7.155 69.12 7.425 ;
     RECT  2.16 7.695 69.12 7.965 ;
     RECT  2.16 8.235 69.12 8.505 ;
     RECT  2.16 8.775 69.12 9.045 ;
     RECT  2.16 9.315 69.12 9.585 ;
     RECT  2.16 9.855 69.12 10.125 ;
     RECT  2.16 10.395 69.12 10.665 ;
     RECT  2.16 10.935 69.12 11.205 ;
     RECT  2.16 11.475 69.12 11.745 ;
     RECT  2.16 12.015 69.12 12.285 ;
     RECT  2.16 12.555 69.12 12.825 ;
     RECT  2.16 13.095 69.12 13.365 ;
     RECT  2.16 13.635 69.12 13.905 ;
     RECT  2.16 14.175 69.12 14.445 ;
     RECT  2.16 14.715 69.12 14.985 ;
     RECT  2.16 15.255 69.12 15.525 ;
     RECT  2.16 15.795 69.12 16.065 ;
     RECT  2.16 16.335 69.12 16.605 ;
     RECT  2.16 16.875 69.12 17.145 ;
     RECT  2.16 17.415 69.12 17.685 ;
     RECT  2.16 17.955 69.12 18.225 ;
     RECT  2.16 18.495 69.12 18.765 ;
     RECT  2.16 19.035 69.12 19.305 ;
     RECT  2.16 19.575 69.12 19.845 ;
     RECT  2.16 20.115 69.12 20.385 ;
     RECT  2.16 20.655 69.12 20.925 ;
     RECT  2.16 21.195 69.12 21.465 ;
     RECT  2.16 21.735 69.12 22.005 ;
     RECT  2.16 22.275 69.12 22.545 ;
     RECT  2.16 22.815 69.12 23.085 ;
     RECT  2.16 23.355 69.12 23.625 ;
     RECT  2.16 23.895 69.12 24.165 ;
     RECT  2.16 24.435 69.12 24.705 ;
     RECT  2.16 24.975 69.12 25.245 ;
     RECT  2.16 25.515 69.12 25.785 ;
     RECT  2.16 26.055 69.12 26.325 ;
     RECT  2.16 26.595 69.12 26.865 ;
     RECT  2.16 27.135 69.12 27.405 ;
     RECT  2.16 27.675 69.12 27.945 ;
     RECT  2.16 28.215 69.12 28.485 ;
     RECT  2.16 28.755 69.12 29.025 ;
     RECT  2.16 29.295 69.12 29.565 ;
     RECT  2.16 29.835 69.12 30.105 ;
     RECT  2.16 30.375 69.12 30.645 ;
     RECT  2.16 30.915 69.12 31.185 ;
     RECT  2.16 31.455 69.12 31.725 ;
     RECT  2.16 31.995 69.12 32.265 ;
     RECT  2.16 32.535 69.12 32.805 ;
     RECT  2.16 33.075 69.12 33.345 ;
     RECT  2.16 33.615 69.12 33.885 ;
     RECT  2.16 34.155 69.12 34.425 ;
     RECT  2.16 34.695 69.12 34.965 ;
     RECT  2.16 35.235 69.12 35.505 ;
     RECT  2.16 35.775 69.12 36.045 ;
     RECT  2.16 36.315 69.12 36.585 ;
     RECT  2.16 36.855 69.12 37.125 ;
     RECT  2.16 37.395 69.12 37.665 ;
     RECT  2.16 37.935 69.12 38.205 ;
     RECT  2.16 38.475 69.12 38.745 ;
     RECT  2.16 39.015 69.12 39.285 ;
     RECT  2.16 39.555 69.12 39.825 ;
     RECT  2.16 40.095 69.12 40.365 ;
     RECT  2.16 40.635 69.12 40.905 ;
     RECT  2.16 41.175 69.12 41.445 ;
     RECT  2.16 41.715 69.12 41.985 ;
     RECT  2.16 42.255 69.12 42.525 ;
     RECT  2.16 42.795 69.12 43.065 ;
     RECT  2.16 43.335 69.12 43.605 ;
     RECT  2.16 43.875 69.12 44.145 ;
     RECT  2.16 44.415 69.12 44.685 ;
     RECT  2.16 44.955 69.12 45.225 ;
     RECT  2.16 45.495 69.12 45.765 ;
     RECT  2.16 46.035 69.12 46.305 ;
     RECT  2.16 46.575 69.12 46.845 ;
     RECT  2.16 47.115 69.12 47.385 ;
     RECT  2.16 47.655 69.12 47.925 ;
     RECT  2.16 48.195 69.12 48.465 ;
     RECT  2.16 48.735 69.12 49.005 ;
     RECT  2.16 49.275 69.12 49.545 ;
     RECT  2.16 49.815 69.12 50.085 ;
     RECT  2.16 50.355 69.12 50.625 ;
     RECT  2.16 50.895 69.12 51.165 ;
     RECT  2.16 51.435 69.12 51.705 ;
     RECT  2.16 51.975 69.12 52.245 ;
     RECT  2.16 52.515 69.12 52.785 ;
     RECT  2.16 53.055 69.12 53.325 ;
     RECT  2.16 53.595 69.12 53.865 ;
     RECT  2.16 54.135 69.12 54.405 ;
     RECT  2.16 54.675 69.12 54.945 ;
     RECT  2.16 55.215 69.12 55.485 ;
     RECT  2.16 55.755 69.12 56.025 ;
     RECT  2.16 56.295 69.12 56.565 ;
     RECT  2.16 56.835 69.12 57.105 ;
     RECT  2.16 57.375 69.12 57.645 ;
     RECT  2.16 57.915 69.12 58.185 ;
     RECT  2.16 58.455 69.12 58.725 ;
     RECT  2.16 58.995 69.12 59.265 ;
     RECT  2.16 59.535 69.12 59.805 ;
     RECT  2.16 60.075 69.12 60.345 ;
     RECT  2.16 60.615 69.12 60.885 ;
     RECT  2.16 61.155 69.12 61.425 ;
     RECT  2.16 61.695 69.12 61.965 ;
     RECT  2.16 62.235 69.12 62.505 ;
     RECT  2.16 62.775 69.12 63.045 ;
     RECT  2.16 63.315 69.12 63.585 ;
     RECT  2.16 63.855 69.12 64.125 ;
     RECT  2.16 64.395 69.12 64.665 ;
     RECT  2.16 64.935 69.12 65.205 ;
     RECT  2.16 65.475 69.12 65.745 ;
     RECT  2.16 66.015 69.12 66.285 ;
     RECT  2.16 66.555 69.12 66.825 ;
     RECT  2.16 67.095 69.12 67.365 ;
     RECT  2.16 67.635 69.12 67.905 ;
     RECT  2.16 68.175 69.12 68.445 ;
     RECT  2.16 68.715 69.12 68.985 ;
    LAYER M1 ;
     RECT  2.16 2.151 69.12 69.129 ;
    LAYER M2 ;
     RECT  0.031 56.691 0.103 56.709 ;
     RECT  0.103 56.574 0.131 56.709 ;
     RECT  0.103 42.732 0.139 42.75 ;
     RECT  0.103 53.532 0.139 53.55 ;
     RECT  0.031 54.378 0.139 54.396 ;
     RECT  0.103 62.514 0.139 63.27 ;
     RECT  0.139 13.068 0.175 13.086 ;
     RECT  0.103 23.751 0.175 23.769 ;
     RECT  0.139 31.23 0.175 31.248 ;
     RECT  0.103 45.081 0.211 45.522 ;
     RECT  0.175 23.751 0.239 23.85 ;
     RECT  0.139 44.118 0.239 44.136 ;
     RECT  0.239 23.832 0.275 23.85 ;
     RECT  0.211 21.672 0.347 21.69 ;
     RECT  0.139 42.498 0.347 42.75 ;
     RECT  0.211 45 0.535 45.522 ;
     RECT  0.103 46.548 0.535 46.566 ;
     RECT  0.103 17.586 0.671 17.604 ;
     RECT  0.131 56.574 0.671 56.592 ;
     RECT  0.103 40.104 1.147 40.122 ;
     RECT  1.147 40.032 1.175 40.122 ;
     RECT  1.147 17.766 1.183 17.784 ;
     RECT  1.147 59.778 1.219 59.796 ;
     RECT  0.175 31.23 1.399 31.788 ;
     RECT  1.399 14.148 1.435 14.166 ;
     RECT  0.175 12.834 1.471 13.086 ;
     RECT  1.399 50.058 1.687 50.076 ;
     RECT  1.183 17.766 1.723 17.982 ;
     RECT  1.399 31.23 1.723 32.022 ;
     RECT  1.723 26.334 1.759 26.352 ;
     RECT  1.759 26.262 1.795 26.352 ;
     RECT  0.211 24.75 1.975 24.768 ;
     RECT  1.399 57.15 2.083 57.168 ;
     RECT  0.571 10.404 2.155 10.422 ;
     RECT  0.347 42.732 2.155 42.75 ;
     RECT  2.155 10.404 2.16 10.854 ;
     RECT  0.103 11.682 2.16 11.7 ;
     RECT  1.471 12.834 2.16 13.392 ;
     RECT  1.435 14.148 2.16 14.4 ;
     RECT  2.119 16.578 2.16 16.596 ;
     RECT  1.723 17.766 2.16 18.72 ;
     RECT  1.147 21.672 2.16 21.69 ;
     RECT  1.399 23.328 2.16 23.346 ;
     RECT  1.975 24.75 2.16 25.2 ;
     RECT  1.795 26.262 2.16 26.82 ;
     RECT  1.723 31.23 2.16 32.058 ;
     RECT  1.687 38.142 2.16 38.16 ;
     RECT  1.175 40.032 2.16 40.05 ;
     RECT  2.155 41.994 2.16 42.75 ;
     RECT  0.535 44.226 2.16 44.244 ;
     RECT  0.535 45 2.16 46.566 ;
     RECT  1.687 50.058 2.16 50.454 ;
     RECT  0.175 51.48 2.16 51.498 ;
     RECT  0.139 53.532 2.16 54.396 ;
     RECT  2.083 56.502 2.16 57.168 ;
     RECT  0.535 59.004 2.16 59.022 ;
     RECT  1.219 59.778 2.16 60.408 ;
     RECT  0.139 62.514 2.16 63.54 ;
     RECT  2.047 64.602 2.16 64.62 ;
     RECT  2.155 65.916 2.16 66.006 ;
     RECT  1.111 67.95 2.16 68.238 ;
     RECT  2.839 0.216 2.939 0.234 ;
     RECT  5.935 0.036 9.535 0.054 ;
     RECT  9.535 0.036 9.967 0.198 ;
     RECT  9.967 0.036 10.183 0.549 ;
     RECT  10.183 0.036 10.967 0.594 ;
     RECT  10.967 0.036 11.075 0.279 ;
     RECT  11.075 0.036 12.587 0.09 ;
     RECT  12.587 0.072 13.127 0.09 ;
     RECT  2.16 2.151 14.287 69.129 ;
     RECT  14.287 2.106 14.711 69.129 ;
     RECT  14.711 2.151 16.987 69.129 ;
     RECT  16.987 2.106 17.591 69.129 ;
     RECT  22.387 0.036 22.999 0.054 ;
     RECT  22.999 0.036 27.059 0.126 ;
     RECT  27.059 0.036 27.203 0.09 ;
     RECT  27.203 0.072 29.147 0.09 ;
     RECT  17.591 2.151 37.723 69.129 ;
     RECT  37.723 2.106 38.795 69.129 ;
     RECT  38.795 2.151 40.459 69.129 ;
     RECT  40.459 2.106 40.955 69.129 ;
     RECT  40.955 2.151 45.103 69.129 ;
     RECT  45.103 2.106 46.103 69.129 ;
     RECT  47.587 0.036 47.767 0.054 ;
     RECT  46.103 2.151 49.963 69.129 ;
     RECT  47.767 0.036 50.179 0.09 ;
     RECT  49.963 2.106 50.431 69.129 ;
     RECT  50.431 2.07 50.963 69.129 ;
     RECT  50.963 2.106 51.683 69.129 ;
     RECT  50.179 0.036 54.203 0.126 ;
     RECT  54.203 0.108 54.635 0.126 ;
     RECT  51.683 2.151 69.12 69.129 ;
     RECT  69.12 39.456 69.431 54.396 ;
     RECT  69.12 7.236 69.467 8.334 ;
     RECT  69.467 7.938 69.503 8.334 ;
     RECT  69.503 7.938 69.539 7.956 ;
     RECT  69.12 9.864 69.539 13.284 ;
     RECT  69.431 39.456 69.539 40.464 ;
     RECT  69.12 68.724 69.539 68.742 ;
     RECT  69.12 38.016 69.827 38.034 ;
     RECT  69.12 60.246 69.827 61.11 ;
     RECT  69.539 39.456 69.863 40.356 ;
     RECT  69.863 39.636 69.935 40.356 ;
     RECT  69.12 55.566 70.115 58.914 ;
     RECT  69.12 62.676 70.115 63.774 ;
     RECT  69.935 39.87 70.151 40.356 ;
     RECT  69.431 41.346 70.151 54.396 ;
     RECT  70.151 39.996 70.187 40.356 ;
     RECT  70.187 39.996 70.259 40.014 ;
     RECT  69.12 14.526 70.619 29.754 ;
     RECT  70.115 55.566 70.619 58.644 ;
     RECT  70.619 14.526 70.655 29.394 ;
     RECT  69.12 30.546 70.655 35.226 ;
     RECT  69.12 36.216 70.655 36.234 ;
     RECT  70.619 55.566 70.655 58.554 ;
     RECT  69.539 9.864 70.663 10.116 ;
     RECT  69.539 10.908 70.663 13.284 ;
     RECT  70.663 9.864 70.691 13.284 ;
     RECT  70.655 30.654 70.691 35.226 ;
     RECT  70.655 55.566 70.691 57.834 ;
     RECT  69.12 64.746 70.691 67.464 ;
     RECT  70.691 9.864 70.727 12.924 ;
     RECT  70.655 17.226 70.727 29.394 ;
     RECT  70.691 30.654 70.727 34.182 ;
     RECT  70.691 34.974 70.727 35.226 ;
     RECT  70.151 41.346 70.727 54.324 ;
     RECT  70.691 55.566 70.727 57.096 ;
     RECT  70.691 66.258 70.727 67.464 ;
     RECT  70.727 9.864 70.763 11.232 ;
     RECT  70.655 14.526 70.763 16.434 ;
     RECT  70.727 17.226 70.763 25.578 ;
     RECT  70.727 26.91 70.763 28.512 ;
     RECT  70.727 30.654 70.763 31.914 ;
     RECT  70.727 32.706 70.763 33.714 ;
     RECT  70.727 41.346 70.763 46.332 ;
     RECT  70.727 47.16 70.763 54.324 ;
     RECT  70.691 64.746 70.763 65.502 ;
     RECT  70.763 9.864 70.799 9.882 ;
     RECT  70.763 10.908 70.799 10.926 ;
     RECT  70.763 14.526 70.799 15.174 ;
     RECT  70.763 17.226 70.799 20.178 ;
     RECT  70.763 21.006 70.799 24.192 ;
     RECT  70.763 31.626 70.799 31.914 ;
     RECT  70.763 44.352 70.799 46.332 ;
     RECT  70.763 47.16 70.799 50.346 ;
     RECT  70.763 51.786 70.799 54.324 ;
     RECT  70.115 62.676 70.799 63.036 ;
     RECT  70.799 14.526 70.835 14.976 ;
     RECT  70.799 17.424 70.835 20.178 ;
     RECT  70.763 24.948 70.835 25.578 ;
     RECT  70.763 32.706 70.835 33.606 ;
     RECT  70.799 47.16 70.835 48.654 ;
     RECT  70.763 64.746 70.835 64.89 ;
     RECT  70.835 17.424 70.871 18.414 ;
     RECT  70.799 31.896 70.871 31.914 ;
     RECT  70.763 41.346 70.871 43.596 ;
     RECT  70.763 15.966 70.907 16.434 ;
     RECT  70.835 19.314 70.907 20.178 ;
     RECT  70.799 22.284 70.907 24.192 ;
     RECT  70.835 32.976 70.907 33.606 ;
     RECT  70.871 43.578 70.907 43.596 ;
     RECT  70.907 15.966 70.943 16.326 ;
     RECT  70.907 19.818 70.943 20.178 ;
     RECT  70.943 16.272 70.979 16.326 ;
     RECT  70.871 17.424 70.979 17.442 ;
     RECT  70.799 21.006 70.979 21.384 ;
     RECT  70.799 46.008 71.051 46.332 ;
     RECT  70.799 53.568 71.095 54.324 ;
     RECT  70.727 55.566 71.095 55.782 ;
     RECT  70.871 41.346 71.123 42.624 ;
     RECT  70.835 47.16 71.123 47.178 ;
     RECT  70.835 47.934 71.123 48.654 ;
     RECT  71.095 55.386 71.123 55.782 ;
     RECT  70.835 14.526 71.159 14.814 ;
     RECT  70.763 27.414 71.159 28.512 ;
     RECT  71.123 41.454 71.159 42.624 ;
     RECT  70.727 66.33 71.159 67.464 ;
     RECT  70.727 12.096 71.195 12.924 ;
     RECT  70.871 18.396 71.195 18.414 ;
     RECT  70.979 21.366 71.195 21.384 ;
     RECT  70.907 22.896 71.195 24.192 ;
     RECT  70.835 24.948 71.195 25.47 ;
     RECT  71.159 27.414 71.195 27.666 ;
     RECT  71.159 28.494 71.195 28.512 ;
     RECT  70.727 29.376 71.195 29.394 ;
     RECT  70.763 30.654 71.195 30.672 ;
     RECT  70.907 33.588 71.195 33.606 ;
     RECT  70.727 35.208 71.195 35.226 ;
     RECT  71.159 42.606 71.195 42.624 ;
     RECT  70.799 44.496 71.195 45.252 ;
     RECT  71.123 47.934 71.195 48.384 ;
     RECT  70.799 49.59 71.195 50.346 ;
     RECT  70.799 51.984 71.195 52.434 ;
     RECT  71.095 53.568 71.195 54.63 ;
     RECT  71.123 55.386 71.195 55.404 ;
     RECT  70.727 57.078 71.195 57.096 ;
     RECT  70.799 62.676 71.195 62.73 ;
     RECT  71.159 66.366 71.195 66.582 ;
     RECT  71.159 67.41 71.195 67.428 ;
     RECT  71.159 14.796 71.231 14.814 ;
     RECT  70.979 16.272 71.231 16.29 ;
     RECT  70.943 19.818 71.267 19.836 ;
     RECT  71.195 22.896 71.267 22.914 ;
     RECT  71.159 41.454 71.267 41.472 ;
     RECT  71.195 44.496 71.267 44.514 ;
     RECT  71.051 46.008 71.267 46.026 ;
     RECT  71.195 47.934 71.267 47.952 ;
     RECT  69.827 60.246 71.267 60.264 ;
     RECT  69.827 61.092 71.267 61.11 ;
     RECT  70.835 64.746 71.267 64.764 ;
    LAYER M3 ;
     RECT  10.404 0.031 10.818 0.043 ;
     RECT  10.404 0.043 11.034 0.067 ;
     RECT  12.564 0.031 12.582 0.067 ;
     RECT  25.524 0.043 25.542 0.067 ;
     RECT  29.088 0.043 29.106 0.067 ;
     RECT  47.592 0.031 47.61 0.067 ;
     RECT  2.376 0.043 3.006 0.091 ;
     RECT  9.324 0.043 9.342 0.091 ;
     RECT  10.116 0.067 11.034 0.091 ;
     RECT  12.564 0.067 13.122 0.091 ;
     RECT  15.156 0.043 15.174 0.091 ;
     RECT  22.392 0.031 22.41 0.091 ;
     RECT  27.18 0.031 27.198 0.091 ;
     RECT  41.22 0.043 41.238 0.091 ;
     RECT  47.592 0.067 47.79 0.091 ;
     RECT  53.244 0.067 53.262 0.091 ;
     RECT  27.18 0.091 27.234 0.103 ;
     RECT  54.18 0.031 54.198 0.103 ;
     RECT  22.392 0.091 23.022 0.131 ;
     RECT  49.788 0.091 50.202 0.131 ;
     RECT  5.076 0.043 5.094 0.139 ;
     RECT  5.94 0.031 5.958 0.139 ;
     RECT  11.988 0.091 15.426 0.139 ;
     RECT  16.2 0.091 16.218 0.139 ;
     RECT  24.984 0.067 25.542 0.139 ;
     RECT  29.088 0.067 29.142 0.139 ;
     RECT  46.62 0.091 46.638 0.139 ;
     RECT  47.52 0.091 48.438 0.139 ;
     RECT  2.376 0.091 4.014 0.173 ;
     RECT  6.84 0.091 6.858 0.187 ;
     RECT  22.392 0.131 22.518 0.187 ;
     RECT  35.316 0.091 35.334 0.187 ;
     RECT  40.968 0.091 41.238 0.187 ;
     RECT  9.324 0.091 11.25 0.221 ;
     RECT  5.076 0.139 5.958 0.269 ;
     RECT  24.984 0.139 25.65 0.269 ;
     RECT  21.06 0.091 21.222 0.283 ;
     RECT  5.076 0.269 5.85 0.317 ;
     RECT  46.62 0.139 48.438 0.317 ;
     RECT  11.988 0.139 16.218 0.365 ;
     RECT  20.592 0.283 21.222 0.365 ;
     RECT  45.468 0.187 45.486 0.365 ;
     RECT  6.84 0.187 6.93 0.413 ;
     RECT  9.612 0.221 11.25 0.413 ;
     RECT  14.652 0.365 16.218 0.413 ;
     RECT  6.84 0.413 6.894 0.461 ;
     RECT  11.988 0.365 13.806 0.461 ;
     RECT  14.832 0.413 16.002 0.461 ;
     RECT  8.316 0.091 8.334 0.509 ;
     RECT  9.612 0.413 10.962 0.509 ;
     RECT  24.984 0.269 25.038 0.523 ;
     RECT  39.888 0.139 39.906 0.523 ;
     RECT  9.972 0.509 10.962 0.554 ;
     RECT  6.876 0.461 6.894 0.557 ;
     RECT  10.116 0.554 10.962 0.557 ;
     RECT  39.672 0.523 40.194 0.571 ;
     RECT  40.968 0.187 41.382 0.571 ;
     RECT  42.264 0.091 42.39 0.571 ;
     RECT  51.804 0.187 51.822 0.571 ;
     RECT  10.188 0.557 10.962 0.599 ;
     RECT  19.764 0.139 19.782 0.619 ;
     RECT  25.956 0.571 26.154 0.619 ;
     RECT  27.036 0.103 27.234 0.619 ;
     RECT  10.404 0.599 10.962 0.701 ;
     RECT  15.012 0.461 16.002 0.701 ;
     RECT  13.14 0.461 13.806 0.749 ;
     RECT  15.66 0.701 16.002 0.749 ;
     RECT  53.136 0.091 53.262 0.811 ;
     RECT  54.18 0.103 54.63 0.811 ;
     RECT  51.444 0.571 51.822 0.907 ;
     RECT  38.52 0.091 38.538 1.099 ;
     RECT  40.968 0.571 42.39 1.099 ;
     RECT  39.348 0.571 40.194 1.627 ;
     RECT  40.968 1.099 42.57 1.627 ;
     RECT  37.908 1.099 38.538 1.675 ;
     RECT  39.348 1.627 42.57 1.675 ;
     RECT  13.14 0.749 13.59 1.723 ;
     RECT  17.46 0.667 17.478 1.723 ;
     RECT  19.44 0.619 19.782 1.723 ;
     RECT  20.592 0.365 21.078 1.723 ;
     RECT  24.552 0.523 25.038 1.723 ;
     RECT  25.956 0.619 27.234 1.723 ;
     RECT  35.28 0.187 35.334 1.723 ;
     RECT  37.908 1.675 42.57 1.723 ;
     RECT  43.308 1.099 43.326 1.723 ;
     RECT  46.62 0.317 48.222 1.723 ;
     RECT  48.996 1.195 49.014 1.723 ;
     RECT  49.788 0.131 49.806 1.723 ;
     RECT  51.444 0.907 52.002 1.723 ;
     RECT  53.136 0.811 54.63 1.723 ;
     RECT  12.924 1.723 13.59 1.771 ;
     RECT  17.46 1.723 17.694 1.771 ;
     RECT  24.552 1.723 27.81 1.771 ;
     RECT  35.28 1.723 35.91 1.771 ;
     RECT  36.828 0.043 36.846 1.771 ;
     RECT  45.468 1.723 50.634 1.771 ;
     RECT  51.444 1.723 54.63 1.771 ;
     RECT  22.32 0.187 22.518 1.819 ;
     RECT  23.4 1.723 23.418 1.819 ;
     RECT  7.74 1.771 7.758 1.963 ;
     RECT  8.82 1.723 8.838 1.963 ;
     RECT  7.74 1.963 8.838 2.011 ;
     RECT  6.84 1.963 6.858 2.059 ;
     RECT  12.924 1.771 14.274 2.101 ;
     RECT  37.908 1.723 43.326 2.101 ;
     RECT  45.468 1.771 54.63 2.101 ;
     RECT  16.92 1.771 17.694 2.107 ;
     RECT  2.844 0.173 4.014 2.143 ;
     RECT  18.576 2.011 18.594 2.143 ;
     RECT  22.32 1.819 23.418 2.143 ;
     RECT  24.372 1.771 27.81 2.143 ;
     RECT  28.584 0.139 29.142 2.143 ;
     RECT  35.28 1.771 36.846 2.143 ;
     RECT  6.84 2.059 6.966 2.155 ;
     RECT  7.704 2.011 8.838 2.155 ;
     RECT  10.548 0.701 10.962 2.155 ;
     RECT  11.988 0.461 12.006 2.155 ;
     RECT  12.924 2.101 14.706 2.155 ;
     RECT  18.576 2.143 18.705 2.155 ;
     RECT  19.44 1.723 21.51 2.155 ;
     RECT  37.728 2.101 43.326 2.155 ;
     RECT  44.244 1.723 44.262 2.155 ;
     RECT  2.415 2.143 4.014 2.191 ;
     RECT  5.22 0.317 5.85 2.191 ;
     RECT  6.84 2.155 8.838 2.191 ;
     RECT  10.26 2.155 10.962 2.191 ;
     RECT  11.988 2.155 14.706 2.191 ;
     RECT  15.66 0.749 15.822 2.191 ;
     RECT  16.704 2.107 17.694 2.191 ;
     RECT  18.576 2.155 21.51 2.191 ;
     RECT  22.32 2.143 27.81 2.191 ;
     RECT  5.22 2.191 5.958 2.203 ;
     RECT  16.632 2.191 17.694 2.203 ;
     RECT  18.576 2.191 27.81 2.203 ;
     RECT  4.932 2.203 5.958 2.227 ;
     RECT  6.732 2.191 8.838 2.227 ;
     RECT  9.972 2.191 10.962 2.227 ;
     RECT  11.916 2.191 15.822 2.227 ;
     RECT  16.632 2.203 27.81 2.227 ;
     RECT  2.304 2.191 4.014 2.251 ;
     RECT  4.932 2.227 8.838 2.251 ;
     RECT  37.728 2.155 44.262 2.251 ;
     RECT  45.108 2.101 54.63 2.251 ;
     RECT  34.815 2.143 36.846 2.371 ;
     RECT  28.584 2.143 29.505 2.413 ;
     RECT  56.415 2.143 56.505 2.413 ;
     RECT  61.815 2.143 61.905 2.413 ;
     RECT  67.215 2.143 67.305 2.413 ;
     RECT  9.972 2.227 27.81 2.461 ;
     RECT  28.584 2.413 29.697 2.461 ;
     RECT  9.792 2.461 29.697 2.533 ;
     RECT  34.776 2.371 36.846 2.569 ;
     RECT  37.728 2.251 54.63 2.569 ;
     RECT  2.304 2.251 8.838 2.605 ;
     RECT  9.756 2.533 29.697 2.605 ;
     RECT  34.776 2.569 54.63 2.911 ;
     RECT  2.304 2.605 29.697 3.569 ;
     RECT  28.584 3.569 29.697 4.109 ;
     RECT  34.74 2.911 54.63 4.217 ;
     RECT  28.8 4.109 29.697 4.379 ;
     RECT  37.62 4.217 54.63 4.559 ;
     RECT  34.74 4.217 36.882 4.589 ;
     RECT  2.304 3.569 27.63 4.649 ;
     RECT  29.124 4.379 29.697 4.649 ;
     RECT  34.74 4.589 36.846 4.649 ;
     RECT  37.836 4.559 54.63 4.649 ;
     RECT  34.815 4.649 35.19 5.117 ;
     RECT  37.836 4.649 54.198 5.575 ;
     RECT  35.928 4.649 36.846 5.605 ;
     RECT  37.8 5.575 54.198 5.605 ;
     RECT  2.304 4.649 27.342 5.881 ;
     RECT  2.304 5.881 27.522 6.151 ;
     RECT  2.268 6.151 27.954 6.269 ;
     RECT  35.928 5.605 54.198 6.413 ;
     RECT  2.268 6.269 27.522 6.809 ;
     RECT  67.215 2.413 67.497 7.051 ;
     RECT  35.928 6.413 53.442 7.159 ;
     RECT  54.18 6.413 54.198 7.159 ;
     RECT  67.215 7.051 67.554 7.159 ;
     RECT  34.815 5.117 35.097 7.195 ;
     RECT  35.928 7.159 54.198 7.195 ;
     RECT  61.815 2.413 62.097 7.231 ;
     RECT  67.215 7.159 67.698 7.231 ;
     RECT  67.215 7.231 67.734 7.321 ;
     RECT  34.815 7.195 54.198 7.357 ;
     RECT  67.215 7.321 67.806 7.357 ;
     RECT  67.215 7.357 67.878 7.429 ;
     RECT  66.888 7.429 67.878 7.465 ;
     RECT  33.084 6.925 33.102 7.483 ;
     RECT  33.084 7.483 33.426 7.501 ;
     RECT  66.744 7.465 67.878 7.501 ;
     RECT  2.268 6.809 27.342 7.531 ;
     RECT  31.824 7.231 31.842 7.591 ;
     RECT  66.744 7.501 68.67 7.655 ;
     RECT  66.744 7.655 68.418 7.663 ;
     RECT  1.98 7.531 27.342 7.771 ;
     RECT  66.384 7.663 68.418 7.799 ;
     RECT  1.98 7.771 27.846 7.819 ;
     RECT  1.404 7.819 27.846 7.889 ;
     RECT  61.815 7.231 62.73 7.889 ;
     RECT  69.444 7.231 69.462 7.933 ;
     RECT  31.824 7.591 32.022 8.011 ;
     RECT  31.824 8.011 32.166 8.041 ;
     RECT  33.084 7.501 33.498 8.041 ;
     RECT  34.272 7.357 54.198 8.041 ;
     RECT  1.404 7.889 27.342 8.159 ;
     RECT  31.824 8.041 54.198 8.195 ;
     RECT  31.824 8.195 33.534 8.203 ;
     RECT  65.592 8.167 65.61 8.203 ;
     RECT  65.412 8.203 65.61 8.311 ;
     RECT  66.384 7.799 68.274 8.311 ;
     RECT  31.716 8.203 33.534 8.339 ;
     RECT  31.716 8.339 33.21 8.429 ;
     RECT  65.412 8.311 68.274 8.581 ;
     RECT  0.108 8.299 0.126 8.683 ;
     RECT  63.9 8.581 63.918 8.743 ;
     RECT  63.9 8.743 64.35 8.815 ;
     RECT  63.54 8.815 64.35 8.851 ;
     RECT  65.412 8.581 68.31 8.851 ;
     RECT  63.54 8.851 68.31 8.941 ;
     RECT  31.896 8.429 33.21 9.053 ;
     RECT  61.815 7.889 62.097 9.085 ;
     RECT  34.344 8.195 54.198 9.115 ;
     RECT  32.112 9.053 33.21 9.121 ;
     RECT  33.948 9.115 54.198 9.121 ;
     RECT  1.404 8.159 27.198 9.451 ;
     RECT  32.112 9.121 54.198 9.509 ;
     RECT  63.54 8.941 68.49 9.553 ;
     RECT  61.815 9.085 62.766 9.661 ;
     RECT  63.54 9.553 68.526 9.661 ;
     RECT  34.056 9.509 54.198 9.689 ;
     RECT  1.404 9.451 27.918 9.779 ;
     RECT  32.112 9.509 32.742 9.787 ;
     RECT  30.78 9.859 30.798 9.931 ;
     RECT  61.815 9.661 68.526 9.931 ;
     RECT  69.444 7.933 69.534 9.931 ;
     RECT  30.78 9.931 31.194 9.959 ;
     RECT  70.776 9.859 70.794 10.057 ;
     RECT  32.04 9.787 32.742 10.123 ;
     RECT  59.436 9.823 59.454 10.129 ;
     RECT  34.704 9.689 54.198 10.157 ;
     RECT  31.176 9.959 31.194 10.165 ;
     RECT  32.004 10.123 32.742 10.165 ;
     RECT  58.824 10.129 59.454 10.165 ;
     RECT  1.404 9.779 27.09 10.193 ;
     RECT  70.668 10.057 70.794 10.229 ;
     RECT  56.415 2.413 56.697 10.267 ;
     RECT  54.18 10.157 54.198 10.319 ;
     RECT  55.116 10.291 55.134 10.349 ;
     RECT  58.824 10.165 59.778 10.363 ;
     RECT  31.176 10.165 32.742 10.411 ;
     RECT  0.108 8.683 0.594 10.427 ;
     RECT  56.196 10.267 56.697 10.435 ;
     RECT  31.176 10.411 32.886 10.471 ;
     RECT  61.815 9.931 69.534 10.669 ;
     RECT  31.176 10.471 32.958 10.699 ;
     RECT  31.14 10.699 32.958 10.733 ;
     RECT  56.196 10.435 56.754 10.733 ;
     RECT  31.14 10.733 32.742 10.769 ;
     RECT  61.74 10.669 69.534 10.795 ;
     RECT  61.74 10.795 69.822 10.925 ;
     RECT  32.04 10.769 32.742 10.976 ;
     RECT  70.704 10.229 70.794 10.987 ;
     RECT  70.668 10.987 70.794 11.011 ;
     RECT  61.74 10.925 68.85 11.165 ;
     RECT  61.74 11.165 68.598 11.261 ;
     RECT  32.148 10.976 32.742 11.273 ;
     RECT  61.74 11.261 68.526 11.309 ;
     RECT  34.704 10.157 53.262 11.407 ;
     RECT  58.824 10.363 59.994 11.479 ;
     RECT  69.804 10.925 69.822 11.515 ;
     RECT  70.596 11.011 70.794 11.515 ;
     RECT  1.404 10.193 26.766 11.551 ;
     RECT  1.404 11.551 27.126 11.669 ;
     RECT  0.108 10.427 0.198 11.705 ;
     RECT  69.804 11.515 70.794 11.755 ;
     RECT  32.292 11.273 32.742 11.777 ;
     RECT  33.624 10.831 33.642 11.813 ;
     RECT  58.716 11.479 60.57 11.813 ;
     RECT  1.404 11.669 26.766 11.849 ;
     RECT  34.452 11.407 53.262 11.939 ;
     RECT  66.528 11.309 68.526 11.983 ;
     RECT  61.74 11.309 65.79 12.245 ;
     RECT  63.612 12.245 65.79 12.289 ;
     RECT  66.528 11.983 68.922 12.289 ;
     RECT  58.716 11.813 60.462 12.361 ;
     RECT  61.74 12.245 62.874 12.361 ;
     RECT  69.804 11.755 71.19 12.478 ;
     RECT  61.56 12.361 62.874 12.479 ;
     RECT  34.524 11.939 53.262 12.515 ;
     RECT  58.14 12.361 60.462 12.551 ;
     RECT  69.768 12.478 71.19 12.551 ;
     RECT  34.596 12.515 53.262 12.559 ;
     RECT  59.148 12.551 60.462 12.559 ;
     RECT  59.148 12.559 60.57 12.631 ;
     RECT  70.632 12.551 71.19 12.749 ;
     RECT  34.596 12.559 53.586 12.793 ;
     RECT  63.612 12.289 68.922 12.793 ;
     RECT  0.144 11.705 0.198 12.857 ;
     RECT  32.544 11.777 32.562 12.857 ;
     RECT  59.148 12.631 60.678 12.865 ;
     RECT  58.14 12.551 58.374 12.893 ;
     RECT  63.612 12.793 68.994 12.929 ;
     RECT  70.668 12.749 71.19 12.929 ;
     RECT  69.768 12.551 69.786 12.941 ;
     RECT  61.74 12.479 62.874 13.051 ;
     RECT  63.612 12.929 68.706 13.051 ;
     RECT  0.144 12.857 0.162 13.091 ;
     RECT  1.404 11.849 26.73 13.099 ;
     RECT  61.74 13.051 68.706 13.163 ;
     RECT  70.668 12.929 70.686 13.289 ;
     RECT  59.148 12.865 60.714 13.297 ;
     RECT  1.404 13.099 26.766 13.325 ;
     RECT  58.356 12.893 58.374 13.333 ;
     RECT  59.112 13.297 60.714 13.333 ;
     RECT  2.268 13.325 26.766 13.369 ;
     RECT  58.356 13.333 60.714 13.373 ;
     RECT  1.404 13.325 1.494 13.397 ;
     RECT  31.176 10.769 31.194 13.397 ;
     RECT  58.86 13.373 60.714 13.405 ;
     RECT  61.74 13.163 68.418 13.405 ;
     RECT  2.268 13.369 26.802 13.469 ;
     RECT  58.86 13.405 68.418 13.559 ;
     RECT  58.86 13.559 59.13 13.595 ;
     RECT  59.868 13.559 68.418 13.595 ;
     RECT  34.596 12.793 53.658 13.711 ;
     RECT  59.868 13.595 67.59 13.739 ;
     RECT  58.86 13.595 59.094 13.829 ;
     RECT  59.868 13.739 60.354 13.829 ;
     RECT  68.328 13.595 68.418 13.865 ;
     RECT  56.415 10.733 56.697 13.963 ;
     RECT  56.304 13.963 56.697 14.009 ;
     RECT  2.268 13.469 26.73 14.099 ;
     RECT  60.192 13.829 60.354 14.099 ;
     RECT  61.128 13.739 67.59 14.099 ;
     RECT  60.192 14.099 60.21 14.144 ;
     RECT  1.404 13.397 1.458 14.171 ;
     RECT  54.792 13.981 54.81 14.251 ;
     RECT  54.684 14.251 54.81 14.369 ;
     RECT  1.44 14.171 1.458 14.405 ;
     RECT  2.268 14.099 26.37 14.539 ;
     RECT  61.164 14.099 67.59 14.635 ;
     RECT  54.936 14.491 54.954 14.639 ;
     RECT  0.144 14.347 0.162 14.717 ;
     RECT  58.896 13.829 59.094 14.755 ;
     RECT  71.136 14.521 71.154 14.791 ;
     RECT  56.415 14.009 56.697 14.872 ;
     RECT  29.415 4.649 29.697 14.875 ;
     RECT  56.196 14.872 56.697 14.909 ;
     RECT  29.415 14.875 29.79 14.915 ;
     RECT  58.896 14.755 59.202 14.917 ;
     RECT  61.164 14.635 67.806 14.917 ;
     RECT  57.708 14.827 57.726 14.953 ;
     RECT  58.5 14.917 59.778 14.953 ;
     RECT  60.516 14.917 67.806 14.953 ;
     RECT  70.38 14.611 70.398 14.953 ;
     RECT  71.136 14.791 71.226 14.953 ;
     RECT  57.708 14.953 67.806 14.957 ;
     RECT  2.232 14.539 26.37 14.989 ;
     RECT  29.415 14.915 29.697 15.061 ;
     RECT  58.068 14.957 67.806 15.061 ;
     RECT  69.012 14.215 69.03 15.061 ;
     RECT  0.216 14.779 0.342 15.101 ;
     RECT  29.304 15.061 29.697 15.101 ;
     RECT  0.252 15.101 0.342 15.197 ;
     RECT  56.268 14.909 56.697 15.251 ;
     RECT  58.068 15.061 69.03 15.259 ;
     RECT  2.196 14.989 26.37 15.499 ;
     RECT  1.728 15.499 26.37 15.595 ;
     RECT  56.304 15.251 56.697 15.629 ;
     RECT  30.816 15.499 30.834 15.691 ;
     RECT  1.152 15.595 26.37 15.739 ;
     RECT  30.816 15.691 31.014 15.821 ;
     RECT  1.152 15.739 26.802 15.835 ;
     RECT  29.415 15.101 29.697 15.871 ;
     RECT  30.816 15.821 30.942 15.965 ;
     RECT  30.816 15.965 30.906 16.027 ;
     RECT  58.068 15.259 69.066 16.027 ;
     RECT  57.42 16.027 69.066 16.067 ;
     RECT  54.72 15.763 54.738 16.105 ;
     RECT  34.488 13.711 53.658 16.141 ;
     RECT  56.415 15.629 56.697 16.141 ;
     RECT  34.38 16.141 53.658 16.267 ;
     RECT  54.684 16.105 54.738 16.267 ;
     RECT  70.38 14.953 71.226 16.295 ;
     RECT  30.78 16.027 30.906 16.349 ;
     RECT  0.36 15.211 0.378 16.363 ;
     RECT  70.38 16.295 71.154 16.397 ;
     RECT  1.152 15.835 26.91 16.445 ;
     RECT  30.888 16.349 30.906 16.445 ;
     RECT  56.415 16.141 56.79 16.445 ;
     RECT  57.636 16.067 69.066 16.445 ;
     RECT  29.415 15.871 29.79 16.529 ;
     RECT  57.78 16.445 69.066 16.529 ;
     RECT  0.36 16.363 0.414 16.603 ;
     RECT  34.38 16.267 54.738 16.603 ;
     RECT  0.324 16.603 0.414 16.651 ;
     RECT  29.415 16.529 29.697 16.681 ;
     RECT  0.18 16.651 0.414 16.685 ;
     RECT  29.304 16.681 29.697 16.733 ;
     RECT  34.38 16.603 54.846 16.733 ;
     RECT  68.976 16.529 69.066 16.771 ;
     RECT  70.632 16.397 71.154 16.781 ;
     RECT  68.976 16.771 69.102 16.951 ;
     RECT  34.38 16.733 54.774 16.979 ;
     RECT  57.78 16.529 68.202 16.979 ;
     RECT  55.656 16.939 55.674 17.069 ;
     RECT  0.18 16.685 0.378 17.131 ;
     RECT  68.976 16.951 69.534 17.221 ;
     RECT  70.632 16.781 70.974 17.221 ;
     RECT  56.415 16.445 56.697 17.311 ;
     RECT  57.78 16.979 68.094 17.311 ;
     RECT  33.516 17.179 33.534 17.339 ;
     RECT  34.38 16.979 54.414 17.339 ;
     RECT  68.976 17.221 70.974 17.447 ;
     RECT  29.415 16.733 29.697 17.491 ;
     RECT  0.144 17.131 0.378 17.515 ;
     RECT  1.152 16.445 26.874 17.515 ;
     RECT  29.415 17.491 29.79 17.549 ;
     RECT  34.38 17.339 53.262 17.563 ;
     RECT  0.144 17.515 26.874 17.581 ;
     RECT  0.108 17.581 26.874 17.645 ;
     RECT  56.415 17.311 68.094 17.681 ;
     RECT  68.976 17.447 70.938 17.741 ;
     RECT  0.144 17.645 26.874 17.761 ;
     RECT  56.415 17.681 56.697 17.851 ;
     RECT  57.6 17.681 68.094 17.878 ;
     RECT  56.304 17.851 56.697 17.888 ;
     RECT  54.792 17.761 54.81 17.959 ;
     RECT  0.144 17.761 27.27 17.981 ;
     RECT  0.684 17.981 27.27 17.987 ;
     RECT  57.6 17.878 68.13 18.023 ;
     RECT  54.792 17.959 54.882 18.059 ;
     RECT  0.684 17.987 0.702 18.125 ;
     RECT  33.912 17.563 53.262 18.193 ;
     RECT  1.728 17.987 27.27 18.301 ;
     RECT  70.128 17.741 70.938 18.379 ;
     RECT  33.912 18.193 53.37 18.391 ;
     RECT  65.484 18.023 68.13 18.391 ;
     RECT  68.976 17.741 69.102 18.391 ;
     RECT  70.128 18.379 71.19 18.419 ;
     RECT  70.128 18.419 71.118 18.461 ;
     RECT  1.728 18.301 27.45 18.563 ;
     RECT  29.415 17.549 29.697 18.565 ;
     RECT  29.415 18.565 29.79 18.605 ;
     RECT  1.728 18.563 27.162 18.689 ;
     RECT  54.792 18.059 54.81 18.697 ;
     RECT  65.484 18.391 69.102 18.701 ;
     RECT  1.728 18.689 27.054 18.725 ;
     RECT  70.128 18.461 70.902 18.733 ;
     RECT  57.6 18.023 64.566 18.769 ;
     RECT  69.804 18.733 70.902 18.797 ;
     RECT  33.624 18.391 53.37 18.805 ;
     RECT  54.72 18.697 54.81 18.805 ;
     RECT  57.6 18.769 64.746 18.841 ;
     RECT  65.484 18.701 69.066 18.841 ;
     RECT  54.648 18.805 54.81 18.995 ;
     RECT  70.704 18.797 70.902 19.085 ;
     RECT  0.144 18.955 0.162 19.195 ;
     RECT  33.624 18.805 53.478 19.337 ;
     RECT  29.415 18.605 29.697 19.381 ;
     RECT  54.72 18.995 54.81 19.387 ;
     RECT  29.304 19.381 29.697 19.421 ;
     RECT  0.144 19.195 0.45 19.435 ;
     RECT  1.404 18.859 1.422 19.435 ;
     RECT  33.624 19.337 53.442 19.483 ;
     RECT  54.72 19.387 54.918 19.535 ;
     RECT  33.012 19.483 53.442 19.565 ;
     RECT  33.012 19.565 53.37 19.571 ;
     RECT  2.304 18.725 26.838 19.615 ;
     RECT  2.304 19.615 27.162 19.651 ;
     RECT  57.6 18.841 69.066 19.651 ;
     RECT  2.304 19.651 27.45 19.675 ;
     RECT  30.816 19.531 30.834 19.675 ;
     RECT  29.415 19.421 29.697 19.723 ;
     RECT  30.816 19.675 30.942 19.723 ;
     RECT  29.415 19.723 29.79 19.769 ;
     RECT  33.012 19.571 52.938 19.769 ;
     RECT  56.415 17.888 56.697 19.777 ;
     RECT  57.492 19.651 69.066 19.777 ;
     RECT  2.268 19.675 27.45 19.805 ;
     RECT  70.812 19.085 70.902 19.813 ;
     RECT  30.816 19.723 31.014 19.853 ;
     RECT  2.304 19.805 27.45 19.877 ;
     RECT  70.812 19.813 71.262 19.885 ;
     RECT  54.72 19.535 54.882 19.913 ;
     RECT  70.776 19.885 71.262 19.915 ;
     RECT  0.144 19.435 1.422 19.949 ;
     RECT  56.415 19.777 69.066 20.141 ;
     RECT  69.804 18.797 69.822 20.429 ;
     RECT  2.304 19.877 27.414 20.453 ;
     RECT  33.048 19.769 52.938 20.579 ;
     RECT  30.78 20.191 30.798 20.623 ;
     RECT  0.324 19.949 1.422 20.683 ;
     RECT  29.415 19.769 29.697 20.779 ;
     RECT  54.72 19.913 54.738 20.821 ;
     RECT  0.216 20.683 1.422 20.827 ;
     RECT  2.304 20.453 27.198 20.827 ;
     RECT  33.048 20.579 52.866 20.849 ;
     RECT  0.216 20.827 27.198 20.875 ;
     RECT  33.048 20.849 52.794 20.885 ;
     RECT  29.415 20.779 29.79 20.909 ;
     RECT  30.78 20.623 30.834 20.909 ;
     RECT  30.816 20.909 30.834 20.921 ;
     RECT  54.504 20.821 54.738 20.993 ;
     RECT  33.048 20.885 52.542 21.001 ;
     RECT  70.668 19.915 71.262 21.163 ;
     RECT  70.128 21.163 71.262 21.259 ;
     RECT  56.415 20.141 68.562 21.361 ;
     RECT  0.144 20.875 27.198 21.389 ;
     RECT  32.868 21.001 52.542 21.389 ;
     RECT  56.415 21.361 68.598 21.433 ;
     RECT  1.152 21.389 27.198 21.505 ;
     RECT  56.415 21.433 68.634 21.505 ;
     RECT  1.152 21.505 27.918 21.533 ;
     RECT  54.756 21.163 54.882 21.533 ;
     RECT  0.144 21.389 0.342 21.581 ;
     RECT  56.415 21.505 68.922 21.659 ;
     RECT  0.216 21.581 0.342 21.695 ;
     RECT  1.152 21.533 27.126 21.695 ;
     RECT  33.048 21.389 52.542 21.695 ;
     RECT  70.092 21.259 71.262 21.731 ;
     RECT  54.756 21.533 54.81 21.739 ;
     RECT  0.324 21.695 0.342 21.773 ;
     RECT  33.084 21.695 52.542 21.973 ;
     RECT  54.684 21.739 54.81 22.009 ;
     RECT  1.404 21.695 27.126 22.037 ;
     RECT  54.612 22.009 54.81 22.081 ;
     RECT  54.54 22.081 54.81 22.199 ;
     RECT  54.72 22.199 54.774 22.235 ;
     RECT  33.084 21.973 52.722 22.279 ;
     RECT  33.084 22.279 52.794 22.379 ;
     RECT  33.084 22.379 52.722 22.577 ;
     RECT  56.415 21.659 68.742 22.585 ;
     RECT  29.415 20.909 29.697 22.699 ;
     RECT  33.084 22.577 52.65 22.739 ;
     RECT  56.415 22.585 68.922 22.739 ;
     RECT  54.756 22.235 54.774 22.775 ;
     RECT  33.084 22.739 52.434 22.783 ;
     RECT  29.304 22.699 29.697 22.819 ;
     RECT  56.415 22.739 68.634 22.843 ;
     RECT  32.832 22.783 52.434 22.847 ;
     RECT  29.304 22.819 29.862 22.919 ;
     RECT  70.128 21.731 71.262 22.919 ;
     RECT  29.304 22.919 29.79 22.925 ;
     RECT  56.268 22.843 68.634 23.009 ;
     RECT  0.144 22.795 0.162 23.035 ;
     RECT  70.128 22.919 71.19 23.117 ;
     RECT  29.304 22.925 29.697 23.279 ;
     RECT  1.404 22.037 27.018 23.351 ;
     RECT  30.78 22.795 30.798 23.357 ;
     RECT  27.9 21.533 27.918 23.405 ;
     RECT  0.144 23.035 0.342 23.467 ;
     RECT  56.415 23.009 68.634 23.549 ;
     RECT  69.624 23.395 69.642 23.563 ;
     RECT  56.415 23.549 68.274 23.621 ;
     RECT  56.415 23.621 57.69 23.657 ;
     RECT  32.904 22.847 52.434 23.701 ;
     RECT  0.144 23.467 0.378 23.746 ;
     RECT  0.108 23.746 0.378 23.789 ;
     RECT  56.415 23.657 57.618 23.819 ;
     RECT  32.4 23.701 52.506 23.827 ;
     RECT  56.415 23.819 57.474 23.827 ;
     RECT  69.552 23.563 69.642 23.863 ;
     RECT  32.22 23.827 52.506 23.885 ;
     RECT  32.472 23.885 52.506 23.933 ;
     RECT  55.872 23.827 57.474 24.089 ;
     RECT  32.652 23.933 52.506 24.133 ;
     RECT  32.652 24.133 52.578 24.187 ;
     RECT  54.792 23.629 54.81 24.205 ;
     RECT  32.652 24.187 52.614 24.233 ;
     RECT  69.552 23.863 69.678 24.235 ;
     RECT  70.632 23.117 71.19 24.235 ;
     RECT  32.652 24.233 52.578 24.359 ;
     RECT  54.72 24.205 54.81 24.359 ;
     RECT  55.872 24.089 57.294 24.359 ;
     RECT  32.652 24.359 52.542 24.431 ;
     RECT  54.792 24.359 54.81 24.431 ;
     RECT  69.552 24.235 71.19 24.431 ;
     RECT  32.652 24.431 52.434 24.509 ;
     RECT  29.415 23.279 29.697 24.511 ;
     RECT  58.464 23.621 68.274 24.526 ;
     RECT  29.415 24.511 29.79 24.557 ;
     RECT  0.144 23.789 0.342 24.619 ;
     RECT  69.516 24.523 69.534 24.637 ;
     RECT  69.48 24.637 69.534 24.701 ;
     RECT  0.144 24.619 0.378 24.716 ;
     RECT  0.216 24.716 0.378 24.749 ;
     RECT  1.98 23.351 27.018 24.811 ;
     RECT  58.644 24.526 68.274 24.871 ;
     RECT  0.216 24.749 0.27 24.893 ;
     RECT  30.78 24.811 30.798 24.941 ;
     RECT  55.872 24.359 57.222 25.007 ;
     RECT  69.48 24.701 69.498 25.007 ;
     RECT  55.872 25.007 57.042 25.079 ;
     RECT  58.644 24.871 68.562 25.169 ;
     RECT  0.216 24.893 0.234 25.229 ;
     RECT  32.724 24.509 52.434 25.249 ;
     RECT  31.788 25.147 31.806 25.285 ;
     RECT  32.58 25.249 52.434 25.285 ;
     RECT  60.84 25.169 68.562 25.411 ;
     RECT  70.56 24.431 71.19 25.475 ;
     RECT  28.368 25.147 28.386 25.517 ;
     RECT  31.788 25.285 52.434 25.517 ;
     RECT  31.968 25.517 52.434 25.753 ;
     RECT  58.644 25.169 60.102 25.753 ;
     RECT  70.56 25.475 70.83 25.753 ;
     RECT  55.872 25.079 56.754 25.853 ;
     RECT  60.84 25.411 68.994 25.867 ;
     RECT  70.128 25.753 70.83 25.867 ;
     RECT  0.108 25.771 0.126 25.963 ;
     RECT  58.14 25.753 60.102 26.023 ;
     RECT  60.84 25.867 70.83 26.023 ;
     RECT  0.108 25.963 0.162 26.059 ;
     RECT  0.108 26.059 0.45 26.237 ;
     RECT  31.968 25.753 52.506 26.299 ;
     RECT  31.968 26.299 52.578 26.329 ;
     RECT  31.716 26.329 52.578 26.429 ;
     RECT  53.532 26.131 53.55 26.477 ;
     RECT  55.08 26.131 55.098 26.477 ;
     RECT  31.752 26.429 52.578 26.573 ;
     RECT  58.14 26.023 70.83 26.587 ;
     RECT  58.14 26.587 71.118 26.627 ;
     RECT  58.14 26.627 69.57 26.765 ;
     RECT  31.752 26.573 52.398 26.789 ;
     RECT  58.14 26.765 69.534 26.789 ;
     RECT  56.415 25.853 56.754 26.797 ;
     RECT  1.728 24.811 27.018 26.825 ;
     RECT  31.968 26.789 52.254 26.825 ;
     RECT  56.415 26.797 56.934 26.905 ;
     RECT  58.14 26.789 68.706 26.905 ;
     RECT  70.596 26.627 71.118 26.923 ;
     RECT  30.78 26.827 30.798 26.957 ;
     RECT  56.304 26.905 56.934 26.957 ;
     RECT  69.48 26.789 69.534 27.095 ;
     RECT  1.152 26.827 1.17 27.149 ;
     RECT  56.376 26.957 56.934 27.163 ;
     RECT  57.924 26.905 68.706 27.163 ;
     RECT  56.376 27.163 68.706 27.365 ;
     RECT  69.516 27.095 69.534 27.707 ;
     RECT  56.376 27.365 68.634 27.743 ;
     RECT  31.968 26.825 52.002 27.841 ;
     RECT  56.376 27.743 57.798 27.869 ;
     RECT  31.5 27.841 52.002 28.021 ;
     RECT  54.684 28.021 54.702 28.183 ;
     RECT  54.684 28.183 54.81 28.211 ;
     RECT  56.415 27.869 57.798 28.247 ;
     RECT  31.356 28.021 52.002 28.255 ;
     RECT  54.792 28.211 54.81 28.283 ;
     RECT  57.636 28.247 57.798 28.409 ;
     RECT  57.636 28.409 57.654 28.445 ;
     RECT  70.596 26.923 71.19 28.459 ;
     RECT  58.644 27.743 68.634 28.481 ;
     RECT  31.356 28.255 52.11 28.679 ;
     RECT  58.644 28.481 68.166 28.679 ;
     RECT  31.356 28.679 52.002 28.715 ;
     RECT  31.356 28.715 51.966 28.831 ;
     RECT  31.32 28.831 51.966 29.065 ;
     RECT  2.304 26.825 27.018 29.101 ;
     RECT  30.816 29.065 51.966 29.101 ;
     RECT  70.092 28.459 71.19 29.129 ;
     RECT  2.304 29.101 27.09 29.179 ;
     RECT  2.268 29.179 27.09 29.255 ;
     RECT  68.904 29.101 68.922 29.299 ;
     RECT  58.716 28.679 68.166 29.363 ;
     RECT  68.904 29.299 68.958 29.399 ;
     RECT  70.596 29.129 71.19 29.399 ;
     RECT  0.144 29.275 0.558 29.453 ;
     RECT  30.78 29.101 51.966 29.597 ;
     RECT  58.752 29.363 68.166 29.641 ;
     RECT  0.54 29.453 0.558 29.741 ;
     RECT  70.596 29.399 70.65 29.759 ;
     RECT  31.284 29.597 51.966 29.911 ;
     RECT  58.752 29.641 68.418 30.029 ;
     RECT  58.752 30.029 60.138 30.109 ;
     RECT  58.716 30.109 60.138 30.209 ;
     RECT  30.492 30.283 30.51 30.335 ;
     RECT  31.284 29.911 52.002 30.343 ;
     RECT  2.304 29.255 27.09 30.415 ;
     RECT  53.388 30.415 53.406 30.427 ;
     RECT  53.172 30.427 53.406 30.479 ;
     RECT  30.924 30.343 52.002 30.569 ;
     RECT  70.632 29.759 70.65 30.569 ;
     RECT  30.924 30.569 51.966 30.605 ;
     RECT  53.244 30.479 53.406 30.613 ;
     RECT  60.876 30.029 68.418 30.649 ;
     RECT  53.244 30.613 53.442 30.677 ;
     RECT  53.316 30.677 53.442 30.713 ;
     RECT  53.316 30.713 53.406 30.749 ;
     RECT  60.876 30.649 68.958 30.749 ;
     RECT  1.404 29.899 1.422 30.859 ;
     RECT  2.304 30.415 27.558 30.859 ;
     RECT  0.18 30.955 0.198 31.051 ;
     RECT  55.296 31.051 55.314 31.081 ;
     RECT  56.415 28.247 56.79 31.081 ;
     RECT  55.296 31.081 56.79 31.109 ;
     RECT  70.668 30.649 71.19 31.145 ;
     RECT  30.924 30.605 51.93 31.147 ;
     RECT  30.78 31.147 51.93 31.387 ;
     RECT  29.415 24.557 29.697 31.495 ;
     RECT  58.788 30.209 60.138 31.495 ;
     RECT  60.876 30.749 68.778 31.495 ;
     RECT  30.78 31.387 52.218 31.523 ;
     RECT  58.788 31.495 68.778 31.621 ;
     RECT  29.415 31.495 29.79 31.627 ;
     RECT  30.78 31.523 52.182 31.627 ;
     RECT  58.788 31.621 68.958 31.657 ;
     RECT  58.644 31.657 68.958 31.721 ;
     RECT  60.444 31.721 68.958 31.765 ;
     RECT  54.792 31.657 54.81 31.801 ;
     RECT  60.444 31.765 68.994 31.801 ;
     RECT  58.644 31.721 59.67 31.891 ;
     RECT  0.108 31.051 0.198 31.915 ;
     RECT  54.648 31.801 54.81 31.919 ;
     RECT  58.428 31.891 59.67 31.919 ;
     RECT  55.764 31.109 56.79 31.991 ;
     RECT  58.428 31.919 59.562 32.011 ;
     RECT  1.404 30.859 27.558 32.027 ;
     RECT  54.72 31.919 54.81 32.035 ;
     RECT  1.728 32.027 27.558 32.063 ;
     RECT  58.032 32.011 59.562 32.063 ;
     RECT  70.74 31.145 71.19 32.161 ;
     RECT  58.176 32.063 59.562 32.189 ;
     RECT  70.704 32.161 71.19 32.203 ;
     RECT  2.196 32.063 27.558 32.225 ;
     RECT  0.108 31.915 0.234 32.237 ;
     RECT  54.72 32.035 54.882 32.261 ;
     RECT  0.216 32.237 0.234 32.285 ;
     RECT  54.72 32.261 54.81 32.297 ;
     RECT  60.444 31.801 69.534 32.341 ;
     RECT  58.176 32.189 59.526 32.459 ;
     RECT  60.444 32.341 69.606 32.467 ;
     RECT  60.372 32.467 69.606 32.525 ;
     RECT  70.668 32.203 71.19 32.621 ;
     RECT  60.552 32.525 69.606 32.701 ;
     RECT  60.552 32.701 69.642 32.881 ;
     RECT  70.668 32.621 70.902 32.881 ;
     RECT  55.908 31.991 56.79 32.971 ;
     RECT  29.415 31.627 52.182 33.053 ;
     RECT  55.908 32.971 57.042 33.079 ;
     RECT  58.176 32.459 59.31 33.079 ;
     RECT  60.552 32.881 70.902 33.293 ;
     RECT  2.232 32.225 27.558 33.305 ;
     RECT  55.908 33.079 59.31 33.313 ;
     RECT  60.552 33.293 69.606 33.313 ;
     RECT  30.564 33.053 52.182 33.341 ;
     RECT  70.704 33.293 70.902 33.451 ;
     RECT  54.792 33.313 54.81 33.511 ;
     RECT  55.908 33.313 69.606 33.539 ;
     RECT  54.72 33.511 55.026 33.547 ;
     RECT  55.908 33.539 68.706 33.547 ;
     RECT  69.552 33.539 69.606 33.581 ;
     RECT  54.72 33.547 68.706 33.595 ;
     RECT  70.704 33.451 71.19 33.611 ;
     RECT  54.576 33.595 68.706 33.719 ;
     RECT  54.576 33.719 59.454 33.845 ;
     RECT  69.588 33.581 69.606 33.869 ;
     RECT  57.528 33.845 59.454 33.917 ;
     RECT  70.704 33.611 70.902 34.061 ;
     RECT  60.408 33.719 68.706 34.079 ;
     RECT  57.816 33.917 59.454 34.115 ;
     RECT  60.408 34.079 60.678 34.151 ;
     RECT  70.704 34.061 70.794 34.253 ;
     RECT  52.164 33.341 52.182 34.259 ;
     RECT  61.524 34.079 68.706 34.355 ;
     RECT  2.304 33.305 27.558 34.385 ;
     RECT  57.816 34.115 59.346 34.385 ;
     RECT  60.408 34.151 60.606 34.385 ;
     RECT  70.704 34.253 70.722 34.411 ;
     RECT  30.564 33.341 51.354 34.421 ;
     RECT  54.576 33.845 56.79 34.429 ;
     RECT  61.632 34.355 68.706 34.459 ;
     RECT  57.816 34.385 59.202 34.529 ;
     RECT  61.632 34.459 69.534 34.541 ;
     RECT  29.415 33.053 29.697 34.591 ;
     RECT  30.564 34.421 51.297 34.591 ;
     RECT  29.088 34.591 51.297 34.637 ;
     RECT  61.632 34.541 68.958 34.637 ;
     RECT  60.516 34.385 60.606 34.655 ;
     RECT  53.964 34.429 56.79 34.699 ;
     RECT  53.964 34.699 56.862 34.735 ;
     RECT  57.816 34.529 59.13 34.735 ;
     RECT  70.668 34.411 70.722 34.987 ;
     RECT  53.964 34.735 59.13 35.159 ;
     RECT  70.632 34.987 70.722 35.179 ;
     RECT  70.632 35.179 71.19 35.231 ;
     RECT  53.964 35.159 58.086 35.303 ;
     RECT  58.896 35.159 59.13 35.303 ;
     RECT  61.632 34.637 68.706 35.311 ;
     RECT  60.948 35.311 68.706 35.339 ;
     RECT  63.18 35.339 68.706 35.357 ;
     RECT  63.468 35.357 68.706 35.465 ;
     RECT  60.192 35.437 60.21 35.473 ;
     RECT  60.948 35.339 62.406 35.473 ;
     RECT  54.144 35.303 58.086 35.549 ;
     RECT  60.192 35.473 62.406 35.609 ;
     RECT  60.192 35.609 60.354 35.693 ;
     RECT  61.164 35.609 62.406 35.699 ;
     RECT  63.756 35.465 68.706 35.699 ;
     RECT  63.756 35.699 64.422 35.735 ;
     RECT  65.556 35.699 68.706 35.735 ;
     RECT  61.164 35.699 62.097 35.771 ;
     RECT  66.096 35.735 68.706 35.837 ;
     RECT  2.34 34.385 27.558 35.851 ;
     RECT  66.204 35.837 68.706 35.851 ;
     RECT  66.204 35.851 68.994 35.879 ;
     RECT  2.34 35.851 27.594 35.899 ;
     RECT  54.18 35.549 58.086 35.969 ;
     RECT  64.188 35.735 64.422 35.969 ;
     RECT  66.312 35.879 68.994 35.969 ;
     RECT  64.188 35.969 64.206 36.005 ;
     RECT  66.312 35.969 67.842 36.005 ;
     RECT  68.688 35.969 68.994 36.041 ;
     RECT  2.304 35.899 27.594 36.113 ;
     RECT  58.068 35.969 58.086 36.113 ;
     RECT  67.14 36.005 67.842 36.149 ;
     RECT  70.632 35.231 70.65 36.239 ;
     RECT  67.14 36.149 67.554 36.275 ;
     RECT  54.18 35.969 57.15 36.355 ;
     RECT  67.176 36.275 67.554 36.509 ;
     RECT  68.688 36.041 68.706 36.509 ;
     RECT  66.312 36.005 66.33 36.689 ;
     RECT  53.496 36.355 57.15 36.779 ;
     RECT  53.496 36.779 56.898 36.815 ;
     RECT  53.496 36.815 56.697 36.895 ;
     RECT  60.228 35.693 60.354 36.931 ;
     RECT  52.38 36.427 52.398 37.057 ;
     RECT  53.316 36.895 56.697 37.057 ;
     RECT  29.415 34.637 51.297 37.147 ;
     RECT  60.228 36.931 60.714 37.165 ;
     RECT  52.38 37.057 56.697 37.355 ;
     RECT  2.304 36.113 27.558 37.471 ;
     RECT  29.088 37.147 51.297 37.483 ;
     RECT  52.38 37.355 52.542 37.669 ;
     RECT  67.215 36.509 67.497 37.669 ;
     RECT  29.052 37.483 51.297 37.705 ;
     RECT  67.215 37.669 67.842 37.741 ;
     RECT  67.032 37.741 67.842 37.831 ;
     RECT  53.604 37.355 56.697 37.859 ;
     RECT  67.032 37.831 67.95 37.903 ;
     RECT  53.604 37.859 55.494 37.967 ;
     RECT  53.604 37.967 55.278 38.003 ;
     RECT  59.112 35.303 59.13 38.011 ;
     RECT  67.032 37.903 68.094 38.011 ;
     RECT  2.268 37.471 27.558 38.137 ;
     RECT  67.032 38.011 68.202 38.173 ;
     RECT  29.052 37.705 51.426 38.245 ;
     RECT  53.604 38.003 54.738 38.245 ;
     RECT  52.272 37.669 52.542 38.281 ;
     RECT  66.456 38.173 68.274 38.281 ;
     RECT  59.112 38.011 59.346 38.479 ;
     RECT  28.944 38.245 51.426 38.515 ;
     RECT  52.236 38.281 52.542 38.515 ;
     RECT  58.464 38.479 59.346 38.515 ;
     RECT  28.944 38.515 52.542 38.551 ;
     RECT  53.46 38.245 54.738 38.551 ;
     RECT  60.228 37.165 60.822 38.551 ;
     RECT  61.815 35.771 62.097 38.551 ;
     RECT  66.456 38.281 68.382 38.551 ;
     RECT  66.456 38.551 68.814 38.677 ;
     RECT  66.24 38.677 68.814 38.705 ;
     RECT  66.24 38.705 68.742 38.713 ;
     RECT  28.944 38.551 54.738 38.717 ;
     RECT  65.268 38.641 65.286 38.731 ;
     RECT  66.06 38.713 68.742 38.731 ;
     RECT  61.815 38.551 62.73 38.741 ;
     RECT  60.228 38.551 60.966 38.776 ;
     RECT  61.815 38.741 62.097 38.776 ;
     RECT  60.228 38.776 62.097 38.813 ;
     RECT  29.232 38.717 54.738 38.821 ;
     RECT  57.924 38.515 59.346 38.911 ;
     RECT  60.228 38.813 61.038 38.911 ;
     RECT  65.268 38.731 68.742 38.975 ;
     RECT  56.415 37.859 56.697 39.019 ;
     RECT  56.34 39.019 56.697 39.055 ;
     RECT  55.872 39.055 56.754 39.091 ;
     RECT  65.268 38.975 68.418 39.091 ;
     RECT  55.872 39.091 57.15 39.181 ;
     RECT  57.924 38.911 61.038 39.181 ;
     RECT  1.692 38.137 27.558 39.209 ;
     RECT  29.232 38.821 54.81 39.209 ;
     RECT  55.872 39.181 61.038 39.209 ;
     RECT  61.02 39.209 61.038 39.281 ;
     RECT  64.764 39.091 68.418 39.361 ;
     RECT  55.872 39.209 60.246 39.389 ;
     RECT  63.9 39.325 63.918 39.451 ;
     RECT  64.728 39.361 68.418 39.451 ;
     RECT  69.804 38.011 69.822 39.451 ;
     RECT  29.232 39.209 54.774 39.499 ;
     RECT  69.804 39.451 69.858 39.631 ;
     RECT  0.288 38.683 0.306 39.691 ;
     RECT  29.124 39.499 54.774 39.691 ;
     RECT  28.512 39.691 54.774 39.749 ;
     RECT  55.872 39.389 60.066 39.785 ;
     RECT  69.804 39.631 69.93 39.829 ;
     RECT  69.48 39.829 69.93 39.865 ;
     RECT  28.62 39.749 54.774 39.991 ;
     RECT  69.48 39.865 70.146 39.991 ;
     RECT  1.692 39.209 27.522 40.013 ;
     RECT  2.232 40.013 27.522 40.055 ;
     RECT  0.288 39.691 0.414 40.061 ;
     RECT  0.288 40.061 0.378 40.099 ;
     RECT  28.62 39.991 54.918 40.099 ;
     RECT  55.872 39.785 59.994 40.099 ;
     RECT  63.9 39.451 68.418 40.099 ;
     RECT  69.48 39.991 70.254 40.099 ;
     RECT  1.152 40.027 1.17 40.127 ;
     RECT  2.232 40.055 27.486 40.127 ;
     RECT  61.815 38.813 62.097 40.261 ;
     RECT  2.232 40.127 27.378 40.325 ;
     RECT  28.62 40.099 59.994 40.325 ;
     RECT  28.62 40.325 55.53 40.361 ;
     RECT  61.56 40.261 62.097 40.369 ;
     RECT  63.9 40.099 70.254 40.441 ;
     RECT  0.108 40.099 0.378 40.493 ;
     RECT  56.415 40.325 59.994 40.531 ;
     RECT  61.488 40.369 62.097 40.531 ;
     RECT  62.856 40.171 62.874 40.531 ;
     RECT  61.236 40.531 62.097 40.567 ;
     RECT  62.856 40.531 62.946 40.567 ;
     RECT  63.756 40.441 70.254 40.567 ;
     RECT  62.856 40.567 70.254 40.595 ;
     RECT  61.164 40.567 62.097 40.639 ;
     RECT  62.856 40.595 64.746 40.639 ;
     RECT  56.415 40.531 60.426 40.651 ;
     RECT  61.164 40.639 64.746 40.651 ;
     RECT  28.62 40.361 54.918 40.675 ;
     RECT  0.144 40.493 0.378 40.829 ;
     RECT  56.415 40.651 64.746 40.877 ;
     RECT  56.415 40.877 64.566 41.009 ;
     RECT  28.332 40.675 54.918 41.021 ;
     RECT  56.415 41.009 58.23 41.071 ;
     RECT  56.304 41.071 58.23 41.117 ;
     RECT  2.268 40.325 27.378 41.251 ;
     RECT  2.268 41.251 27.738 41.369 ;
     RECT  0.144 40.829 0.162 41.405 ;
     RECT  71.1 41.341 71.118 41.449 ;
     RECT  2.268 41.369 27.702 41.597 ;
     RECT  56.415 41.117 58.23 41.675 ;
     RECT  28.584 41.021 54.918 41.683 ;
     RECT  59.292 41.009 64.566 41.791 ;
     RECT  65.556 40.595 70.254 41.791 ;
     RECT  59.112 41.791 70.254 41.881 ;
     RECT  71.1 41.449 71.262 41.881 ;
     RECT  28.584 41.683 54.99 41.909 ;
     RECT  0.324 41.707 0.342 41.947 ;
     RECT  2.268 41.597 27.126 41.989 ;
     RECT  28.584 41.909 54.918 42.151 ;
     RECT  0.324 41.947 0.45 42.187 ;
     RECT  0.144 42.187 0.45 42.235 ;
     RECT  56.415 41.675 56.862 42.421 ;
     RECT  0.144 42.235 1.17 42.509 ;
     RECT  58.248 41.881 71.262 42.509 ;
     RECT  28.224 42.151 54.918 42.521 ;
     RECT  28.224 42.521 53.73 42.565 ;
     RECT  28.152 42.565 53.73 42.653 ;
     RECT  28.224 42.653 53.73 42.719 ;
     RECT  54.648 42.521 54.918 42.719 ;
     RECT  0.144 42.509 0.45 42.727 ;
     RECT  1.224 42.523 1.242 42.749 ;
     RECT  28.224 42.719 53.37 42.755 ;
     RECT  54.648 42.719 54.846 42.755 ;
     RECT  54.792 42.755 54.846 42.989 ;
     RECT  2.16 41.989 27.126 43.133 ;
     RECT  2.232 43.133 27.126 43.181 ;
     RECT  0.108 42.727 0.45 43.469 ;
     RECT  28.584 42.755 53.37 43.501 ;
     RECT  54.792 42.989 54.81 43.537 ;
     RECT  58.392 42.509 71.262 43.645 ;
     RECT  54.72 43.537 54.81 43.771 ;
     RECT  28.584 43.501 53.946 43.799 ;
     RECT  53.388 43.799 53.946 43.915 ;
     RECT  54.72 43.771 54.918 43.915 ;
     RECT  53.388 43.915 54.954 43.951 ;
     RECT  0.144 43.469 0.45 43.963 ;
     RECT  58.212 43.645 71.262 43.979 ;
     RECT  53.388 43.951 54.99 44.059 ;
     RECT  28.584 43.799 52.65 44.069 ;
     RECT  53.388 44.059 55.494 44.069 ;
     RECT  56.415 42.421 57.294 44.077 ;
     RECT  0.144 43.963 1.17 44.189 ;
     RECT  54.72 44.069 55.494 44.221 ;
     RECT  56.34 44.077 57.294 44.221 ;
     RECT  2.268 43.181 27.126 44.251 ;
     RECT  58.212 43.979 58.734 44.311 ;
     RECT  28.584 44.069 52.47 44.339 ;
     RECT  54.72 44.221 57.294 44.381 ;
     RECT  59.472 43.979 71.262 44.411 ;
     RECT  50.796 44.339 52.47 44.447 ;
     RECT  65.412 44.411 71.262 44.519 ;
     RECT  28.584 44.339 49.626 44.581 ;
     RECT  53.388 44.069 53.91 44.609 ;
     RECT  56.415 44.381 57.294 44.617 ;
     RECT  58.14 44.311 58.734 44.617 ;
     RECT  0.144 44.189 0.558 44.621 ;
     RECT  2.232 44.251 27.126 44.689 ;
     RECT  2.196 44.689 27.126 44.725 ;
     RECT  28.008 44.581 49.626 44.725 ;
     RECT  2.196 44.725 49.626 44.915 ;
     RECT  2.196 44.915 49.59 44.957 ;
     RECT  53.46 44.609 53.91 44.987 ;
     RECT  0.144 44.621 0.234 45.067 ;
     RECT  56.415 44.617 58.734 45.115 ;
     RECT  59.472 44.411 64.602 45.115 ;
     RECT  50.868 44.447 52.47 45.121 ;
     RECT  0.108 45.067 0.234 45.149 ;
     RECT  50.868 45.121 52.542 45.197 ;
     RECT  50.868 45.197 52.47 45.229 ;
     RECT  65.412 44.519 71.19 45.257 ;
     RECT  56.415 45.115 64.602 45.265 ;
     RECT  65.412 45.257 70.902 45.265 ;
     RECT  2.304 44.957 49.59 45.389 ;
     RECT  50.796 45.229 52.47 45.427 ;
     RECT  27.936 45.389 49.59 45.491 ;
     RECT  0.108 45.149 0.198 45.677 ;
     RECT  56.415 45.265 70.902 45.677 ;
     RECT  2.304 45.389 27.126 45.688 ;
     RECT  2.268 45.688 27.126 45.725 ;
     RECT  0.144 45.677 0.198 45.773 ;
     RECT  69.552 45.677 70.902 46.003 ;
     RECT  54.72 44.381 55.674 46.027 ;
     RECT  56.415 45.677 68.778 46.027 ;
     RECT  69.552 46.003 71.262 46.061 ;
     RECT  50.724 45.427 52.47 46.111 ;
     RECT  28.296 45.491 49.59 46.201 ;
     RECT  53.892 44.987 53.91 46.229 ;
     RECT  28.296 46.201 49.626 46.253 ;
     RECT  50.724 46.111 52.506 46.309 ;
     RECT  50.724 46.309 52.614 46.315 ;
     RECT  0.54 46.003 0.558 46.349 ;
     RECT  50.724 46.315 52.722 46.349 ;
     RECT  50.796 46.349 52.722 46.409 ;
     RECT  54.72 46.027 68.778 46.499 ;
     RECT  28.296 46.253 49.59 46.507 ;
     RECT  50.796 46.409 52.686 46.733 ;
     RECT  2.304 45.725 27.126 46.741 ;
     RECT  28.224 46.507 49.59 46.843 ;
     RECT  0.108 46.543 0.306 47.069 ;
     RECT  2.268 46.741 27.126 47.075 ;
     RECT  0.108 47.069 0.126 47.117 ;
     RECT  2.304 47.075 27.126 47.131 ;
     RECT  28.116 46.843 49.59 47.131 ;
     RECT  2.304 47.131 49.59 47.261 ;
     RECT  28.116 47.261 49.59 47.309 ;
     RECT  70.128 46.061 71.262 47.309 ;
     RECT  53.748 46.345 53.766 47.317 ;
     RECT  54.756 46.499 68.418 47.317 ;
     RECT  53.748 47.317 68.418 47.357 ;
     RECT  58.644 47.357 68.418 47.425 ;
     RECT  28.224 47.309 49.59 47.461 ;
     RECT  50.796 46.733 52.542 47.461 ;
     RECT  58.644 47.425 68.85 47.461 ;
     RECT  28.224 47.461 49.806 47.563 ;
     RECT  50.724 47.461 52.542 47.563 ;
     RECT  54.684 47.357 57.762 47.615 ;
     RECT  55.656 47.615 57.762 47.651 ;
     RECT  28.224 47.563 52.542 47.893 ;
     RECT  70.164 47.309 71.262 47.957 ;
     RECT  2.304 47.261 27.342 48.043 ;
     RECT  70.164 47.957 71.19 48.091 ;
     RECT  2.268 48.043 27.342 48.271 ;
     RECT  28.224 47.893 52.974 48.271 ;
     RECT  53.748 47.357 53.766 48.271 ;
     RECT  58.644 47.461 68.922 48.271 ;
     RECT  70.128 48.091 71.19 48.389 ;
     RECT  58.644 48.271 68.994 48.397 ;
     RECT  70.128 48.389 71.118 48.397 ;
     RECT  0.108 48.235 0.126 48.413 ;
     RECT  53.748 48.271 53.802 48.433 ;
     RECT  54.684 47.615 54.81 48.469 ;
     RECT  2.268 48.271 52.974 48.505 ;
     RECT  53.748 48.433 53.91 48.505 ;
     RECT  55.656 47.651 57.69 48.505 ;
     RECT  58.644 48.397 71.118 48.505 ;
     RECT  2.268 48.505 53.91 48.569 ;
     RECT  2.268 48.569 53.838 48.731 ;
     RECT  54.684 48.469 54.882 48.767 ;
     RECT  55.656 48.505 71.118 48.845 ;
     RECT  2.268 48.731 53.802 48.907 ;
     RECT  2.232 48.907 53.802 48.929 ;
     RECT  53.172 48.929 53.73 48.965 ;
     RECT  53.172 48.965 53.658 49.001 ;
     RECT  54.684 48.767 54.846 49.001 ;
     RECT  55.656 48.845 69.534 49.001 ;
     RECT  2.232 48.929 49.338 49.085 ;
     RECT  53.172 49.001 53.622 49.469 ;
     RECT  54.684 49.001 54.81 49.469 ;
     RECT  70.704 48.845 71.118 49.576 ;
     RECT  53.172 49.469 53.262 49.739 ;
     RECT  55.656 49.001 68.742 49.819 ;
     RECT  69.48 49.001 69.534 49.819 ;
     RECT  55.656 49.819 69.534 49.919 ;
     RECT  2.304 49.085 49.338 50.009 ;
     RECT  54.72 49.469 54.81 50.053 ;
     RECT  54.72 50.053 54.918 50.153 ;
     RECT  2.304 50.009 48.438 50.315 ;
     RECT  70.704 49.576 71.19 50.351 ;
     RECT  59.652 49.919 69.534 50.381 ;
     RECT  49.32 50.009 49.338 50.395 ;
     RECT  50.184 48.929 52.434 50.395 ;
     RECT  55.656 49.919 58.734 50.423 ;
     RECT  1.404 50.053 1.422 50.431 ;
     RECT  2.304 50.315 48.402 50.431 ;
     RECT  70.704 50.351 70.758 50.431 ;
     RECT  70.128 50.431 70.758 50.477 ;
     RECT  59.652 50.381 68.994 50.549 ;
     RECT  54.72 50.153 54.846 50.557 ;
     RECT  59.652 50.549 59.67 50.585 ;
     RECT  60.624 50.549 68.994 50.621 ;
     RECT  53.532 50.587 53.55 50.701 ;
     RECT  54.288 50.557 54.846 50.701 ;
     RECT  53.532 50.701 54.846 50.765 ;
     RECT  60.66 50.621 68.994 50.891 ;
     RECT  55.656 50.423 58.446 50.963 ;
     RECT  53.748 50.765 54.846 51.097 ;
     RECT  55.656 50.963 58.194 51.097 ;
     RECT  60.732 50.891 68.994 51.161 ;
     RECT  49.32 50.395 52.434 51.169 ;
     RECT  63.288 51.161 68.994 51.233 ;
     RECT  1.404 50.431 48.402 51.241 ;
     RECT  49.176 51.169 52.434 51.241 ;
     RECT  1.404 51.241 52.434 51.355 ;
     RECT  60.732 51.161 62.514 51.359 ;
     RECT  70.668 50.477 70.758 51.403 ;
     RECT  66.276 51.233 68.994 51.467 ;
     RECT  59.436 51.439 59.742 51.475 ;
     RECT  1.152 51.355 52.434 51.485 ;
     RECT  70.092 51.403 70.758 51.499 ;
     RECT  53.748 51.097 58.194 51.503 ;
     RECT  1.404 51.485 52.434 51.511 ;
     RECT  66.42 51.467 68.994 51.511 ;
     RECT  59.436 51.475 59.994 51.601 ;
     RECT  1.404 51.511 52.542 51.629 ;
     RECT  59.4 51.601 59.994 51.673 ;
     RECT  60.732 51.359 62.478 51.673 ;
     RECT  58.068 51.503 58.194 51.701 ;
     RECT  70.092 51.499 71.19 51.701 ;
     RECT  59.4 51.673 62.478 51.907 ;
     RECT  0.18 51.475 0.198 52.027 ;
     RECT  63.288 51.233 65.466 52.051 ;
     RECT  53.748 51.503 57.186 52.141 ;
     RECT  59.184 51.907 62.478 52.141 ;
     RECT  53.532 52.141 57.186 52.169 ;
     RECT  58.428 51.883 58.446 52.169 ;
     RECT  0.108 52.027 0.198 52.205 ;
     RECT  53.532 52.169 55.566 52.213 ;
     RECT  0.18 52.205 0.198 52.219 ;
     RECT  59.184 52.141 62.514 52.219 ;
     RECT  63.288 52.051 65.682 52.219 ;
     RECT  1.404 51.629 52.434 52.241 ;
     RECT  59.184 52.219 65.682 52.285 ;
     RECT  70.128 51.701 71.19 52.301 ;
     RECT  53.496 52.213 55.566 52.411 ;
     RECT  53.424 52.411 55.566 52.439 ;
     RECT  58.788 52.285 65.682 52.483 ;
     RECT  66.42 51.511 69.03 52.483 ;
     RECT  58.788 52.483 69.03 52.511 ;
     RECT  52.02 52.241 52.434 52.519 ;
     RECT  53.424 52.439 55.494 52.519 ;
     RECT  61.128 52.511 69.03 52.589 ;
     RECT  1.404 52.241 51.297 52.685 ;
     RECT  56.415 52.169 57.114 53.059 ;
     RECT  0.18 52.219 0.558 53.083 ;
     RECT  1.404 52.685 1.422 53.083 ;
     RECT  56.415 53.059 57.474 53.095 ;
     RECT  56.415 53.095 57.546 53.165 ;
     RECT  58.788 52.511 60.318 53.257 ;
     RECT  61.128 52.589 68.994 53.257 ;
     RECT  52.02 52.519 55.494 53.329 ;
     RECT  56.415 53.165 57.438 53.329 ;
     RECT  58.788 53.257 68.994 53.365 ;
     RECT  70.596 52.301 71.19 53.419 ;
     RECT  52.02 53.329 57.438 53.519 ;
     RECT  0.144 53.083 1.422 53.527 ;
     RECT  53.856 53.519 57.438 53.555 ;
     RECT  2.268 52.685 51.297 53.599 ;
     RECT  52.02 53.519 52.974 53.599 ;
     RECT  0.108 53.527 1.422 53.671 ;
     RECT  2.268 53.599 52.974 53.671 ;
     RECT  58.716 53.365 68.994 53.699 ;
     RECT  53.856 53.555 53.946 53.789 ;
     RECT  54.72 53.555 57.438 53.789 ;
     RECT  68.976 53.699 68.994 53.789 ;
     RECT  58.716 53.699 68.202 53.797 ;
     RECT  58.536 53.797 68.202 54.091 ;
     RECT  0.108 53.671 52.974 54.131 ;
     RECT  54.792 53.789 57.438 54.139 ;
     RECT  70.128 53.419 71.19 54.175 ;
     RECT  58.5 54.091 68.202 54.187 ;
     RECT  58.464 54.187 68.202 54.235 ;
     RECT  15.12 54.131 52.974 54.301 ;
     RECT  53.856 53.789 53.91 54.301 ;
     RECT  0.108 54.131 14.13 54.317 ;
     RECT  69.552 54.175 71.19 54.317 ;
     RECT  0.108 54.317 0.342 54.365 ;
     RECT  1.152 54.317 14.13 54.365 ;
     RECT  0.108 54.365 0.198 54.373 ;
     RECT  70.128 54.317 71.19 54.401 ;
     RECT  0.036 54.373 0.198 54.509 ;
     RECT  58.392 54.235 68.202 54.571 ;
     RECT  15.12 54.301 53.91 54.679 ;
     RECT  54.792 54.139 57.582 54.679 ;
     RECT  15.12 54.679 57.582 54.715 ;
     RECT  58.392 54.571 68.238 54.715 ;
     RECT  15.12 54.715 68.238 54.859 ;
     RECT  68.976 54.751 68.994 54.859 ;
     RECT  1.692 54.365 14.13 54.949 ;
     RECT  1.692 54.949 14.166 55.021 ;
     RECT  15.12 54.859 68.994 55.175 ;
     RECT  55.62 55.175 68.994 55.211 ;
     RECT  55.764 55.211 68.994 55.247 ;
     RECT  70.704 54.401 71.19 55.409 ;
     RECT  1.692 55.021 14.274 55.687 ;
     RECT  15.12 55.175 54.846 55.687 ;
     RECT  56.376 55.247 68.994 55.715 ;
     RECT  1.692 55.687 54.846 55.787 ;
     RECT  70.704 55.409 71.118 55.819 ;
     RECT  1.692 55.787 54.522 55.901 ;
     RECT  70.092 55.819 71.118 56.101 ;
     RECT  0.036 54.509 0.054 56.299 ;
     RECT  70.056 56.101 71.118 56.333 ;
     RECT  1.692 55.901 53.37 56.489 ;
     RECT  56.415 55.715 68.994 56.489 ;
     RECT  19.728 56.489 53.37 56.641 ;
     RECT  54.36 55.901 54.522 56.641 ;
     RECT  1.692 56.489 18.897 56.669 ;
     RECT  0.036 56.299 0.666 56.714 ;
     RECT  70.092 56.333 71.118 56.779 ;
     RECT  57.42 56.489 68.994 56.795 ;
     RECT  0.108 56.714 0.666 56.813 ;
     RECT  1.692 56.669 13.95 57.005 ;
     RECT  19.728 56.641 54.558 57.029 ;
     RECT  54.36 57.029 54.558 57.145 ;
     RECT  70.092 56.779 71.19 57.163 ;
     RECT  54.36 57.145 54.738 57.173 ;
     RECT  57.528 56.795 68.994 57.173 ;
     RECT  54.72 57.173 54.738 57.335 ;
     RECT  70.02 57.163 71.19 57.355 ;
     RECT  19.728 57.029 53.514 57.407 ;
     RECT  57.528 57.173 68.742 57.479 ;
     RECT  69.804 57.355 71.19 57.547 ;
     RECT  19.728 57.407 52.29 57.569 ;
     RECT  53.1 57.407 53.514 57.569 ;
     RECT  57.528 57.479 57.546 57.569 ;
     RECT  58.716 57.479 68.742 57.605 ;
     RECT  0.108 56.813 0.558 57.677 ;
     RECT  0.144 57.677 0.558 58.061 ;
     RECT  58.716 57.605 68.526 58.351 ;
     RECT  19.728 57.569 51.966 58.459 ;
     RECT  53.1 57.569 53.406 58.459 ;
     RECT  58.716 58.351 68.598 58.495 ;
     RECT  2.268 57.005 13.95 58.531 ;
     RECT  58.716 58.495 68.814 58.531 ;
     RECT  69.804 57.547 71.262 58.649 ;
     RECT  58.716 58.531 68.922 58.685 ;
     RECT  14.868 56.669 18.897 58.699 ;
     RECT  19.728 58.459 53.406 58.699 ;
     RECT  14.868 58.699 53.406 58.702 ;
     RECT  14.868 58.702 52.542 58.721 ;
     RECT  14.868 58.721 52.326 58.729 ;
     RECT  2.232 58.531 13.95 58.801 ;
     RECT  14.796 58.729 52.326 58.801 ;
     RECT  53.28 58.702 53.406 58.919 ;
     RECT  58.716 58.685 68.814 58.919 ;
     RECT  69.804 58.649 70.11 58.919 ;
     RECT  0.54 58.061 0.558 59.027 ;
     RECT  53.316 58.919 53.406 59.063 ;
     RECT  58.716 58.919 63.09 59.099 ;
     RECT  64.368 58.919 68.814 59.225 ;
     RECT  64.368 59.225 65.43 59.261 ;
     RECT  66.384 59.225 68.814 59.309 ;
     RECT  64.692 59.261 65.43 59.459 ;
     RECT  66.744 59.309 68.814 59.531 ;
     RECT  58.716 59.099 62.73 59.575 ;
     RECT  58.5 59.575 62.73 59.639 ;
     RECT  2.232 58.801 52.326 59.729 ;
     RECT  2.232 59.729 52.218 59.765 ;
     RECT  58.5 59.639 62.097 59.765 ;
     RECT  1.404 57.145 1.422 59.773 ;
     RECT  66.888 59.531 68.814 59.789 ;
     RECT  54.72 59.611 54.738 59.801 ;
     RECT  58.5 59.765 60.75 59.801 ;
     RECT  58.5 59.801 60.57 59.809 ;
     RECT  67.215 59.789 68.814 59.809 ;
     RECT  67.215 59.809 68.994 59.999 ;
     RECT  67.215 59.999 68.922 60.035 ;
     RECT  2.232 59.765 52.146 60.143 ;
     RECT  61.74 59.765 62.097 60.179 ;
     RECT  57.924 59.809 60.57 60.269 ;
     RECT  71.244 58.649 71.262 60.269 ;
     RECT  56.415 56.489 56.697 60.277 ;
     RECT  57.924 60.269 58.194 60.277 ;
     RECT  59.04 60.269 60.57 60.305 ;
     RECT  56.415 60.277 58.194 60.317 ;
     RECT  59.04 60.305 60.102 60.377 ;
     RECT  59.292 60.377 60.102 60.413 ;
     RECT  59.292 60.413 59.994 60.539 ;
     RECT  69.804 58.919 69.822 60.539 ;
     RECT  53.316 59.063 53.334 60.691 ;
     RECT  61.815 60.179 62.097 60.691 ;
     RECT  56.415 60.317 56.697 60.817 ;
     RECT  67.215 60.035 68.13 60.817 ;
     RECT  55.836 60.817 56.697 60.853 ;
     RECT  52.128 60.143 52.146 60.859 ;
     RECT  55.008 60.817 55.026 60.893 ;
     RECT  53.316 60.691 53.442 60.961 ;
     RECT  55.8 60.853 56.697 60.961 ;
     RECT  57.564 60.317 58.194 61.159 ;
     RECT  59.292 60.539 59.922 61.159 ;
     RECT  67.068 60.817 68.13 61.159 ;
     RECT  68.904 60.035 68.922 61.159 ;
     RECT  55.26 60.961 56.697 61.195 ;
     RECT  57.564 61.159 59.922 61.195 ;
     RECT  55.26 61.195 59.922 61.223 ;
     RECT  67.068 61.159 68.922 61.231 ;
     RECT  53.316 60.961 53.874 61.349 ;
     RECT  55.26 61.223 58.914 61.349 ;
     RECT  59.832 61.223 59.922 61.349 ;
     RECT  57.42 61.349 58.914 61.385 ;
     RECT  59.832 61.349 59.85 61.385 ;
     RECT  2.232 60.143 51.297 61.429 ;
     RECT  52.128 60.859 52.218 61.429 ;
     RECT  66.708 61.231 68.922 61.465 ;
     RECT  66.384 61.465 68.922 61.501 ;
     RECT  1.152 59.773 1.422 61.517 ;
     RECT  53.856 61.349 53.874 61.591 ;
     RECT  57.528 61.385 58.914 61.691 ;
     RECT  53.856 61.591 54.198 61.699 ;
     RECT  55.26 61.349 56.697 61.699 ;
     RECT  2.232 61.429 52.218 61.897 ;
     RECT  66.384 61.501 69.03 61.969 ;
     RECT  66.06 61.969 69.03 62.041 ;
     RECT  0.144 62.011 0.162 62.059 ;
     RECT  0.144 62.059 0.234 62.107 ;
     RECT  57.636 61.691 58.914 62.159 ;
     RECT  61.815 60.691 62.73 62.167 ;
     RECT  64.548 62.131 64.566 62.203 ;
     RECT  58.716 62.159 58.914 62.231 ;
     RECT  64.512 62.203 64.566 62.239 ;
     RECT  2.196 61.897 52.218 62.275 ;
     RECT  64.512 62.239 65.178 62.275 ;
     RECT  58.788 62.231 58.914 62.303 ;
     RECT  61.815 62.167 62.802 62.303 ;
     RECT  66.06 62.041 69.066 62.311 ;
     RECT  0.144 62.107 0.414 62.395 ;
     RECT  1.152 61.517 1.242 62.395 ;
     RECT  53.856 61.699 56.697 62.401 ;
     RECT  58.86 62.303 58.914 62.429 ;
     RECT  63.864 62.275 65.178 62.429 ;
     RECT  2.196 62.275 52.29 62.437 ;
     RECT  53.856 62.401 56.754 62.437 ;
     RECT  2.196 62.437 52.65 62.473 ;
     RECT  53.388 62.437 56.754 62.473 ;
     RECT  58.86 62.429 58.878 62.501 ;
     RECT  0.144 62.395 1.242 62.509 ;
     RECT  2.196 62.473 56.754 62.545 ;
     RECT  57.636 62.159 57.87 62.545 ;
     RECT  2.196 62.545 57.87 62.609 ;
     RECT  63.864 62.429 64.998 62.669 ;
     RECT  71.244 61.087 71.262 62.671 ;
     RECT  2.196 62.609 57.69 62.699 ;
     RECT  71.172 62.671 71.262 62.707 ;
     RECT  0.108 62.509 1.242 62.717 ;
     RECT  64.548 62.669 64.998 62.735 ;
     RECT  1.224 62.717 1.242 62.765 ;
     RECT  66.06 62.311 69.102 62.815 ;
     RECT  2.196 62.699 57.258 62.843 ;
     RECT  71.1 62.707 71.262 63.013 ;
     RECT  61.815 62.303 62.73 63.085 ;
     RECT  66.024 62.815 69.102 63.211 ;
     RECT  2.196 62.843 57.042 63.239 ;
     RECT  2.196 63.239 56.97 63.275 ;
     RECT  64.548 62.735 64.566 63.625 ;
     RECT  70.776 63.013 71.262 63.751 ;
     RECT  64.548 63.625 64.674 63.895 ;
     RECT  64.116 63.895 64.674 63.931 ;
     RECT  65.484 63.211 69.102 63.931 ;
     RECT  2.196 63.275 56.754 63.959 ;
     RECT  52.236 63.959 56.754 64.049 ;
     RECT  54.72 64.049 56.697 64.109 ;
     RECT  54.72 64.109 54.81 64.121 ;
     RECT  54.792 64.121 54.81 64.157 ;
     RECT  60.408 63.259 60.426 64.171 ;
     RECT  0.108 62.717 0.162 64.205 ;
     RECT  55.98 64.109 56.697 64.229 ;
     RECT  61.815 63.085 62.766 64.363 ;
     RECT  64.116 63.931 69.102 64.363 ;
     RECT  0.144 64.205 0.162 64.397 ;
     RECT  2.196 63.959 51.498 64.411 ;
     RECT  61.815 64.363 69.102 64.493 ;
     RECT  2.052 64.411 51.498 64.589 ;
     RECT  52.236 64.049 53.946 64.589 ;
     RECT  61.815 64.493 69.066 64.589 ;
     RECT  2.052 64.589 51.354 64.625 ;
     RECT  61.815 64.589 69.03 64.685 ;
     RECT  60.12 64.171 60.426 64.696 ;
     RECT  52.236 64.589 53.838 64.697 ;
     RECT  59.796 64.696 60.426 64.733 ;
     RECT  60.228 64.733 60.426 64.741 ;
     RECT  70.092 63.751 71.262 64.769 ;
     RECT  70.092 64.769 71.19 64.781 ;
     RECT  52.524 64.697 53.838 64.859 ;
     RECT  70.092 64.781 71.118 64.877 ;
     RECT  58.716 64.741 58.734 64.895 ;
     RECT  61.815 64.685 68.994 64.973 ;
     RECT  52.524 64.859 53.262 65.003 ;
     RECT  52.524 65.003 52.758 65.021 ;
     RECT  52.668 65.021 52.758 65.129 ;
     RECT  52.668 65.129 52.686 65.165 ;
     RECT  60.228 64.741 60.498 65.407 ;
     RECT  70.092 64.877 70.83 65.443 ;
     RECT  2.268 64.625 51.354 65.471 ;
     RECT  2.268 65.471 51.297 65.713 ;
     RECT  61.815 64.973 68.562 65.713 ;
     RECT  69.552 65.443 70.83 65.741 ;
     RECT  2.196 65.713 51.297 65.747 ;
     RECT  60.228 65.407 61.038 65.785 ;
     RECT  70.128 65.741 70.83 65.803 ;
     RECT  60.192 65.785 61.038 65.821 ;
     RECT  61.815 65.713 68.742 65.821 ;
     RECT  2.196 65.747 48.654 65.911 ;
     RECT  2.16 65.911 48.654 66.011 ;
     RECT  70.128 65.803 71.19 66.083 ;
     RECT  49.392 65.747 51.297 66.235 ;
     RECT  58.356 66.181 58.842 66.235 ;
     RECT  60.192 65.821 68.742 66.451 ;
     RECT  55.44 66.451 55.458 66.475 ;
     RECT  56.415 64.229 56.697 66.475 ;
     RECT  57.564 66.451 57.582 66.475 ;
     RECT  58.356 66.235 59.454 66.475 ;
     RECT  55.08 66.475 56.697 66.523 ;
     RECT  57.564 66.475 59.454 66.523 ;
     RECT  2.196 66.011 48.654 66.559 ;
     RECT  49.392 66.235 51.822 66.559 ;
     RECT  55.08 66.523 59.454 66.559 ;
     RECT  60.192 66.451 68.85 66.559 ;
     RECT  55.08 66.559 68.922 66.595 ;
     RECT  2.196 66.559 51.822 66.631 ;
     RECT  2.196 66.631 52.146 66.749 ;
     RECT  55.08 66.595 68.994 66.749 ;
     RECT  56.232 66.749 68.994 66.859 ;
     RECT  53.82 66.793 53.838 66.865 ;
     RECT  56.232 66.859 69.57 66.955 ;
     RECT  70.668 66.083 71.19 66.955 ;
     RECT  53.82 66.865 53.91 66.991 ;
     RECT  52.956 66.859 52.974 67.027 ;
     RECT  53.82 66.991 53.982 67.027 ;
     RECT  55.08 66.749 55.35 67.027 ;
     RECT  56.232 66.955 71.19 67.199 ;
     RECT  60.768 67.199 71.19 67.244 ;
     RECT  56.232 67.199 59.562 67.289 ;
     RECT  60.768 67.244 69.534 67.289 ;
     RECT  70.668 67.244 71.19 67.289 ;
     RECT  52.128 66.749 52.146 67.297 ;
     RECT  52.956 67.027 55.35 67.297 ;
     RECT  58.248 67.289 59.562 67.325 ;
     RECT  60.768 67.289 61.038 67.325 ;
     RECT  61.02 67.325 61.038 67.361 ;
     RECT  70.704 67.289 71.19 67.373 ;
     RECT  58.572 67.325 59.562 67.397 ;
     RECT  61.815 67.289 69.534 67.397 ;
     RECT  71.136 67.373 71.19 67.433 ;
     RECT  58.572 67.397 59.238 67.469 ;
     RECT  71.136 67.433 71.154 67.475 ;
     RECT  52.128 67.297 55.35 67.559 ;
     RECT  61.815 67.397 64.494 67.559 ;
     RECT  52.128 67.559 55.314 67.595 ;
     RECT  56.232 67.289 57.51 67.631 ;
     RECT  2.196 66.749 51.39 67.667 ;
     RECT  65.232 67.397 68.706 67.667 ;
     RECT  52.272 67.595 53.01 67.703 ;
     RECT  59.22 67.469 59.238 67.703 ;
     RECT  56.415 67.631 57.51 67.757 ;
     RECT  52.416 67.703 53.01 67.805 ;
     RECT  2.196 67.667 51.297 67.819 ;
     RECT  53.82 67.595 55.314 67.829 ;
     RECT  57.42 67.757 57.51 67.829 ;
     RECT  61.815 67.559 64.422 67.829 ;
     RECT  52.992 67.805 53.01 67.853 ;
     RECT  2.16 67.819 51.297 67.865 ;
     RECT  53.82 67.829 54.666 67.865 ;
     RECT  53.82 67.865 54.486 67.901 ;
     RECT  2.16 67.865 49.842 67.907 ;
     RECT  2.16 67.907 49.662 68.099 ;
     RECT  50.724 67.865 51.297 68.099 ;
     RECT  53.82 67.901 53.91 68.099 ;
     RECT  1.116 67.945 1.134 68.101 ;
     RECT  2.16 68.099 49.122 68.101 ;
     RECT  63 67.829 64.422 68.135 ;
     RECT  1.116 68.101 49.122 68.141 ;
     RECT  53.82 68.099 53.838 68.141 ;
     RECT  50.76 68.099 51.297 68.171 ;
     RECT  63 68.135 64.098 68.207 ;
     RECT  2.16 68.141 49.122 68.243 ;
     RECT  63 68.207 63.018 68.279 ;
     RECT  63.828 68.207 64.098 68.279 ;
     RECT  1.116 68.141 1.134 68.285 ;
     RECT  49.104 68.243 49.122 68.381 ;
     RECT  63.828 68.279 63.846 68.405 ;
     RECT  65.268 67.667 68.706 68.429 ;
     RECT  65.556 68.429 68.706 68.477 ;
     RECT  66.024 68.477 68.706 68.639 ;
     RECT  2.16 68.243 48.366 68.675 ;
     RECT  66.204 68.639 68.706 68.675 ;
     RECT  66.204 68.675 66.222 68.711 ;
     RECT  69.516 67.397 69.534 68.747 ;
     RECT  51.015 68.171 51.297 68.867 ;
     RECT  56.415 67.757 56.697 68.867 ;
     RECT  61.815 67.829 62.097 68.867 ;
     RECT  2.16 68.675 10.35 68.909 ;
     RECT  11.232 68.675 48.366 68.909 ;
     RECT  67.215 68.675 68.706 68.909 ;
     RECT  11.232 68.909 47.898 68.945 ;
     RECT  67.215 68.909 67.77 68.945 ;
     RECT  2.16 68.909 8.478 68.957 ;
     RECT  14.076 68.945 25.434 68.957 ;
     RECT  33.228 68.945 43.146 68.957 ;
     RECT  45.504 68.945 46.062 68.957 ;
     RECT  46.98 68.945 47.898 68.957 ;
     RECT  11.232 68.945 13.305 68.981 ;
     RECT  37.152 68.957 39.33 68.981 ;
     RECT  42.768 68.957 42.93 68.981 ;
     RECT  44.172 68.945 44.622 68.981 ;
     RECT  45.504 68.957 45.954 68.981 ;
     RECT  47.052 68.957 47.07 68.981 ;
     RECT  47.88 68.957 47.898 68.981 ;
     RECT  2.16 68.957 4.158 69.005 ;
     RECT  9.432 68.909 10.35 69.005 ;
     RECT  11.304 68.981 11.358 69.005 ;
     RECT  12.168 68.981 13.305 69.005 ;
     RECT  14.328 68.957 25.434 69.005 ;
     RECT  26.172 68.945 32.094 69.005 ;
     RECT  33.228 68.957 36.018 69.005 ;
     RECT  37.188 68.981 39.33 69.005 ;
     RECT  40.215 68.957 41.382 69.005 ;
     RECT  44.496 68.981 44.514 69.005 ;
     RECT  45.615 68.981 45.954 69.005 ;
     RECT  16.38 69.005 25.434 69.053 ;
     RECT  33.228 69.005 35.73 69.053 ;
     RECT  33.336 69.053 35.73 69.089 ;
     RECT  37.188 69.005 37.206 69.089 ;
     RECT  16.38 69.053 20.07 69.101 ;
     RECT  40.215 69.005 41.346 69.101 ;
     RECT  12.456 69.005 13.305 69.137 ;
     RECT  23.148 69.053 25.434 69.137 ;
     RECT  34.308 69.089 35.73 69.137 ;
     RECT  40.215 69.101 41.022 69.137 ;
     RECT  45.615 69.005 45.705 69.137 ;
     RECT  51.015 68.867 51.105 69.137 ;
     RECT  56.415 68.867 56.505 69.137 ;
     RECT  61.815 68.867 61.905 69.137 ;
     RECT  67.215 68.945 67.305 69.137 ;
     RECT  7.56 68.957 8.478 69.245 ;
     RECT  26.172 69.005 29.574 69.245 ;
     RECT  40.788 69.137 41.022 69.245 ;
     RECT  23.148 69.137 23.346 69.293 ;
     RECT  29.556 69.245 29.574 69.293 ;
     RECT  40.788 69.245 40.806 69.293 ;
     RECT  24.264 69.137 25.434 69.341 ;
     RECT  14.328 69.005 15.354 69.485 ;
     RECT  2.16 69.005 3.834 69.533 ;
     RECT  4.932 68.957 6.75 69.533 ;
     RECT  9.432 69.005 9.954 69.533 ;
     RECT  12.456 69.137 12.546 69.533 ;
     RECT  14.328 69.485 15.138 69.533 ;
     RECT  16.38 69.101 19.854 69.533 ;
     RECT  21.096 69.053 22.302 69.533 ;
     RECT  30.96 69.005 31.698 69.533 ;
     RECT  37.944 69.005 37.962 69.533 ;
     RECT  38.736 69.005 38.754 69.533 ;
     RECT  4.932 69.533 5.598 69.581 ;
     RECT  11.304 69.005 11.322 69.581 ;
     RECT  14.328 69.533 14.346 69.581 ;
     RECT  16.38 69.533 18.234 69.581 ;
     RECT  23.148 69.293 23.31 69.581 ;
     RECT  35.208 69.137 35.73 69.581 ;
     RECT  19.44 69.533 19.818 70.109 ;
     RECT  23.148 69.581 23.166 70.109 ;
     RECT  7.56 69.245 7.578 70.157 ;
     RECT  9.648 69.533 9.954 70.157 ;
     RECT  16.956 69.581 18.234 70.157 ;
     RECT  21.348 69.533 21.942 70.157 ;
     RECT  26.172 69.245 28.71 70.157 ;
     RECT  33.336 69.089 33.354 70.157 ;
     RECT  34.308 69.137 34.326 70.157 ;
     RECT  27.288 70.157 28.71 70.205 ;
     RECT  27.288 70.205 27.846 70.253 ;
     RECT  28.656 70.205 28.71 70.637 ;
     RECT  8.46 69.245 8.478 70.651 ;
     RECT  12.456 69.533 12.474 70.685 ;
     RECT  16.956 70.157 17.766 70.685 ;
     RECT  19.8 70.109 19.818 70.685 ;
     RECT  24.84 69.341 25.434 70.685 ;
     RECT  26.172 70.157 26.19 70.685 ;
     RECT  31.68 69.533 31.698 70.685 ;
     RECT  5.58 69.581 5.598 70.733 ;
     RECT  25.164 70.685 25.182 70.733 ;
     RECT  27.288 70.253 27.306 70.733 ;
     RECT  28.692 70.637 28.71 70.733 ;
     RECT  35.712 69.581 35.73 70.733 ;
     RECT  8.46 70.651 8.514 70.795 ;
     RECT  7.056 70.651 7.074 71.035 ;
     RECT  8.388 70.795 8.514 71.035 ;
     RECT  9.648 70.157 9.666 71.035 ;
     RECT  37.62 70.939 37.638 71.035 ;
     RECT  41.724 70.939 41.742 71.035 ;
     RECT  8.388 71.035 9.666 71.069 ;
     RECT  6.84 71.035 7.074 71.117 ;
     RECT  19.044 70.651 19.062 71.117 ;
     RECT  29.988 70.651 30.006 71.117 ;
     RECT  3.384 69.533 3.834 71.165 ;
     RECT  6.84 71.117 6.858 71.165 ;
     RECT  8.388 71.069 9.126 71.165 ;
     RECT  16.956 70.685 16.974 71.165 ;
     RECT  17.748 70.685 17.766 71.165 ;
     RECT  26.28 71.035 26.298 71.165 ;
     RECT  36.936 71.035 37.638 71.165 ;
     RECT  41.724 71.035 42.03 71.165 ;
    LAYER M4 ;
     RECT  0.06 13.776 0.097 25.992 ;
     RECT  0.06 29.136 0.097 32.136 ;
     RECT  0.06 39.12 0.097 48.264 ;
     RECT  0.06 52.176 0.097 58.248 ;
     RECT  0.06 6.864 0.133 9.864 ;
     RECT  0.097 52.032 0.133 58.248 ;
     RECT  0.133 6.864 0.181 10.968 ;
     RECT  0.097 13.776 0.181 26.232 ;
     RECT  0.097 29.136 0.181 32.232 ;
     RECT  0.133 36.912 0.181 36.936 ;
     RECT  0.133 50.592 0.181 50.952 ;
     RECT  0.133 52.032 0.181 59.592 ;
     RECT  0.06 61.392 0.181 64.392 ;
     RECT  0.181 29.04 0.205 32.232 ;
     RECT  0.133 12.24 0.229 12.264 ;
     RECT  0.181 13.776 0.229 26.904 ;
     RECT  0.205 29.04 0.229 32.28 ;
     RECT  0.097 39.12 0.229 48.408 ;
     RECT  0.181 50.304 0.229 59.592 ;
     RECT  0.181 60.576 0.229 64.392 ;
     RECT  0.229 13.776 0.277 27.144 ;
     RECT  0.229 29.04 0.277 32.568 ;
     RECT  0.133 33.648 0.277 33.672 ;
     RECT  0.181 36.912 0.277 37.464 ;
     RECT  0.229 38.448 0.277 49.224 ;
     RECT  0.229 50.304 0.277 64.392 ;
     RECT  0.277 33.648 0.325 34.44 ;
     RECT  0.181 35.904 0.325 35.928 ;
     RECT  0.181 6.576 0.373 10.968 ;
     RECT  0.229 12.24 0.373 12.312 ;
     RECT  0.277 13.776 0.373 32.568 ;
     RECT  0.325 33.648 0.373 35.928 ;
     RECT  0.805 5.472 0.901 5.496 ;
     RECT  0.373 6.576 0.901 32.568 ;
     RECT  0.901 5.472 0.997 32.568 ;
     RECT  0.709 68.256 0.997 68.28 ;
     RECT  0.805 65.952 1.285 65.976 ;
     RECT  0.997 67.344 1.285 68.28 ;
     RECT  1.525 2.832 1.621 2.856 ;
     RECT  1.621 2.784 1.813 2.856 ;
     RECT  0.277 50.304 1.813 64.44 ;
     RECT  1.285 65.952 1.813 68.28 ;
     RECT  1.813 2.784 1.861 3.72 ;
     RECT  0.997 4.752 1.861 32.568 ;
     RECT  0.277 36.912 1.957 49.224 ;
     RECT  1.813 50.304 1.957 68.28 ;
     RECT  1.957 36.912 2.005 68.28 ;
     RECT  1.717 0.144 2.101 0.168 ;
     RECT  1.861 2.352 2.197 32.568 ;
     RECT  0.373 33.552 2.197 35.928 ;
     RECT  2.101 0.144 2.293 0.264 ;
     RECT  2.197 2.352 2.293 35.928 ;
     RECT  2.005 36.912 2.293 68.424 ;
     RECT  2.149 69.504 2.293 69.528 ;
     RECT  2.293 0.144 2.365 0.36 ;
     RECT  2.293 2.256 2.408 69.528 ;
     RECT  2.408 2.148 2.512 69.528 ;
     RECT  2.365 0.048 2.725 0.36 ;
     RECT  2.725 0.048 3.011 0.6 ;
     RECT  2.197 71.04 3.013 71.064 ;
     RECT  3.011 0.048 3.017 0.408 ;
     RECT  2.512 2.16 3.305 69.528 ;
     RECT  3.013 70.896 3.373 71.064 ;
     RECT  3.305 2.16 3.731 69.048 ;
     RECT  3.373 70.896 3.781 71.16 ;
     RECT  3.781 70.512 3.923 71.16 ;
     RECT  3.017 0.096 4.025 0.408 ;
     RECT  3.731 2.16 4.451 69 ;
     RECT  4.025 0.144 4.597 0.408 ;
     RECT  4.451 2.208 4.921 69 ;
     RECT  4.597 0.144 5.065 0.456 ;
     RECT  3.923 71.088 5.123 71.112 ;
     RECT  4.921 2.208 5.459 69.576 ;
     RECT  5.459 2.208 5.653 69.528 ;
     RECT  5.569 70.704 5.843 70.728 ;
     RECT  5.653 2.112 5.845 69.528 ;
     RECT  5.065 0.048 6.373 0.456 ;
     RECT  6.277 70.848 6.709 70.872 ;
     RECT  6.709 70.848 6.757 71.064 ;
     RECT  5.845 2.064 6.761 69.528 ;
     RECT  6.761 2.064 6.829 68.952 ;
     RECT  6.757 70.848 6.869 71.16 ;
     RECT  6.869 70.848 6.997 71.112 ;
     RECT  6.373 0.048 7.333 0.84 ;
     RECT  6.829 1.968 7.333 68.952 ;
     RECT  6.997 70.656 7.549 71.112 ;
     RECT  7.333 0.048 7.808 68.952 ;
     RECT  7.808 0.048 8.101 69.132 ;
     RECT  7.549 70.128 8.101 71.112 ;
     RECT  8.101 0.048 8.188 71.112 ;
     RECT  8.188 0.048 8.243 68.952 ;
     RECT  8.188 70.128 8.243 71.112 ;
     RECT  8.243 70.56 8.377 71.112 ;
     RECT  8.377 70.56 8.627 71.16 ;
     RECT  8.627 70.848 8.723 71.16 ;
     RECT  8.243 0.048 8.849 68.808 ;
     RECT  8.723 70.896 9.158 71.16 ;
     RECT  8.849 2.112 9.421 68.808 ;
     RECT  9.158 70.896 9.733 71.112 ;
     RECT  9.421 2.112 9.875 69.528 ;
     RECT  9.733 70.848 9.925 71.112 ;
     RECT  8.849 0.048 10.549 0.984 ;
     RECT  9.925 70.128 10.835 71.112 ;
     RECT  9.875 2.112 11.293 69 ;
     RECT  10.549 0.048 11.461 1.128 ;
     RECT  11.293 2.112 11.461 69.576 ;
     RECT  11.461 0.048 11.603 69.576 ;
     RECT  10.835 71.088 12.227 71.112 ;
     RECT  11.603 0.048 12.557 69.528 ;
     RECT  12.445 70.656 12.563 70.68 ;
     RECT  12.557 0.048 13.312 69.132 ;
     RECT  13.312 0.048 13.504 68.952 ;
     RECT  13.504 0.048 14.213 37.128 ;
     RECT  13.504 38.208 14.317 68.952 ;
     RECT  14.213 36.384 14.321 37.128 ;
     RECT  14.321 36.816 14.485 37.128 ;
     RECT  14.317 38.208 14.485 69.576 ;
     RECT  14.485 36.816 14.531 69.576 ;
     RECT  14.531 37.056 14.717 69.576 ;
     RECT  14.717 37.056 14.861 37.608 ;
     RECT  14.717 38.784 14.963 69.576 ;
     RECT  14.213 0.048 15.185 34.968 ;
     RECT  14.963 38.784 15.193 69.528 ;
     RECT  15.185 0.096 15.203 34.968 ;
     RECT  15.203 0.096 15.299 1.176 ;
     RECT  15.193 38.784 15.365 69.48 ;
     RECT  15.299 0.096 15.539 0.936 ;
     RECT  15.445 71.088 15.635 71.112 ;
     RECT  15.637 70.992 15.685 71.016 ;
     RECT  15.203 2.16 15.731 34.968 ;
     RECT  15.685 70.896 15.827 71.016 ;
     RECT  15.539 0.096 16.229 0.744 ;
     RECT  14.861 37.056 16.297 37.464 ;
     RECT  15.731 2.16 16.357 34.104 ;
     RECT  15.365 38.784 16.357 69 ;
     RECT  16.357 38.784 16.369 69.528 ;
     RECT  16.369 38.784 16.549 69.576 ;
     RECT  16.549 38.736 16.595 69.576 ;
     RECT  16.297 36.912 17.053 37.464 ;
     RECT  16.229 0.144 17.077 0.744 ;
     RECT  16.357 1.728 17.077 34.104 ;
     RECT  16.333 35.328 17.089 35.352 ;
     RECT  17.053 36.48 17.089 37.464 ;
     RECT  16.595 38.736 17.089 69.528 ;
     RECT  17.077 0.144 17.125 34.104 ;
     RECT  17.089 35.328 17.125 69.528 ;
     RECT  17.125 0.144 17.219 69.528 ;
     RECT  17.219 0.144 17.221 0.696 ;
     RECT  17.219 1.728 17.267 69.528 ;
     RECT  17.221 0.096 17.489 0.696 ;
     RECT  16.901 71.136 17.665 71.16 ;
     RECT  17.665 70.656 17.777 71.16 ;
     RECT  17.267 38.736 18.205 69.528 ;
     RECT  17.777 70.656 18.205 71.112 ;
     RECT  18.205 38.736 18.323 71.112 ;
     RECT  17.267 1.728 18.608 37.608 ;
     RECT  18.323 38.736 18.608 69.528 ;
     RECT  18.608 1.728 18.904 69.528 ;
     RECT  18.323 70.656 19.091 71.112 ;
     RECT  18.904 36.48 19.297 69.528 ;
     RECT  19.297 37.152 19.429 69.528 ;
     RECT  19.091 70.656 19.429 70.68 ;
     RECT  17.489 0.096 19.469 0.648 ;
     RECT  19.429 37.152 19.513 70.68 ;
     RECT  18.904 1.728 19.577 35.352 ;
     RECT  19.513 37.152 19.865 69.528 ;
     RECT  19.469 0.096 20.243 0.552 ;
     RECT  19.577 30.336 20.501 35.352 ;
     RECT  19.513 70.656 20.629 70.68 ;
     RECT  19.865 37.152 20.675 69.096 ;
     RECT  20.675 37.152 20.689 37.704 ;
     RECT  20.501 30.336 20.725 35.4 ;
     RECT  20.725 30.336 20.771 35.448 ;
     RECT  20.689 36.48 20.773 37.704 ;
     RECT  20.675 38.736 20.819 69.096 ;
     RECT  20.819 38.784 21.085 69.096 ;
     RECT  19.577 1.728 21.205 29.112 ;
     RECT  20.243 0.096 21.253 0.408 ;
     RECT  21.085 38.784 21.337 69.528 ;
     RECT  20.629 70.656 21.337 71.112 ;
     RECT  21.205 1.728 21.445 29.208 ;
     RECT  20.771 30.336 21.445 34.104 ;
     RECT  20.773 37.008 21.557 37.704 ;
     RECT  21.445 1.728 21.701 34.104 ;
     RECT  21.337 38.784 21.731 71.112 ;
     RECT  21.701 1.728 22.205 33.624 ;
     RECT  21.253 0.096 22.213 0.552 ;
     RECT  20.771 35.424 22.261 35.448 ;
     RECT  22.213 0.096 22.405 0.6 ;
     RECT  22.205 1.728 22.405 28.824 ;
     RECT  21.731 38.784 22.837 70.152 ;
     RECT  21.557 37.008 22.885 37.608 ;
     RECT  22.837 38.784 22.885 71.112 ;
     RECT  22.261 35.424 22.933 35.88 ;
     RECT  22.885 37.008 22.933 71.112 ;
     RECT  22.933 35.424 23.02 71.112 ;
     RECT  22.405 0.096 23.033 28.824 ;
     RECT  22.205 30.048 23.221 33.624 ;
     RECT  23.033 0.144 23.267 28.824 ;
     RECT  23.267 0.24 23.317 28.824 ;
     RECT  23.02 37.056 23.507 71.112 ;
     RECT  23.02 35.424 23.605 35.448 ;
     RECT  23.605 35.328 23.965 35.448 ;
     RECT  23.317 0.24 24.008 29.064 ;
     RECT  23.221 30.048 24.008 34.008 ;
     RECT  23.965 34.992 24.008 35.448 ;
     RECT  23.507 37.056 24.008 69.336 ;
     RECT  24.008 0.24 24.304 69.336 ;
     RECT  24.304 0.24 24.325 12.072 ;
     RECT  24.304 13.104 24.419 33.576 ;
     RECT  23.507 70.944 24.709 71.112 ;
     RECT  24.325 0.144 24.805 12.072 ;
     RECT  24.304 37.392 24.851 69.336 ;
     RECT  24.304 34.608 24.949 35.88 ;
     RECT  24.805 0.096 25.091 12.072 ;
     RECT  24.851 37.392 25.121 68.52 ;
     RECT  24.949 34.608 25.139 35.4 ;
     RECT  25.091 0.096 25.201 4.584 ;
     RECT  25.201 0.096 25.283 2.76 ;
     RECT  25.121 37.392 25.331 37.704 ;
     RECT  25.091 5.712 25.436 12.072 ;
     RECT  24.419 13.104 25.436 33.144 ;
     RECT  25.283 0.096 25.513 2.568 ;
     RECT  25.436 5.712 25.517 33.144 ;
     RECT  25.517 12.528 25.523 33.144 ;
     RECT  25.523 13.104 25.553 33.144 ;
     RECT  25.517 5.712 25.661 11.4 ;
     RECT  25.201 3.744 25.697 4.584 ;
     RECT  25.697 3.744 25.715 3.96 ;
     RECT  25.121 38.784 25.873 68.52 ;
     RECT  25.297 69.504 25.873 69.528 ;
     RECT  25.661 5.808 25.913 11.4 ;
     RECT  25.913 7.2 25.985 11.4 ;
     RECT  25.913 5.808 26.021 5.88 ;
     RECT  25.139 34.608 26.129 35.304 ;
     RECT  24.709 70.656 26.225 71.112 ;
     RECT  25.715 3.936 26.237 3.96 ;
     RECT  26.225 70.656 26.309 71.16 ;
     RECT  25.513 0.048 26.705 2.568 ;
     RECT  25.553 13.104 26.777 27.48 ;
     RECT  25.873 38.784 26.821 69.528 ;
     RECT  26.309 70.656 26.821 71.112 ;
     RECT  26.021 5.856 26.965 5.88 ;
     RECT  25.985 7.2 26.965 10.968 ;
     RECT  26.965 5.856 26.993 10.968 ;
     RECT  26.993 6.24 27.011 10.968 ;
     RECT  27.011 6.24 27.052 6.264 ;
     RECT  26.821 38.784 27.347 71.112 ;
     RECT  27.347 38.784 27.649 70.728 ;
     RECT  26.705 1.728 27.821 2.568 ;
     RECT  27.821 2.496 28.037 2.568 ;
     RECT  27.649 70.08 28.211 70.728 ;
     RECT  28.211 70.176 28.307 70.728 ;
     RECT  28.307 70.224 28.595 70.728 ;
     RECT  26.705 0.048 28.829 0.216 ;
     RECT  27.649 38.784 28.933 69 ;
     RECT  28.933 38.688 29.005 69 ;
     RECT  26.129 34.608 29.029 34.92 ;
     RECT  25.331 37.392 29.077 37.608 ;
     RECT  29.005 38.592 29.077 69 ;
     RECT  28.829 0.048 29.117 0.072 ;
     RECT  29.077 37.152 29.269 69 ;
     RECT  28.595 70.608 29.363 70.728 ;
     RECT  28.037 2.496 29.408 2.52 ;
     RECT  27.011 7.488 29.408 10.968 ;
     RECT  26.777 13.44 29.408 27.48 ;
     RECT  25.553 28.56 29.408 33.144 ;
     RECT  29.029 34.608 29.408 35.304 ;
     RECT  29.269 37.152 29.408 69.336 ;
     RECT  29.408 2.148 29.512 69.336 ;
     RECT  29.512 2.418 29.555 69.336 ;
     RECT  29.555 2.418 29.585 69.288 ;
     RECT  29.585 2.418 29.651 69.24 ;
     RECT  29.363 70.656 29.701 70.728 ;
     RECT  29.651 2.418 29.704 69 ;
     RECT  29.701 70.656 29.948 71.016 ;
     RECT  29.948 70.656 30.035 71.112 ;
     RECT  29.704 34.512 30.241 35.544 ;
     RECT  29.704 37.008 30.949 69 ;
     RECT  30.949 36.72 31.033 69.528 ;
     RECT  31.033 36.72 31.036 69 ;
     RECT  30.241 34.512 31.061 35.4 ;
     RECT  29.704 28.56 31.129 33.144 ;
     RECT  31.061 35.088 31.139 35.4 ;
     RECT  30.035 70.656 31.477 70.68 ;
     RECT  31.129 28.56 31.493 33.672 ;
     RECT  31.477 70.656 32.051 71.112 ;
     RECT  29.704 7.488 32.069 10.968 ;
     RECT  31.772 35.424 32.173 35.448 ;
     RECT  29.704 13.44 32.217 27.48 ;
     RECT  31.493 28.56 32.217 33.144 ;
     RECT  32.173 34.8 32.281 35.448 ;
     RECT  32.069 7.488 32.393 10.68 ;
     RECT  32.281 34.8 32.54 35.544 ;
     RECT  32.54 34.8 32.677 35.64 ;
     RECT  32.677 34.752 32.785 35.64 ;
     RECT  32.393 7.488 32.897 10.44 ;
     RECT  32.217 13.44 32.924 33.144 ;
     RECT  32.785 34.704 32.929 35.64 ;
     RECT  31.036 36.96 32.929 69 ;
     RECT  32.051 71.088 32.963 71.112 ;
     RECT  32.924 13.44 33.001 33.528 ;
     RECT  32.929 34.704 33.001 69 ;
     RECT  33.001 13.44 33.217 69 ;
     RECT  32.897 7.488 34.213 9.912 ;
     RECT  33.217 13.44 34.513 69.048 ;
     RECT  34.513 12.48 34.789 69.048 ;
     RECT  33.325 70.128 34.789 70.152 ;
     RECT  34.213 7.392 34.808 9.912 ;
     RECT  34.789 12.48 34.808 70.152 ;
     RECT  34.808 2.148 35.027 70.152 ;
     RECT  35.027 2.148 35.104 69.576 ;
     RECT  35.104 5.088 35.245 11.448 ;
     RECT  35.261 0.096 35.269 0.12 ;
     RECT  35.104 12.48 35.315 69.576 ;
     RECT  35.269 0.096 35.345 0.216 ;
     RECT  35.315 12.48 35.345 69.336 ;
     RECT  35.345 0.192 35.411 0.216 ;
     RECT  35.245 5.76 35.489 11.448 ;
     RECT  35.461 1.728 35.921 1.8 ;
     RECT  35.345 12.48 36.029 69 ;
     RECT  35.701 70.704 36.275 70.728 ;
     RECT  36.349 3.984 36.413 4.008 ;
     RECT  35.921 1.776 36.421 1.8 ;
     RECT  36.421 1.776 36.533 2.76 ;
     RECT  35.489 5.76 36.601 11.016 ;
     RECT  36.413 3.984 36.709 4.584 ;
     RECT  36.601 5.712 36.709 11.016 ;
     RECT  36.757 71.04 36.805 71.064 ;
     RECT  36.533 2.736 36.949 2.76 ;
     RECT  36.709 3.984 36.949 11.016 ;
     RECT  36.949 2.736 36.997 11.016 ;
     RECT  36.997 2.736 37.001 11.448 ;
     RECT  37.001 6.816 37.033 11.448 ;
     RECT  36.029 12.48 37.033 68.952 ;
     RECT  37.001 2.736 37.043 5.832 ;
     RECT  36.805 71.04 37.381 71.16 ;
     RECT  37.381 70.992 37.429 71.16 ;
     RECT  37.033 6.816 37.477 68.952 ;
     RECT  37.429 70.896 37.619 71.16 ;
     RECT  37.619 70.944 37.715 71.16 ;
     RECT  37.477 6.816 37.933 69 ;
     RECT  37.715 70.944 37.955 71.016 ;
     RECT  37.043 2.736 38.005 5.784 ;
     RECT  37.933 6.816 38.005 69.528 ;
     RECT  37.955 70.944 38.147 70.968 ;
     RECT  38.005 2.736 38.149 69.528 ;
     RECT  37.897 1.104 38.437 1.128 ;
     RECT  36.817 0.048 38.509 0.072 ;
     RECT  38.149 2.496 38.581 69.528 ;
     RECT  38.581 2.256 38.765 69.528 ;
     RECT  38.437 1.104 38.797 1.176 ;
     RECT  38.765 2.256 38.797 69 ;
     RECT  38.917 71.088 39.155 71.16 ;
     RECT  39.155 71.088 39.299 71.112 ;
     RECT  38.509 0.048 39.337 0.12 ;
     RECT  38.797 1.104 39.337 69 ;
     RECT  39.337 0.048 39.539 69 ;
     RECT  39.539 0.048 39.731 1.128 ;
     RECT  39.539 2.148 40.208 69 ;
     RECT  39.731 0.048 40.307 0.648 ;
     RECT  40.208 2.148 40.453 69.132 ;
     RECT  40.453 2.148 40.549 69.24 ;
     RECT  40.549 2.148 40.669 69.288 ;
     RECT  40.669 1.68 40.817 69.288 ;
     RECT  40.817 1.68 40.882 69.24 ;
     RECT  40.882 1.632 40.889 69.24 ;
     RECT  40.889 4.512 41.033 69.24 ;
     RECT  40.307 0.048 41.249 0.312 ;
     RECT  40.889 1.632 41.363 3.432 ;
     RECT  40.693 71.088 41.365 71.112 ;
     RECT  41.033 4.512 41.459 69.096 ;
     RECT  41.249 0.096 41.461 0.312 ;
     RECT  41.363 1.632 41.461 1.8 ;
     RECT  41.459 4.512 41.465 68.952 ;
     RECT  41.365 70.992 41.669 71.112 ;
     RECT  41.669 70.992 41.713 71.16 ;
     RECT  41.713 70.944 41.843 71.16 ;
     RECT  41.363 3.216 41.929 3.432 ;
     RECT  41.465 4.512 41.929 11.448 ;
     RECT  41.843 71.04 42.041 71.16 ;
     RECT  42.041 71.04 42.083 71.112 ;
     RECT  42.083 71.04 42.179 71.064 ;
     RECT  41.465 12.528 42.401 68.952 ;
     RECT  41.461 0.096 42.445 1.8 ;
     RECT  42.445 0.144 42.613 1.8 ;
     RECT  41.929 3.216 42.613 11.448 ;
     RECT  42.613 0.144 42.661 11.448 ;
     RECT  42.401 12.528 42.661 27.96 ;
     RECT  42.401 28.944 42.797 68.952 ;
     RECT  42.661 0.144 42.869 27.96 ;
     RECT  42.869 0.144 43.379 4.68 ;
     RECT  43.379 1.728 43.475 4.68 ;
     RECT  42.869 5.712 43.837 27.96 ;
     RECT  43.837 5.088 43.909 27.96 ;
     RECT  42.797 28.992 43.909 68.952 ;
     RECT  43.909 5.088 44.243 68.952 ;
     RECT  43.475 1.728 44.273 3.912 ;
     RECT  43.379 0.144 44.291 0.216 ;
     RECT  44.243 5.088 44.435 35.928 ;
     RECT  44.243 36.912 44.485 68.952 ;
     RECT  44.291 0.192 45.061 0.216 ;
     RECT  44.273 2.256 45.061 3.912 ;
     RECT  45.061 0.192 45.203 1.176 ;
     RECT  45.061 2.256 45.253 3.96 ;
     RECT  44.435 5.088 45.253 10.92 ;
     RECT  45.253 2.256 45.349 10.92 ;
     RECT  44.435 28.896 45.385 35.928 ;
     RECT  44.485 36.912 45.385 69 ;
     RECT  45.349 1.728 45.397 10.92 ;
     RECT  44.435 12 45.397 27.912 ;
     RECT  45.203 0.192 45.539 0.36 ;
     RECT  45.397 1.728 45.608 27.912 ;
     RECT  45.385 28.896 45.608 69 ;
     RECT  45.608 1.728 45.712 69.132 ;
     RECT  45.712 1.728 45.904 69 ;
     RECT  45.904 3.408 45.965 69 ;
     RECT  45.904 1.728 46.163 2.328 ;
     RECT  45.965 3.408 46.181 68.952 ;
     RECT  46.181 3.408 46.211 37.656 ;
     RECT  45.539 0.192 46.213 0.312 ;
     RECT  46.211 3.408 46.325 37.608 ;
     RECT  46.325 3.408 46.397 11.448 ;
     RECT  46.397 6.048 46.685 11.448 ;
     RECT  46.325 12.528 46.739 34.248 ;
     RECT  46.685 6.048 46.793 6.312 ;
     RECT  46.213 0.096 46.825 0.312 ;
     RECT  46.325 35.616 46.883 37.608 ;
     RECT  46.163 1.728 47.173 2.28 ;
     RECT  46.397 3.408 47.173 5.016 ;
     RECT  46.883 35.808 47.221 37.608 ;
     RECT  46.181 38.64 47.221 68.952 ;
     RECT  46.825 0.096 47.293 0.36 ;
     RECT  47.173 1.728 47.293 5.016 ;
     RECT  47.293 0.096 47.333 5.016 ;
     RECT  47.333 2.256 47.365 5.016 ;
     RECT  46.793 6.048 47.365 6.072 ;
     RECT  46.739 29.232 47.369 34.152 ;
     RECT  47.365 2.256 47.405 6.072 ;
     RECT  47.221 35.808 47.521 68.952 ;
     RECT  47.521 37.008 47.549 68.952 ;
     RECT  47.369 30.384 47.621 34.152 ;
     RECT  46.685 7.728 47.66 11.448 ;
     RECT  46.739 12.528 47.66 27.912 ;
     RECT  47.549 37.008 47.773 37.416 ;
     RECT  47.66 7.728 47.797 27.912 ;
     RECT  47.549 38.736 47.801 68.952 ;
     RECT  47.801 38.736 47.837 68.376 ;
     RECT  47.749 34.464 47.845 34.728 ;
     RECT  47.837 52.464 47.891 68.376 ;
     RECT  47.797 6.864 47.909 27.912 ;
     RECT  47.845 34.464 47.932 34.776 ;
     RECT  47.405 2.256 47.945 5.736 ;
     RECT  47.932 34.464 48.017 34.728 ;
     RECT  47.521 35.808 48.125 35.88 ;
     RECT  47.909 12.864 48.133 27.912 ;
     RECT  47.773 37.056 48.269 37.416 ;
     RECT  47.369 29.232 48.301 29.256 ;
     RECT  47.333 0.096 48.325 1.176 ;
     RECT  47.945 2.256 48.325 5.16 ;
     RECT  48.133 12.864 48.325 28.008 ;
     RECT  48.301 29.088 48.325 29.256 ;
     RECT  47.837 38.736 48.413 51.48 ;
     RECT  47.909 6.864 48.445 11.832 ;
     RECT  48.269 37.104 48.467 37.416 ;
     RECT  48.467 37.104 48.485 37.176 ;
     RECT  47.621 30.384 48.733 33.288 ;
     RECT  48.445 6.288 48.877 11.832 ;
     RECT  48.325 12.864 48.877 29.256 ;
     RECT  48.413 38.736 48.949 50.184 ;
     RECT  48.325 0.096 48.953 5.16 ;
     RECT  48.953 3.984 48.956 5.16 ;
     RECT  48.956 3.984 49.043 5.208 ;
     RECT  48.877 6.288 49.084 29.256 ;
     RECT  47.891 52.512 49.133 68.376 ;
     RECT  49.084 6.288 49.421 11.784 ;
     RECT  48.949 38.208 49.421 50.184 ;
     RECT  49.084 12.768 49.457 29.256 ;
     RECT  49.421 38.784 49.489 50.184 ;
     RECT  48.413 51.456 49.489 51.48 ;
     RECT  48.017 34.464 49.58 34.488 ;
     RECT  48.125 35.856 49.58 35.88 ;
     RECT  48.485 37.104 49.58 37.128 ;
     RECT  49.58 34.464 49.601 35.88 ;
     RECT  49.457 12.816 49.619 29.256 ;
     RECT  48.733 30.24 49.621 33.288 ;
     RECT  49.601 34.464 49.621 35.064 ;
     RECT  49.58 36.912 49.621 37.128 ;
     RECT  49.621 30.24 49.667 35.064 ;
     RECT  49.621 36.912 49.667 37.656 ;
     RECT  48.953 0.096 49.853 2.952 ;
     RECT  49.619 12.816 49.853 29.112 ;
     RECT  49.043 3.984 49.889 5.16 ;
     RECT  49.853 12.816 49.889 28.632 ;
     RECT  49.889 13.68 49.907 28.632 ;
     RECT  49.133 52.512 49.961 68.136 ;
     RECT  49.421 6.288 50.437 11.304 ;
     RECT  49.489 38.784 50.533 51.48 ;
     RECT  49.961 52.512 50.533 60.984 ;
     RECT  50.533 12.528 50.869 12.552 ;
     RECT  49.907 13.68 50.869 28.248 ;
     RECT  49.853 0.096 51.008 2.904 ;
     RECT  49.889 3.984 51.008 4.152 ;
     RECT  49.889 5.136 51.008 5.16 ;
     RECT  50.437 6.24 51.008 11.304 ;
     RECT  50.869 12.528 51.008 28.248 ;
     RECT  49.667 30.24 51.008 34.152 ;
     RECT  49.667 37.632 51.008 37.656 ;
     RECT  50.533 38.784 51.008 60.984 ;
     RECT  49.961 62.16 51.008 68.136 ;
     RECT  51.008 0.096 51.112 69.132 ;
     RECT  51.112 0.096 51.304 68.862 ;
     RECT  51.304 13.68 51.365 24.216 ;
     RECT  51.304 54.144 51.473 58.68 ;
     RECT  51.304 6.288 51.761 10.728 ;
     RECT  51.473 54.144 51.797 56.568 ;
     RECT  51.304 66.24 51.833 66.888 ;
     RECT  51.761 8.016 51.905 10.728 ;
     RECT  51.304 25.248 51.905 28.152 ;
     RECT  51.304 62.448 51.905 64.728 ;
     RECT  51.304 0.096 51.941 2.616 ;
     RECT  51.304 30.432 51.941 33.288 ;
     RECT  51.941 30.432 52.049 31.464 ;
     RECT  51.304 52.464 52.121 53.112 ;
     RECT  51.304 59.856 52.157 59.88 ;
     RECT  52.049 30.432 52.229 31.416 ;
     RECT  51.304 60.864 52.229 60.888 ;
     RECT  51.833 66.576 52.405 66.888 ;
     RECT  51.304 68.112 52.405 68.136 ;
     RECT  51.905 62.544 52.513 64.728 ;
     RECT  51.941 0.096 52.517 2.52 ;
     RECT  51.797 54.144 52.517 56.472 ;
     RECT  51.761 6.288 52.553 6.984 ;
     RECT  51.304 45.168 52.553 46.92 ;
     RECT  51.365 13.968 52.625 24.216 ;
     RECT  51.905 8.016 52.799 10.344 ;
     RECT  51.304 38.784 52.909 44.184 ;
     RECT  52.625 13.968 52.913 23.64 ;
     RECT  52.121 52.704 53.017 53.112 ;
     RECT  52.799 7.392 53.027 10.344 ;
     RECT  52.513 62.544 53.027 65.016 ;
     RECT  52.553 6.288 53.093 6.312 ;
     RECT  53.017 52.704 53.125 53.16 ;
     RECT  52.517 0.096 53.165 0.888 ;
     RECT  52.913 13.968 53.165 19.56 ;
     RECT  52.229 30.432 53.201 30.456 ;
     RECT  52.517 54.336 53.237 56.472 ;
     RECT  53.125 52.704 53.305 53.256 ;
     RECT  52.909 38.592 53.309 44.184 ;
     RECT  51.473 57.552 53.345 58.68 ;
     RECT  53.027 7.872 53.417 10.344 ;
     RECT  53.309 39.6 53.417 44.184 ;
     RECT  53.165 19.536 53.453 19.56 ;
     RECT  53.305 52.656 53.489 53.256 ;
     RECT  53.309 38.592 53.507 38.616 ;
     RECT  51.304 48.096 53.521 50.616 ;
     RECT  53.417 39.6 53.525 44.088 ;
     RECT  53.417 8.016 53.597 10.344 ;
     RECT  53.489 52.704 53.597 53.256 ;
     RECT  51.905 25.728 53.603 28.152 ;
     RECT  52.517 1.872 53.633 2.376 ;
     RECT  53.597 53.088 53.665 53.256 ;
     RECT  53.237 54.336 53.665 55.896 ;
     RECT  53.165 0.816 53.669 0.888 ;
     RECT  53.525 40.176 53.705 44.088 ;
     RECT  53.669 0.816 53.777 0.84 ;
     RECT  53.665 53.088 53.777 55.896 ;
     RECT  52.405 66.576 53.849 68.136 ;
     RECT  53.027 62.544 53.917 64.728 ;
     RECT  53.633 1.872 53.921 1.896 ;
     RECT  53.777 53.088 53.921 55.8 ;
     RECT  53.705 42.192 53.957 44.088 ;
     RECT  53.917 62.112 54.131 64.728 ;
     RECT  52.369 36.432 54.133 36.456 ;
     RECT  53.521 48.096 54.173 50.76 ;
     RECT  52.553 46.032 54.457 46.92 ;
     RECT  54.173 48.096 54.457 49.848 ;
     RECT  53.849 66.576 54.497 67.848 ;
     RECT  54.133 35.52 54.556 36.456 ;
     RECT  54.469 37.872 54.556 37.896 ;
     RECT  51.941 33.264 54.565 33.288 ;
     RECT  53.705 40.176 54.673 41.112 ;
     RECT  53.165 13.968 54.709 18.504 ;
     RECT  53.957 44.064 54.709 44.088 ;
     RECT  54.565 33.264 54.749 33.624 ;
     RECT  54.131 62.544 54.857 64.728 ;
     RECT  54.709 13.968 54.929 19.416 ;
     RECT  54.497 66.576 55.069 67.368 ;
     RECT  53.597 9.888 55.145 10.344 ;
     RECT  54.749 33.264 55.285 33.576 ;
     RECT  55.237 51.648 55.324 52.056 ;
     RECT  55.244 31.056 55.331 31.08 ;
     RECT  53.921 53.088 55.381 55.464 ;
     RECT  53.345 58.656 55.427 58.68 ;
     RECT  54.709 44.064 55.465 44.376 ;
     RECT  55.285 33.12 55.753 33.576 ;
     RECT  54.673 34.752 55.753 35.064 ;
     RECT  52.913 21.168 55.861 23.64 ;
     RECT  54.997 60.864 56.108 60.888 ;
     RECT  56.108 60.864 56.149 61.272 ;
     RECT  54.857 63.072 56.149 64.728 ;
     RECT  53.603 25.776 56.293 28.152 ;
     RECT  53.597 8.016 56.408 8.808 ;
     RECT  55.145 9.888 56.408 10.296 ;
     RECT  54.929 13.968 56.408 18.504 ;
     RECT  55.861 21.168 56.408 23.928 ;
     RECT  56.293 25.776 56.408 28.248 ;
     RECT  55.285 29.808 56.408 29.832 ;
     RECT  55.861 31.248 56.408 31.272 ;
     RECT  55.753 33.12 56.408 35.064 ;
     RECT  54.556 36.24 56.408 36.456 ;
     RECT  54.673 40.128 56.408 41.112 ;
     RECT  53.957 42.192 56.408 42.744 ;
     RECT  55.465 44.064 56.408 44.472 ;
     RECT  54.457 46.032 56.408 49.848 ;
     RECT  55.324 51.648 56.408 51.672 ;
     RECT  55.381 53.088 56.408 56.28 ;
     RECT  53.345 57.552 56.408 57.576 ;
     RECT  56.149 60.864 56.408 61.464 ;
     RECT  56.149 62.784 56.408 64.728 ;
     RECT  55.069 66.48 56.408 67.368 ;
     RECT  56.408 2.148 56.512 69.132 ;
     RECT  56.512 2.418 56.704 68.862 ;
     RECT  56.704 33.12 56.765 33.288 ;
     RECT  56.704 34.752 56.819 36.264 ;
     RECT  56.704 44.352 56.837 51.672 ;
     RECT  56.837 45.408 56.909 51.672 ;
     RECT  56.704 19.632 57.011 24.216 ;
     RECT  56.837 44.352 57.125 44.376 ;
     RECT  56.704 59.616 57.436 60.312 ;
     RECT  56.909 45.408 57.443 51 ;
     RECT  56.704 53.088 57.485 53.16 ;
     RECT  56.704 66.48 57.521 67.752 ;
     RECT  57.443 48.432 57.539 51 ;
     RECT  56.819 34.752 57.557 34.776 ;
     RECT  57.485 53.136 57.557 53.16 ;
     RECT  57.539 48.816 57.629 51 ;
     RECT  56.704 13.968 57.685 13.992 ;
     RECT  56.704 15.168 57.685 18.504 ;
     RECT  57.685 13.968 57.733 18.504 ;
     RECT  56.704 40.8 57.733 42.744 ;
     RECT  57.011 19.632 57.769 19.944 ;
     RECT  57.733 13.056 57.781 18.504 ;
     RECT  57.733 39.888 57.781 42.744 ;
     RECT  57.781 38.736 57.827 42.744 ;
     RECT  57.443 45.408 57.913 47.352 ;
     RECT  56.704 54.144 57.913 56.28 ;
     RECT  56.704 57.552 57.913 57.576 ;
     RECT  57.827 38.736 57.953 39.336 ;
     RECT  58.021 32.016 58.117 32.04 ;
     RECT  56.765 33.264 58.117 33.288 ;
     RECT  57.781 13.056 58.129 14.136 ;
     RECT  58.117 31.488 58.163 32.04 ;
     RECT  57.521 66.48 58.169 67.272 ;
     RECT  57.913 45.12 58.205 47.352 ;
     RECT  57.827 40.8 58.241 42.744 ;
     RECT  58.129 12.384 58.357 14.136 ;
     RECT  57.781 15.168 58.381 18.504 ;
     RECT  57.769 19.488 58.381 19.944 ;
     RECT  56.704 9.888 58.403 10.632 ;
     RECT  57.011 21.168 58.453 24.216 ;
     RECT  58.205 45.12 58.489 47.208 ;
     RECT  57.913 54.144 58.489 57.576 ;
     RECT  58.489 44.736 58.493 47.208 ;
     RECT  57.629 48.816 58.499 50.712 ;
     RECT  58.493 44.736 58.529 45.672 ;
     RECT  57.436 59.616 58.529 59.64 ;
     RECT  56.704 61.44 58.601 61.464 ;
     RECT  56.704 25.776 58.669 28.248 ;
     RECT  58.357 11.712 58.691 14.136 ;
     RECT  58.381 15.168 58.741 19.944 ;
     RECT  58.453 21.168 58.741 24.504 ;
     RECT  58.741 15.168 58.817 24.504 ;
     RECT  56.704 29.808 58.817 29.832 ;
     RECT  58.163 31.488 58.853 31.8 ;
     RECT  58.241 42.192 58.885 42.744 ;
     RECT  58.669 25.776 58.925 28.44 ;
     RECT  58.415 51.888 59.057 51.912 ;
     RECT  58.529 44.736 59.105 45.576 ;
     RECT  58.169 66.576 59.132 67.272 ;
     RECT  59.057 51.888 59.137 52.488 ;
     RECT  58.853 31.488 59.177 31.704 ;
     RECT  59.137 51.888 59.209 52.776 ;
     RECT  59.132 66.576 59.219 67.32 ;
     RECT  58.241 40.8 59.276 41.112 ;
     RECT  58.885 42.192 59.276 42.792 ;
     RECT  59.276 40.8 59.357 42.792 ;
     RECT  58.493 46.752 59.413 47.208 ;
     RECT  59.219 66.576 59.425 67.272 ;
     RECT  58.489 54.096 59.453 57.576 ;
     RECT  59.353 58.752 59.453 58.776 ;
     RECT  59.425 66.24 59.459 67.272 ;
     RECT  59.453 54.096 59.537 58.776 ;
     RECT  58.691 11.712 59.573 11.736 ;
     RECT  58.691 13.056 59.573 14.136 ;
     RECT  59.105 44.736 59.605 45.144 ;
     RECT  59.209 51.888 59.605 52.824 ;
     RECT  59.537 54.096 59.605 57.576 ;
     RECT  57.953 39.312 59.681 39.336 ;
     RECT  58.499 48.816 59.681 50.28 ;
     RECT  59.573 13.968 59.708 14.136 ;
     RECT  58.817 15.168 59.708 23.64 ;
     RECT  59.357 40.848 59.713 42.792 ;
     RECT  59.413 46.752 59.785 47.304 ;
     RECT  59.681 48.816 59.785 49.848 ;
     RECT  59.708 13.968 59.795 23.64 ;
     RECT  59.713 40.848 59.821 43.032 ;
     RECT  59.605 44.064 59.821 45.144 ;
     RECT  56.704 63.264 59.825 64.728 ;
     RECT  59.795 15.168 60.113 23.64 ;
     RECT  59.459 66.24 60.113 67.032 ;
     RECT  60.113 20.304 60.149 23.64 ;
     RECT  59.825 63.264 60.149 64.2 ;
     RECT  56.819 36.24 60.181 36.264 ;
     RECT  59.821 40.848 60.221 45.144 ;
     RECT  59.785 46.368 60.253 47.304 ;
     RECT  59.785 48.672 60.253 49.848 ;
     RECT  59.537 58.704 60.253 58.776 ;
     RECT  60.221 44.016 60.257 45.144 ;
     RECT  59.177 31.536 60.361 31.704 ;
     RECT  58.117 33.264 60.361 34.056 ;
     RECT  59.605 51.888 60.365 57.576 ;
     RECT  60.361 31.536 60.401 34.056 ;
     RECT  60.253 46.368 60.437 49.848 ;
     RECT  60.149 63.264 60.437 63.288 ;
     RECT  60.221 40.848 60.545 43.032 ;
     RECT  59.795 13.968 60.805 14.136 ;
     RECT  60.113 15.168 60.805 19.08 ;
     RECT  58.925 25.776 60.937 28.008 ;
     RECT  60.545 40.848 60.937 41.112 ;
     RECT  60.149 20.928 61.261 23.64 ;
     RECT  60.937 24.912 61.261 28.008 ;
     RECT  60.253 58.704 61.34 59.256 ;
     RECT  60.437 46.848 61.405 49.848 ;
     RECT  61.405 46.848 61.429 49.896 ;
     RECT  60.401 31.68 61.441 34.056 ;
     RECT  61.429 46.848 61.441 50.52 ;
     RECT  60.113 66.24 61.477 66.936 ;
     RECT  61.441 31.632 61.484 34.056 ;
     RECT  60.937 40.656 61.549 41.112 ;
     RECT  60.545 42.192 61.549 43.032 ;
     RECT  60.365 51.936 61.669 57.576 ;
     RECT  60.257 44.016 61.729 45.096 ;
     RECT  60.805 13.968 61.801 19.08 ;
     RECT  61.549 40.656 61.801 43.032 ;
     RECT  61.729 44.016 61.801 45.768 ;
     RECT  56.704 8.016 61.808 8.808 ;
     RECT  58.403 9.888 61.808 9.912 ;
     RECT  61.801 13.056 61.808 19.08 ;
     RECT  61.261 20.736 61.808 23.64 ;
     RECT  61.261 24.912 61.808 28.488 ;
     RECT  61.484 31.632 61.808 34.344 ;
     RECT  60.181 35.664 61.808 36.264 ;
     RECT  60.793 38.784 61.808 38.808 ;
     RECT  61.801 40.656 61.808 45.768 ;
     RECT  61.441 46.848 61.808 50.616 ;
     RECT  61.669 51.936 61.808 57.72 ;
     RECT  61.34 58.704 61.808 59.736 ;
     RECT  61.477 66.048 61.808 66.936 ;
     RECT  61.808 2.148 61.912 69.132 ;
     RECT  61.912 2.418 62.104 68.862 ;
     RECT  62.104 11.376 62.165 21.672 ;
     RECT  62.104 40.656 62.165 45.768 ;
     RECT  62.104 46.752 62.165 49.896 ;
     RECT  62.165 40.656 62.243 44.76 ;
     RECT  62.243 42.192 62.273 44.76 ;
     RECT  62.165 46.752 62.345 49.848 ;
     RECT  62.345 46.8 62.381 49.848 ;
     RECT  62.104 58.752 62.597 58.968 ;
     RECT  62.165 17.664 62.627 21.672 ;
     RECT  62.597 58.944 62.741 58.968 ;
     RECT  62.104 8.016 62.771 10.344 ;
     RECT  62.104 66.24 63.011 67.56 ;
     RECT  62.165 11.376 63.173 16.68 ;
     RECT  63.011 66.24 63.173 66.264 ;
     RECT  62.104 30.24 63.241 33.576 ;
     RECT  63.173 15.168 63.313 16.68 ;
     RECT  62.627 17.664 63.313 19.8 ;
     RECT  62.627 20.832 63.349 21.672 ;
     RECT  62.104 22.704 63.349 28.488 ;
     RECT  62.273 42.192 63.353 43.656 ;
     RECT  62.165 45.744 63.353 45.768 ;
     RECT  63.169 35.328 63.357 35.352 ;
     RECT  62.273 44.688 63.385 44.76 ;
     RECT  63.353 42.576 63.461 43.656 ;
     RECT  63.241 30.24 63.497 33.672 ;
     RECT  62.243 40.656 63.529 41.208 ;
     RECT  63.461 42.624 63.541 43.656 ;
     RECT  63.385 44.688 63.541 45.24 ;
     RECT  63.529 40.656 63.613 41.592 ;
     RECT  62.381 48.192 63.641 49.848 ;
     RECT  63.313 15.168 63.673 19.8 ;
     RECT  63.349 20.832 63.673 28.488 ;
     RECT  63.589 65.904 63.676 65.928 ;
     RECT  63.641 48.288 63.677 49.848 ;
     RECT  63.677 48.384 63.709 49.848 ;
     RECT  63.357 34.752 63.785 35.352 ;
     RECT  63.497 30.96 63.817 33.672 ;
     RECT  63.785 34.752 63.817 34.776 ;
     RECT  63.173 11.376 63.893 13.992 ;
     RECT  63.313 64.368 63.925 64.392 ;
     RECT  63.853 62.64 63.971 62.664 ;
     RECT  63.673 15.168 64.001 28.488 ;
     RECT  63.613 40.656 64.021 41.112 ;
     RECT  64.021 39.888 64.033 41.112 ;
     RECT  64.033 39.6 64.108 41.112 ;
     RECT  62.104 52.224 64.109 57.576 ;
     RECT  64.001 21.216 64.117 28.488 ;
     RECT  63.893 11.376 64.145 12.36 ;
     RECT  63.011 67.488 64.165 67.56 ;
     RECT  64.117 21.216 64.204 28.92 ;
     RECT  62.381 46.8 64.321 47.208 ;
     RECT  64.109 52.224 64.357 56.376 ;
     RECT  64.109 57.408 64.433 57.576 ;
     RECT  63.541 42.624 64.465 45.24 ;
     RECT  64.321 46.32 64.465 47.208 ;
     RECT  63.925 63.744 64.469 64.392 ;
     RECT  62.771 8.016 64.645 9.912 ;
     RECT  64.429 11.136 64.645 11.16 ;
     RECT  64.469 63.744 64.685 64.104 ;
     RECT  63.893 13.488 64.691 13.992 ;
     RECT  63.709 48.384 64.717 50.664 ;
     RECT  64.357 51.744 64.717 56.376 ;
     RECT  64.285 62.4 64.717 62.424 ;
     RECT  64.691 13.968 64.757 13.992 ;
     RECT  64.108 40.848 64.757 41.112 ;
     RECT  64.165 66.768 64.789 67.56 ;
     RECT  64.789 66.576 64.861 67.56 ;
     RECT  64.465 42.624 64.897 47.208 ;
     RECT  64.717 48.384 64.897 56.376 ;
     RECT  64.717 62.352 64.901 62.424 ;
     RECT  63.817 30.96 64.973 34.776 ;
     RECT  64.973 34.128 65.009 34.776 ;
     RECT  64.108 39.6 65.077 39.624 ;
     RECT  64.645 8.016 65.117 11.16 ;
     RECT  65.077 39.6 65.117 39.912 ;
     RECT  64.901 62.4 65.189 62.424 ;
     RECT  64.685 64.08 65.189 64.104 ;
     RECT  64.145 12.336 65.221 12.36 ;
     RECT  64.861 65.904 65.257 67.56 ;
     RECT  65.221 12.336 65.293 12.408 ;
     RECT  65.293 12.336 65.437 12.936 ;
     RECT  65.437 12.288 65.473 12.936 ;
     RECT  64.001 15.168 65.473 20.184 ;
     RECT  64.204 21.216 65.473 28.488 ;
     RECT  64.897 42.624 65.509 56.376 ;
     RECT  64.433 57.408 65.509 57.528 ;
     RECT  65.473 15.168 65.513 28.488 ;
     RECT  64.757 41.088 65.545 41.112 ;
     RECT  65.513 17.856 65.581 28.488 ;
     RECT  64.973 30.96 65.621 32.856 ;
     RECT  65.621 30.96 65.689 31.224 ;
     RECT  65.257 65.904 65.693 68.424 ;
     RECT  65.117 8.016 65.74 10.584 ;
     RECT  65.545 41.088 65.797 41.256 ;
     RECT  65.509 42.624 65.797 57.528 ;
     RECT  65.473 11.808 65.801 12.936 ;
     RECT  65.117 39.888 65.837 39.912 ;
     RECT  65.621 32.448 65.941 32.856 ;
     RECT  65.009 34.128 65.941 34.2 ;
     RECT  65.797 41.088 66.013 57.528 ;
     RECT  65.941 32.448 66.049 34.2 ;
     RECT  66.013 41.088 66.085 58.152 ;
     RECT  65.801 11.952 66.157 12.936 ;
     RECT  65.74 8.016 66.517 10.536 ;
     RECT  65.693 65.904 66.517 65.928 ;
     RECT  65.513 15.168 66.524 16.824 ;
     RECT  65.581 17.856 66.524 28.968 ;
     RECT  66.517 7.968 66.589 10.536 ;
     RECT  66.524 15.168 66.589 28.968 ;
     RECT  66.517 65.472 66.589 65.928 ;
     RECT  65.653 63.648 66.661 63.672 ;
     RECT  66.589 15.168 66.697 29.256 ;
     RECT  65.693 67.152 66.697 68.424 ;
     RECT  65.869 38.736 66.769 38.76 ;
     RECT  66.157 11.952 66.805 13.32 ;
     RECT  64.681 59.28 66.86 59.304 ;
     RECT  66.589 65.424 66.877 65.928 ;
     RECT  66.697 67.056 66.877 68.424 ;
     RECT  66.86 59.28 66.901 59.784 ;
     RECT  66.085 40.992 66.908 58.152 ;
     RECT  66.589 7.92 66.913 10.536 ;
     RECT  66.805 11.76 66.913 13.32 ;
     RECT  66.769 38.4 66.949 38.76 ;
     RECT  66.913 7.92 67.057 13.32 ;
     RECT  66.697 14.64 67.057 29.256 ;
     RECT  67.057 7.92 67.208 29.256 ;
     RECT  65.689 30.576 67.208 31.224 ;
     RECT  66.049 32.448 67.208 34.488 ;
     RECT  66.085 35.808 67.208 35.832 ;
     RECT  66.949 38.4 67.208 39.336 ;
     RECT  66.908 40.512 67.208 58.152 ;
     RECT  66.901 59.28 67.208 60.6 ;
     RECT  66.661 62.544 67.208 62.568 ;
     RECT  66.661 63.648 67.208 64.392 ;
     RECT  66.877 65.424 67.208 68.424 ;
     RECT  67.208 2.148 67.312 69.132 ;
     RECT  67.312 2.418 67.504 68.862 ;
     RECT  67.504 32.784 67.529 35.832 ;
     RECT  67.504 7.392 67.565 8.808 ;
     RECT  67.529 33.024 67.565 35.832 ;
     RECT  67.504 63.792 67.565 64.392 ;
     RECT  67.565 7.392 67.601 8.472 ;
     RECT  67.504 67.056 67.601 67.848 ;
     RECT  67.504 24.96 67.673 29.256 ;
     RECT  67.504 65.424 67.673 65.496 ;
     RECT  67.601 8.448 67.68 8.472 ;
     RECT  67.673 65.472 67.745 65.496 ;
     RECT  67.504 38.4 67.781 38.904 ;
     RECT  67.504 14.64 67.817 23.592 ;
     RECT  67.601 7.392 67.889 7.416 ;
     RECT  67.817 14.736 67.889 23.592 ;
     RECT  67.781 38.4 67.889 38.424 ;
     RECT  67.565 33.12 67.925 35.832 ;
     RECT  67.601 67.152 67.925 67.848 ;
     RECT  67.889 14.736 67.955 23.304 ;
     RECT  67.955 15.648 67.961 23.304 ;
     RECT  67.961 15.648 67.996 16.968 ;
     RECT  67.504 60.576 67.997 60.6 ;
     RECT  67.925 34.128 68.033 35.832 ;
     RECT  67.504 62.544 68.033 62.568 ;
     RECT  67.925 67.152 68.033 67.176 ;
     RECT  67.565 63.792 68.069 63.816 ;
     RECT  67.504 9.936 68.105 12.36 ;
     RECT  67.961 17.952 68.141 23.304 ;
     RECT  67.673 24.96 68.141 28.536 ;
     RECT  67.504 46.32 68.321 57.48 ;
     RECT  68.141 24.96 68.357 28.008 ;
     RECT  68.141 18.432 68.429 23.304 ;
     RECT  68.357 26.592 68.465 28.008 ;
     RECT  68.429 20.016 68.573 23.304 ;
     RECT  68.105 9.936 68.609 11.256 ;
     RECT  68.573 20.016 68.609 21.96 ;
     RECT  67.996 16.032 68.645 16.968 ;
     RECT  67.925 33.12 68.749 33.144 ;
     RECT  68.105 12.288 68.861 12.36 ;
     RECT  67.504 42.096 68.933 43.32 ;
     RECT  68.645 16.08 68.965 16.968 ;
     RECT  68.965 64.944 69.001 64.968 ;
     RECT  69.001 64.656 69.037 64.968 ;
     RECT  69.037 64.56 69.073 64.968 ;
     RECT  68.933 42.384 69.109 43.32 ;
     RECT  68.465 26.592 69.469 26.616 ;
     RECT  68.465 27.6 69.469 28.008 ;
     RECT  68.965 45.36 69.469 45.384 ;
     RECT  68.321 46.512 69.469 57.48 ;
     RECT  68.965 16.08 69.505 17.448 ;
     RECT  68.429 18.432 69.505 18.696 ;
     RECT  68.357 24.96 69.505 25.608 ;
     RECT  69.469 26.592 69.505 28.008 ;
     RECT  68.573 23.28 69.541 23.304 ;
     RECT  69.505 24.528 69.541 28.008 ;
     RECT  68.749 32.304 69.541 33.144 ;
     RECT  68.033 34.128 69.541 35.112 ;
     RECT  69.073 64.464 69.541 64.968 ;
     RECT  69.505 67.152 69.541 67.176 ;
     RECT  68.861 12.336 69.757 12.36 ;
     RECT  68.609 20.016 70.081 20.616 ;
     RECT  68.609 21.648 70.081 21.96 ;
     RECT  69.541 23.28 70.081 28.008 ;
     RECT  68.609 9.936 70.117 10.92 ;
     RECT  69.757 12.336 70.117 12.936 ;
     RECT  69.505 16.08 70.117 18.696 ;
     RECT  70.081 20.016 70.117 21.96 ;
     RECT  70.081 23.28 70.117 28.488 ;
     RECT  69.109 42.384 70.117 44.04 ;
     RECT  69.541 64.464 70.117 65.736 ;
     RECT  69.541 66.864 70.117 67.176 ;
     RECT  70.117 20.016 70.585 28.488 ;
     RECT  70.585 20.016 70.657 28.872 ;
     RECT  69.541 32.304 70.657 35.112 ;
     RECT  69.469 45.36 70.657 57.48 ;
     RECT  70.117 16.08 70.693 18.792 ;
     RECT  70.657 19.92 70.693 28.872 ;
     RECT  70.117 42.192 70.693 44.04 ;
     RECT  70.657 45.264 70.693 57.48 ;
     RECT  70.117 64.464 70.693 67.176 ;
     RECT  70.693 64.464 71.125 67.368 ;
     RECT  70.657 32.208 71.161 35.112 ;
     RECT  70.693 42.192 71.161 57.48 ;
     RECT  70.117 9.936 71.244 12.936 ;
     RECT  70.693 16.08 71.244 29.064 ;
     RECT  71.161 32.208 71.244 35.208 ;
     RECT  71.161 42.192 71.244 57.576 ;
     RECT  71.125 64.464 71.244 67.464 ;
     RECT  71.244 57.552 71.273 57.576 ;
    LAYER M5 ;
     RECT  35.28 0.016 35.592 0.131 ;
     RECT  39.12 0.016 51.336 0.133 ;
     RECT  35.376 0.131 35.592 0.227 ;
     RECT  0.72 0.016 25.992 1.811 ;
     RECT  35.472 0.227 35.592 1.811 ;
     RECT  29.4 2.137 29.52 2.151 ;
     RECT  56.4 2.137 56.52 2.151 ;
     RECT  61.8 2.137 61.92 2.151 ;
     RECT  67.2 2.137 67.32 2.151 ;
     RECT  39.12 0.133 51.432 2.245 ;
     RECT  38.592 2.245 51.432 2.387 ;
     RECT  38.592 2.387 51.312 2.485 ;
     RECT  0.72 1.811 25.896 2.579 ;
     RECT  36.432 2.725 36.456 3.589 ;
     RECT  38.16 2.485 51.312 3.685 ;
     RECT  0.72 2.579 25.272 3.733 ;
     RECT  36.432 3.589 36.984 4.261 ;
     RECT  36.432 4.261 37.032 4.595 ;
     RECT  34.8 2.137 35.112 5.077 ;
     RECT  36.96 4.595 37.032 5.077 ;
     RECT  38.064 3.685 51.312 5.077 ;
     RECT  36.96 5.077 51.312 5.653 ;
     RECT  34.8 5.077 35.208 6.229 ;
     RECT  36.768 5.653 51.312 6.229 ;
     RECT  0.72 3.733 25.704 6.323 ;
     RECT  0.72 6.323 25.272 6.565 ;
     RECT  34.8 6.229 51.312 7.043 ;
     RECT  0.192 6.565 25.272 7.045 ;
     RECT  26.976 6.229 27 7.235 ;
     RECT  34.8 7.043 49.08 7.381 ;
     RECT  52.848 6.277 52.872 7.381 ;
     RECT  67.2 2.151 67.512 7.381 ;
     RECT  52.848 7.381 53.016 7.427 ;
     RECT  34.224 7.381 49.08 7.667 ;
     RECT  34.224 7.667 48.6 8.003 ;
     RECT  34.224 8.003 48.264 8.147 ;
     RECT  34.8 8.147 48.264 8.195 ;
     RECT  67.2 7.381 67.608 8.483 ;
     RECT  34.8 8.195 37.032 8.579 ;
     RECT  34.8 8.579 36.936 9.155 ;
     RECT  38.112 8.195 48.264 9.155 ;
     RECT  52.992 7.427 53.016 9.155 ;
     RECT  27.888 8.005 27.912 9.491 ;
     RECT  61.8 2.151 62.112 9.637 ;
     RECT  50.112 7.043 51.312 9.925 ;
     RECT  38.112 9.155 48.168 10.307 ;
     RECT  61.8 9.637 62.76 10.355 ;
     RECT  34.8 9.155 36.792 10.501 ;
     RECT  38.112 10.307 46.872 10.501 ;
     RECT  65.664 9.637 65.688 10.595 ;
     RECT  49.536 9.925 51.312 10.883 ;
     RECT  0.144 7.045 25.272 10.979 ;
     RECT  0.288 10.979 25.272 11.459 ;
     RECT  34.8 10.501 46.872 11.459 ;
     RECT  48.144 10.307 48.168 11.459 ;
     RECT  58.368 10.597 58.392 11.701 ;
     RECT  58.368 11.701 58.68 11.747 ;
     RECT  67.2 8.483 67.512 11.941 ;
     RECT  0.288 11.459 24.504 12.229 ;
     RECT  58.656 11.747 58.68 12.419 ;
     RECT  48.816 11.797 48.84 12.421 ;
     RECT  34.8 11.459 46.248 12.853 ;
     RECT  48.816 12.421 49.032 12.853 ;
     RECT  34.8 12.853 46.296 13.045 ;
     RECT  63.264 11.701 63.288 13.091 ;
     RECT  0.144 12.229 24.504 13.139 ;
     RECT  25.488 12.517 25.512 13.139 ;
     RECT  34.8 13.045 46.44 13.285 ;
     RECT  47.712 11.653 47.832 13.285 ;
     RECT  34.8 13.285 47.832 13.331 ;
     RECT  66.528 11.941 67.512 13.331 ;
     RECT  48.816 12.853 49.368 13.573 ;
     RECT  0.144 13.139 24.312 13.715 ;
     RECT  50.4 10.883 51.312 13.763 ;
     RECT  0.144 13.715 22.632 13.811 ;
     RECT  57.744 13.045 58.392 14.147 ;
     RECT  61.8 10.355 62.112 14.197 ;
     RECT  48.432 13.573 49.368 14.533 ;
     RECT  34.8 13.331 47.256 14.677 ;
     RECT  48.24 14.533 49.368 14.677 ;
     RECT  67.2 13.331 67.512 14.725 ;
     RECT  61.8 14.197 62.952 14.773 ;
     RECT  57.744 14.147 57.768 14.867 ;
     RECT  34.8 14.677 49.368 15.061 ;
     RECT  50.592 13.763 51.312 15.061 ;
     RECT  23.616 13.715 24.312 15.109 ;
     RECT  23.616 15.109 24.648 15.443 ;
     RECT  0.192 13.811 22.632 15.493 ;
     RECT  23.616 15.443 24.504 15.493 ;
     RECT  60.816 14.773 62.952 15.539 ;
     RECT  67.2 14.725 67.944 15.683 ;
     RECT  29.4 2.151 29.712 15.733 ;
     RECT  29.4 15.733 30.84 15.875 ;
     RECT  59.76 14.917 59.784 15.971 ;
     RECT  57.696 14.917 57.72 16.067 ;
     RECT  60.816 15.539 62.856 16.259 ;
     RECT  54.24 15.973 54.264 16.307 ;
     RECT  29.4 15.875 29.928 16.355 ;
     RECT  0.192 15.493 24.504 16.403 ;
     RECT  29.4 16.355 29.832 16.451 ;
     RECT  2.016 16.403 24.504 16.549 ;
     RECT  34.8 15.061 51.312 16.595 ;
     RECT  61.8 16.259 62.856 16.595 ;
     RECT  43.152 16.595 51.312 16.741 ;
     RECT  43.152 16.741 52.008 16.981 ;
     RECT  2.016 16.549 24.6 17.029 ;
     RECT  67.2 15.683 67.512 17.077 ;
     RECT  34.8 16.595 42.168 17.219 ;
     RECT  37.056 17.219 42.168 17.315 ;
     RECT  0.192 16.403 0.984 17.413 ;
     RECT  61.8 16.595 62.112 17.653 ;
     RECT  2.016 17.029 25.32 17.699 ;
     RECT  37.2 17.315 42.168 17.699 ;
     RECT  66.576 17.077 67.512 17.893 ;
     RECT  0.144 17.413 0.984 17.989 ;
     RECT  66.576 17.893 67.704 18.179 ;
     RECT  60.72 17.077 60.744 18.419 ;
     RECT  0.144 17.989 1.128 18.661 ;
     RECT  37.2 17.699 42.12 18.709 ;
     RECT  43.152 16.981 52.296 18.709 ;
     RECT  37.2 18.709 52.296 18.851 ;
     RECT  64.656 10.501 64.68 18.947 ;
     RECT  58.656 16.405 58.68 19.091 ;
     RECT  67.2 18.179 67.704 19.139 ;
     RECT  61.8 17.653 62.808 19.475 ;
     RECT  37.2 18.851 51.96 19.477 ;
     RECT  56.4 2.151 56.712 19.621 ;
     RECT  29.4 16.451 29.712 19.669 ;
     RECT  34.8 17.219 35.592 19.765 ;
     RECT  37.056 19.477 51.96 19.765 ;
     RECT  26.496 18.133 26.52 19.811 ;
     RECT  0.144 18.661 1.176 20.003 ;
     RECT  61.8 19.475 62.616 20.003 ;
     RECT  34.8 19.765 51.96 20.053 ;
     RECT  29.4 19.669 29.832 20.387 ;
     RECT  61.8 20.003 62.472 20.725 ;
     RECT  34.704 20.053 51.96 21.157 ;
     RECT  34.704 21.157 52.392 21.299 ;
     RECT  52.368 21.299 52.392 21.443 ;
     RECT  34.704 21.299 51.312 21.635 ;
     RECT  61.488 20.725 62.472 21.683 ;
     RECT  66.096 21.109 66.12 22.163 ;
     RECT  56.4 19.621 57 22.597 ;
     RECT  61.8 21.683 62.472 22.739 ;
     RECT  33.456 22.165 33.48 22.741 ;
     RECT  67.2 19.139 67.512 22.741 ;
     RECT  2.256 17.699 25.32 22.787 ;
     RECT  34.8 21.635 51.312 23.269 ;
     RECT  64.272 22.741 64.296 23.363 ;
     RECT  67.2 22.741 67.8 23.411 ;
     RECT  0.144 20.003 1.128 23.651 ;
     RECT  32.256 23.845 32.28 23.893 ;
     RECT  33.264 22.741 33.48 23.893 ;
     RECT  0.144 23.651 1.032 23.987 ;
     RECT  34.704 23.269 51.312 24.035 ;
     RECT  56.4 22.597 57.288 24.227 ;
     RECT  0.144 23.987 0.984 24.467 ;
     RECT  32.256 23.893 33.48 24.469 ;
     RECT  0.144 24.467 0.84 24.659 ;
     RECT  67.2 23.411 67.512 24.901 ;
     RECT  2.256 22.787 22.488 25.045 ;
     RECT  23.472 22.787 25.32 25.045 ;
     RECT  31.824 24.469 33.48 25.045 ;
     RECT  34.8 24.035 51.312 25.045 ;
     RECT  0.144 24.659 0.6 25.139 ;
     RECT  27.312 25.045 27.336 25.187 ;
     RECT  31.824 25.045 51.312 25.187 ;
     RECT  66.672 24.901 67.512 25.187 ;
     RECT  26.304 21.061 26.328 25.621 ;
     RECT  0.144 25.139 0.552 26.147 ;
     RECT  53.568 25.717 53.592 26.149 ;
     RECT  64.944 25.621 64.968 26.197 ;
     RECT  63.84 23.893 63.864 26.243 ;
     RECT  32.016 25.187 51.312 26.389 ;
     RECT  56.4 24.227 56.712 26.437 ;
     RECT  53.52 26.149 53.592 26.483 ;
     RECT  59.616 22.741 59.64 26.677 ;
     RECT  67.2 25.187 67.512 26.773 ;
     RECT  31.728 26.389 51.312 26.867 ;
     RECT  66.72 26.773 67.512 26.963 ;
     RECT  59.616 26.677 59.976 27.157 ;
     RECT  61.8 22.739 62.112 27.157 ;
     RECT  0.144 26.147 0.504 27.253 ;
     RECT  31.728 26.867 48.552 27.395 ;
     RECT  32.016 27.395 48.456 27.443 ;
     RECT  49.536 26.867 51.312 27.443 ;
     RECT  61.68 27.157 62.112 27.589 ;
     RECT  58.704 27.157 59.976 27.635 ;
     RECT  64.944 26.197 65.208 27.635 ;
     RECT  59.952 27.635 59.976 27.875 ;
     RECT  65.184 27.635 65.208 27.923 ;
     RECT  48.144 27.443 48.456 28.019 ;
     RECT  53.52 26.483 53.544 28.163 ;
     RECT  56.304 26.437 56.712 28.259 ;
     RECT  2.256 25.045 25.32 28.405 ;
     RECT  58.704 27.635 58.728 28.451 ;
     RECT  32.016 27.443 47.064 28.837 ;
     RECT  64.128 27.877 64.152 28.931 ;
     RECT  48.336 28.019 48.456 29.123 ;
     RECT  49.536 27.443 49.896 29.123 ;
     RECT  29.4 20.387 29.712 29.221 ;
     RECT  31.344 28.837 47.064 29.221 ;
     RECT  0.144 27.253 0.552 29.267 ;
     RECT  49.584 29.123 49.896 29.267 ;
     RECT  0.144 29.267 0.456 29.315 ;
     RECT  26.304 25.621 26.856 29.699 ;
     RECT  26.304 29.699 26.808 30.035 ;
     RECT  2.208 28.405 25.32 30.181 ;
     RECT  26.304 30.035 26.328 30.181 ;
     RECT  49.776 29.267 49.896 30.275 ;
     RECT  0.144 29.315 0.408 30.613 ;
     RECT  51 27.443 51.312 30.613 ;
     RECT  29.4 29.221 47.064 30.757 ;
     RECT  48.432 29.123 48.456 30.757 ;
     RECT  49.872 30.275 49.896 30.757 ;
     RECT  50.88 30.613 51.312 30.757 ;
     RECT  0.144 30.613 0.504 30.997 ;
     RECT  2.208 30.181 26.328 31.139 ;
     RECT  49.872 30.757 51.312 31.139 ;
     RECT  0.144 30.997 0.552 31.667 ;
     RECT  29.4 30.757 48.456 31.667 ;
     RECT  0.144 31.667 0.504 31.955 ;
     RECT  31.488 31.667 48.456 31.955 ;
     RECT  67.2 26.963 67.512 32.437 ;
     RECT  0.144 31.955 0.456 32.531 ;
     RECT  31.488 31.955 31.512 32.531 ;
     RECT  49.872 31.139 49.896 32.531 ;
     RECT  2.208 31.139 25.32 33.107 ;
     RECT  32.976 31.955 48.456 33.107 ;
     RECT  66.72 32.437 67.512 33.107 ;
     RECT  61.536 27.589 62.112 33.301 ;
     RECT  32.976 33.107 47.208 33.539 ;
     RECT  63.408 32.869 63.432 33.541 ;
     RECT  0.144 32.531 0.408 33.587 ;
     RECT  55.296 29.797 55.32 33.587 ;
     RECT  63.408 33.541 63.816 33.587 ;
     RECT  0.144 33.587 0.312 33.683 ;
     RECT  33.12 33.539 47.208 33.683 ;
     RECT  58.128 31.477 58.152 33.827 ;
     RECT  60.672 33.301 62.112 34.067 ;
     RECT  33.12 33.683 46.728 34.259 ;
     RECT  29.4 31.667 29.712 34.501 ;
     RECT  48.432 33.107 48.456 34.693 ;
     RECT  56.4 28.259 56.712 34.741 ;
     RECT  63.792 33.587 63.816 34.741 ;
     RECT  63.408 34.741 63.816 34.787 ;
     RECT  0.192 33.683 0.312 34.933 ;
     RECT  29.4 34.501 30.216 35.077 ;
     RECT  29.4 35.077 31.128 35.269 ;
     RECT  63.408 34.787 63.432 35.363 ;
     RECT  29.04 35.269 31.128 35.413 ;
     RECT  56.4 34.741 56.808 35.459 ;
     RECT  29.04 35.413 31.848 35.605 ;
     RECT  33.12 34.259 46.488 35.605 ;
     RECT  47.76 34.693 48.456 35.605 ;
     RECT  0.192 34.933 0.36 35.939 ;
     RECT  61.536 34.067 62.112 36.275 ;
     RECT  0.336 35.939 0.36 36.901 ;
     RECT  0.144 36.901 0.36 37.525 ;
     RECT  49.632 34.117 49.656 37.667 ;
     RECT  2.304 33.107 25.32 37.715 ;
     RECT  54.48 35.509 54.504 37.907 ;
     RECT  0.144 37.525 0.552 38.725 ;
     RECT  2.304 37.715 25.272 38.867 ;
     RECT  51 31.139 51.312 39.109 ;
     RECT  2.304 38.867 14.712 39.301 ;
     RECT  67.2 33.107 67.512 39.301 ;
     RECT  53.472 38.581 53.496 39.589 ;
     RECT  0.144 38.725 0.6 39.635 ;
     RECT  53.04 39.589 53.496 39.635 ;
     RECT  29.04 35.605 48.456 39.731 ;
     RECT  26.304 31.139 26.328 39.877 ;
     RECT  29.28 39.731 48.456 39.877 ;
     RECT  57.792 38.725 57.816 39.923 ;
     RECT  66.96 39.301 67.512 40.547 ;
     RECT  29.28 39.877 49.416 40.643 ;
     RECT  2.256 39.301 14.712 40.693 ;
     RECT  16.08 38.867 25.272 40.693 ;
     RECT  29.28 40.643 49.224 40.741 ;
     RECT  51 39.109 51.768 40.741 ;
     RECT  26.256 39.877 26.328 40.835 ;
     RECT  56.4 35.459 56.712 40.837 ;
     RECT  61.8 36.275 62.112 40.837 ;
     RECT  50.736 40.741 51.768 40.883 ;
     RECT  64.032 39.877 64.056 40.883 ;
     RECT  28.368 40.741 49.224 41.075 ;
     RECT  0.144 39.635 0.552 41.509 ;
     RECT  28.368 41.075 47.304 41.557 ;
     RECT  27.696 41.557 47.304 41.651 ;
     RECT  51 40.883 51.768 41.651 ;
     RECT  2.256 40.693 25.272 41.699 ;
     RECT  0.144 41.509 0.6 41.749 ;
     RECT  67.104 40.547 67.512 42.181 ;
     RECT  2.304 41.699 25.272 42.227 ;
     RECT  27.696 41.651 46.104 42.227 ;
     RECT  67.104 42.181 67.992 42.227 ;
     RECT  59.328 41.413 59.352 42.229 ;
     RECT  53.04 39.635 53.064 42.275 ;
     RECT  58.704 42.229 59.352 42.275 ;
     RECT  0.144 41.749 0.744 42.421 ;
     RECT  58.704 42.275 58.92 42.515 ;
     RECT  61.8 40.837 62.232 42.707 ;
     RECT  67.2 42.227 67.992 42.755 ;
     RECT  45.312 42.227 46.104 42.757 ;
     RECT  58.896 42.515 58.92 42.803 ;
     RECT  64.704 42.613 64.728 42.803 ;
     RECT  45.312 42.757 46.776 42.851 ;
     RECT  16.08 42.227 25.272 43.285 ;
     RECT  45.408 42.851 46.776 43.477 ;
     RECT  45.408 43.477 47.304 43.763 ;
     RECT  47.28 43.763 47.304 43.861 ;
     RECT  48.432 41.075 49.224 43.861 ;
     RECT  47.28 43.861 49.224 44.099 ;
     RECT  63.552 41.557 63.576 44.389 ;
     RECT  45.408 43.763 46.104 44.483 ;
     RECT  15.696 43.285 25.272 44.627 ;
     RECT  63.552 44.389 64.44 44.723 ;
     RECT  63.552 44.723 63.576 44.725 ;
     RECT  63.408 44.725 63.576 44.771 ;
     RECT  63.408 44.771 63.528 44.867 ;
     RECT  0.144 42.421 0.84 45.251 ;
     RECT  45.6 44.483 46.104 45.541 ;
     RECT  56.4 40.837 57 45.733 ;
     RECT  0.144 45.251 0.552 45.779 ;
     RECT  45.6 45.541 46.2 46.021 ;
     RECT  47.856 44.099 49.224 46.211 ;
     RECT  45.6 46.021 46.728 46.453 ;
     RECT  51 41.651 51.312 46.645 ;
     RECT  45.6 46.453 47.112 46.787 ;
     RECT  26.304 40.835 26.328 47.125 ;
     RECT  27.696 42.227 44.328 47.125 ;
     RECT  56.4 45.733 57.432 47.317 ;
     RECT  0.144 45.779 0.504 47.507 ;
     RECT  16.08 44.627 25.272 47.557 ;
     RECT  26.304 47.125 44.328 47.557 ;
     RECT  2.304 42.227 14.52 47.797 ;
     RECT  16.08 47.557 44.328 47.797 ;
     RECT  2.304 47.797 44.328 47.893 ;
     RECT  45.6 46.787 46.632 47.893 ;
     RECT  48.432 46.211 49.224 47.939 ;
     RECT  56.064 47.317 57.432 48.371 ;
     RECT  56.4 48.371 57.432 48.421 ;
     RECT  49.2 47.939 49.224 48.611 ;
     RECT  2.304 47.893 46.632 48.659 ;
     RECT  0.144 47.507 0.408 48.707 ;
     RECT  47.712 48.661 47.736 48.899 ;
     RECT  59.424 47.269 59.448 48.899 ;
     RECT  63.504 44.867 63.528 48.901 ;
     RECT  67.2 42.755 67.512 48.901 ;
     RECT  63.504 48.901 63.816 48.947 ;
     RECT  68.976 48.997 69 49.187 ;
     RECT  71.088 48.997 71.112 49.187 ;
     RECT  26.304 48.659 46.632 49.381 ;
     RECT  26.304 49.381 46.728 49.477 ;
     RECT  61.8 42.707 62.112 49.573 ;
     RECT  63.792 48.947 63.816 49.619 ;
     RECT  2.304 48.659 25.272 49.861 ;
     RECT  1.968 49.861 25.272 50.005 ;
     RECT  26.304 49.477 47.352 50.005 ;
     RECT  56.4 48.421 57.528 50.245 ;
     RECT  0.144 48.707 0.36 50.389 ;
     RECT  1.968 50.005 47.352 50.531 ;
     RECT  61.44 49.573 62.112 50.531 ;
     RECT  50.736 46.645 51.312 50.627 ;
     RECT  66.96 48.901 67.512 50.771 ;
     RECT  0.144 50.389 0.456 50.773 ;
     RECT  1.968 50.531 46.968 51.541 ;
     RECT  1.728 51.541 46.968 51.683 ;
     RECT  56.4 50.245 58.488 51.877 ;
     RECT  67.008 50.771 67.512 51.971 ;
     RECT  61.488 50.531 62.112 52.405 ;
     RECT  1.824 51.683 46.968 52.453 ;
     RECT  50.832 50.627 51.312 52.499 ;
     RECT  56.4 51.877 59.112 52.499 ;
     RECT  0.144 50.773 0.552 52.933 ;
     RECT  63.264 52.405 63.288 53.075 ;
     RECT  55.248 51.637 55.272 53.219 ;
     RECT  56.4 52.499 58.44 53.365 ;
     RECT  1.824 52.453 47.88 53.603 ;
     RECT  47.856 53.603 47.88 53.699 ;
     RECT  60.96 52.405 62.112 54.035 ;
     RECT  49.584 52.549 49.608 54.179 ;
     RECT  55.968 53.365 58.44 54.179 ;
     RECT  0.144 52.933 0.6 54.611 ;
     RECT  61.8 54.035 62.112 54.613 ;
     RECT  67.2 51.971 67.512 54.661 ;
     RECT  55.968 54.179 56.712 54.755 ;
     RECT  65.952 53.557 65.976 54.755 ;
     RECT  1.824 53.603 46.2 55.045 ;
     RECT  58.416 54.179 58.44 55.141 ;
     RECT  64.272 54.085 64.296 55.283 ;
     RECT  48.96 54.661 48.984 55.715 ;
     RECT  1.824 55.045 46.488 55.813 ;
     RECT  67.2 54.661 68.088 55.813 ;
     RECT  58.368 55.141 58.44 56.003 ;
     RECT  60.432 55.957 60.456 56.099 ;
     RECT  51 52.499 51.312 56.101 ;
     RECT  1.824 55.813 46.728 56.533 ;
     RECT  47.856 55.573 47.88 56.533 ;
     RECT  66.72 55.813 68.088 56.723 ;
     RECT  61.8 54.613 62.232 56.869 ;
     RECT  61.68 56.869 62.232 56.915 ;
     RECT  1.824 56.533 47.88 56.917 ;
     RECT  48.864 56.389 48.888 56.917 ;
     RECT  59.856 56.677 59.88 57.253 ;
     RECT  58.368 56.003 58.392 57.299 ;
     RECT  59.472 57.253 59.88 57.299 ;
     RECT  50.544 56.101 51.312 57.397 ;
     RECT  1.824 56.917 48.888 57.443 ;
     RECT  0.144 54.611 0.552 57.683 ;
     RECT  59.472 57.299 59.496 58.163 ;
     RECT  61.68 56.915 62.112 58.693 ;
     RECT  56.4 54.755 56.712 59.605 ;
     RECT  61.392 58.693 62.112 59.747 ;
     RECT  1.824 57.443 48.6 59.795 ;
     RECT  49.872 57.397 51.312 59.797 ;
     RECT  49.584 59.797 51.312 59.843 ;
     RECT  50.688 59.843 51.312 59.939 ;
     RECT  50.832 59.939 51.312 60.035 ;
     RECT  0.144 57.683 0.504 60.085 ;
     RECT  1.824 59.795 48.456 60.085 ;
     RECT  0.144 60.085 48.456 60.515 ;
     RECT  55.392 56.245 55.416 60.853 ;
     RECT  56.4 59.605 57.384 60.853 ;
     RECT  55.392 60.853 57.384 61.475 ;
     RECT  49.584 59.843 49.704 62.435 ;
     RECT  51 60.035 51.312 62.437 ;
     RECT  50.736 62.437 51.312 62.579 ;
     RECT  0.144 60.515 47.544 62.677 ;
     RECT  0.144 62.677 48.504 62.819 ;
     RECT  55.392 61.475 56.712 62.819 ;
     RECT  55.392 62.819 55.416 63.061 ;
     RECT  55.296 63.061 55.416 63.347 ;
     RECT  0.192 62.819 48.504 63.395 ;
     RECT  54.096 62.101 54.12 63.635 ;
     RECT  63.936 62.629 63.96 63.779 ;
     RECT  51 62.579 51.312 63.829 ;
     RECT  0.288 63.395 48.504 64.019 ;
     RECT  0.288 64.019 47.928 64.451 ;
     RECT  49.68 62.435 49.704 64.643 ;
     RECT  52.992 63.301 53.016 65.027 ;
     RECT  50.88 63.829 51.312 65.221 ;
     RECT  66.72 56.723 67.512 65.893 ;
     RECT  63.6 64.357 63.624 65.939 ;
     RECT  0.912 64.451 47.928 65.941 ;
     RECT  50.784 65.221 51.312 65.941 ;
     RECT  61.8 59.747 62.112 66.229 ;
     RECT  50.688 65.941 51.312 66.325 ;
     RECT  49.824 66.325 51.312 66.371 ;
     RECT  56.4 62.819 56.712 66.469 ;
     RECT  59.184 66.565 59.208 66.613 ;
     RECT  61.8 66.229 63 66.707 ;
     RECT  66.096 65.893 67.512 67.187 ;
     RECT  0.816 65.941 47.928 67.189 ;
     RECT  56.4 66.469 57.24 67.283 ;
     RECT  59.184 66.613 59.448 67.283 ;
     RECT  53.04 66.565 53.064 67.331 ;
     RECT  59.184 67.283 59.208 67.331 ;
     RECT  55.296 63.347 55.32 67.379 ;
     RECT  64.176 66.757 64.2 67.523 ;
     RECT  66.72 67.187 67.512 67.571 ;
     RECT  53.952 67.333 53.976 67.811 ;
     RECT  49.824 66.371 49.848 67.907 ;
     RECT  0.816 67.189 48.024 68.099 ;
     RECT  0.816 68.099 47.352 68.245 ;
     RECT  0.72 68.245 47.352 68.387 ;
     RECT  0.72 68.387 46.824 68.435 ;
     RECT  0.72 68.435 43.32 68.531 ;
     RECT  44.448 68.435 46.824 68.579 ;
     RECT  43.2 68.531 43.32 68.627 ;
     RECT  45.408 68.579 46.824 68.675 ;
     RECT  43.2 68.627 43.224 68.915 ;
     RECT  45.6 68.675 45.912 69.129 ;
     RECT  51 66.371 51.312 69.129 ;
     RECT  56.4 67.283 56.712 69.129 ;
     RECT  61.8 66.707 62.112 69.129 ;
     RECT  67.2 67.571 67.512 69.129 ;
     RECT  0.72 68.531 42.168 69.143 ;
     RECT  45.6 69.129 45.72 69.143 ;
     RECT  51 69.129 51.12 69.143 ;
     RECT  56.4 69.129 56.52 69.143 ;
     RECT  61.8 69.129 61.92 69.143 ;
     RECT  67.2 69.129 67.32 69.143 ;
     RECT  40.464 69.143 42.168 71.075 ;
     RECT  0.72 69.143 39.288 71.123 ;
     RECT  0.72 71.123 39.144 71.171 ;
     RECT  0.72 71.171 39.048 71.248 ;
     RECT  40.464 71.075 42.12 71.248 ;
     RECT  35.472 1.811 35.592 2.137 ;
     RECT  35.112 2.137 35.592 2.725 ;
     RECT  25.272 2.579 25.704 3.733 ;
     RECT  35.112 2.725 36.432 4.595 ;
     RECT  36.984 3.589 38.16 3.685 ;
     RECT  36.984 3.685 38.064 4.261 ;
     RECT  37.032 4.261 38.064 5.077 ;
     RECT  35.112 4.595 35.208 5.077 ;
     RECT  36.768 4.595 36.96 5.653 ;
     RECT  25.704 6.229 26.976 6.323 ;
     RECT  49.08 7.043 50.112 7.667 ;
     RECT  48.6 7.667 50.112 8.003 ;
     RECT  27.912 8.005 29.4 9.491 ;
     RECT  37.032 8.195 38.112 8.579 ;
     RECT  36.936 8.579 38.112 9.155 ;
     RECT  36.792 9.155 38.112 10.501 ;
     RECT  48.168 9.155 48.264 9.925 ;
     RECT  65.688 9.637 67.2 10.595 ;
     RECT  48.168 9.925 49.536 10.883 ;
     RECT  46.872 10.307 48.144 11.459 ;
     RECT  62.112 10.355 62.76 11.701 ;
     RECT  64.68 10.501 65.664 10.595 ;
     RECT  66.528 10.595 67.2 11.941 ;
     RECT  48.168 10.883 48.84 11.459 ;
     RECT  0.144 10.979 0.288 12.229 ;
     RECT  24.504 11.459 25.272 12.517 ;
     RECT  46.248 11.459 48.84 11.653 ;
     RECT  46.248 11.653 47.712 12.853 ;
     RECT  47.832 11.653 48.84 11.797 ;
     RECT  62.112 11.701 63.264 13.091 ;
     RECT  63.288 11.701 64.656 13.091 ;
     RECT  58.368 11.747 58.656 12.419 ;
     RECT  47.832 11.797 48.816 13.331 ;
     RECT  58.368 12.419 58.392 13.045 ;
     RECT  49.032 12.421 50.4 12.853 ;
     RECT  24.504 12.517 25.488 13.139 ;
     RECT  46.296 12.853 47.712 13.045 ;
     RECT  49.368 12.853 50.4 13.763 ;
     RECT  46.44 13.045 47.712 13.285 ;
     RECT  56.712 13.045 57.744 14.867 ;
     RECT  62.112 13.091 62.952 14.197 ;
     RECT  47.256 13.331 48.816 13.573 ;
     RECT  47.256 13.573 48.432 14.533 ;
     RECT  22.632 13.715 23.616 15.493 ;
     RECT  49.368 13.763 50.592 15.061 ;
     RECT  47.256 14.533 48.24 14.677 ;
     RECT  56.712 14.867 57.72 14.917 ;
     RECT  56.712 14.917 57.696 16.067 ;
     RECT  59.784 14.917 60.816 15.971 ;
     RECT  24.504 15.443 24.6 16.549 ;
     RECT  60.72 15.971 60.816 16.259 ;
     RECT  60.72 16.259 61.8 17.077 ;
     RECT  0.984 16.403 2.016 17.699 ;
     RECT  42.168 16.595 43.152 17.699 ;
     RECT  62.112 16.595 62.808 17.653 ;
     RECT  60.744 17.077 61.8 18.419 ;
     RECT  35.592 17.219 37.056 17.315 ;
     RECT  0.984 17.699 2.256 17.989 ;
     RECT  42.12 17.699 43.152 18.709 ;
     RECT  1.128 17.989 2.256 18.661 ;
     RECT  25.32 18.133 26.496 19.811 ;
     RECT  1.176 18.661 2.256 20.003 ;
     RECT  35.592 19.477 37.056 19.765 ;
     RECT  25.32 19.811 26.328 21.061 ;
     RECT  1.128 20.003 2.256 23.651 ;
     RECT  25.32 21.061 26.304 30.181 ;
     RECT  66.12 21.109 67.2 22.163 ;
     RECT  51.312 21.299 52.368 21.443 ;
     RECT  34.704 21.635 34.8 22.165 ;
     RECT  33.48 22.165 34.8 23.269 ;
     RECT  22.488 22.787 23.472 25.045 ;
     RECT  33.48 23.269 34.704 24.035 ;
     RECT  1.032 23.651 2.256 23.987 ;
     RECT  32.28 23.845 33.264 23.893 ;
     RECT  0.984 23.987 2.256 24.467 ;
     RECT  33.48 24.035 34.8 25.045 ;
     RECT  0.84 24.467 2.256 24.659 ;
     RECT  26.328 25.045 27.312 25.187 ;
     RECT  26.328 25.187 26.856 25.621 ;
     RECT  31.824 25.187 32.016 26.389 ;
     RECT  63.864 25.621 64.944 26.243 ;
     RECT  0.504 26.147 0.552 27.253 ;
     RECT  65.208 26.773 66.72 26.963 ;
     RECT  48.552 26.867 49.536 27.395 ;
     RECT  31.728 27.395 32.016 28.837 ;
     RECT  48.456 27.395 49.536 29.123 ;
     RECT  47.064 27.443 48.144 28.019 ;
     RECT  49.896 27.443 51 30.613 ;
     RECT  58.728 27.635 59.952 27.875 ;
     RECT  64.944 27.635 65.184 27.877 ;
     RECT  64.152 27.877 65.184 27.923 ;
     RECT  47.064 28.019 48.336 29.123 ;
     RECT  47.064 29.123 48.432 30.757 ;
     RECT  48.456 29.123 49.584 29.267 ;
     RECT  0.456 29.267 0.504 29.315 ;
     RECT  48.456 29.267 49.776 30.275 ;
     RECT  0.408 29.315 0.504 30.613 ;
     RECT  55.32 29.797 56.4 33.587 ;
     RECT  48.456 30.275 49.872 32.531 ;
     RECT  49.896 30.613 50.88 30.757 ;
     RECT  25.32 31.139 26.304 37.715 ;
     RECT  49.896 31.139 51 32.531 ;
     RECT  56.712 31.477 58.128 33.827 ;
     RECT  31.512 31.955 32.976 32.531 ;
     RECT  62.112 32.869 63.408 33.587 ;
     RECT  47.208 33.107 48.432 33.683 ;
     RECT  0.312 33.587 0.36 34.933 ;
     RECT  62.112 33.587 63.792 34.741 ;
     RECT  46.728 33.683 48.432 34.259 ;
     RECT  56.712 33.827 56.808 34.741 ;
     RECT  48.456 34.117 49.632 37.667 ;
     RECT  49.656 34.117 51 37.667 ;
     RECT  46.488 34.259 48.432 34.693 ;
     RECT  46.488 34.693 47.76 35.605 ;
     RECT  62.112 34.741 63.408 35.363 ;
     RECT  31.848 35.413 33.12 35.605 ;
     RECT  0.192 35.939 0.336 36.901 ;
     RECT  25.272 37.715 26.304 39.877 ;
     RECT  56.712 38.725 57.792 39.923 ;
     RECT  14.712 38.867 16.08 40.693 ;
     RECT  51.768 39.589 53.04 41.651 ;
     RECT  29.04 39.731 29.28 40.741 ;
     RECT  25.272 39.877 26.256 40.835 ;
     RECT  56.712 39.923 57 40.837 ;
     RECT  49.224 40.643 49.416 40.741 ;
     RECT  49.224 40.741 50.736 40.883 ;
     RECT  25.272 40.835 26.304 47.557 ;
     RECT  47.304 41.075 48.432 41.651 ;
     RECT  26.328 41.557 27.696 47.125 ;
     RECT  62.232 41.557 63.552 42.707 ;
     RECT  46.104 41.651 46.776 42.757 ;
     RECT  2.256 41.699 2.304 41.749 ;
     RECT  0.744 41.749 2.304 42.421 ;
     RECT  14.52 42.227 16.08 43.285 ;
     RECT  44.328 42.227 45.312 42.851 ;
     RECT  0.84 42.421 2.304 45.251 ;
     RECT  63.576 42.613 64.704 42.803 ;
     RECT  62.112 42.707 63.552 44.725 ;
     RECT  44.328 42.851 45.408 44.483 ;
     RECT  14.52 43.285 15.696 44.627 ;
     RECT  47.304 43.477 48.432 43.861 ;
     RECT  46.104 43.763 47.28 44.099 ;
     RECT  46.104 44.099 46.2 45.541 ;
     RECT  44.328 44.483 45.6 47.893 ;
     RECT  62.112 44.725 63.408 44.867 ;
     RECT  62.112 44.867 63.504 48.947 ;
     RECT  46.728 46.021 47.856 46.211 ;
     RECT  46.728 46.211 48.432 46.453 ;
     RECT  47.112 46.453 48.432 46.787 ;
     RECT  49.224 46.645 50.736 48.611 ;
     RECT  25.272 48.659 26.304 50.005 ;
     RECT  46.632 48.661 47.712 48.899 ;
     RECT  46.632 48.899 47.352 49.381 ;
     RECT  67.512 48.997 68.976 49.187 ;
     RECT  46.728 49.381 47.352 49.477 ;
     RECT  0.456 50.389 1.968 50.773 ;
     RECT  0.552 50.773 1.968 51.541 ;
     RECT  0.552 51.541 1.728 51.683 ;
     RECT  55.272 51.637 56.4 53.219 ;
     RECT  0.552 51.683 1.824 52.933 ;
     RECT  62.112 52.405 63.264 53.075 ;
     RECT  50.832 52.499 51 52.549 ;
     RECT  49.608 52.549 51 54.179 ;
     RECT  0.6 52.933 1.824 54.611 ;
     RECT  55.968 53.219 56.4 53.365 ;
     RECT  65.976 53.557 67.2 54.755 ;
     RECT  46.2 53.603 47.856 53.699 ;
     RECT  46.2 53.699 46.488 55.045 ;
     RECT  58.368 54.179 58.416 55.141 ;
     RECT  0.552 54.611 1.824 57.683 ;
     RECT  55.968 54.755 56.4 56.245 ;
     RECT  66.72 54.755 67.2 55.813 ;
     RECT  46.488 55.573 47.856 55.813 ;
     RECT  47.88 55.573 48.96 55.715 ;
     RECT  47.88 55.715 48.888 56.389 ;
     RECT  46.728 55.813 47.856 56.533 ;
     RECT  60.456 55.957 61.8 56.099 ;
     RECT  58.392 56.003 58.44 56.677 ;
     RECT  61.68 56.099 61.8 56.869 ;
     RECT  55.416 56.245 56.4 60.853 ;
     RECT  47.88 56.389 48.864 56.917 ;
     RECT  58.392 56.677 59.856 57.253 ;
     RECT  58.392 57.253 59.472 57.299 ;
     RECT  48.888 57.397 49.872 57.443 ;
     RECT  48.6 57.443 49.872 59.795 ;
     RECT  0.504 57.683 1.824 60.085 ;
     RECT  48.456 59.795 49.872 59.797 ;
     RECT  48.456 59.797 49.584 60.515 ;
     RECT  49.704 59.843 50.688 59.939 ;
     RECT  49.704 59.939 50.832 60.035 ;
     RECT  49.704 60.035 51 62.437 ;
     RECT  54.12 62.101 55.392 63.061 ;
     RECT  49.584 62.435 49.68 62.677 ;
     RECT  49.704 62.437 50.736 62.579 ;
     RECT  49.704 62.579 51 63.829 ;
     RECT  48.504 62.677 49.68 64.019 ;
     RECT  55.416 62.819 56.4 63.347 ;
     RECT  54.12 63.061 55.296 63.635 ;
     RECT  53.016 63.301 54.096 63.635 ;
     RECT  55.32 63.347 56.4 67.379 ;
     RECT  49.704 63.829 50.88 64.643 ;
     RECT  62.112 64.357 63.6 65.939 ;
     RECT  0.816 64.451 0.912 65.941 ;
     RECT  50.688 64.643 50.88 65.221 ;
     RECT  50.688 65.221 50.784 65.941 ;
     RECT  62.112 65.939 63 66.229 ;
     RECT  49.848 66.371 51 67.907 ;
     RECT  53.976 67.333 55.296 67.379 ;
     RECT  43.32 68.435 44.448 68.579 ;
     RECT  42.168 68.531 43.2 68.915 ;
     RECT  39.288 69.143 40.464 71.123 ;
     RECT  39.144 71.123 40.464 71.148 ;
     RECT  39.144 71.148 40.416 71.171 ;
     RECT  39.096 71.171 40.416 71.248 ;
  END
END ot_qfd_su_align_group4
END LIBRARY
